<?xml version="1.0" encoding="utf-8" standalone="no"?>
<device schemaVersion="1.1" xmlns:xs="http://www.w3.org/2001/XMLSchema-instance" noNamespaceSchemaLocation="CMSIS-SVD.xsd">
  <vendor>PUYA Co.Ltd</vendor>
  <vendorID>PUYA</vendorID>
  <name>PY32F420xx</name>
  <series>ARMCM4</series>
  <version>1.2</version>
  <cpu>
    <name>CM4</name>
    <revision>r0p1</revision>
    <endian>little</endian>
    <mpuPresent>true</mpuPresent>
    <fpuPresent>true</fpuPresent>
    <nvicPrioBits>4</nvicPrioBits>
    <vendorSystickConfig>false</vendorSystickConfig>
  </cpu>
  <addressUnitBits>8</addressUnitBits>
  <width>32</width>
  <size>32</size>
  <access>read-write</access>
  <resetValue>0x0</resetValue>
  <resetMask>0xFFFFFFFF</resetMask>
  <peripherals>
    <peripheral>
      <name>ADC1</name>
      <groupName>ADC</groupName>
      <baseAddress>0x40012400</baseAddress>
      <addressBlock>
        <offset>0x0</offset>
        <size>0x310</size>
        <usage>registers</usage>
      </addressBlock>
      <interrupt>
        <name>ADC1</name>
        <description>ADC1 global Interrupt</description>
        <value>18</value>
      </interrupt>
      <registers>
        <register>
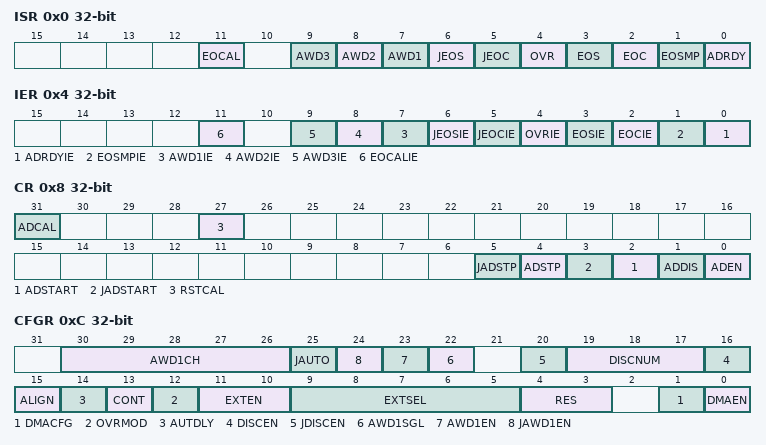
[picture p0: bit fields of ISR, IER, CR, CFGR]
          <name>ISR</name>
          <addressOffset>0x0</addressOffset>
          <fields>
            <field>
              <name>ADRDY</name>
              <bitRange>[0:0]</bitRange>
            </field>
            <field>
              <name>EOSMP</name>
              <bitRange>[1:1]</bitRange>
            </field>
            <field>
              <name>EOC</name>
              <bitRange>[2:2]</bitRange>
            </field>
            <field>
              <name>EOS</name>
              <bitRange>[3:3]</bitRange>
            </field>
            <field>
              <name>OVR</name>
              <bitRange>[4:4]</bitRange>
            </field>
            <field>
              <name>JEOC</name>
              <bitRange>[5:5]</bitRange>
            </field>
            <field>
              <name>JEOS</name>
              <bitRange>[6:6]</bitRange>
            </field>
            <field>
              <name>AWD1</name>
              <bitRange>[7:7]</bitRange>
            </field>
            <field>
              <name>AWD2</name>
              <bitRange>[8:8]</bitRange>
            </field>
            <field>
              <name>AWD3</name>
              <bitRange>[9:9]</bitRange>
            </field>
            <field>
              <name>EOCAL</name>
              <bitRange>[11:11]</bitRange>
            </field>
          </fields>
        </register>
        <register>
          <name>IER</name>
          <addressOffset>0x4</addressOffset>
          <fields>
            <field>
              <name>ADRDYIE</name>
              <bitRange>[0:0]</bitRange>
            </field>
            <field>
              <name>EOSMPIE</name>
              <bitRange>[1:1]</bitRange>
            </field>
            <field>
              <name>EOCIE</name>
              <bitRange>[2:2]</bitRange>
            </field>
            <field>
              <name>EOSIE</name>
              <bitRange>[3:3]</bitRange>
            </field>
            <field>
              <name>OVRIE</name>
              <bitRange>[4:4]</bitRange>
            </field>
            <field>
              <name>JEOCIE</name>
              <bitRange>[5:5]</bitRange>
            </field>
            <field>
              <name>JEOSIE</name>
              <bitRange>[6:6]</bitRange>
            </field>
            <field>
              <name>AWD1IE</name>
              <bitRange>[7:7]</bitRange>
            </field>
            <field>
              <name>AWD2IE</name>
              <bitRange>[8:8]</bitRange>
            </field>
            <field>
              <name>AWD3IE</name>
              <bitRange>[9:9]</bitRange>
            </field>
            <field>
              <name>EOCALIE</name>
              <bitRange>[11:11]</bitRange>
            </field>
          </fields>
        </register>
        <register>
          <name>CR</name>
          <addressOffset>0x8</addressOffset>
          <fields>
            <field>
              <name>ADEN</name>
              <bitRange>[0:0]</bitRange>
            </field>
            <field>
              <name>ADDIS</name>
              <bitRange>[1:1]</bitRange>
            </field>
            <field>
              <name>ADSTART</name>
              <bitRange>[2:2]</bitRange>
            </field>
            <field>
              <name>JADSTART</name>
              <bitRange>[3:3]</bitRange>
            </field>
            <field>
              <name>ADSTP</name>
              <bitRange>[4:4]</bitRange>
            </field>
            <field>
              <name>JADSTP</name>
              <bitRange>[5:5]</bitRange>
            </field>
            <field>
              <name>RSTCAL</name>
              <bitRange>[27:27]</bitRange>
            </field>
            <field>
              <name>ADCAL</name>
              <bitRange>[31:31]</bitRange>
            </field>
          </fields>
        </register>
        <register>
          <name>CFGR</name>
          <addressOffset>0xC</addressOffset>
          <fields>
            <field>
              <name>DMAEN</name>
              <bitRange>[0:0]</bitRange>
            </field>
            <field>
              <name>DMACFG</name>
              <bitRange>[1:1]</bitRange>
            </field>
            <field>
              <name>RES</name>
              <bitRange>[4:3]</bitRange>
            </field>
            <field>
              <name>EXTSEL</name>
              <bitRange>[9:5]</bitRange>
            </field>
            <field>
              <name>EXTEN</name>
              <bitRange>[11:10]</bitRange>
            </field>
            <field>
              <name>OVRMOD</name>
              <bitRange>[12:12]</bitRange>
            </field>
            <field>
              <name>CONT</name>
              <bitRange>[13:13]</bitRange>
            </field>
            <field>
              <name>AUTDLY</name>
              <bitRange>[14:14]</bitRange>
            </field>
            <field>
              <name>ALIGN</name>
              <bitRange>[15:15]</bitRange>
            </field>
            <field>
              <name>DISCEN</name>
              <bitRange>[16:16]</bitRange>
            </field>
            <field>
              <name>DISCNUM</name>
              <bitRange>[19:17]</bitRange>
            </field>
            <field>
              <name>JDISCEN</name>
              <bitRange>[20:20]</bitRange>
            </field>
            <field>
              <name>AWD1SGL</name>
              <bitRange>[22:22]</bitRange>
            </field>
            <field>
              <name>AWD1EN</name>
              <bitRange>[23:23]</bitRange>
            </field>
            <field>
              <name>JAWD1EN</name>
              <bitRange>[24:24]</bitRange>
            </field>
            <field>
              <name>JAUTO</name>
              <bitRange>[25:25]</bitRange>
            </field>
            <field>
              <name>AWD1CH</name>
              <bitRange>[30:26]</bitRange>
            </field>
          </fields>
        </register>
        <register>
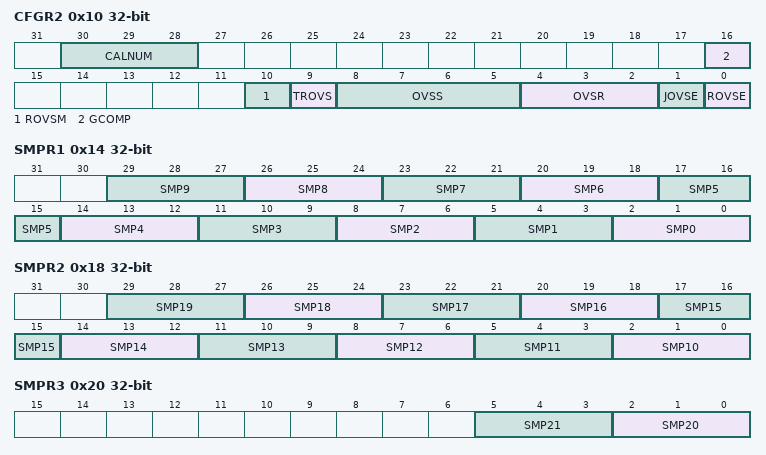
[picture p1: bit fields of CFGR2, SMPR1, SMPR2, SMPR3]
          <name>CFGR2</name>
          <addressOffset>0x10</addressOffset>
          <fields>
            <field>
              <name>ROVSE</name>
              <bitRange>[0:0]</bitRange>
            </field>
            <field>
              <name>JOVSE</name>
              <bitRange>[1:1]</bitRange>
            </field>
            <field>
              <name>OVSR</name>
              <bitRange>[4:2]</bitRange>
            </field>
            <field>
              <name>OVSS</name>
              <bitRange>[8:5]</bitRange>
            </field>
            <field>
              <name>TROVS</name>
              <bitRange>[9:9]</bitRange>
            </field>
            <field>
              <name>ROVSM</name>
              <bitRange>[10:10]</bitRange>
            </field>
            <field>
              <name>GCOMP</name>
              <bitRange>[16:16]</bitRange>
            </field>
            <field>
              <name>CALNUM</name>
              <bitRange>[30:28]</bitRange>
            </field>
          </fields>
        </register>
        <register>
          <name>SMPR1</name>
          <addressOffset>0x14</addressOffset>
          <fields>
            <field>
              <name>SMP0</name>
              <bitRange>[2:0]</bitRange>
            </field>
            <field>
              <name>SMP1</name>
              <bitRange>[5:3]</bitRange>
            </field>
            <field>
              <name>SMP2</name>
              <bitRange>[8:6]</bitRange>
            </field>
            <field>
              <name>SMP3</name>
              <bitRange>[11:9]</bitRange>
            </field>
            <field>
              <name>SMP4</name>
              <bitRange>[14:12]</bitRange>
            </field>
            <field>
              <name>SMP5</name>
              <bitRange>[17:15]</bitRange>
            </field>
            <field>
              <name>SMP6</name>
              <bitRange>[20:18]</bitRange>
            </field>
            <field>
              <name>SMP7</name>
              <bitRange>[23:21]</bitRange>
            </field>
            <field>
              <name>SMP8</name>
              <bitRange>[26:24]</bitRange>
            </field>
            <field>
              <name>SMP9</name>
              <bitRange>[29:27]</bitRange>
            </field>
          </fields>
        </register>
        <register>
          <name>SMPR2</name>
          <addressOffset>0x18</addressOffset>
          <fields>
            <field>
              <name>SMP10</name>
              <bitRange>[2:0]</bitRange>
            </field>
            <field>
              <name>SMP11</name>
              <bitRange>[5:3]</bitRange>
            </field>
            <field>
              <name>SMP12</name>
              <bitRange>[8:6]</bitRange>
            </field>
            <field>
              <name>SMP13</name>
              <bitRange>[11:9]</bitRange>
            </field>
            <field>
              <name>SMP14</name>
              <bitRange>[14:12]</bitRange>
            </field>
            <field>
              <name>SMP15</name>
              <bitRange>[17:15]</bitRange>
            </field>
            <field>
              <name>SMP16</name>
              <bitRange>[20:18]</bitRange>
            </field>
            <field>
              <name>SMP17</name>
              <bitRange>[23:21]</bitRange>
            </field>
            <field>
              <name>SMP18</name>
              <bitRange>[26:24]</bitRange>
            </field>
            <field>
              <name>SMP19</name>
              <bitRange>[29:27]</bitRange>
            </field>
          </fields>
        </register>
        <register>
          <name>SMPR3</name>
          <addressOffset>0x20</addressOffset>
          <fields>
            <field>
              <name>SMP20</name>
              <bitRange>[2:0]</bitRange>
            </field>
            <field>
              <name>SMP21</name>
              <bitRange>[5:3]</bitRange>
            </field>
          </fields>
        </register>
        <register>
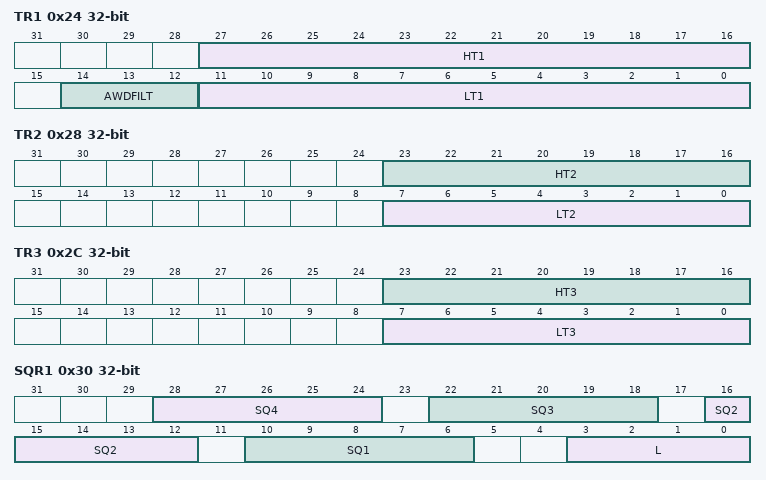
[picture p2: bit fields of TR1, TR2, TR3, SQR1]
          <name>TR1</name>
          <addressOffset>0x24</addressOffset>
          <fields>
            <field>
              <name>LT1</name>
              <bitRange>[11:0]</bitRange>
            </field>
            <field>
              <name>AWDFILT</name>
              <bitRange>[14:12]</bitRange>
            </field>
            <field>
              <name>HT1</name>
              <bitRange>[27:16]</bitRange>
            </field>
          </fields>
        </register>
        <register>
          <name>TR2</name>
          <addressOffset>0x28</addressOffset>
          <fields>
            <field>
              <name>LT2</name>
              <bitRange>[7:0]</bitRange>
            </field>
            <field>
              <name>HT2</name>
              <bitRange>[23:16]</bitRange>
            </field>
          </fields>
        </register>
        <register>
          <name>TR3</name>
          <addressOffset>0x2C</addressOffset>
          <fields>
            <field>
              <name>LT3</name>
              <bitRange>[7:0]</bitRange>
            </field>
            <field>
              <name>HT3</name>
              <bitRange>[23:16]</bitRange>
            </field>
          </fields>
        </register>
        <register>
          <name>SQR1</name>
          <addressOffset>0x30</addressOffset>
          <fields>
            <field>
              <name>L</name>
              <bitRange>[3:0]</bitRange>
            </field>
            <field>
              <name>SQ1</name>
              <bitRange>[10:6]</bitRange>
            </field>
            <field>
              <name>SQ2</name>
              <bitRange>[16:12]</bitRange>
            </field>
            <field>
              <name>SQ3</name>
              <bitRange>[22:18]</bitRange>
            </field>
            <field>
              <name>SQ4</name>
              <bitRange>[28:24]</bitRange>
            </field>
          </fields>
        </register>
        <register>
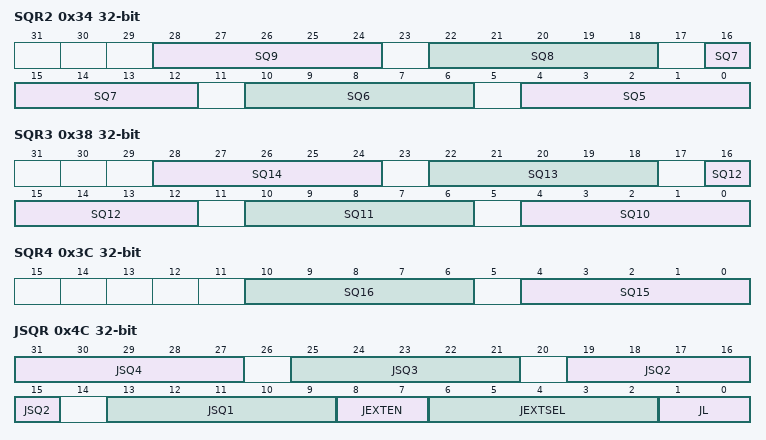
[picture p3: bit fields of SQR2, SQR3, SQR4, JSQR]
          <name>SQR2</name>
          <addressOffset>0x34</addressOffset>
          <fields>
            <field>
              <name>SQ5</name>
              <bitRange>[4:0]</bitRange>
            </field>
            <field>
              <name>SQ6</name>
              <bitRange>[10:6]</bitRange>
            </field>
            <field>
              <name>SQ7</name>
              <bitRange>[16:12]</bitRange>
            </field>
            <field>
              <name>SQ8</name>
              <bitRange>[22:18]</bitRange>
            </field>
            <field>
              <name>SQ9</name>
              <bitRange>[28:24]</bitRange>
            </field>
          </fields>
        </register>
        <register>
          <name>SQR3</name>
          <addressOffset>0x38</addressOffset>
          <fields>
            <field>
              <name>SQ10</name>
              <bitRange>[4:0]</bitRange>
            </field>
            <field>
              <name>SQ11</name>
              <bitRange>[10:6]</bitRange>
            </field>
            <field>
              <name>SQ12</name>
              <bitRange>[16:12]</bitRange>
            </field>
            <field>
              <name>SQ13</name>
              <bitRange>[22:18]</bitRange>
            </field>
            <field>
              <name>SQ14</name>
              <bitRange>[28:24]</bitRange>
            </field>
          </fields>
        </register>
        <register>
          <name>SQR4</name>
          <addressOffset>0x3C</addressOffset>
          <fields>
            <field>
              <name>SQ15</name>
              <bitRange>[4:0]</bitRange>
            </field>
            <field>
              <name>SQ16</name>
              <bitRange>[10:6]</bitRange>
            </field>
          </fields>
        </register>
        <register>
          <name>DR</name>
          <addressOffset>0x40</addressOffset>
          <fields>
            <field>
              <name>RDATA</name>
              <bitRange>[15:0]</bitRange>
              <access>read-only</access>
            </field>
          </fields>
        </register>
        <register>
          <name>JSQR</name>
          <addressOffset>0x4C</addressOffset>
          <fields>
            <field>
              <name>JL</name>
              <bitRange>[1:0]</bitRange>
            </field>
            <field>
              <name>JEXTSEL</name>
              <bitRange>[6:2]</bitRange>
            </field>
            <field>
              <name>JEXTEN</name>
              <bitRange>[8:7]</bitRange>
            </field>
            <field>
              <name>JSQ1</name>
              <bitRange>[13:9]</bitRange>
            </field>
            <field>
              <name>JSQ2</name>
              <bitRange>[19:15]</bitRange>
            </field>
            <field>
              <name>JSQ3</name>
              <bitRange>[25:21]</bitRange>
            </field>
            <field>
              <name>JSQ4</name>
              <bitRange>[31:27]</bitRange>
            </field>
          </fields>
        </register>
        <register>
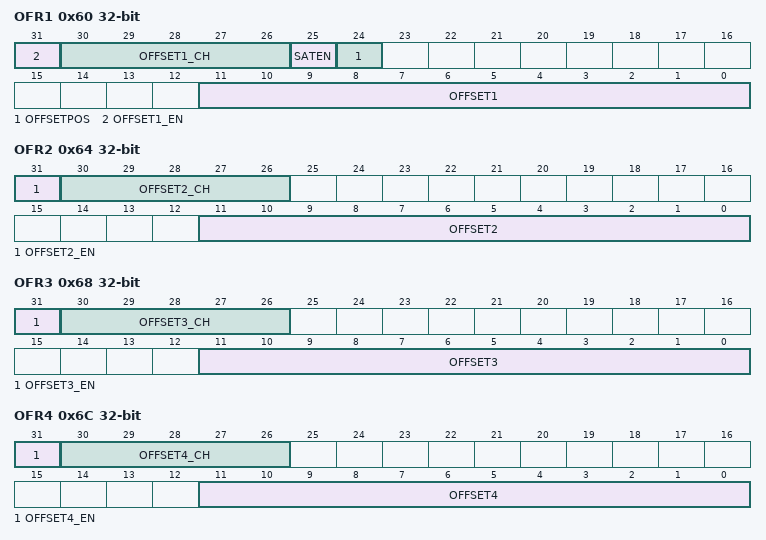
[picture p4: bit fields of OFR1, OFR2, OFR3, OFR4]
          <name>OFR1</name>
          <addressOffset>0x60</addressOffset>
          <fields>
            <field>
              <name>OFFSET1</name>
              <bitRange>[11:0]</bitRange>
            </field>
            <field>
              <name>OFFSETPOS</name>
              <bitRange>[24:24]</bitRange>
            </field>
            <field>
              <name>SATEN</name>
              <bitRange>[25:25]</bitRange>
            </field>
            <field>
              <name>OFFSET1_CH</name>
              <bitRange>[30:26]</bitRange>
            </field>
            <field>
              <name>OFFSET1_EN</name>
              <bitRange>[31:31]</bitRange>
            </field>
          </fields>
        </register>
        <register>
          <name>OFR2</name>
          <addressOffset>0x64</addressOffset>
          <fields>
            <field>
              <name>OFFSET2</name>
              <bitRange>[11:0]</bitRange>
            </field>
            <field>
              <name>OFFSET2_CH</name>
              <bitRange>[30:26]</bitRange>
            </field>
            <field>
              <name>OFFSET2_EN</name>
              <bitRange>[31:31]</bitRange>
            </field>
          </fields>
        </register>
        <register>
          <name>OFR3</name>
          <addressOffset>0x68</addressOffset>
          <fields>
            <field>
              <name>OFFSET3</name>
              <bitRange>[11:0]</bitRange>
            </field>
            <field>
              <name>OFFSET3_CH</name>
              <bitRange>[30:26]</bitRange>
            </field>
            <field>
              <name>OFFSET3_EN</name>
              <bitRange>[31:31]</bitRange>
            </field>
          </fields>
        </register>
        <register>
          <name>OFR4</name>
          <addressOffset>0x6C</addressOffset>
          <fields>
            <field>
              <name>OFFSET4</name>
              <bitRange>[11:0]</bitRange>
            </field>
            <field>
              <name>OFFSET4_CH</name>
              <bitRange>[30:26]</bitRange>
            </field>
            <field>
              <name>OFFSET4_EN</name>
              <bitRange>[31:31]</bitRange>
            </field>
          </fields>
        </register>
        <register>
          <name>JDR1</name>
          <addressOffset>0x80</addressOffset>
          <fields>
            <field>
              <name>JDATA</name>
              <bitRange>[15:0]</bitRange>
              <access>read-only</access>
            </field>
          </fields>
        </register>
        <register>
          <name>JDR2</name>
          <addressOffset>0x84</addressOffset>
          <fields>
            <field>
              <name>JDATA</name>
              <bitRange>[15:0]</bitRange>
              <access>read-only</access>
            </field>
          </fields>
        </register>
        <register>
          <name>JDR3</name>
          <addressOffset>0x88</addressOffset>
          <fields>
            <field>
              <name>JDATA</name>
              <bitRange>[15:0]</bitRange>
              <access>read-only</access>
            </field>
          </fields>
        </register>
        <register>
          <name>JDR4</name>
          <addressOffset>0x8C</addressOffset>
          <fields>
            <field>
              <name>JDATA</name>
              <bitRange>[15:0]</bitRange>
              <access>read-only</access>
            </field>
          </fields>
        </register>
        <register>
          <name>AWD2CR</name>
          <addressOffset>0xA0</addressOffset>
          <fields>
            <field>
              <name>AWD2CH</name>
              <bitRange>[21:0]</bitRange>
            </field>
          </fields>
        </register>
        <register>
          <name>AWD3CR</name>
          <addressOffset>0xA4</addressOffset>
          <fields>
            <field>
              <name>AWD3CH</name>
              <bitRange>[21:0]</bitRange>
            </field>
          </fields>
        </register>
        <register>
          <name>DIFSEL</name>
          <addressOffset>0xB0</addressOffset>
          <fields>
            <field>
              <name>DIFSEL</name>
              <bitRange>[21:0]</bitRange>
            </field>
          </fields>
        </register>
        <register>
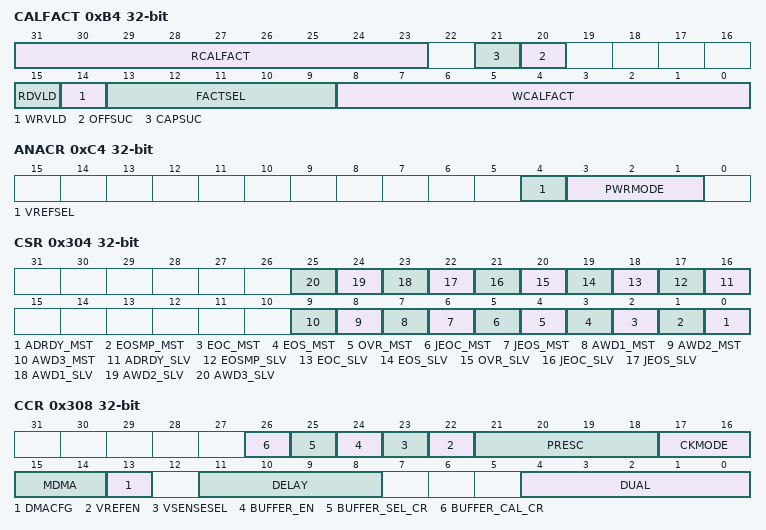
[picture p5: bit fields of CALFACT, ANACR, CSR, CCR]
          <name>CALFACT</name>
          <addressOffset>0xB4</addressOffset>
          <fields>
            <field>
              <name>WCALFACT</name>
              <bitRange>[8:0]</bitRange>
            </field>
            <field>
              <name>FACTSEL</name>
              <bitRange>[13:9]</bitRange>
            </field>
            <field>
              <name>WRVLD</name>
              <bitRange>[14:14]</bitRange>
            </field>
            <field>
              <name>RDVLD</name>
              <bitRange>[15:15]</bitRange>
            </field>
            <field>
              <name>OFFSUC</name>
              <bitRange>[20:20]</bitRange>
            </field>
            <field>
              <name>CAPSUC</name>
              <bitRange>[21:21]</bitRange>
            </field>
            <field>
              <name>RCALFACT</name>
              <bitRange>[31:23]</bitRange>
              <access>read-only</access>
            </field>
          </fields>
        </register>
        <register>
          <name>GCOMP</name>
          <addressOffset>0xC0</addressOffset>
          <fields>
            <field>
              <name>GCOMPCOEFF</name>
              <bitRange>[13:0]</bitRange>
            </field>
          </fields>
        </register>
        <register>
          <name>ANACR</name>
          <addressOffset>0xC4</addressOffset>
          <fields>
            <field>
              <name>PWRMODE</name>
              <bitRange>[3:1]</bitRange>
            </field>
            <field>
              <name>VREFSEL</name>
              <bitRange>[4:4]</bitRange>
            </field>
          </fields>
        </register>
        <register>
          <name>CSR</name>
          <addressOffset>0x304</addressOffset>
          <fields>
            <field>
              <name>ADRDY_MST</name>
              <bitRange>[0:0]</bitRange>
              <access>read-only</access>
            </field>
            <field>
              <name>EOSMP_MST</name>
              <bitRange>[1:1]</bitRange>
              <access>read-only</access>
            </field>
            <field>
              <name>EOC_MST</name>
              <bitRange>[2:2]</bitRange>
              <access>read-only</access>
            </field>
            <field>
              <name>EOS_MST</name>
              <bitRange>[3:3]</bitRange>
              <access>read-only</access>
            </field>
            <field>
              <name>OVR_MST</name>
              <bitRange>[4:4]</bitRange>
              <access>read-only</access>
            </field>
            <field>
              <name>JEOC_MST</name>
              <bitRange>[5:5]</bitRange>
              <access>read-only</access>
            </field>
            <field>
              <name>JEOS_MST</name>
              <bitRange>[6:6]</bitRange>
              <access>read-only</access>
            </field>
            <field>
              <name>AWD1_MST</name>
              <bitRange>[7:7]</bitRange>
              <access>read-only</access>
            </field>
            <field>
              <name>AWD2_MST</name>
              <bitRange>[8:8]</bitRange>
              <access>read-only</access>
            </field>
            <field>
              <name>AWD3_MST</name>
              <bitRange>[9:9]</bitRange>
              <access>read-only</access>
            </field>
            <field>
              <name>ADRDY_SLV</name>
              <bitRange>[16:16]</bitRange>
              <access>read-only</access>
            </field>
            <field>
              <name>EOSMP_SLV</name>
              <bitRange>[17:17]</bitRange>
              <access>read-only</access>
            </field>
            <field>
              <name>EOC_SLV</name>
              <bitRange>[18:18]</bitRange>
              <access>read-only</access>
            </field>
            <field>
              <name>EOS_SLV</name>
              <bitRange>[19:19]</bitRange>
              <access>read-only</access>
            </field>
            <field>
              <name>OVR_SLV</name>
              <bitRange>[20:20]</bitRange>
              <access>read-only</access>
            </field>
            <field>
              <name>JEOC_SLV</name>
              <bitRange>[21:21]</bitRange>
              <access>read-only</access>
            </field>
            <field>
              <name>JEOS_SLV</name>
              <bitRange>[22:22]</bitRange>
              <access>read-only</access>
            </field>
            <field>
              <name>AWD1_SLV</name>
              <bitRange>[23:23]</bitRange>
              <access>read-only</access>
            </field>
            <field>
              <name>AWD2_SLV</name>
              <bitRange>[24:24]</bitRange>
              <access>read-only</access>
            </field>
            <field>
              <name>AWD3_SLV</name>
              <bitRange>[25:25]</bitRange>
              <access>read-only</access>
            </field>
          </fields>
        </register>
        <register>
          <name>CCR</name>
          <addressOffset>0x308</addressOffset>
          <fields>
            <field>
              <name>DUAL</name>
              <bitRange>[4:0]</bitRange>
            </field>
            <field>
              <name>DELAY</name>
              <bitRange>[11:8]</bitRange>
            </field>
            <field>
              <name>DMACFG</name>
              <bitRange>[13:13]</bitRange>
            </field>
            <field>
              <name>MDMA</name>
              <bitRange>[15:14]</bitRange>
            </field>
            <field>
              <name>CKMODE</name>
              <bitRange>[17:16]</bitRange>
            </field>
            <field>
              <name>PRESC</name>
              <bitRange>[21:18]</bitRange>
            </field>
            <field>
              <name>VREFEN</name>
              <bitRange>[22:22]</bitRange>
            </field>
            <field>
              <name>VSENSESEL</name>
              <bitRange>[23:23]</bitRange>
            </field>
            <field>
              <name>BUFFER_EN</name>
              <bitRange>[24:24]</bitRange>
            </field>
            <field>
              <name>BUFFER_SEL_CR</name>
              <bitRange>[25:25]</bitRange>
            </field>
            <field>
              <name>BUFFER_CAL_CR</name>
              <bitRange>[26:26]</bitRange>
            </field>
          </fields>
        </register>
        <register>
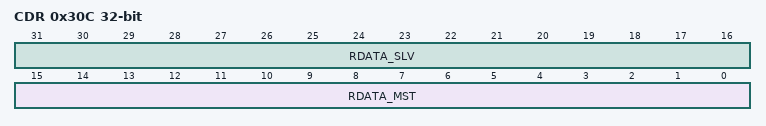
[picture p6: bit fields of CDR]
          <name>CDR</name>
          <addressOffset>0x30C</addressOffset>
          <fields>
            <field>
              <name>RDATA_MST</name>
              <bitRange>[15:0]</bitRange>
              <access>read-only</access>
            </field>
            <field>
              <name>RDATA_SLV</name>
              <bitRange>[31:16]</bitRange>
              <access>read-only</access>
            </field>
          </fields>
        </register>
      </registers>
    </peripheral>
    <peripheral derivedFrom="ADC1">
      <name>ADC2</name>
      <baseAddress>0x40012800</baseAddress>
      <interrupt>
        <name>ADC2</name>
        <description>ADC2 global Interrupt</description>
        <value>19</value>
      </interrupt>
    </peripheral>
    <peripheral>
      <name>COMP1</name>
      <groupName>COMP</groupName>
      <baseAddress>0x40016C00</baseAddress>
      <addressBlock>
        <offset>0x0</offset>
        <size>0x10</size>
        <usage>registers</usage>
      </addressBlock>
      <interrupt>
        <name>COMP1</name>
        <description>COMP1 global Interrupt</description>
        <value>47</value>
      </interrupt>
      <registers>
        <register>
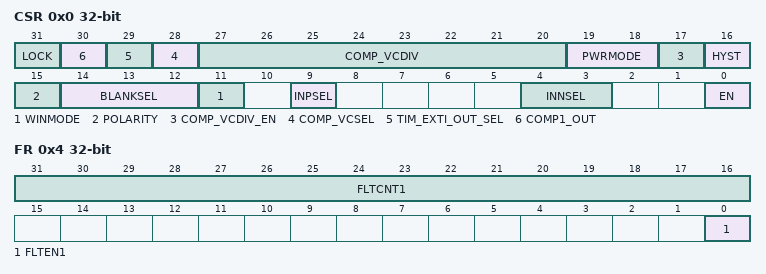
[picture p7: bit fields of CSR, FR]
          <name>CSR</name>
          <addressOffset>0x0</addressOffset>
          <fields>
            <field>
              <name>EN</name>
              <bitRange>[0:0]</bitRange>
            </field>
            <field>
              <name>INNSEL</name>
              <bitRange>[4:3]</bitRange>
            </field>
            <field>
              <name>INPSEL</name>
              <bitRange>[9:9]</bitRange>
            </field>
            <field>
              <name>WINMODE</name>
              <bitRange>[11:11]</bitRange>
            </field>
            <field>
              <name>BLANKSEL</name>
              <bitRange>[14:12]</bitRange>
            </field>
            <field>
              <name>POLARITY</name>
              <bitRange>[15:15]</bitRange>
            </field>
            <field>
              <name>HYST</name>
              <bitRange>[16:16]</bitRange>
            </field>
            <field>
              <name>COMP_VCDIV_EN</name>
              <bitRange>[17:17]</bitRange>
            </field>
            <field>
              <name>PWRMODE</name>
              <bitRange>[19:18]</bitRange>
            </field>
            <field>
              <name>COMP_VCDIV</name>
              <bitRange>[27:20]</bitRange>
            </field>
            <field>
              <name>COMP_VCSEL</name>
              <bitRange>[28:28]</bitRange>
            </field>
            <field>
              <name>TIM_EXTI_OUT_SEL</name>
              <bitRange>[29:29]</bitRange>
            </field>
            <field>
              <name>COMP1_OUT</name>
              <bitRange>[30:30]</bitRange>
              <access>read-only</access>
            </field>
            <field>
              <name>LOCK</name>
              <bitRange>[31:31]</bitRange>
            </field>
          </fields>
        </register>
        <register>
          <name>FR</name>
          <addressOffset>0x4</addressOffset>
          <fields>
            <field>
              <name>FLTEN1</name>
              <bitRange>[0:0]</bitRange>
            </field>
            <field>
              <name>FLTCNT1</name>
              <bitRange>[31:16]</bitRange>
            </field>
          </fields>
        </register>
      </registers>
    </peripheral>
    <peripheral derivedFrom="COMP1">
      <name>COMP2</name>
      <baseAddress>0x40016C10</baseAddress>
      <interrupt>
        <name>COMP2</name>
        <description>COMP2 global Interrupt</description>
        <value>48</value>
      </interrupt>
    </peripheral>
    <peripheral derivedFrom="COMP1">
      <name>COMP3</name>
      <baseAddress>0x40016C20</baseAddress>
      <interrupt>
        <name>COMP3</name>
        <description>COMP3 global Interrupt</description>
        <value>49</value>
      </interrupt>
    </peripheral>
    <peripheral derivedFrom="COMP1">
      <name>COMP4</name>
      <baseAddress>0x40016C30</baseAddress>
      <interrupt>
        <name>COMP4</name>
        <description>COMP4 global Interrupt</description>
        <value>50</value>
      </interrupt>
    </peripheral>
    <peripheral>
      <name>CRC</name>
      <baseAddress>0x40023000</baseAddress>
      <addressBlock>
        <offset>0x0</offset>
        <size>0x10</size>
        <usage>registers</usage>
      </addressBlock>
      <registers>
        <register>
          <name>DR</name>
          <addressOffset>0x0</addressOffset>
          <fields>
            <field>
              <name>DR</name>
              <description>CRC data</description>
              <bitRange>[31:0]</bitRange>
            </field>
          </fields>
        </register>
        <register>
          <name>IDR</name>
          <addressOffset>0x4</addressOffset>
          <fields>
            <field>
              <name>IDR</name>
              <description>CRC independent data</description>
              <bitRange>[7:0]</bitRange>
            </field>
          </fields>
        </register>
        <register>
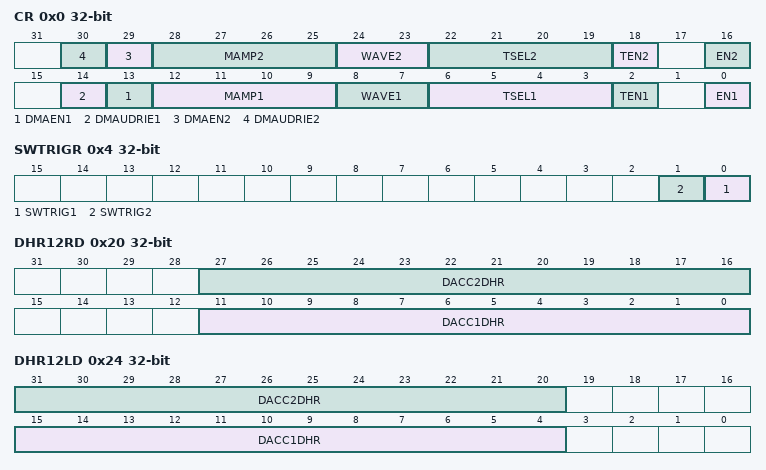
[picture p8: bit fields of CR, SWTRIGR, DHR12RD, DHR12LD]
          <name>CR</name>
          <addressOffset>0x8</addressOffset>
          <fields>
            <field>
              <name>RESET</name>
              <description>CRC software reset</description>
              <bitRange>[0:0]</bitRange>
            </field>
          </fields>
        </register>
      </registers>
    </peripheral>
    <peripheral>
      <name>DAC</name>
      <baseAddress>0x40007400</baseAddress>
      <addressBlock>
        <offset>0x0</offset>
        <size>0x70</size>
        <usage>registers</usage>
      </addressBlock>
      <interrupt>
        <name>DAC</name>
        <description>DAC global Interrupt</description>
        <value>20</value>
      </interrupt>
      <registers>
        <register>
          <name>CR</name>
          <addressOffset>0x0</addressOffset>
          <fields>
            <field>
              <name>EN1</name>
              <bitRange>[0:0]</bitRange>
            </field>
            <field>
              <name>TEN1</name>
              <bitRange>[2:2]</bitRange>
            </field>
            <field>
              <name>TSEL1</name>
              <bitRange>[6:3]</bitRange>
            </field>
            <field>
              <name>WAVE1</name>
              <bitRange>[8:7]</bitRange>
            </field>
            <field>
              <name>MAMP1</name>
              <bitRange>[12:9]</bitRange>
            </field>
            <field>
              <name>DMAEN1</name>
              <bitRange>[13:13]</bitRange>
            </field>
            <field>
              <name>DMAUDRIE1</name>
              <bitRange>[14:14]</bitRange>
            </field>
            <field>
              <name>EN2</name>
              <bitRange>[16:16]</bitRange>
            </field>
            <field>
              <name>TEN2</name>
              <bitRange>[18:18]</bitRange>
            </field>
            <field>
              <name>TSEL2</name>
              <bitRange>[22:19]</bitRange>
            </field>
            <field>
              <name>WAVE2</name>
              <bitRange>[24:23]</bitRange>
            </field>
            <field>
              <name>MAMP2</name>
              <bitRange>[28:25]</bitRange>
            </field>
            <field>
              <name>DMAEN2</name>
              <bitRange>[29:29]</bitRange>
            </field>
            <field>
              <name>DMAUDRIE2</name>
              <bitRange>[30:30]</bitRange>
            </field>
          </fields>
        </register>
        <register>
          <name>SWTRIGR</name>
          <addressOffset>0x4</addressOffset>
          <fields>
            <field>
              <name>SWTRIG1</name>
              <bitRange>[0:0]</bitRange>
              <access>write-only</access>
            </field>
            <field>
              <name>SWTRIG2</name>
              <bitRange>[1:1]</bitRange>
              <access>write-only</access>
            </field>
          </fields>
        </register>
        <register>
          <name>DHR12R1</name>
          <addressOffset>0x8</addressOffset>
          <fields>
            <field>
              <name>DACC1DHR</name>
              <bitRange>[11:0]</bitRange>
            </field>
          </fields>
        </register>
        <register>
          <name>DHR12L1</name>
          <addressOffset>0xC</addressOffset>
          <fields>
            <field>
              <name>DACC1DHR</name>
              <bitRange>[15:4]</bitRange>
            </field>
          </fields>
        </register>
        <register>
          <name>DHR8R1</name>
          <addressOffset>0x10</addressOffset>
          <fields>
            <field>
              <name>DACC1DHR</name>
              <bitRange>[7:0]</bitRange>
            </field>
          </fields>
        </register>
        <register>
          <name>DHR12R2</name>
          <addressOffset>0x14</addressOffset>
          <fields>
            <field>
              <name>DACC2DHR</name>
              <bitRange>[11:0]</bitRange>
            </field>
          </fields>
        </register>
        <register>
          <name>DHR12L2</name>
          <addressOffset>0x18</addressOffset>
          <fields>
            <field>
              <name>DACC2DHR</name>
              <bitRange>[15:4]</bitRange>
            </field>
          </fields>
        </register>
        <register>
          <name>DHR8R2</name>
          <addressOffset>0x1C</addressOffset>
          <fields>
            <field>
              <name>DACC2DHR</name>
              <bitRange>[7:0]</bitRange>
            </field>
          </fields>
        </register>
        <register>
          <name>DHR12RD</name>
          <addressOffset>0x20</addressOffset>
          <fields>
            <field>
              <name>DACC1DHR</name>
              <bitRange>[11:0]</bitRange>
            </field>
            <field>
              <name>DACC2DHR</name>
              <bitRange>[27:16]</bitRange>
            </field>
          </fields>
        </register>
        <register>
          <name>DHR12LD</name>
          <addressOffset>0x24</addressOffset>
          <fields>
            <field>
              <name>DACC1DHR</name>
              <bitRange>[15:4]</bitRange>
            </field>
            <field>
              <name>DACC2DHR</name>
              <bitRange>[31:20]</bitRange>
            </field>
          </fields>
        </register>
        <register>
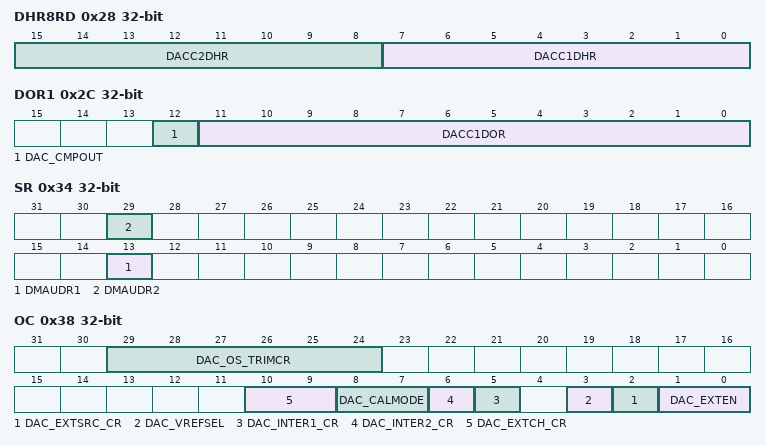
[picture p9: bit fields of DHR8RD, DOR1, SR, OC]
          <name>DHR8RD</name>
          <addressOffset>0x28</addressOffset>
          <fields>
            <field>
              <name>DACC1DHR</name>
              <bitRange>[7:0]</bitRange>
            </field>
            <field>
              <name>DACC2DHR</name>
              <bitRange>[15:8]</bitRange>
            </field>
          </fields>
        </register>
        <register>
          <name>DOR1</name>
          <addressOffset>0x2C</addressOffset>
          <fields>
            <field>
              <name>DACC1DOR</name>
              <bitRange>[11:0]</bitRange>
              <access>read-only</access>
            </field>
            <field>
              <name>DAC_CMPOUT</name>
              <bitRange>[12:12]</bitRange>
              <access>read-only</access>
            </field>
          </fields>
        </register>
        <register>
          <name>DOR2</name>
          <addressOffset>0x30</addressOffset>
          <fields>
            <field>
              <name>DACC2DOR</name>
              <bitRange>[11:0]</bitRange>
              <access>read-only</access>
            </field>
          </fields>
        </register>
        <register>
          <name>SR</name>
          <addressOffset>0x34</addressOffset>
          <fields>
            <field>
              <name>DMAUDR1</name>
              <bitRange>[13:13]</bitRange>
            </field>
            <field>
              <name>DMAUDR2</name>
              <bitRange>[29:29]</bitRange>
            </field>
          </fields>
        </register>
        <register>
          <name>OC</name>
          <addressOffset>0x38</addressOffset>
          <fields>
            <field>
              <name>DAC_EXTEN</name>
              <bitRange>[1:0]</bitRange>
            </field>
            <field>
              <name>DAC_EXTSRC_CR</name>
              <bitRange>[2:2]</bitRange>
            </field>
            <field>
              <name>DAC_VREFSEL</name>
              <bitRange>[3:3]</bitRange>
            </field>
            <field>
              <name>DAC_INTER1_CR</name>
              <bitRange>[5:5]</bitRange>
            </field>
            <field>
              <name>DAC_INTER2_CR</name>
              <bitRange>[6:6]</bitRange>
            </field>
            <field>
              <name>DAC_CALMODE</name>
              <bitRange>[8:7]</bitRange>
            </field>
            <field>
              <name>DAC_EXTCH_CR</name>
              <bitRange>[10:9]</bitRange>
            </field>
            <field>
              <name>DAC_OS_TRIMCR</name>
              <bitRange>[29:24]</bitRange>
            </field>
          </fields>
        </register>
        <register>
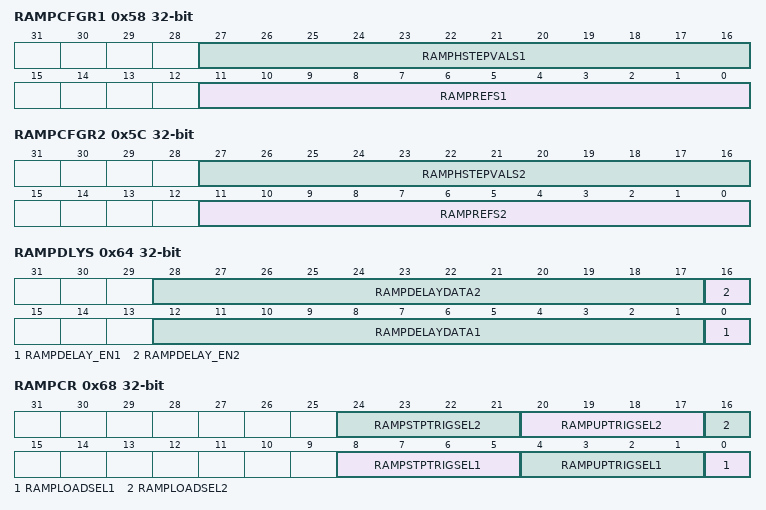
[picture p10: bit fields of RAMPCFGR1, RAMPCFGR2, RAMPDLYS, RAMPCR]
          <name>RAMPCFGR1</name>
          <addressOffset>0x58</addressOffset>
          <fields>
            <field>
              <name>RAMPREFS1</name>
              <bitRange>[11:0]</bitRange>
            </field>
            <field>
              <name>RAMPHSTEPVALS1</name>
              <bitRange>[27:16]</bitRange>
            </field>
          </fields>
        </register>
        <register>
          <name>RAMPCFGR2</name>
          <addressOffset>0x5C</addressOffset>
          <fields>
            <field>
              <name>RAMPREFS2</name>
              <bitRange>[11:0]</bitRange>
            </field>
            <field>
              <name>RAMPHSTEPVALS2</name>
              <bitRange>[27:16]</bitRange>
            </field>
          </fields>
        </register>
        <register>
          <name>RAMPDLYS</name>
          <addressOffset>0x64</addressOffset>
          <fields>
            <field>
              <name>RAMPDELAY_EN1</name>
              <bitRange>[0:0]</bitRange>
            </field>
            <field>
              <name>RAMPDELAYDATA1</name>
              <bitRange>[12:1]</bitRange>
            </field>
            <field>
              <name>RAMPDELAY_EN2</name>
              <bitRange>[16:16]</bitRange>
            </field>
            <field>
              <name>RAMPDELAYDATA2</name>
              <bitRange>[28:17]</bitRange>
            </field>
          </fields>
        </register>
        <register>
          <name>RAMPCR</name>
          <addressOffset>0x68</addressOffset>
          <fields>
            <field>
              <name>RAMPLOADSEL1</name>
              <bitRange>[0:0]</bitRange>
            </field>
            <field>
              <name>RAMPUPTRIGSEL1</name>
              <bitRange>[4:1]</bitRange>
            </field>
            <field>
              <name>RAMPSTPTRIGSEL1</name>
              <bitRange>[8:5]</bitRange>
            </field>
            <field>
              <name>RAMPLOADSEL2</name>
              <bitRange>[16:16]</bitRange>
            </field>
            <field>
              <name>RAMPUPTRIGSEL2</name>
              <bitRange>[20:17]</bitRange>
            </field>
            <field>
              <name>RAMPSTPTRIGSEL2</name>
              <bitRange>[24:21]</bitRange>
            </field>
          </fields>
        </register>
      </registers>
    </peripheral>
    <peripheral>
      <name>DBGMCU</name>
      <baseAddress>0xE0042000</baseAddress>
      <addressBlock>
        <offset>0x0</offset>
        <size>0x10</size>
        <usage>registers</usage>
      </addressBlock>
      <registers>
        <register>
          <name>IDCODE</name>
          <addressOffset>0x0</addressOffset>
          <fields>
            <field>
              <name>REV_ID</name>
              <bitRange>[31:0]</bitRange>
              <access>read-only</access>
            </field>
          </fields>
        </register>
        <register>
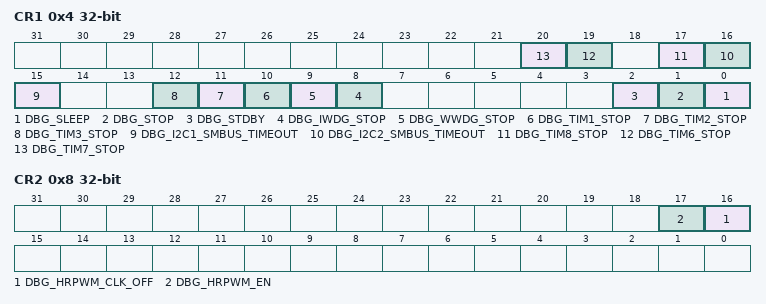
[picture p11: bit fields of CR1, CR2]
          <name>CR1</name>
          <addressOffset>0x4</addressOffset>
          <fields>
            <field>
              <name>DBG_SLEEP</name>
              <bitRange>[0:0]</bitRange>
            </field>
            <field>
              <name>DBG_STOP</name>
              <bitRange>[1:1]</bitRange>
            </field>
            <field>
              <name>DBG_STDBY</name>
              <bitRange>[2:2]</bitRange>
            </field>
            <field>
              <name>DBG_IWDG_STOP</name>
              <bitRange>[8:8]</bitRange>
            </field>
            <field>
              <name>DBG_WWDG_STOP</name>
              <bitRange>[9:9]</bitRange>
            </field>
            <field>
              <name>DBG_TIM1_STOP</name>
              <bitRange>[10:10]</bitRange>
            </field>
            <field>
              <name>DBG_TIM2_STOP</name>
              <bitRange>[11:11]</bitRange>
            </field>
            <field>
              <name>DBG_TIM3_STOP</name>
              <bitRange>[12:12]</bitRange>
            </field>
            <field>
              <name>DBG_I2C1_SMBUS_TIMEOUT</name>
              <bitRange>[15:15]</bitRange>
            </field>
            <field>
              <name>DBG_I2C2_SMBUS_TIMEOUT</name>
              <bitRange>[16:16]</bitRange>
            </field>
            <field>
              <name>DBG_TIM8_STOP</name>
              <bitRange>[17:17]</bitRange>
            </field>
            <field>
              <name>DBG_TIM6_STOP</name>
              <bitRange>[19:19]</bitRange>
            </field>
            <field>
              <name>DBG_TIM7_STOP</name>
              <bitRange>[20:20]</bitRange>
            </field>
          </fields>
        </register>
        <register>
          <name>CR2</name>
          <addressOffset>0x8</addressOffset>
          <fields>
            <field>
              <name>DBG_HRPWM_CLK_OFF</name>
              <bitRange>[16:16]</bitRange>
            </field>
            <field>
              <name>DBG_HRPWM_EN</name>
              <bitRange>[17:17]</bitRange>
            </field>
          </fields>
        </register>
      </registers>
    </peripheral>
    <peripheral>
      <name>DMA</name>
      <baseAddress>0x40020000</baseAddress>
      <addressBlock>
        <offset>0x0</offset>
        <size>0xB0</size>
        <usage>registers</usage>
      </addressBlock>
      <interrupt>
        <name>DMA1_MAP1</name>
        <description>DMA1_MAP1 global Interrupt</description>
        <value>13</value>
      </interrupt>
      <interrupt>
        <name>DMA1_MAP2</name>
        <description>DMA1_MAP2 global Interrupt</description>
        <value>14</value>
      </interrupt>
      <interrupt>
        <name>DMA1_MAP3</name>
        <description>DMA1_MAP3 global Interrupt</description>
        <value>15</value>
      </interrupt>
      <interrupt>
        <name>DMA1_MAP4</name>
        <description>DMA1_MAP4 global Interrupt</description>
        <value>16</value>
      </interrupt>
      <interrupt>
        <name>DMA1_MAP5</name>
        <description>DMA1_MAP5 global Interrupt</description>
        <value>17</value>
      </interrupt>
      <registers>
        <register>
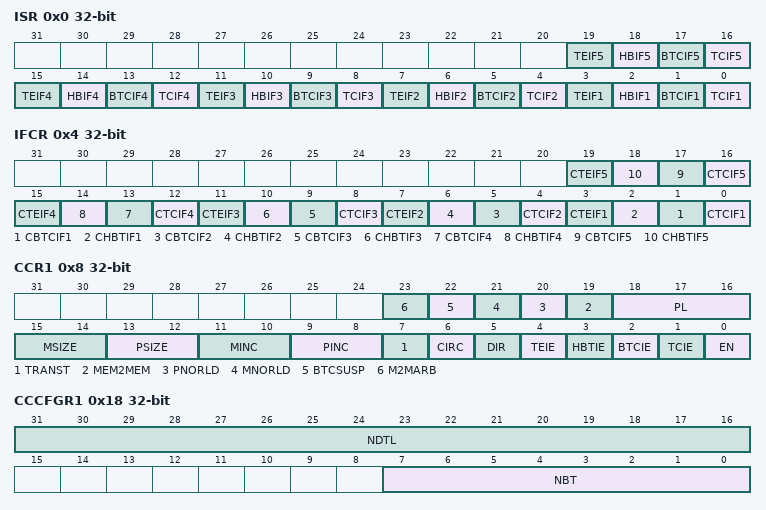
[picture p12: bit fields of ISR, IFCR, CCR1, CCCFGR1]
          <name>ISR</name>
          <addressOffset>0x0</addressOffset>
          <fields>
            <field>
              <name>TCIF1</name>
              <bitRange>[0:0]</bitRange>
              <access>read-only</access>
            </field>
            <field>
              <name>BTCIF1</name>
              <bitRange>[1:1]</bitRange>
              <access>read-only</access>
            </field>
            <field>
              <name>HBIF1</name>
              <bitRange>[2:2]</bitRange>
              <access>read-only</access>
            </field>
            <field>
              <name>TEIF1</name>
              <bitRange>[3:3]</bitRange>
              <access>read-only</access>
            </field>
            <field>
              <name>TCIF2</name>
              <bitRange>[4:4]</bitRange>
              <access>read-only</access>
            </field>
            <field>
              <name>BTCIF2</name>
              <bitRange>[5:5]</bitRange>
              <access>read-only</access>
            </field>
            <field>
              <name>HBIF2</name>
              <bitRange>[6:6]</bitRange>
              <access>read-only</access>
            </field>
            <field>
              <name>TEIF2</name>
              <bitRange>[7:7]</bitRange>
              <access>read-only</access>
            </field>
            <field>
              <name>TCIF3</name>
              <bitRange>[8:8]</bitRange>
              <access>read-only</access>
            </field>
            <field>
              <name>BTCIF3</name>
              <bitRange>[9:9]</bitRange>
              <access>read-only</access>
            </field>
            <field>
              <name>HBIF3</name>
              <bitRange>[10:10]</bitRange>
              <access>read-only</access>
            </field>
            <field>
              <name>TEIF3</name>
              <bitRange>[11:11]</bitRange>
              <access>read-only</access>
            </field>
            <field>
              <name>TCIF4</name>
              <bitRange>[12:12]</bitRange>
              <access>read-only</access>
            </field>
            <field>
              <name>BTCIF4</name>
              <bitRange>[13:13]</bitRange>
              <access>read-only</access>
            </field>
            <field>
              <name>HBIF4</name>
              <bitRange>[14:14]</bitRange>
              <access>read-only</access>
            </field>
            <field>
              <name>TEIF4</name>
              <bitRange>[15:15]</bitRange>
              <access>read-only</access>
            </field>
            <field>
              <name>TCIF5</name>
              <bitRange>[16:16]</bitRange>
              <access>read-only</access>
            </field>
            <field>
              <name>BTCIF5</name>
              <bitRange>[17:17]</bitRange>
              <access>read-only</access>
            </field>
            <field>
              <name>HBIF5</name>
              <bitRange>[18:18]</bitRange>
              <access>read-only</access>
            </field>
            <field>
              <name>TEIF5</name>
              <bitRange>[19:19]</bitRange>
              <access>read-only</access>
            </field>
          </fields>
        </register>
        <register>
          <name>IFCR</name>
          <addressOffset>0x4</addressOffset>
          <fields>
            <field>
              <name>CTCIF1</name>
              <bitRange>[0:0]</bitRange>
              <access>write-only</access>
            </field>
            <field>
              <name>CBTCIF1</name>
              <bitRange>[1:1]</bitRange>
              <access>write-only</access>
            </field>
            <field>
              <name>CHBTIF1</name>
              <bitRange>[2:2]</bitRange>
              <access>write-only</access>
            </field>
            <field>
              <name>CTEIF1</name>
              <bitRange>[3:3]</bitRange>
              <access>write-only</access>
            </field>
            <field>
              <name>CTCIF2</name>
              <bitRange>[4:4]</bitRange>
              <access>write-only</access>
            </field>
            <field>
              <name>CBTCIF2</name>
              <bitRange>[5:5]</bitRange>
              <access>write-only</access>
            </field>
            <field>
              <name>CHBTIF2</name>
              <bitRange>[6:6]</bitRange>
              <access>write-only</access>
            </field>
            <field>
              <name>CTEIF2</name>
              <bitRange>[7:7]</bitRange>
              <access>write-only</access>
            </field>
            <field>
              <name>CTCIF3</name>
              <bitRange>[8:8]</bitRange>
              <access>write-only</access>
            </field>
            <field>
              <name>CBTCIF3</name>
              <bitRange>[9:9]</bitRange>
              <access>write-only</access>
            </field>
            <field>
              <name>CHBTIF3</name>
              <bitRange>[10:10]</bitRange>
              <access>write-only</access>
            </field>
            <field>
              <name>CTEIF3</name>
              <bitRange>[11:11]</bitRange>
              <access>write-only</access>
            </field>
            <field>
              <name>CTCIF4</name>
              <bitRange>[12:12]</bitRange>
              <access>write-only</access>
            </field>
            <field>
              <name>CBTCIF4</name>
              <bitRange>[13:13]</bitRange>
              <access>write-only</access>
            </field>
            <field>
              <name>CHBTIF4</name>
              <bitRange>[14:14]</bitRange>
              <access>write-only</access>
            </field>
            <field>
              <name>CTEIF4</name>
              <bitRange>[15:15]</bitRange>
              <access>write-only</access>
            </field>
            <field>
              <name>CTCIF5</name>
              <bitRange>[16:16]</bitRange>
              <access>write-only</access>
            </field>
            <field>
              <name>CBTCIF5</name>
              <bitRange>[17:17]</bitRange>
              <access>write-only</access>
            </field>
            <field>
              <name>CHBTIF5</name>
              <bitRange>[18:18]</bitRange>
              <access>write-only</access>
            </field>
            <field>
              <name>CTEIF5</name>
              <bitRange>[19:19]</bitRange>
              <access>write-only</access>
            </field>
          </fields>
        </register>
        <register>
          <name>CCR1</name>
          <addressOffset>0x8</addressOffset>
          <fields>
            <field>
              <name>EN</name>
              <bitRange>[0:0]</bitRange>
            </field>
            <field>
              <name>TCIE</name>
              <bitRange>[1:1]</bitRange>
            </field>
            <field>
              <name>BTCIE</name>
              <bitRange>[2:2]</bitRange>
            </field>
            <field>
              <name>HBTIE</name>
              <bitRange>[3:3]</bitRange>
            </field>
            <field>
              <name>TEIE</name>
              <bitRange>[4:4]</bitRange>
            </field>
            <field>
              <name>DIR</name>
              <bitRange>[5:5]</bitRange>
            </field>
            <field>
              <name>CIRC</name>
              <bitRange>[6:6]</bitRange>
            </field>
            <field>
              <name>TRANST</name>
              <bitRange>[7:7]</bitRange>
            </field>
            <field>
              <name>PINC</name>
              <bitRange>[9:8]</bitRange>
            </field>
            <field>
              <name>MINC</name>
              <bitRange>[11:10]</bitRange>
            </field>
            <field>
              <name>PSIZE</name>
              <bitRange>[13:12]</bitRange>
            </field>
            <field>
              <name>MSIZE</name>
              <bitRange>[15:14]</bitRange>
            </field>
            <field>
              <name>PL</name>
              <bitRange>[18:16]</bitRange>
            </field>
            <field>
              <name>MEM2MEM</name>
              <bitRange>[19:19]</bitRange>
            </field>
            <field>
              <name>PNORLD</name>
              <bitRange>[20:20]</bitRange>
            </field>
            <field>
              <name>MNORLD</name>
              <bitRange>[21:21]</bitRange>
            </field>
            <field>
              <name>BTCSUSP</name>
              <bitRange>[22:22]</bitRange>
            </field>
            <field>
              <name>M2MARB</name>
              <bitRange>[23:23]</bitRange>
            </field>
          </fields>
        </register>
        <register>
          <name>CNDTR1</name>
          <addressOffset>0xC</addressOffset>
          <fields>
            <field>
              <name>NDT</name>
              <bitRange>[15:0]</bitRange>
            </field>
          </fields>
        </register>
        <register>
          <name>CPAR1</name>
          <addressOffset>0x10</addressOffset>
          <fields>
            <field>
              <name>PA</name>
              <bitRange>[31:0]</bitRange>
            </field>
          </fields>
        </register>
        <register>
          <name>CMAR1</name>
          <addressOffset>0x14</addressOffset>
          <fields>
            <field>
              <name>MA</name>
              <bitRange>[31:0]</bitRange>
            </field>
          </fields>
        </register>
        <register>
          <name>CCCFGR1</name>
          <addressOffset>0x18</addressOffset>
          <fields>
            <field>
              <name>NBT</name>
              <bitRange>[7:0]</bitRange>
            </field>
            <field>
              <name>NDTL</name>
              <bitRange>[31:16]</bitRange>
            </field>
          </fields>
        </register>
        <register>
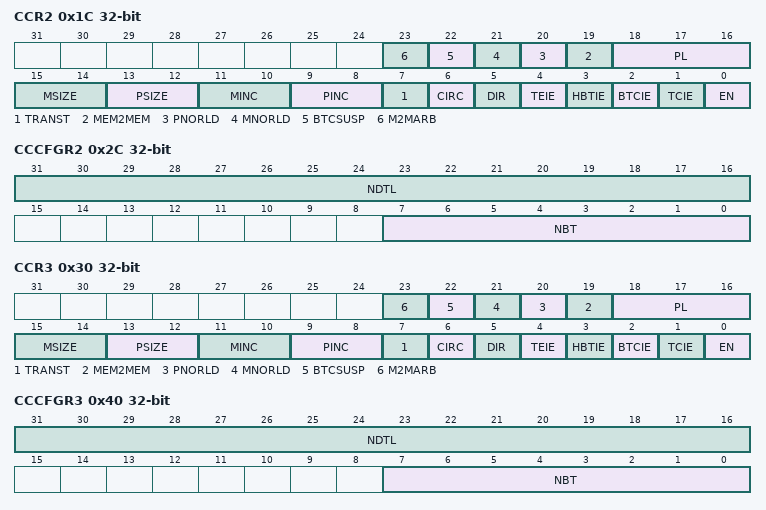
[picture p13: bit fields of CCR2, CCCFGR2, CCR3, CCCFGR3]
          <name>CCR2</name>
          <addressOffset>0x1C</addressOffset>
          <fields>
            <field>
              <name>EN</name>
              <bitRange>[0:0]</bitRange>
            </field>
            <field>
              <name>TCIE</name>
              <bitRange>[1:1]</bitRange>
            </field>
            <field>
              <name>BTCIE</name>
              <bitRange>[2:2]</bitRange>
            </field>
            <field>
              <name>HBTIE</name>
              <bitRange>[3:3]</bitRange>
            </field>
            <field>
              <name>TEIE</name>
              <bitRange>[4:4]</bitRange>
            </field>
            <field>
              <name>DIR</name>
              <bitRange>[5:5]</bitRange>
            </field>
            <field>
              <name>CIRC</name>
              <bitRange>[6:6]</bitRange>
            </field>
            <field>
              <name>TRANST</name>
              <bitRange>[7:7]</bitRange>
            </field>
            <field>
              <name>PINC</name>
              <bitRange>[9:8]</bitRange>
            </field>
            <field>
              <name>MINC</name>
              <bitRange>[11:10]</bitRange>
            </field>
            <field>
              <name>PSIZE</name>
              <bitRange>[13:12]</bitRange>
            </field>
            <field>
              <name>MSIZE</name>
              <bitRange>[15:14]</bitRange>
            </field>
            <field>
              <name>PL</name>
              <bitRange>[18:16]</bitRange>
            </field>
            <field>
              <name>MEM2MEM</name>
              <bitRange>[19:19]</bitRange>
            </field>
            <field>
              <name>PNORLD</name>
              <bitRange>[20:20]</bitRange>
            </field>
            <field>
              <name>MNORLD</name>
              <bitRange>[21:21]</bitRange>
            </field>
            <field>
              <name>BTCSUSP</name>
              <bitRange>[22:22]</bitRange>
            </field>
            <field>
              <name>M2MARB</name>
              <bitRange>[23:23]</bitRange>
            </field>
          </fields>
        </register>
        <register>
          <name>CNDTR2</name>
          <addressOffset>0x20</addressOffset>
          <fields>
            <field>
              <name>NDT</name>
              <bitRange>[15:0]</bitRange>
            </field>
          </fields>
        </register>
        <register>
          <name>CPAR2</name>
          <addressOffset>0x24</addressOffset>
          <fields>
            <field>
              <name>PA</name>
              <bitRange>[31:0]</bitRange>
            </field>
          </fields>
        </register>
        <register>
          <name>CMAR2</name>
          <addressOffset>0x28</addressOffset>
          <fields>
            <field>
              <name>MA</name>
              <bitRange>[31:0]</bitRange>
            </field>
          </fields>
        </register>
        <register>
          <name>CCCFGR2</name>
          <addressOffset>0x2C</addressOffset>
          <fields>
            <field>
              <name>NBT</name>
              <bitRange>[7:0]</bitRange>
            </field>
            <field>
              <name>NDTL</name>
              <bitRange>[31:16]</bitRange>
            </field>
          </fields>
        </register>
        <register>
          <name>CCR3</name>
          <addressOffset>0x30</addressOffset>
          <fields>
            <field>
              <name>EN</name>
              <bitRange>[0:0]</bitRange>
            </field>
            <field>
              <name>TCIE</name>
              <bitRange>[1:1]</bitRange>
            </field>
            <field>
              <name>BTCIE</name>
              <bitRange>[2:2]</bitRange>
            </field>
            <field>
              <name>HBTIE</name>
              <bitRange>[3:3]</bitRange>
            </field>
            <field>
              <name>TEIE</name>
              <bitRange>[4:4]</bitRange>
            </field>
            <field>
              <name>DIR</name>
              <bitRange>[5:5]</bitRange>
            </field>
            <field>
              <name>CIRC</name>
              <bitRange>[6:6]</bitRange>
            </field>
            <field>
              <name>TRANST</name>
              <bitRange>[7:7]</bitRange>
            </field>
            <field>
              <name>PINC</name>
              <bitRange>[9:8]</bitRange>
            </field>
            <field>
              <name>MINC</name>
              <bitRange>[11:10]</bitRange>
            </field>
            <field>
              <name>PSIZE</name>
              <bitRange>[13:12]</bitRange>
            </field>
            <field>
              <name>MSIZE</name>
              <bitRange>[15:14]</bitRange>
            </field>
            <field>
              <name>PL</name>
              <bitRange>[18:16]</bitRange>
            </field>
            <field>
              <name>MEM2MEM</name>
              <bitRange>[19:19]</bitRange>
            </field>
            <field>
              <name>PNORLD</name>
              <bitRange>[20:20]</bitRange>
            </field>
            <field>
              <name>MNORLD</name>
              <bitRange>[21:21]</bitRange>
            </field>
            <field>
              <name>BTCSUSP</name>
              <bitRange>[22:22]</bitRange>
            </field>
            <field>
              <name>M2MARB</name>
              <bitRange>[23:23]</bitRange>
            </field>
          </fields>
        </register>
        <register>
          <name>CNDTR3</name>
          <addressOffset>0x34</addressOffset>
          <fields>
            <field>
              <name>NDT</name>
              <bitRange>[15:0]</bitRange>
            </field>
          </fields>
        </register>
        <register>
          <name>CPAR3</name>
          <addressOffset>0x38</addressOffset>
          <fields>
            <field>
              <name>PA</name>
              <bitRange>[31:0]</bitRange>
            </field>
          </fields>
        </register>
        <register>
          <name>CMAR3</name>
          <addressOffset>0x3C</addressOffset>
          <fields>
            <field>
              <name>MA</name>
              <bitRange>[31:0]</bitRange>
            </field>
          </fields>
        </register>
        <register>
          <name>CCCFGR3</name>
          <addressOffset>0x40</addressOffset>
          <fields>
            <field>
              <name>NBT</name>
              <bitRange>[7:0]</bitRange>
            </field>
            <field>
              <name>NDTL</name>
              <bitRange>[31:16]</bitRange>
            </field>
          </fields>
        </register>
        <register>
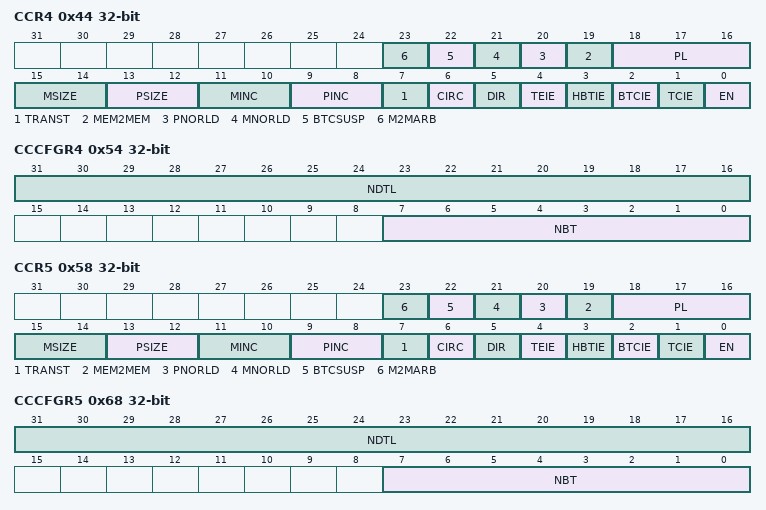
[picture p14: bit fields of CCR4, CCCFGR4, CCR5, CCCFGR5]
          <name>CCR4</name>
          <addressOffset>0x44</addressOffset>
          <fields>
            <field>
              <name>EN</name>
              <bitRange>[0:0]</bitRange>
            </field>
            <field>
              <name>TCIE</name>
              <bitRange>[1:1]</bitRange>
            </field>
            <field>
              <name>BTCIE</name>
              <bitRange>[2:2]</bitRange>
            </field>
            <field>
              <name>HBTIE</name>
              <bitRange>[3:3]</bitRange>
            </field>
            <field>
              <name>TEIE</name>
              <bitRange>[4:4]</bitRange>
            </field>
            <field>
              <name>DIR</name>
              <bitRange>[5:5]</bitRange>
            </field>
            <field>
              <name>CIRC</name>
              <bitRange>[6:6]</bitRange>
            </field>
            <field>
              <name>TRANST</name>
              <bitRange>[7:7]</bitRange>
            </field>
            <field>
              <name>PINC</name>
              <bitRange>[9:8]</bitRange>
            </field>
            <field>
              <name>MINC</name>
              <bitRange>[11:10]</bitRange>
            </field>
            <field>
              <name>PSIZE</name>
              <bitRange>[13:12]</bitRange>
            </field>
            <field>
              <name>MSIZE</name>
              <bitRange>[15:14]</bitRange>
            </field>
            <field>
              <name>PL</name>
              <bitRange>[18:16]</bitRange>
            </field>
            <field>
              <name>MEM2MEM</name>
              <bitRange>[19:19]</bitRange>
            </field>
            <field>
              <name>PNORLD</name>
              <bitRange>[20:20]</bitRange>
            </field>
            <field>
              <name>MNORLD</name>
              <bitRange>[21:21]</bitRange>
            </field>
            <field>
              <name>BTCSUSP</name>
              <bitRange>[22:22]</bitRange>
            </field>
            <field>
              <name>M2MARB</name>
              <bitRange>[23:23]</bitRange>
            </field>
          </fields>
        </register>
        <register>
          <name>CNDTR4</name>
          <addressOffset>0x48</addressOffset>
          <fields>
            <field>
              <name>NDT</name>
              <bitRange>[15:0]</bitRange>
            </field>
          </fields>
        </register>
        <register>
          <name>CPAR4</name>
          <addressOffset>0x4C</addressOffset>
          <fields>
            <field>
              <name>PA</name>
              <bitRange>[31:0]</bitRange>
            </field>
          </fields>
        </register>
        <register>
          <name>CMAR4</name>
          <addressOffset>0x50</addressOffset>
          <fields>
            <field>
              <name>MA</name>
              <bitRange>[31:0]</bitRange>
            </field>
          </fields>
        </register>
        <register>
          <name>CCCFGR4</name>
          <addressOffset>0x54</addressOffset>
          <fields>
            <field>
              <name>NBT</name>
              <bitRange>[7:0]</bitRange>
            </field>
            <field>
              <name>NDTL</name>
              <bitRange>[31:16]</bitRange>
            </field>
          </fields>
        </register>
        <register>
          <name>CCR5</name>
          <addressOffset>0x58</addressOffset>
          <fields>
            <field>
              <name>EN</name>
              <bitRange>[0:0]</bitRange>
            </field>
            <field>
              <name>TCIE</name>
              <bitRange>[1:1]</bitRange>
            </field>
            <field>
              <name>BTCIE</name>
              <bitRange>[2:2]</bitRange>
            </field>
            <field>
              <name>HBTIE</name>
              <bitRange>[3:3]</bitRange>
            </field>
            <field>
              <name>TEIE</name>
              <bitRange>[4:4]</bitRange>
            </field>
            <field>
              <name>DIR</name>
              <bitRange>[5:5]</bitRange>
            </field>
            <field>
              <name>CIRC</name>
              <bitRange>[6:6]</bitRange>
            </field>
            <field>
              <name>TRANST</name>
              <bitRange>[7:7]</bitRange>
            </field>
            <field>
              <name>PINC</name>
              <bitRange>[9:8]</bitRange>
            </field>
            <field>
              <name>MINC</name>
              <bitRange>[11:10]</bitRange>
            </field>
            <field>
              <name>PSIZE</name>
              <bitRange>[13:12]</bitRange>
            </field>
            <field>
              <name>MSIZE</name>
              <bitRange>[15:14]</bitRange>
            </field>
            <field>
              <name>PL</name>
              <bitRange>[18:16]</bitRange>
            </field>
            <field>
              <name>MEM2MEM</name>
              <bitRange>[19:19]</bitRange>
            </field>
            <field>
              <name>PNORLD</name>
              <bitRange>[20:20]</bitRange>
            </field>
            <field>
              <name>MNORLD</name>
              <bitRange>[21:21]</bitRange>
            </field>
            <field>
              <name>BTCSUSP</name>
              <bitRange>[22:22]</bitRange>
            </field>
            <field>
              <name>M2MARB</name>
              <bitRange>[23:23]</bitRange>
            </field>
          </fields>
        </register>
        <register>
          <name>CNDTR5</name>
          <addressOffset>0x5C</addressOffset>
          <fields>
            <field>
              <name>NDT</name>
              <bitRange>[15:0]</bitRange>
            </field>
          </fields>
        </register>
        <register>
          <name>CPAR5</name>
          <addressOffset>0x60</addressOffset>
          <fields>
            <field>
              <name>PA</name>
              <bitRange>[31:0]</bitRange>
            </field>
          </fields>
        </register>
        <register>
          <name>CMAR5</name>
          <addressOffset>0x64</addressOffset>
          <fields>
            <field>
              <name>MA</name>
              <bitRange>[31:0]</bitRange>
            </field>
          </fields>
        </register>
        <register>
          <name>CCCFGR5</name>
          <addressOffset>0x68</addressOffset>
          <fields>
            <field>
              <name>NBT</name>
              <bitRange>[7:0]</bitRange>
            </field>
            <field>
              <name>NDTL</name>
              <bitRange>[31:16]</bitRange>
            </field>
          </fields>
        </register>
      </registers>
    </peripheral>
    <peripheral>
      <name>EXTI</name>
      <baseAddress>0x40010400</baseAddress>
      <addressBlock>
        <offset>0x0</offset>
        <size>0x20</size>
        <usage>registers</usage>
      </addressBlock>
      <interrupt>
        <name>PVD</name>
        <description>PVD through EXTI Line detection Interrupt</description>
        <value>1</value>
      </interrupt>
      <interrupt>
        <name>EXTI0</name>
        <description>EXTI Line0 interrupt</description>
        <value>6</value>
      </interrupt>
      <interrupt>
        <name>EXTI1</name>
        <description>EXTI Line1 interrupt</description>
        <value>7</value>
      </interrupt>
      <interrupt>
        <name>EXTI2</name>
        <description>EXTI Line2 interrupt</description>
        <value>8</value>
      </interrupt>
      <interrupt>
        <name>EXTI3</name>
        <description>EXTI Line3 interrupt</description>
        <value>9</value>
      </interrupt>
      <interrupt>
        <name>EXTI4</name>
        <description>EXTI Line4 interrupt</description>
        <value>10</value>
      </interrupt>
      <interrupt>
        <name>EXTI9_5</name>
        <description>EXTI Line[9:5] interrupt</description>
        <value>11</value>
      </interrupt>
      <interrupt>
        <name>EXTI15_10</name>
        <description>EXTI Line[15:10] interrupt</description>
        <value>12</value>
      </interrupt>
      <interrupt>
        <name>RTC_ALR</name>
        <description>RTC_ALR through EXTI Line detection Interrupt</description>
        <value>40</value>
      </interrupt>
      <registers>
        <register>
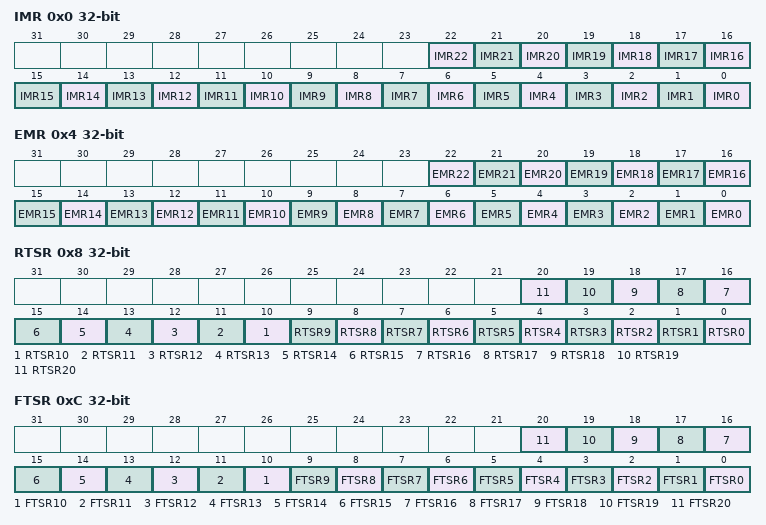
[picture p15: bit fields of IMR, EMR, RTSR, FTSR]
          <name>IMR</name>
          <addressOffset>0x0</addressOffset>
          <fields>
            <field>
              <name>IMR0</name>
              <bitRange>[0:0]</bitRange>
            </field>
            <field>
              <name>IMR1</name>
              <bitRange>[1:1]</bitRange>
            </field>
            <field>
              <name>IMR2</name>
              <bitRange>[2:2]</bitRange>
            </field>
            <field>
              <name>IMR3</name>
              <bitRange>[3:3]</bitRange>
            </field>
            <field>
              <name>IMR4</name>
              <bitRange>[4:4]</bitRange>
            </field>
            <field>
              <name>IMR5</name>
              <bitRange>[5:5]</bitRange>
            </field>
            <field>
              <name>IMR6</name>
              <bitRange>[6:6]</bitRange>
            </field>
            <field>
              <name>IMR7</name>
              <bitRange>[7:7]</bitRange>
            </field>
            <field>
              <name>IMR8</name>
              <bitRange>[8:8]</bitRange>
            </field>
            <field>
              <name>IMR9</name>
              <bitRange>[9:9]</bitRange>
            </field>
            <field>
              <name>IMR10</name>
              <bitRange>[10:10]</bitRange>
            </field>
            <field>
              <name>IMR11</name>
              <bitRange>[11:11]</bitRange>
            </field>
            <field>
              <name>IMR12</name>
              <bitRange>[12:12]</bitRange>
            </field>
            <field>
              <name>IMR13</name>
              <bitRange>[13:13]</bitRange>
            </field>
            <field>
              <name>IMR14</name>
              <bitRange>[14:14]</bitRange>
            </field>
            <field>
              <name>IMR15</name>
              <bitRange>[15:15]</bitRange>
            </field>
            <field>
              <name>IMR16</name>
              <bitRange>[16:16]</bitRange>
            </field>
            <field>
              <name>IMR17</name>
              <bitRange>[17:17]</bitRange>
            </field>
            <field>
              <name>IMR18</name>
              <bitRange>[18:18]</bitRange>
            </field>
            <field>
              <name>IMR19</name>
              <bitRange>[19:19]</bitRange>
            </field>
            <field>
              <name>IMR20</name>
              <bitRange>[20:20]</bitRange>
            </field>
            <field>
              <name>IMR21</name>
              <bitRange>[21:21]</bitRange>
            </field>
            <field>
              <name>IMR22</name>
              <bitRange>[22:22]</bitRange>
            </field>
          </fields>
        </register>
        <register>
          <name>EMR</name>
          <addressOffset>0x4</addressOffset>
          <fields>
            <field>
              <name>EMR0</name>
              <bitRange>[0:0]</bitRange>
            </field>
            <field>
              <name>EMR1</name>
              <bitRange>[1:1]</bitRange>
            </field>
            <field>
              <name>EMR2</name>
              <bitRange>[2:2]</bitRange>
            </field>
            <field>
              <name>EMR3</name>
              <bitRange>[3:3]</bitRange>
            </field>
            <field>
              <name>EMR4</name>
              <bitRange>[4:4]</bitRange>
            </field>
            <field>
              <name>EMR5</name>
              <bitRange>[5:5]</bitRange>
            </field>
            <field>
              <name>EMR6</name>
              <bitRange>[6:6]</bitRange>
            </field>
            <field>
              <name>EMR7</name>
              <bitRange>[7:7]</bitRange>
            </field>
            <field>
              <name>EMR8</name>
              <bitRange>[8:8]</bitRange>
            </field>
            <field>
              <name>EMR9</name>
              <bitRange>[9:9]</bitRange>
            </field>
            <field>
              <name>EMR10</name>
              <bitRange>[10:10]</bitRange>
            </field>
            <field>
              <name>EMR11</name>
              <bitRange>[11:11]</bitRange>
            </field>
            <field>
              <name>EMR12</name>
              <bitRange>[12:12]</bitRange>
            </field>
            <field>
              <name>EMR13</name>
              <bitRange>[13:13]</bitRange>
            </field>
            <field>
              <name>EMR14</name>
              <bitRange>[14:14]</bitRange>
            </field>
            <field>
              <name>EMR15</name>
              <bitRange>[15:15]</bitRange>
            </field>
            <field>
              <name>EMR16</name>
              <bitRange>[16:16]</bitRange>
            </field>
            <field>
              <name>EMR17</name>
              <bitRange>[17:17]</bitRange>
            </field>
            <field>
              <name>EMR18</name>
              <bitRange>[18:18]</bitRange>
            </field>
            <field>
              <name>EMR19</name>
              <bitRange>[19:19]</bitRange>
            </field>
            <field>
              <name>EMR20</name>
              <bitRange>[20:20]</bitRange>
            </field>
            <field>
              <name>EMR21</name>
              <bitRange>[21:21]</bitRange>
            </field>
            <field>
              <name>EMR22</name>
              <bitRange>[22:22]</bitRange>
            </field>
          </fields>
        </register>
        <register>
          <name>RTSR</name>
          <addressOffset>0x8</addressOffset>
          <fields>
            <field>
              <name>RTSR0</name>
              <bitRange>[0:0]</bitRange>
            </field>
            <field>
              <name>RTSR1</name>
              <bitRange>[1:1]</bitRange>
            </field>
            <field>
              <name>RTSR2</name>
              <bitRange>[2:2]</bitRange>
            </field>
            <field>
              <name>RTSR3</name>
              <bitRange>[3:3]</bitRange>
            </field>
            <field>
              <name>RTSR4</name>
              <bitRange>[4:4]</bitRange>
            </field>
            <field>
              <name>RTSR5</name>
              <bitRange>[5:5]</bitRange>
            </field>
            <field>
              <name>RTSR6</name>
              <bitRange>[6:6]</bitRange>
            </field>
            <field>
              <name>RTSR7</name>
              <bitRange>[7:7]</bitRange>
            </field>
            <field>
              <name>RTSR8</name>
              <bitRange>[8:8]</bitRange>
            </field>
            <field>
              <name>RTSR9</name>
              <bitRange>[9:9]</bitRange>
            </field>
            <field>
              <name>RTSR10</name>
              <bitRange>[10:10]</bitRange>
            </field>
            <field>
              <name>RTSR11</name>
              <bitRange>[11:11]</bitRange>
            </field>
            <field>
              <name>RTSR12</name>
              <bitRange>[12:12]</bitRange>
            </field>
            <field>
              <name>RTSR13</name>
              <bitRange>[13:13]</bitRange>
            </field>
            <field>
              <name>RTSR14</name>
              <bitRange>[14:14]</bitRange>
            </field>
            <field>
              <name>RTSR15</name>
              <bitRange>[15:15]</bitRange>
            </field>
            <field>
              <name>RTSR16</name>
              <bitRange>[16:16]</bitRange>
            </field>
            <field>
              <name>RTSR17</name>
              <bitRange>[17:17]</bitRange>
            </field>
            <field>
              <name>RTSR18</name>
              <bitRange>[18:18]</bitRange>
            </field>
            <field>
              <name>RTSR19</name>
              <bitRange>[19:19]</bitRange>
            </field>
            <field>
              <name>RTSR20</name>
              <bitRange>[20:20]</bitRange>
            </field>
          </fields>
        </register>
        <register>
          <name>FTSR</name>
          <addressOffset>0xC</addressOffset>
          <fields>
            <field>
              <name>FTSR0</name>
              <bitRange>[0:0]</bitRange>
            </field>
            <field>
              <name>FTSR1</name>
              <bitRange>[1:1]</bitRange>
            </field>
            <field>
              <name>FTSR2</name>
              <bitRange>[2:2]</bitRange>
            </field>
            <field>
              <name>FTSR3</name>
              <bitRange>[3:3]</bitRange>
            </field>
            <field>
              <name>FTSR4</name>
              <bitRange>[4:4]</bitRange>
            </field>
            <field>
              <name>FTSR5</name>
              <bitRange>[5:5]</bitRange>
            </field>
            <field>
              <name>FTSR6</name>
              <bitRange>[6:6]</bitRange>
            </field>
            <field>
              <name>FTSR7</name>
              <bitRange>[7:7]</bitRange>
            </field>
            <field>
              <name>FTSR8</name>
              <bitRange>[8:8]</bitRange>
            </field>
            <field>
              <name>FTSR9</name>
              <bitRange>[9:9]</bitRange>
            </field>
            <field>
              <name>FTSR10</name>
              <bitRange>[10:10]</bitRange>
            </field>
            <field>
              <name>FTSR11</name>
              <bitRange>[11:11]</bitRange>
            </field>
            <field>
              <name>FTSR12</name>
              <bitRange>[12:12]</bitRange>
            </field>
            <field>
              <name>FTSR13</name>
              <bitRange>[13:13]</bitRange>
            </field>
            <field>
              <name>FTSR14</name>
              <bitRange>[14:14]</bitRange>
            </field>
            <field>
              <name>FTSR15</name>
              <bitRange>[15:15]</bitRange>
            </field>
            <field>
              <name>FTSR16</name>
              <bitRange>[16:16]</bitRange>
            </field>
            <field>
              <name>FTSR17</name>
              <bitRange>[17:17]</bitRange>
            </field>
            <field>
              <name>FTSR18</name>
              <bitRange>[18:18]</bitRange>
            </field>
            <field>
              <name>FTSR19</name>
              <bitRange>[19:19]</bitRange>
            </field>
            <field>
              <name>FTSR20</name>
              <bitRange>[20:20]</bitRange>
            </field>
          </fields>
        </register>
        <register>
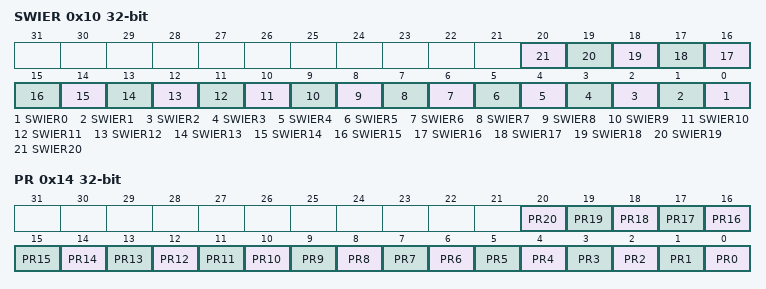
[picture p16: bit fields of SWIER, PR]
          <name>SWIER</name>
          <addressOffset>0x10</addressOffset>
          <fields>
            <field>
              <name>SWIER0</name>
              <bitRange>[0:0]</bitRange>
            </field>
            <field>
              <name>SWIER1</name>
              <bitRange>[1:1]</bitRange>
            </field>
            <field>
              <name>SWIER2</name>
              <bitRange>[2:2]</bitRange>
            </field>
            <field>
              <name>SWIER3</name>
              <bitRange>[3:3]</bitRange>
            </field>
            <field>
              <name>SWIER4</name>
              <bitRange>[4:4]</bitRange>
            </field>
            <field>
              <name>SWIER5</name>
              <bitRange>[5:5]</bitRange>
            </field>
            <field>
              <name>SWIER6</name>
              <bitRange>[6:6]</bitRange>
            </field>
            <field>
              <name>SWIER7</name>
              <bitRange>[7:7]</bitRange>
            </field>
            <field>
              <name>SWIER8</name>
              <bitRange>[8:8]</bitRange>
            </field>
            <field>
              <name>SWIER9</name>
              <bitRange>[9:9]</bitRange>
            </field>
            <field>
              <name>SWIER10</name>
              <bitRange>[10:10]</bitRange>
            </field>
            <field>
              <name>SWIER11</name>
              <bitRange>[11:11]</bitRange>
            </field>
            <field>
              <name>SWIER12</name>
              <bitRange>[12:12]</bitRange>
            </field>
            <field>
              <name>SWIER13</name>
              <bitRange>[13:13]</bitRange>
            </field>
            <field>
              <name>SWIER14</name>
              <bitRange>[14:14]</bitRange>
            </field>
            <field>
              <name>SWIER15</name>
              <bitRange>[15:15]</bitRange>
            </field>
            <field>
              <name>SWIER16</name>
              <bitRange>[16:16]</bitRange>
            </field>
            <field>
              <name>SWIER17</name>
              <bitRange>[17:17]</bitRange>
            </field>
            <field>
              <name>SWIER18</name>
              <bitRange>[18:18]</bitRange>
            </field>
            <field>
              <name>SWIER19</name>
              <bitRange>[19:19]</bitRange>
            </field>
            <field>
              <name>SWIER20</name>
              <bitRange>[20:20]</bitRange>
            </field>
          </fields>
        </register>
        <register>
          <name>PR</name>
          <addressOffset>0x14</addressOffset>
          <fields>
            <field>
              <name>PR0</name>
              <bitRange>[0:0]</bitRange>
            </field>
            <field>
              <name>PR1</name>
              <bitRange>[1:1]</bitRange>
            </field>
            <field>
              <name>PR2</name>
              <bitRange>[2:2]</bitRange>
            </field>
            <field>
              <name>PR3</name>
              <bitRange>[3:3]</bitRange>
            </field>
            <field>
              <name>PR4</name>
              <bitRange>[4:4]</bitRange>
            </field>
            <field>
              <name>PR5</name>
              <bitRange>[5:5]</bitRange>
            </field>
            <field>
              <name>PR6</name>
              <bitRange>[6:6]</bitRange>
            </field>
            <field>
              <name>PR7</name>
              <bitRange>[7:7]</bitRange>
            </field>
            <field>
              <name>PR8</name>
              <bitRange>[8:8]</bitRange>
            </field>
            <field>
              <name>PR9</name>
              <bitRange>[9:9]</bitRange>
            </field>
            <field>
              <name>PR10</name>
              <bitRange>[10:10]</bitRange>
            </field>
            <field>
              <name>PR11</name>
              <bitRange>[11:11]</bitRange>
            </field>
            <field>
              <name>PR12</name>
              <bitRange>[12:12]</bitRange>
            </field>
            <field>
              <name>PR13</name>
              <bitRange>[13:13]</bitRange>
            </field>
            <field>
              <name>PR14</name>
              <bitRange>[14:14]</bitRange>
            </field>
            <field>
              <name>PR15</name>
              <bitRange>[15:15]</bitRange>
            </field>
            <field>
              <name>PR16</name>
              <bitRange>[16:16]</bitRange>
            </field>
            <field>
              <name>PR17</name>
              <bitRange>[17:17]</bitRange>
            </field>
            <field>
              <name>PR18</name>
              <bitRange>[18:18]</bitRange>
            </field>
            <field>
              <name>PR19</name>
              <bitRange>[19:19]</bitRange>
            </field>
            <field>
              <name>PR20</name>
              <bitRange>[20:20]</bitRange>
            </field>
          </fields>
        </register>
      </registers>
    </peripheral>
    <peripheral>
      <name>FDCAN</name>
      <baseAddress>0x4000CC00</baseAddress>
      <addressBlock>
        <offset>0x0</offset>
        <size>0x100</size>
        <usage>registers</usage>
      </addressBlock>
      <interrupt>
        <name>CAN_INT0</name>
        <description>CAN_INT0 global Interrupt</description>
        <value>45</value>
      </interrupt>
      <interrupt>
        <name>CAN_INT1</name>
        <description>CAN_INT1 global Interrupt</description>
        <value>46</value>
      </interrupt>
      <registers>
        <register>
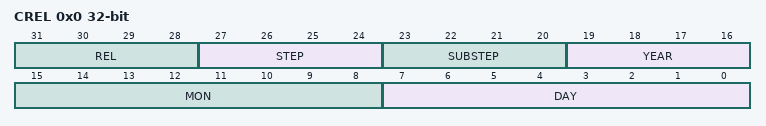
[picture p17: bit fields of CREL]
          <name>CREL</name>
          <addressOffset>0x0</addressOffset>
          <fields>
            <field>
              <name>DAY</name>
              <description>-</description>
              <bitRange>[7:0]</bitRange>
              <access>read-only</access>
            </field>
            <field>
              <name>MON</name>
              <description>-</description>
              <bitRange>[15:8]</bitRange>
              <access>read-only</access>
            </field>
            <field>
              <name>YEAR</name>
              <description>-</description>
              <bitRange>[19:16]</bitRange>
              <access>read-only</access>
            </field>
            <field>
              <name>SUBSTEP</name>
              <description>-</description>
              <bitRange>[23:20]</bitRange>
              <access>read-only</access>
            </field>
            <field>
              <name>STEP</name>
              <description>-</description>
              <bitRange>[27:24]</bitRange>
              <access>read-only</access>
            </field>
            <field>
              <name>REL</name>
              <description>-</description>
              <bitRange>[31:28]</bitRange>
              <access>read-only</access>
            </field>
          </fields>
        </register>
        <register>
          <name>ENDN</name>
          <addressOffset>0x4</addressOffset>
          <fields>
            <field>
              <name>ETV</name>
              <description>Endian Register</description>
              <bitRange>[31:0]</bitRange>
              <access>read-only</access>
            </field>
          </fields>
        </register>
        <register>
          <name>DBTP</name>
          <addressOffset>0xC</addressOffset>
          <fields>
            <field>
              <name>DSJW</name>
              <description>Data (Re)Synchronization Jump Width</description>
              <bitRange>[3:0]</bitRange>
            </field>
            <field>
              <name>DTSEG2</name>
              <description>Data time segment after sample point</description>
              <bitRange>[7:4]</bitRange>
            </field>
            <field>
              <name>DTSEG1</name>
              <description>Data time segment before sample point</description>
              <bitRange>[12:8]</bitRange>
            </field>
            <field>
              <name>DBRP</name>
              <description>Data Bit Rate Prescaler</description>
              <bitRange>[20:16]</bitRange>
            </field>
            <field>
              <name>TDC</name>
              <description>Transmitter Delay Compensation</description>
              <bitRange>[23:23]</bitRange>
            </field>
          </fields>
        </register>
        <register>
          <name>TEST</name>
          <addressOffset>0x10</addressOffset>
          <fields>
            <field>
              <name>LBCK</name>
              <description>Loop Back Mode</description>
              <bitRange>[4:4]</bitRange>
            </field>
            <field>
              <name>TX</name>
              <description>Control of Transmit Pin</description>
              <bitRange>[6:5]</bitRange>
            </field>
            <field>
              <name>RX</name>
              <description>Receive Pin</description>
              <bitRange>[7:7]</bitRange>
            </field>
            <field>
              <name>TXBNP</name>
              <description>Tx Buffer Number Prepared</description>
              <bitRange>[12:8]</bitRange>
            </field>
            <field>
              <name>PVAL</name>
              <description>Prepared Valid</description>
              <bitRange>[13:13]</bitRange>
            </field>
            <field>
              <name>TXBNS</name>
              <description>Tx Buffer Number Started</description>
              <bitRange>[20:16]</bitRange>
            </field>
            <field>
              <name>SVAL</name>
              <description>Started Valid</description>
              <bitRange>[21:21]</bitRange>
            </field>
          </fields>
        </register>
        <register>
          <name>RWD</name>
          <addressOffset>0x14</addressOffset>
          <fields>
            <field>
              <name>WDC</name>
              <description>Watchdog Configuration</description>
              <bitRange>[7:0]</bitRange>
            </field>
            <field>
              <name>WDV</name>
              <description>Watchdog Value</description>
              <bitRange>[15:8]</bitRange>
            </field>
          </fields>
        </register>
        <register>
          <name>CCCR</name>
          <addressOffset>0x18</addressOffset>
          <fields>
            <field>
              <name>INIT</name>
              <description>Initialization</description>
              <bitRange>[0:0]</bitRange>
            </field>
            <field>
              <name>CCE</name>
              <description>Configuration Change Enable</description>
              <bitRange>[1:1]</bitRange>
            </field>
            <field>
              <name>ASM</name>
              <description>Restricted Operation Mode</description>
              <bitRange>[2:2]</bitRange>
            </field>
            <field>
              <name>CSA</name>
              <description>Clock Stop Acknowledge</description>
              <bitRange>[3:3]</bitRange>
            </field>
            <field>
              <name>CSR</name>
              <description>Clock Stop Request</description>
              <bitRange>[4:4]</bitRange>
            </field>
            <field>
              <name>MON</name>
              <description>Bus Monitoring Mode</description>
              <bitRange>[5:5]</bitRange>
            </field>
            <field>
              <name>DAR</name>
              <description>Disable Automatic Retransmission</description>
              <bitRange>[6:6]</bitRange>
            </field>
            <field>
              <name>TEST</name>
              <description>Test Mode Enable</description>
              <bitRange>[7:7]</bitRange>
            </field>
            <field>
              <name>FDOE</name>
              <description>FD Operation Enable</description>
              <bitRange>[8:8]</bitRange>
            </field>
            <field>
              <name>BRSE</name>
              <description>Bit Rate Switch Enable</description>
              <bitRange>[9:9]</bitRange>
            </field>
            <field>
              <name>WMM</name>
              <description>Wide Message Marker</description>
              <bitRange>[11:11]</bitRange>
            </field>
            <field>
              <name>PXHD</name>
              <description>Protocol Exception Handling Disable</description>
              <bitRange>[12:12]</bitRange>
            </field>
            <field>
              <name>EFBI</name>
              <description>Edge Filtering during Bus Integration</description>
              <bitRange>[13:13]</bitRange>
            </field>
            <field>
              <name>TXP</name>
              <description>Transmit Pause</description>
              <bitRange>[14:14]</bitRange>
            </field>
            <field>
              <name>NISO</name>
              <description>Non ISO Operation</description>
              <bitRange>[15:15]</bitRange>
            </field>
          </fields>
        </register>
        <register>
          <name>NBTP</name>
          <addressOffset>0x1C</addressOffset>
          <fields>
            <field>
              <name>NTSEG2</name>
              <description>Nominal Time segment after sample point</description>
              <bitRange>[6:0]</bitRange>
              <access>read-only</access>
            </field>
            <field>
              <name>NTSEG1</name>
              <description>Nominal Time segment before sample point</description>
              <bitRange>[15:8]</bitRange>
              <access>read-only</access>
            </field>
            <field>
              <name>NBRP</name>
              <description>Nominal Bit Rate Prescaler</description>
              <bitRange>[24:16]</bitRange>
              <access>read-only</access>
            </field>
            <field>
              <name>NSJW</name>
              <description>Nominal (Re)Synchronization Jump Width</description>
              <bitRange>[31:25]</bitRange>
              <access>read-only</access>
            </field>
          </fields>
        </register>
        <register>
          <name>TSCC</name>
          <addressOffset>0x20</addressOffset>
          <fields>
            <field>
              <name>TSS</name>
              <description>Timestamp Select</description>
              <bitRange>[1:0]</bitRange>
            </field>
            <field>
              <name>TCP</name>
              <description>Timestamp Counter Prescaler</description>
              <bitRange>[19:16]</bitRange>
            </field>
          </fields>
        </register>
        <register>
          <name>TSCV</name>
          <addressOffset>0x24</addressOffset>
          <fields>
            <field>
              <name>TSC</name>
              <description>Timestamp Counter</description>
              <bitRange>[15:0]</bitRange>
            </field>
          </fields>
        </register>
        <register>
          <name>TOCC</name>
          <addressOffset>0x28</addressOffset>
          <fields>
            <field>
              <name>ETOC</name>
              <description>Enable Timeout Counter</description>
              <bitRange>[0:0]</bitRange>
            </field>
            <field>
              <name>TOS</name>
              <description>Timeout Select</description>
              <bitRange>[2:1]</bitRange>
            </field>
            <field>
              <name>TOP</name>
              <description>Timeout Period</description>
              <bitRange>[31:16]</bitRange>
            </field>
          </fields>
        </register>
        <register>
          <name>TOCV</name>
          <addressOffset>0x2C</addressOffset>
          <fields>
            <field>
              <name>TOC</name>
              <description>Timeout Counter</description>
              <bitRange>[15:0]</bitRange>
            </field>
          </fields>
        </register>
        <register>
          <name>ECR</name>
          <addressOffset>0x40</addressOffset>
          <fields>
            <field>
              <name>TEC</name>
              <description>Transmit Error Counter</description>
              <bitRange>[7:0]</bitRange>
            </field>
            <field>
              <name>REC</name>
              <description>Receive Error Counter</description>
              <bitRange>[14:8]</bitRange>
            </field>
            <field>
              <name>RP</name>
              <description>Receive Error Passive</description>
              <bitRange>[15:15]</bitRange>
            </field>
            <field>
              <name>CEL</name>
              <description>CAN Error Logging</description>
              <bitRange>[23:16]</bitRange>
            </field>
          </fields>
        </register>
        <register>
          <name>PSR</name>
          <addressOffset>0x44</addressOffset>
          <fields>
            <field>
              <name>LEC</name>
              <description>Last Error Code</description>
              <bitRange>[2:0]</bitRange>
            </field>
            <field>
              <name>ACT</name>
              <description>Activity</description>
              <bitRange>[4:3]</bitRange>
            </field>
            <field>
              <name>EP</name>
              <description>Error Passive</description>
              <bitRange>[5:5]</bitRange>
            </field>
            <field>
              <name>EW</name>
              <description>Warning Status</description>
              <bitRange>[6:6]</bitRange>
            </field>
            <field>
              <name>GAO</name>
              <description>Bus_Off Status</description>
              <bitRange>[7:7]</bitRange>
            </field>
            <field>
              <name>DLEC</name>
              <description>Data Phase Last Error Code</description>
              <bitRange>[10:8]</bitRange>
            </field>
            <field>
              <name>RESI</name>
              <description>ESI flag of last received CAN FD Message</description>
              <bitRange>[11:11]</bitRange>
            </field>
            <field>
              <name>RBRS</name>
              <description>BRS flag of last received CAN FD Message</description>
              <bitRange>[12:12]</bitRange>
            </field>
            <field>
              <name>RFDF</name>
              <description>Received a CAN FD Message</description>
              <bitRange>[13:13]</bitRange>
            </field>
            <field>
              <name>PXE</name>
              <description>Protocol Exception Event</description>
              <bitRange>[14:14]</bitRange>
            </field>
            <field>
              <name>TDCV</name>
              <description>Transmitter Delay Compensation Value</description>
              <bitRange>[22:16]</bitRange>
            </field>
          </fields>
        </register>
        <register>
          <name>TDCR</name>
          <addressOffset>0x48</addressOffset>
          <fields>
            <field>
              <name>TDCF</name>
              <description>Transmitter Delay Compensation Filter Window Length</description>
              <bitRange>[6:0]</bitRange>
            </field>
            <field>
              <name>TDCO</name>
              <description>Transmitter Delay Compensation SSP Offset</description>
              <bitRange>[14:8]</bitRange>
            </field>
          </fields>
        </register>
        <register>
          <name>IR</name>
          <addressOffset>0x50</addressOffset>
          <fields>
            <field>
              <name>RF0N</name>
              <description>Rx FIFO 0 New Message</description>
              <bitRange>[0:0]</bitRange>
            </field>
            <field>
              <name>RF0W</name>
              <description>Rx FIFO 0 Watermark Reached</description>
              <bitRange>[1:1]</bitRange>
            </field>
            <field>
              <name>RF0F</name>
              <description>Rx FIFO 0 Full</description>
              <bitRange>[2:2]</bitRange>
            </field>
            <field>
              <name>RF0L</name>
              <description>Rx FIFO 0 Message Lost</description>
              <bitRange>[3:3]</bitRange>
            </field>
            <field>
              <name>RF1N</name>
              <description>Rx FIFO 1 New Message</description>
              <bitRange>[4:4]</bitRange>
            </field>
            <field>
              <name>RF1W</name>
              <description>Rx FIFO 1 Watermark Reached</description>
              <bitRange>[5:5]</bitRange>
            </field>
            <field>
              <name>RF1F</name>
              <description>Rx FIFO 1 Full</description>
              <bitRange>[6:6]</bitRange>
            </field>
            <field>
              <name>RF1L</name>
              <description>Rx FIFO 1 Message Lost</description>
              <bitRange>[7:7]</bitRange>
            </field>
            <field>
              <name>HPM</name>
              <description>High Priority Message</description>
              <bitRange>[8:8]</bitRange>
            </field>
            <field>
              <name>TC</name>
              <description>Transmission Completed</description>
              <bitRange>[9:9]</bitRange>
            </field>
            <field>
              <name>TCF</name>
              <description>Transmission Cancellation Finished</description>
              <bitRange>[10:10]</bitRange>
            </field>
            <field>
              <name>TFE</name>
              <description>Tx FIFO Empty</description>
              <bitRange>[11:11]</bitRange>
            </field>
            <field>
              <name>TEFN</name>
              <description>Tx Event FIFO New Entry</description>
              <bitRange>[12:12]</bitRange>
            </field>
            <field>
              <name>TEFW</name>
              <description>Tx Event FIFO Watermark Reached</description>
              <bitRange>[13:13]</bitRange>
            </field>
            <field>
              <name>TEFF</name>
              <description>Tx Event FIFO Full</description>
              <bitRange>[14:14]</bitRange>
            </field>
            <field>
              <name>TEFL</name>
              <description>Tx Event FIFO Element Lost</description>
              <bitRange>[15:15]</bitRange>
            </field>
            <field>
              <name>TSW</name>
              <description>Timestamp Wraparound</description>
              <bitRange>[16:16]</bitRange>
            </field>
            <field>
              <name>MRAF</name>
              <description>Message RAM Access Failure</description>
              <bitRange>[17:17]</bitRange>
            </field>
            <field>
              <name>TOO</name>
              <description>Timeout Occurred</description>
              <bitRange>[18:18]</bitRange>
            </field>
            <field>
              <name>DRX</name>
              <description>Message stored to Dedicated Rx Buffer</description>
              <bitRange>[19:19]</bitRange>
            </field>
            <field>
              <name>BEC</name>
              <description>Bit Error Corrected</description>
              <bitRange>[20:20]</bitRange>
            </field>
            <field>
              <name>BEU</name>
              <description>Bit Error Uncorrected</description>
              <bitRange>[21:21]</bitRange>
            </field>
            <field>
              <name>ELO</name>
              <description>Error Logging Overflow</description>
              <bitRange>[22:22]</bitRange>
            </field>
            <field>
              <name>EP</name>
              <description>Error Passive</description>
              <bitRange>[23:23]</bitRange>
            </field>
            <field>
              <name>EW</name>
              <description>Warning Status</description>
              <bitRange>[24:24]</bitRange>
            </field>
            <field>
              <name>BO</name>
              <description>Bus_Off Status</description>
              <bitRange>[25:25]</bitRange>
            </field>
            <field>
              <name>WDI</name>
              <description>Watchdog Interrupt</description>
              <bitRange>[26:26]</bitRange>
            </field>
            <field>
              <name>PEA</name>
              <description>Protocol Error in Arbitration Phase</description>
              <bitRange>[27:27]</bitRange>
            </field>
            <field>
              <name>PED</name>
              <description>Protocol Error in Data Phase (Data Bit Time is used)</description>
              <bitRange>[28:28]</bitRange>
            </field>
            <field>
              <name>ARA</name>
              <description>Access to Reserved Address</description>
              <bitRange>[29:29]</bitRange>
            </field>
          </fields>
        </register>
        <register>
          <name>IE</name>
          <addressOffset>0x54</addressOffset>
          <fields>
            <field>
              <name>RF0NE</name>
              <description>Rx FIFO 1 New Message Interrupt Enable</description>
              <bitRange>[0:0]</bitRange>
            </field>
            <field>
              <name>RF0WE</name>
              <description>Rx FIFO 1 Watermark Reached Interrupt Enable</description>
              <bitRange>[1:1]</bitRange>
            </field>
            <field>
              <name>RF0FE</name>
              <description>Rx FIFO 1 Full Interrupt Enable</description>
              <bitRange>[2:2]</bitRange>
            </field>
            <field>
              <name>RF0LE</name>
              <description>Rx FIFO 1 Message Lost Interrupt Enable</description>
              <bitRange>[3:3]</bitRange>
            </field>
            <field>
              <name>RF1NE</name>
              <description>Rx FIFO 2 New Message Interrupt Enable</description>
              <bitRange>[4:4]</bitRange>
            </field>
            <field>
              <name>RF1WE</name>
              <description>Rx FIFO 2 Watermark Reached Interrupt Enable</description>
              <bitRange>[5:5]</bitRange>
            </field>
            <field>
              <name>RF1FE</name>
              <description>Rx FIFO 2 Full Interrupt Enable</description>
              <bitRange>[6:6]</bitRange>
            </field>
            <field>
              <name>RF1LE</name>
              <description>Rx FIFO 2 Message Lost Interrupt Enable</description>
              <bitRange>[7:7]</bitRange>
            </field>
            <field>
              <name>HPME</name>
              <description>High Priority Message Interrupt Enable</description>
              <bitRange>[8:8]</bitRange>
            </field>
            <field>
              <name>TCE</name>
              <description>Transmission Completed Interrupt Enable</description>
              <bitRange>[9:9]</bitRange>
            </field>
            <field>
              <name>TCFE</name>
              <description>Transmission Cancellation Finished Interrupt Enable</description>
              <bitRange>[10:10]</bitRange>
            </field>
            <field>
              <name>TFEE</name>
              <description>Tx FIFO Empty Interrupt Enable</description>
              <bitRange>[11:11]</bitRange>
            </field>
            <field>
              <name>TEFNE</name>
              <description>Tx Event FIFO New Entry Interrupt Enable</description>
              <bitRange>[12:12]</bitRange>
            </field>
            <field>
              <name>TEFWE</name>
              <description>Tx Event FIFO Watermark Reached Interrupt Enable</description>
              <bitRange>[13:13]</bitRange>
            </field>
            <field>
              <name>TEFFE</name>
              <description>Tx Event FIFO Full Interrupt Enable</description>
              <bitRange>[14:14]</bitRange>
            </field>
            <field>
              <name>TEFLE</name>
              <description>Tx Event FIFO Event Lost Interrupt Enable</description>
              <bitRange>[15:15]</bitRange>
            </field>
            <field>
              <name>TSWE</name>
              <description>Timestamp Wraparound Interrupt Enable</description>
              <bitRange>[16:16]</bitRange>
            </field>
            <field>
              <name>MRAFE</name>
              <description>Message RAM Access Failure Interrupt Enable</description>
              <bitRange>[17:17]</bitRange>
            </field>
            <field>
              <name>TOOE</name>
              <description>Timeout Occurred Interrupt Enable</description>
              <bitRange>[18:18]</bitRange>
            </field>
            <field>
              <name>DRXE</name>
              <description>Message stored to Dedicated Rx Buffer Interrupt Enable</description>
              <bitRange>[19:19]</bitRange>
            </field>
            <field>
              <name>BECE</name>
              <description>Bit Error Corrected Interrupt Enable</description>
              <bitRange>[20:20]</bitRange>
            </field>
            <field>
              <name>BEUE</name>
              <description>Bit Error Uncorrected Interrupt Enable</description>
              <bitRange>[21:21]</bitRange>
            </field>
            <field>
              <name>ELOE</name>
              <description>Error Logging Overflow Interrupt Enable</description>
              <bitRange>[22:22]</bitRange>
            </field>
            <field>
              <name>EPE</name>
              <description>Error Passive Interrupt Enable</description>
              <bitRange>[23:23]</bitRange>
            </field>
            <field>
              <name>EWE</name>
              <description>Warning Status Interrupt Enable</description>
              <bitRange>[24:24]</bitRange>
            </field>
            <field>
              <name>BOE</name>
              <description>Bus_Off Status Interrupt Enable</description>
              <bitRange>[25:25]</bitRange>
            </field>
            <field>
              <name>WDIE</name>
              <description>Watchdog Interrupt Enable</description>
              <bitRange>[26:26]</bitRange>
            </field>
            <field>
              <name>PEAE</name>
              <description>Protocol Error in Arbitration Phase Enable</description>
              <bitRange>[27:27]</bitRange>
            </field>
            <field>
              <name>PEDE</name>
              <description>Protocol Error in Data Phase Enable</description>
              <bitRange>[28:28]</bitRange>
            </field>
            <field>
              <name>ARAE</name>
              <description>Access to Reserved Address Enable</description>
              <bitRange>[29:29]</bitRange>
            </field>
          </fields>
        </register>
        <register>
          <name>ILS</name>
          <addressOffset>0x58</addressOffset>
          <fields>
            <field>
              <name>RF0NL</name>
              <description>Rx FIFO 1 New Message Interrupt Line</description>
              <bitRange>[0:0]</bitRange>
            </field>
            <field>
              <name>RF0WL</name>
              <description>Rx FIFO 1 Watermark Reached Interrupt Line</description>
              <bitRange>[1:1]</bitRange>
            </field>
            <field>
              <name>RF0FL</name>
              <description>Rx FIFO 1 Full Interrupt Line</description>
              <bitRange>[2:2]</bitRange>
            </field>
            <field>
              <name>RF0LL</name>
              <description>Rx FIFO 1 Message Lost Interrupt Line</description>
              <bitRange>[3:3]</bitRange>
            </field>
            <field>
              <name>RF1NL</name>
              <description>Rx FIFO 2 New Message Interrupt Line</description>
              <bitRange>[4:4]</bitRange>
            </field>
            <field>
              <name>RF1WL</name>
              <description>Rx FIFO 2 Watermark Reached Interrupt Line</description>
              <bitRange>[5:5]</bitRange>
            </field>
            <field>
              <name>RF1FL</name>
              <description>Rx FIFO 2 Full Interrupt Line</description>
              <bitRange>[6:6]</bitRange>
            </field>
            <field>
              <name>RF1LL</name>
              <description>Rx FIFO 2 Message Lost Interrupt Line</description>
              <bitRange>[7:7]</bitRange>
            </field>
            <field>
              <name>HPML</name>
              <description>High Priority Message Interrupt Line</description>
              <bitRange>[8:8]</bitRange>
            </field>
            <field>
              <name>TCL</name>
              <description>Transmission Completed Interrupt Line</description>
              <bitRange>[9:9]</bitRange>
            </field>
            <field>
              <name>TCFL</name>
              <description>Transmission Cancellation Finished Interrupt Line</description>
              <bitRange>[10:10]</bitRange>
            </field>
            <field>
              <name>TFEL</name>
              <description>Tx FIFO Empty Interrupt Line</description>
              <bitRange>[11:11]</bitRange>
            </field>
            <field>
              <name>TEFNL</name>
              <description>Tx Event FIFO New Entry Interrupt Line</description>
              <bitRange>[12:12]</bitRange>
            </field>
            <field>
              <name>TEFWL</name>
              <description>Tx Event FIFO Watermark Reached Interrupt Line</description>
              <bitRange>[13:13]</bitRange>
            </field>
            <field>
              <name>TEFFL</name>
              <description>Tx Event FIFO Full Interrupt Line</description>
              <bitRange>[14:14]</bitRange>
            </field>
            <field>
              <name>TEFLL</name>
              <description>Tx Event FIFO Event Lost Interrupt Line</description>
              <bitRange>[15:15]</bitRange>
            </field>
            <field>
              <name>TSWL</name>
              <description>Timestamp Wraparound Interrupt Line</description>
              <bitRange>[16:16]</bitRange>
            </field>
            <field>
              <name>MRAFL</name>
              <description>Message RAM Access Failure Interrupt Line</description>
              <bitRange>[17:17]</bitRange>
            </field>
            <field>
              <name>TOOL</name>
              <description>Timeout Occurred Interrupt Line</description>
              <bitRange>[18:18]</bitRange>
            </field>
            <field>
              <name>DRXL</name>
              <description>Message stored to Dedicated Rx Buffer Interrupt Line</description>
              <bitRange>[19:19]</bitRange>
            </field>
            <field>
              <name>BECL</name>
              <description>Bit Error Corrected Interrupt Line</description>
              <bitRange>[20:20]</bitRange>
            </field>
            <field>
              <name>BEUL</name>
              <description>Bit Error Uncorrected Interrupt Line</description>
              <bitRange>[21:21]</bitRange>
            </field>
            <field>
              <name>ELOL</name>
              <description>Error Logging Overflow Interrupt Line</description>
              <bitRange>[22:22]</bitRange>
            </field>
            <field>
              <name>EPL</name>
              <description>Error Passive Interrupt Line</description>
              <bitRange>[23:23]</bitRange>
            </field>
            <field>
              <name>EWL</name>
              <description>Warning Status Interrupt Line</description>
              <bitRange>[24:24]</bitRange>
            </field>
            <field>
              <name>BOL</name>
              <description>Bus_Off Status Interrupt Line</description>
              <bitRange>[25:25]</bitRange>
            </field>
            <field>
              <name>WDIL</name>
              <description>Watchdog Interrupt Line</description>
              <bitRange>[26:26]</bitRange>
            </field>
            <field>
              <name>PEAL</name>
              <description>Protocol Error in Arbitration Phase Line</description>
              <bitRange>[27:27]</bitRange>
            </field>
            <field>
              <name>PEDL</name>
              <description>Protocol Error in Data Phase Line</description>
              <bitRange>[28:28]</bitRange>
            </field>
            <field>
              <name>ARAL</name>
              <description>Access to Reserved Address Line</description>
              <bitRange>[29:29]</bitRange>
            </field>
          </fields>
        </register>
        <register>
          <name>ILE</name>
          <addressOffset>0x5C</addressOffset>
          <fields>
            <field>
              <name>EINT0</name>
              <description>Enable Interrupt Line 0</description>
              <bitRange>[0:0]</bitRange>
              <access>read-only</access>
            </field>
            <field>
              <name>EINT1</name>
              <description>Enable Interrupt Line 1</description>
              <bitRange>[1:1]</bitRange>
            </field>
          </fields>
        </register>
        <register>
          <name>GFC</name>
          <addressOffset>0x80</addressOffset>
          <fields>
            <field>
              <name>RRFE</name>
              <description>Reject Remote Frames Extended</description>
              <bitRange>[0:0]</bitRange>
            </field>
            <field>
              <name>RRFS</name>
              <description>Reject Remote Frames Standard</description>
              <bitRange>[1:1]</bitRange>
            </field>
            <field>
              <name>ANFE</name>
              <description>Accept Non-matching Frames Extended</description>
              <bitRange>[3:2]</bitRange>
            </field>
            <field>
              <name>ANFS</name>
              <description>Accept Non-matching Frames Standard</description>
              <bitRange>[5:4]</bitRange>
            </field>
          </fields>
        </register>
        <register>
          <name>SIDFC</name>
          <addressOffset>0x84</addressOffset>
          <fields>
            <field>
              <name>FLSSA</name>
              <description>Filter List Standard Start Address</description>
              <bitRange>[15:2]</bitRange>
            </field>
            <field>
              <name>LSS</name>
              <description>List Size Standard</description>
              <bitRange>[23:16]</bitRange>
            </field>
          </fields>
        </register>
        <register>
          <name>XIDFC</name>
          <addressOffset>0x88</addressOffset>
          <fields>
            <field>
              <name>FLESA</name>
              <description>Filter List Extended Start Address</description>
              <bitRange>[15:2]</bitRange>
            </field>
            <field>
              <name>LSE</name>
              <description>List Size Extended</description>
              <bitRange>[22:16]</bitRange>
            </field>
          </fields>
        </register>
        <register>
          <name>XIDAM</name>
          <addressOffset>0x90</addressOffset>
          <fields>
            <field>
              <name>EIDM</name>
              <description>Extended ID Mask</description>
              <bitRange>[28:0]</bitRange>
            </field>
          </fields>
        </register>
        <register>
          <name>HPMS</name>
          <addressOffset>0x94</addressOffset>
          <fields>
            <field>
              <name>BIDX</name>
              <description>Buffer Index</description>
              <bitRange>[5:0]</bitRange>
              <access>read-only</access>
            </field>
            <field>
              <name>MSI</name>
              <description>Message Storage Indicator</description>
              <bitRange>[7:6]</bitRange>
              <access>read-only</access>
            </field>
            <field>
              <name>FIDX</name>
              <description>Filter Index</description>
              <bitRange>[14:8]</bitRange>
              <access>read-only</access>
            </field>
            <field>
              <name>FLST</name>
              <description>Filter List</description>
              <bitRange>[15:15]</bitRange>
              <access>read-only</access>
            </field>
          </fields>
        </register>
        <register>
          <name>NDAT1</name>
          <addressOffset>0x98</addressOffset>
          <fields>
            <field>
              <name>ND0</name>
              <description>New Data0</description>
              <bitRange>[0:0]</bitRange>
            </field>
            <field>
              <name>ND1</name>
              <description>New Data1</description>
              <bitRange>[1:1]</bitRange>
            </field>
            <field>
              <name>ND2</name>
              <description>New Data2</description>
              <bitRange>[2:2]</bitRange>
            </field>
            <field>
              <name>ND3</name>
              <description>New Data3</description>
              <bitRange>[3:3]</bitRange>
            </field>
            <field>
              <name>ND4</name>
              <description>New Data4</description>
              <bitRange>[4:4]</bitRange>
            </field>
            <field>
              <name>ND5</name>
              <description>New Data5</description>
              <bitRange>[5:5]</bitRange>
            </field>
            <field>
              <name>ND6</name>
              <description>New Data6</description>
              <bitRange>[6:6]</bitRange>
            </field>
            <field>
              <name>ND7</name>
              <description>New Data7</description>
              <bitRange>[7:7]</bitRange>
            </field>
            <field>
              <name>ND8</name>
              <description>New Data8</description>
              <bitRange>[8:8]</bitRange>
            </field>
            <field>
              <name>ND9</name>
              <description>New Data9</description>
              <bitRange>[9:9]</bitRange>
            </field>
            <field>
              <name>ND10</name>
              <description>New Data10</description>
              <bitRange>[10:10]</bitRange>
            </field>
            <field>
              <name>ND11</name>
              <description>New Data11</description>
              <bitRange>[11:11]</bitRange>
            </field>
            <field>
              <name>ND12</name>
              <description>New Data12</description>
              <bitRange>[12:12]</bitRange>
            </field>
            <field>
              <name>ND13</name>
              <description>New Data13</description>
              <bitRange>[13:13]</bitRange>
            </field>
            <field>
              <name>ND14</name>
              <description>New Data14</description>
              <bitRange>[14:14]</bitRange>
            </field>
            <field>
              <name>ND15</name>
              <description>New Data15</description>
              <bitRange>[15:15]</bitRange>
            </field>
            <field>
              <name>ND16</name>
              <description>New Data16</description>
              <bitRange>[16:16]</bitRange>
            </field>
            <field>
              <name>ND17</name>
              <description>New Data17</description>
              <bitRange>[17:17]</bitRange>
            </field>
            <field>
              <name>ND18</name>
              <description>New Data18</description>
              <bitRange>[18:18]</bitRange>
            </field>
            <field>
              <name>ND19</name>
              <description>New Data19</description>
              <bitRange>[19:19]</bitRange>
            </field>
            <field>
              <name>ND20</name>
              <description>New Data20</description>
              <bitRange>[20:20]</bitRange>
            </field>
            <field>
              <name>ND21</name>
              <description>New Data21</description>
              <bitRange>[21:21]</bitRange>
            </field>
            <field>
              <name>ND22</name>
              <description>New Data22</description>
              <bitRange>[22:22]</bitRange>
            </field>
            <field>
              <name>ND23</name>
              <description>New Data23</description>
              <bitRange>[23:23]</bitRange>
            </field>
            <field>
              <name>ND24</name>
              <description>New Data24</description>
              <bitRange>[24:24]</bitRange>
            </field>
            <field>
              <name>ND25</name>
              <description>New Data25</description>
              <bitRange>[25:25]</bitRange>
            </field>
            <field>
              <name>ND26</name>
              <description>New Data26</description>
              <bitRange>[26:26]</bitRange>
            </field>
            <field>
              <name>ND27</name>
              <description>New Data27</description>
              <bitRange>[27:27]</bitRange>
            </field>
            <field>
              <name>ND28</name>
              <description>New Data28</description>
              <bitRange>[28:28]</bitRange>
            </field>
            <field>
              <name>ND29</name>
              <description>New Data29</description>
              <bitRange>[29:29]</bitRange>
            </field>
            <field>
              <name>ND30</name>
              <description>New Data30</description>
              <bitRange>[30:30]</bitRange>
            </field>
            <field>
              <name>ND31</name>
              <description>New Data31</description>
              <bitRange>[31:31]</bitRange>
            </field>
          </fields>
        </register>
        <register>
          <name>NDAT2</name>
          <addressOffset>0x9C</addressOffset>
          <fields>
            <field>
              <name>ND32</name>
              <description>New Data32</description>
              <bitRange>[0:0]</bitRange>
            </field>
            <field>
              <name>ND33</name>
              <description>New Data33</description>
              <bitRange>[1:1]</bitRange>
            </field>
            <field>
              <name>ND34</name>
              <description>New Data34</description>
              <bitRange>[2:2]</bitRange>
            </field>
            <field>
              <name>ND35</name>
              <description>New Data35</description>
              <bitRange>[3:3]</bitRange>
            </field>
            <field>
              <name>ND36</name>
              <description>New Data36</description>
              <bitRange>[4:4]</bitRange>
            </field>
            <field>
              <name>ND37</name>
              <description>New Data37</description>
              <bitRange>[5:5]</bitRange>
            </field>
            <field>
              <name>ND38</name>
              <description>New Data38</description>
              <bitRange>[6:6]</bitRange>
            </field>
            <field>
              <name>ND39</name>
              <description>New Data39</description>
              <bitRange>[7:7]</bitRange>
            </field>
            <field>
              <name>ND40</name>
              <description>New Data40</description>
              <bitRange>[8:8]</bitRange>
            </field>
            <field>
              <name>ND41</name>
              <description>New Data41</description>
              <bitRange>[9:9]</bitRange>
            </field>
            <field>
              <name>ND42</name>
              <description>New Data42</description>
              <bitRange>[10:10]</bitRange>
            </field>
            <field>
              <name>ND43</name>
              <description>New Data43</description>
              <bitRange>[11:11]</bitRange>
            </field>
            <field>
              <name>ND44</name>
              <description>New Data44</description>
              <bitRange>[12:12]</bitRange>
            </field>
            <field>
              <name>ND45</name>
              <description>New Data45</description>
              <bitRange>[13:13]</bitRange>
            </field>
            <field>
              <name>ND46</name>
              <description>New Data46</description>
              <bitRange>[14:14]</bitRange>
            </field>
            <field>
              <name>ND47</name>
              <description>New Data47</description>
              <bitRange>[15:15]</bitRange>
            </field>
            <field>
              <name>ND48</name>
              <description>New Data48</description>
              <bitRange>[16:16]</bitRange>
            </field>
            <field>
              <name>ND49</name>
              <description>New Data49</description>
              <bitRange>[17:17]</bitRange>
            </field>
            <field>
              <name>ND50</name>
              <description>New Data50</description>
              <bitRange>[18:18]</bitRange>
            </field>
            <field>
              <name>ND51</name>
              <description>New Data51</description>
              <bitRange>[19:19]</bitRange>
            </field>
            <field>
              <name>ND52</name>
              <description>New Data52</description>
              <bitRange>[20:20]</bitRange>
            </field>
            <field>
              <name>ND53</name>
              <description>New Data53</description>
              <bitRange>[21:21]</bitRange>
            </field>
            <field>
              <name>ND54</name>
              <description>New Data54</description>
              <bitRange>[22:22]</bitRange>
            </field>
            <field>
              <name>ND55</name>
              <description>New Data55</description>
              <bitRange>[23:23]</bitRange>
            </field>
            <field>
              <name>ND56</name>
              <description>New Data56</description>
              <bitRange>[24:24]</bitRange>
            </field>
            <field>
              <name>ND57</name>
              <description>New Data57</description>
              <bitRange>[25:25]</bitRange>
            </field>
            <field>
              <name>ND58</name>
              <description>New Data58</description>
              <bitRange>[26:26]</bitRange>
            </field>
            <field>
              <name>ND59</name>
              <description>New Data59</description>
              <bitRange>[27:27]</bitRange>
            </field>
            <field>
              <name>ND60</name>
              <description>New Data60</description>
              <bitRange>[28:28]</bitRange>
            </field>
            <field>
              <name>ND61</name>
              <description>New Data61</description>
              <bitRange>[29:29]</bitRange>
            </field>
            <field>
              <name>ND62</name>
              <description>New Data62</description>
              <bitRange>[30:30]</bitRange>
            </field>
            <field>
              <name>ND63</name>
              <description>New Data63</description>
              <bitRange>[31:31]</bitRange>
            </field>
          </fields>
        </register>
        <register>
          <name>RXF0C</name>
          <addressOffset>0xA0</addressOffset>
          <fields>
            <field>
              <name>F0SA</name>
              <description>Rx FIFO 0 Start Address</description>
              <bitRange>[5:2]</bitRange>
              <access>read-only</access>
            </field>
            <field>
              <name>F0S</name>
              <description>Rx FIFO 0 Size</description>
              <bitRange>[22:16]</bitRange>
              <access>read-only</access>
            </field>
            <field>
              <name>F0WM</name>
              <description>Rx FIFO 0 Watermark</description>
              <bitRange>[30:24]</bitRange>
              <access>read-only</access>
            </field>
            <field>
              <name>F0OM</name>
              <description>FIFO 0 Operation Mode</description>
              <bitRange>[31:31]</bitRange>
              <access>read-only</access>
            </field>
          </fields>
        </register>
        <register>
          <name>RXF0S</name>
          <addressOffset>0xA4</addressOffset>
          <fields>
            <field>
              <name>F0FL</name>
              <description>Rx FIFO 0 Fill Level</description>
              <bitRange>[6:0]</bitRange>
              <access>read-only</access>
            </field>
            <field>
              <name>F0GI</name>
              <description>Rx FIFO 0 Get Index</description>
              <bitRange>[13:8]</bitRange>
              <access>read-only</access>
            </field>
            <field>
              <name>F0PI</name>
              <description>Rx FIFO 0 Put Index</description>
              <bitRange>[21:16]</bitRange>
              <access>read-only</access>
            </field>
            <field>
              <name>F0F</name>
              <description>Rx FIFO 0 Full</description>
              <bitRange>[24:24]</bitRange>
              <access>read-only</access>
            </field>
            <field>
              <name>RF0L</name>
              <description>Rx FIFO 0 Message Lost</description>
              <bitRange>[25:25]</bitRange>
              <access>read-only</access>
            </field>
          </fields>
        </register>
        <register>
          <name>RXF0A</name>
          <addressOffset>0xA8</addressOffset>
          <fields>
            <field>
              <name>F0AI</name>
              <description>Rx FIFO 0 Acknowledge Index</description>
              <bitRange>[5:0]</bitRange>
              <access>read-only</access>
            </field>
          </fields>
        </register>
        <register>
          <name>RXBC</name>
          <addressOffset>0xAC</addressOffset>
          <fields>
            <field>
              <name>RBSA</name>
              <description>Rx Buffer Start Address</description>
              <bitRange>[15:2]</bitRange>
              <access>read-only</access>
            </field>
          </fields>
        </register>
        <register>
          <name>RXF1C</name>
          <addressOffset>0xB0</addressOffset>
          <fields>
            <field>
              <name>F1SA</name>
              <description>Rx FIFO 1 Start Address</description>
              <bitRange>[5:2]</bitRange>
              <access>read-only</access>
            </field>
            <field>
              <name>F1S</name>
              <description>Rx FIFO 1 Size</description>
              <bitRange>[22:16]</bitRange>
              <access>read-only</access>
            </field>
            <field>
              <name>F1WM</name>
              <description>Rx FIFO 1 Watermark</description>
              <bitRange>[30:24]</bitRange>
              <access>read-only</access>
            </field>
            <field>
              <name>F1OM</name>
              <description>FIFO 1 Operation Mode</description>
              <bitRange>[31:31]</bitRange>
              <access>read-only</access>
            </field>
          </fields>
        </register>
        <register>
          <name>RXF1S</name>
          <addressOffset>0xB4</addressOffset>
          <fields>
            <field>
              <name>F1FL</name>
              <description>Rx FIFO 1 Fill Level</description>
              <bitRange>[6:0]</bitRange>
              <access>read-only</access>
            </field>
            <field>
              <name>F1GI</name>
              <description>Rx FIFO 1 Get Index</description>
              <bitRange>[13:8]</bitRange>
              <access>read-only</access>
            </field>
            <field>
              <name>F1PI</name>
              <description>Rx FIFO 1 Put Index</description>
              <bitRange>[21:16]</bitRange>
              <access>read-only</access>
            </field>
            <field>
              <name>F1F</name>
              <description>Rx FIFO 1 Full</description>
              <bitRange>[24:24]</bitRange>
              <access>read-only</access>
            </field>
            <field>
              <name>RF1L</name>
              <description>Rx FIFO 1 Message Lost</description>
              <bitRange>[25:25]</bitRange>
              <access>read-only</access>
            </field>
            <field>
              <name>DMS</name>
              <description>Debug Message Status</description>
              <bitRange>[31:30]</bitRange>
              <access>read-only</access>
            </field>
          </fields>
        </register>
        <register>
          <name>RXF1A</name>
          <addressOffset>0xB8</addressOffset>
          <fields>
            <field>
              <name>F1AI</name>
              <description>Rx FIFO 1 Acknowledge Index</description>
              <bitRange>[5:0]</bitRange>
              <access>read-only</access>
            </field>
          </fields>
        </register>
        <register>
          <name>RXESC</name>
          <addressOffset>0xBC</addressOffset>
          <fields>
            <field>
              <name>F0DS</name>
              <description>Rx FIFO 0 Data Field Size</description>
              <bitRange>[2:0]</bitRange>
              <access>read-only</access>
            </field>
            <field>
              <name>F1DS</name>
              <description>Rx FIFO 1 Data Field Size</description>
              <bitRange>[6:4]</bitRange>
              <access>read-only</access>
            </field>
            <field>
              <name>RBDS</name>
              <description>Rx Buffer Data Field Size</description>
              <bitRange>[10:8]</bitRange>
              <access>read-only</access>
            </field>
          </fields>
        </register>
        <register>
          <name>TXBC</name>
          <addressOffset>0xC0</addressOffset>
          <fields>
            <field>
              <name>TBSA</name>
              <description>Tx Buffers Start Address</description>
              <bitRange>[15:2]</bitRange>
              <access>read-only</access>
            </field>
            <field>
              <name>NDTB</name>
              <description>Number of Dedicated Transmit Buffers</description>
              <bitRange>[21:16]</bitRange>
              <access>read-only</access>
            </field>
            <field>
              <name>TFQS</name>
              <description>Transmit FIFO/Queue Size</description>
              <bitRange>[29:24]</bitRange>
              <access>read-only</access>
            </field>
            <field>
              <name>TFQM</name>
              <description>Tx FIFO/Queue Mode</description>
              <bitRange>[30:30]</bitRange>
              <access>read-only</access>
            </field>
          </fields>
        </register>
        <register>
          <name>TXFQS</name>
          <addressOffset>0xC4</addressOffset>
          <fields>
            <field>
              <name>TFFL</name>
              <description>Tx FIFO Free Level</description>
              <bitRange>[5:0]</bitRange>
              <access>read-only</access>
            </field>
            <field>
              <name>TFGI</name>
              <description>Tx FIFO Get Index</description>
              <bitRange>[12:8]</bitRange>
              <access>read-only</access>
            </field>
            <field>
              <name>TFQPI</name>
              <description>Tx FIFO/Queue Put Index</description>
              <bitRange>[20:16]</bitRange>
              <access>read-only</access>
            </field>
            <field>
              <name>TFQF</name>
              <description>Tx FIFO/Queue Full</description>
              <bitRange>[21:21]</bitRange>
              <access>read-only</access>
            </field>
          </fields>
        </register>
        <register>
          <name>TXESC</name>
          <addressOffset>0xC8</addressOffset>
          <fields>
            <field>
              <name>TBDS</name>
              <description>Tx Buffer Data Field Size</description>
              <bitRange>[2:0]</bitRange>
              <access>read-only</access>
            </field>
          </fields>
        </register>
        <register>
          <name>TXBRP</name>
          <addressOffset>0xCC</addressOffset>
          <fields>
            <field>
              <name>TRP0</name>
              <description>Transmission Request Pending</description>
              <bitRange>[0:0]</bitRange>
              <access>read-only</access>
            </field>
            <field>
              <name>TRP1</name>
              <description>Transmission Request Pending</description>
              <bitRange>[1:1]</bitRange>
              <access>read-only</access>
            </field>
            <field>
              <name>TRP2</name>
              <description>Transmission Request Pending</description>
              <bitRange>[2:2]</bitRange>
              <access>read-only</access>
            </field>
            <field>
              <name>TRP3</name>
              <description>Transmission Request Pending</description>
              <bitRange>[3:3]</bitRange>
              <access>read-only</access>
            </field>
            <field>
              <name>TRP4</name>
              <description>Transmission Request Pending</description>
              <bitRange>[4:4]</bitRange>
              <access>read-only</access>
            </field>
            <field>
              <name>TRP5</name>
              <description>Transmission Request Pending</description>
              <bitRange>[5:5]</bitRange>
              <access>read-only</access>
            </field>
            <field>
              <name>TRP6</name>
              <description>Transmission Request Pending</description>
              <bitRange>[6:6]</bitRange>
              <access>read-only</access>
            </field>
            <field>
              <name>TRP7</name>
              <description>Transmission Request Pending</description>
              <bitRange>[7:7]</bitRange>
              <access>read-only</access>
            </field>
            <field>
              <name>TRP8</name>
              <description>Transmission Request Pending</description>
              <bitRange>[8:8]</bitRange>
              <access>read-only</access>
            </field>
            <field>
              <name>TRP9</name>
              <description>Transmission Request Pending</description>
              <bitRange>[9:9]</bitRange>
              <access>read-only</access>
            </field>
            <field>
              <name>TRP10</name>
              <description>Transmission Request Pending</description>
              <bitRange>[10:10]</bitRange>
              <access>read-only</access>
            </field>
            <field>
              <name>TRP11</name>
              <description>Transmission Request Pending</description>
              <bitRange>[11:11]</bitRange>
              <access>read-only</access>
            </field>
            <field>
              <name>TRP12</name>
              <description>Transmission Request Pending</description>
              <bitRange>[12:12]</bitRange>
              <access>read-only</access>
            </field>
            <field>
              <name>TRP13</name>
              <description>Transmission Request Pending</description>
              <bitRange>[13:13]</bitRange>
              <access>read-only</access>
            </field>
            <field>
              <name>TRP14</name>
              <description>Transmission Request Pending</description>
              <bitRange>[14:14]</bitRange>
              <access>read-only</access>
            </field>
            <field>
              <name>TRP15</name>
              <description>Transmission Request Pending</description>
              <bitRange>[15:15]</bitRange>
              <access>read-only</access>
            </field>
            <field>
              <name>TRP16</name>
              <description>Transmission Request Pending</description>
              <bitRange>[16:16]</bitRange>
              <access>read-only</access>
            </field>
            <field>
              <name>TRP17</name>
              <description>Transmission Request Pending</description>
              <bitRange>[17:17]</bitRange>
              <access>read-only</access>
            </field>
            <field>
              <name>TRP18</name>
              <description>Transmission Request Pending</description>
              <bitRange>[18:18]</bitRange>
              <access>read-only</access>
            </field>
            <field>
              <name>TRP19</name>
              <description>Transmission Request Pending</description>
              <bitRange>[19:19]</bitRange>
              <access>read-only</access>
            </field>
            <field>
              <name>TRP20</name>
              <description>Transmission Request Pending</description>
              <bitRange>[20:20]</bitRange>
              <access>read-only</access>
            </field>
            <field>
              <name>TRP21</name>
              <description>Transmission Request Pending</description>
              <bitRange>[21:21]</bitRange>
              <access>read-only</access>
            </field>
            <field>
              <name>TRP22</name>
              <description>Transmission Request Pending</description>
              <bitRange>[22:22]</bitRange>
              <access>read-only</access>
            </field>
            <field>
              <name>TRP23</name>
              <description>Transmission Request Pending</description>
              <bitRange>[23:23]</bitRange>
              <access>read-only</access>
            </field>
            <field>
              <name>TRP24</name>
              <description>Transmission Request Pending</description>
              <bitRange>[24:24]</bitRange>
              <access>read-only</access>
            </field>
            <field>
              <name>TRP25</name>
              <description>Transmission Request Pending</description>
              <bitRange>[25:25]</bitRange>
              <access>read-only</access>
            </field>
            <field>
              <name>TRP26</name>
              <description>Transmission Request Pending</description>
              <bitRange>[26:26]</bitRange>
              <access>read-only</access>
            </field>
            <field>
              <name>TRP27</name>
              <description>Transmission Request Pending</description>
              <bitRange>[27:27]</bitRange>
              <access>read-only</access>
            </field>
            <field>
              <name>TRP28</name>
              <description>Transmission Request Pending</description>
              <bitRange>[28:28]</bitRange>
              <access>read-only</access>
            </field>
            <field>
              <name>TRP29</name>
              <description>Transmission Request Pending</description>
              <bitRange>[29:29]</bitRange>
              <access>read-only</access>
            </field>
            <field>
              <name>TRP30</name>
              <description>Transmission Request Pending</description>
              <bitRange>[30:30]</bitRange>
              <access>read-only</access>
            </field>
            <field>
              <name>TRP31</name>
              <description>Transmission Request Pending</description>
              <bitRange>[31:31]</bitRange>
              <access>read-only</access>
            </field>
          </fields>
        </register>
        <register>
          <name>TXBAR</name>
          <addressOffset>0xD0</addressOffset>
          <fields>
            <field>
              <name>AR0</name>
              <description>Add Request</description>
              <bitRange>[0:0]</bitRange>
            </field>
            <field>
              <name>AR1</name>
              <description>Add Request</description>
              <bitRange>[1:1]</bitRange>
            </field>
            <field>
              <name>AR2</name>
              <description>Add Request</description>
              <bitRange>[2:2]</bitRange>
            </field>
            <field>
              <name>AR3</name>
              <description>Add Request</description>
              <bitRange>[3:3]</bitRange>
            </field>
            <field>
              <name>AR4</name>
              <description>Add Request</description>
              <bitRange>[4:4]</bitRange>
            </field>
            <field>
              <name>AR5</name>
              <description>Add Request</description>
              <bitRange>[5:5]</bitRange>
            </field>
            <field>
              <name>AR6</name>
              <description>Add Request</description>
              <bitRange>[6:6]</bitRange>
            </field>
            <field>
              <name>AR7</name>
              <description>Add Request</description>
              <bitRange>[7:7]</bitRange>
            </field>
            <field>
              <name>AR8</name>
              <description>Add Request</description>
              <bitRange>[8:8]</bitRange>
            </field>
            <field>
              <name>AR9</name>
              <description>Add Request</description>
              <bitRange>[9:9]</bitRange>
            </field>
            <field>
              <name>AR10</name>
              <description>Add Request</description>
              <bitRange>[10:10]</bitRange>
            </field>
            <field>
              <name>AR11</name>
              <description>Add Request</description>
              <bitRange>[11:11]</bitRange>
            </field>
            <field>
              <name>AR12</name>
              <description>Add Request</description>
              <bitRange>[12:12]</bitRange>
            </field>
            <field>
              <name>AR13</name>
              <description>Add Request</description>
              <bitRange>[13:13]</bitRange>
            </field>
            <field>
              <name>AR14</name>
              <description>Add Request</description>
              <bitRange>[14:14]</bitRange>
            </field>
            <field>
              <name>AR15</name>
              <description>Add Request</description>
              <bitRange>[15:15]</bitRange>
            </field>
            <field>
              <name>AR16</name>
              <description>Add Request</description>
              <bitRange>[16:16]</bitRange>
            </field>
            <field>
              <name>AR17</name>
              <description>Add Request</description>
              <bitRange>[17:17]</bitRange>
            </field>
            <field>
              <name>AR18</name>
              <description>Add Request</description>
              <bitRange>[18:18]</bitRange>
            </field>
            <field>
              <name>AR19</name>
              <description>Add Request</description>
              <bitRange>[19:19]</bitRange>
            </field>
            <field>
              <name>AR20</name>
              <description>Add Request</description>
              <bitRange>[20:20]</bitRange>
            </field>
            <field>
              <name>AR21</name>
              <description>Add Request</description>
              <bitRange>[21:21]</bitRange>
            </field>
            <field>
              <name>AR22</name>
              <description>Add Request</description>
              <bitRange>[22:22]</bitRange>
            </field>
            <field>
              <name>AR23</name>
              <description>Add Request</description>
              <bitRange>[23:23]</bitRange>
            </field>
            <field>
              <name>AR24</name>
              <description>Add Request</description>
              <bitRange>[24:24]</bitRange>
            </field>
            <field>
              <name>AR25</name>
              <description>Add Request</description>
              <bitRange>[25:25]</bitRange>
            </field>
            <field>
              <name>AR26</name>
              <description>Add Request</description>
              <bitRange>[26:26]</bitRange>
            </field>
            <field>
              <name>AR27</name>
              <description>Add Request</description>
              <bitRange>[27:27]</bitRange>
            </field>
            <field>
              <name>AR28</name>
              <description>Add Request</description>
              <bitRange>[28:28]</bitRange>
            </field>
            <field>
              <name>AR29</name>
              <description>Add Request</description>
              <bitRange>[29:29]</bitRange>
            </field>
            <field>
              <name>AR30</name>
              <description>Add Request</description>
              <bitRange>[30:30]</bitRange>
            </field>
            <field>
              <name>AR31</name>
              <description>Add Request</description>
              <bitRange>[31:31]</bitRange>
            </field>
          </fields>
        </register>
        <register>
          <name>TXBCR</name>
          <addressOffset>0xD4</addressOffset>
          <fields>
            <field>
              <name>CR0</name>
              <description>Cancellation Request</description>
              <bitRange>[0:0]</bitRange>
            </field>
            <field>
              <name>CR1</name>
              <description>Cancellation Request</description>
              <bitRange>[1:1]</bitRange>
            </field>
            <field>
              <name>CR2</name>
              <description>Cancellation Request</description>
              <bitRange>[2:2]</bitRange>
            </field>
            <field>
              <name>CR3</name>
              <description>Cancellation Request</description>
              <bitRange>[3:3]</bitRange>
            </field>
            <field>
              <name>CR4</name>
              <description>Cancellation Request</description>
              <bitRange>[4:4]</bitRange>
            </field>
            <field>
              <name>CR5</name>
              <description>Cancellation Request</description>
              <bitRange>[5:5]</bitRange>
            </field>
            <field>
              <name>CR6</name>
              <description>Cancellation Request</description>
              <bitRange>[6:6]</bitRange>
            </field>
            <field>
              <name>CR7</name>
              <description>Cancellation Request</description>
              <bitRange>[7:7]</bitRange>
            </field>
            <field>
              <name>CR8</name>
              <description>Cancellation Request</description>
              <bitRange>[8:8]</bitRange>
            </field>
            <field>
              <name>CR9</name>
              <description>Cancellation Request</description>
              <bitRange>[9:9]</bitRange>
            </field>
            <field>
              <name>CR10</name>
              <description>Cancellation Request</description>
              <bitRange>[10:10]</bitRange>
            </field>
            <field>
              <name>CR11</name>
              <description>Cancellation Request</description>
              <bitRange>[11:11]</bitRange>
            </field>
            <field>
              <name>CR12</name>
              <description>Cancellation Request</description>
              <bitRange>[12:12]</bitRange>
            </field>
            <field>
              <name>CR13</name>
              <description>Cancellation Request</description>
              <bitRange>[13:13]</bitRange>
            </field>
            <field>
              <name>CR14</name>
              <description>Cancellation Request</description>
              <bitRange>[14:14]</bitRange>
            </field>
            <field>
              <name>CR15</name>
              <description>Cancellation Request</description>
              <bitRange>[15:15]</bitRange>
            </field>
            <field>
              <name>CR16</name>
              <description>Cancellation Request</description>
              <bitRange>[16:16]</bitRange>
            </field>
            <field>
              <name>CR17</name>
              <description>Cancellation Request</description>
              <bitRange>[17:17]</bitRange>
            </field>
            <field>
              <name>CR18</name>
              <description>Cancellation Request</description>
              <bitRange>[18:18]</bitRange>
            </field>
            <field>
              <name>CR19</name>
              <description>Cancellation Request</description>
              <bitRange>[19:19]</bitRange>
            </field>
            <field>
              <name>CR20</name>
              <description>Cancellation Request</description>
              <bitRange>[20:20]</bitRange>
            </field>
            <field>
              <name>CR21</name>
              <description>Cancellation Request</description>
              <bitRange>[21:21]</bitRange>
            </field>
            <field>
              <name>CR22</name>
              <description>Cancellation Request</description>
              <bitRange>[22:22]</bitRange>
            </field>
            <field>
              <name>CR23</name>
              <description>Cancellation Request</description>
              <bitRange>[23:23]</bitRange>
            </field>
            <field>
              <name>CR24</name>
              <description>Cancellation Request</description>
              <bitRange>[24:24]</bitRange>
            </field>
            <field>
              <name>CR25</name>
              <description>Cancellation Request</description>
              <bitRange>[25:25]</bitRange>
            </field>
            <field>
              <name>CR26</name>
              <description>Cancellation Request</description>
              <bitRange>[26:26]</bitRange>
            </field>
            <field>
              <name>CR27</name>
              <description>Cancellation Request</description>
              <bitRange>[27:27]</bitRange>
            </field>
            <field>
              <name>CR28</name>
              <description>Cancellation Request</description>
              <bitRange>[28:28]</bitRange>
            </field>
            <field>
              <name>CR29</name>
              <description>Cancellation Request</description>
              <bitRange>[29:29]</bitRange>
            </field>
            <field>
              <name>CR30</name>
              <description>Cancellation Request</description>
              <bitRange>[30:30]</bitRange>
            </field>
            <field>
              <name>CR31</name>
              <description>Cancellation Request</description>
              <bitRange>[31:31]</bitRange>
            </field>
          </fields>
        </register>
        <register>
          <name>TXBTO</name>
          <addressOffset>0xD8</addressOffset>
          <fields>
            <field>
              <name>TO0</name>
              <description>Transmission Occurred</description>
              <bitRange>[0:0]</bitRange>
              <access>read-only</access>
            </field>
            <field>
              <name>TO1</name>
              <description>Transmission Occurred</description>
              <bitRange>[1:1]</bitRange>
              <access>read-only</access>
            </field>
            <field>
              <name>TO2</name>
              <description>Transmission Occurred</description>
              <bitRange>[2:2]</bitRange>
              <access>read-only</access>
            </field>
            <field>
              <name>TO3</name>
              <description>Transmission Occurred</description>
              <bitRange>[3:3]</bitRange>
              <access>read-only</access>
            </field>
            <field>
              <name>TO4</name>
              <description>Transmission Occurred</description>
              <bitRange>[4:4]</bitRange>
              <access>read-only</access>
            </field>
            <field>
              <name>TO5</name>
              <description>Transmission Occurred</description>
              <bitRange>[5:5]</bitRange>
              <access>read-only</access>
            </field>
            <field>
              <name>TO6</name>
              <description>Transmission Occurred</description>
              <bitRange>[6:6]</bitRange>
              <access>read-only</access>
            </field>
            <field>
              <name>TO7</name>
              <description>Transmission Occurred</description>
              <bitRange>[7:7]</bitRange>
              <access>read-only</access>
            </field>
            <field>
              <name>TO8</name>
              <description>Transmission Occurred</description>
              <bitRange>[8:8]</bitRange>
              <access>read-only</access>
            </field>
            <field>
              <name>TO9</name>
              <description>Transmission Occurred</description>
              <bitRange>[9:9]</bitRange>
              <access>read-only</access>
            </field>
            <field>
              <name>TO10</name>
              <description>Transmission Occurred</description>
              <bitRange>[10:10]</bitRange>
              <access>read-only</access>
            </field>
            <field>
              <name>TO11</name>
              <description>Transmission Occurred</description>
              <bitRange>[11:11]</bitRange>
              <access>read-only</access>
            </field>
            <field>
              <name>TO12</name>
              <description>Transmission Occurred</description>
              <bitRange>[12:12]</bitRange>
              <access>read-only</access>
            </field>
            <field>
              <name>TO13</name>
              <description>Transmission Occurred</description>
              <bitRange>[13:13]</bitRange>
              <access>read-only</access>
            </field>
            <field>
              <name>TO14</name>
              <description>Transmission Occurred</description>
              <bitRange>[14:14]</bitRange>
              <access>read-only</access>
            </field>
            <field>
              <name>TO15</name>
              <description>Transmission Occurred</description>
              <bitRange>[15:15]</bitRange>
              <access>read-only</access>
            </field>
            <field>
              <name>TO16</name>
              <description>Transmission Occurred</description>
              <bitRange>[16:16]</bitRange>
              <access>read-only</access>
            </field>
            <field>
              <name>TO17</name>
              <description>Transmission Occurred</description>
              <bitRange>[17:17]</bitRange>
              <access>read-only</access>
            </field>
            <field>
              <name>TO18</name>
              <description>Transmission Occurred</description>
              <bitRange>[18:18]</bitRange>
              <access>read-only</access>
            </field>
            <field>
              <name>TO19</name>
              <description>Transmission Occurred</description>
              <bitRange>[19:19]</bitRange>
              <access>read-only</access>
            </field>
            <field>
              <name>TO20</name>
              <description>Transmission Occurred</description>
              <bitRange>[20:20]</bitRange>
              <access>read-only</access>
            </field>
            <field>
              <name>TO21</name>
              <description>Transmission Occurred</description>
              <bitRange>[21:21]</bitRange>
              <access>read-only</access>
            </field>
            <field>
              <name>TO22</name>
              <description>Transmission Occurred</description>
              <bitRange>[22:22]</bitRange>
              <access>read-only</access>
            </field>
            <field>
              <name>TO23</name>
              <description>Transmission Occurred</description>
              <bitRange>[23:23]</bitRange>
              <access>read-only</access>
            </field>
            <field>
              <name>TO24</name>
              <description>Transmission Occurred</description>
              <bitRange>[24:24]</bitRange>
              <access>read-only</access>
            </field>
            <field>
              <name>TO25</name>
              <description>Transmission Occurred</description>
              <bitRange>[25:25]</bitRange>
              <access>read-only</access>
            </field>
            <field>
              <name>TO26</name>
              <description>Transmission Occurred</description>
              <bitRange>[26:26]</bitRange>
              <access>read-only</access>
            </field>
            <field>
              <name>TO27</name>
              <description>Transmission Occurred</description>
              <bitRange>[27:27]</bitRange>
              <access>read-only</access>
            </field>
            <field>
              <name>TO28</name>
              <description>Transmission Occurred</description>
              <bitRange>[28:28]</bitRange>
              <access>read-only</access>
            </field>
            <field>
              <name>TO29</name>
              <description>Transmission Occurred</description>
              <bitRange>[29:29]</bitRange>
              <access>read-only</access>
            </field>
            <field>
              <name>TO30</name>
              <description>Transmission Occurred</description>
              <bitRange>[30:30]</bitRange>
              <access>read-only</access>
            </field>
            <field>
              <name>TO31</name>
              <description>Transmission Occurred</description>
              <bitRange>[31:31]</bitRange>
              <access>read-only</access>
            </field>
          </fields>
        </register>
        <register>
          <name>TXBCF</name>
          <addressOffset>0xDC</addressOffset>
          <fields>
            <field>
              <name>CF0</name>
              <description>Cancellation Finished</description>
              <bitRange>[0:0]</bitRange>
              <access>read-only</access>
            </field>
            <field>
              <name>CF1</name>
              <description>Cancellation Finished</description>
              <bitRange>[1:1]</bitRange>
              <access>read-only</access>
            </field>
            <field>
              <name>CF2</name>
              <description>Cancellation Finished</description>
              <bitRange>[2:2]</bitRange>
              <access>read-only</access>
            </field>
            <field>
              <name>CF3</name>
              <description>Cancellation Finished</description>
              <bitRange>[3:3]</bitRange>
              <access>read-only</access>
            </field>
            <field>
              <name>CF4</name>
              <description>Cancellation Finished</description>
              <bitRange>[4:4]</bitRange>
              <access>read-only</access>
            </field>
            <field>
              <name>CF5</name>
              <description>Cancellation Finished</description>
              <bitRange>[5:5]</bitRange>
              <access>read-only</access>
            </field>
            <field>
              <name>CF6</name>
              <description>Cancellation Finished</description>
              <bitRange>[6:6]</bitRange>
              <access>read-only</access>
            </field>
            <field>
              <name>CF7</name>
              <description>Cancellation Finished</description>
              <bitRange>[7:7]</bitRange>
              <access>read-only</access>
            </field>
            <field>
              <name>CF8</name>
              <description>Cancellation Finished</description>
              <bitRange>[8:8]</bitRange>
              <access>read-only</access>
            </field>
            <field>
              <name>CF9</name>
              <description>Cancellation Finished</description>
              <bitRange>[9:9]</bitRange>
              <access>read-only</access>
            </field>
            <field>
              <name>CF10</name>
              <description>Cancellation Finished</description>
              <bitRange>[10:10]</bitRange>
              <access>read-only</access>
            </field>
            <field>
              <name>CF11</name>
              <description>Cancellation Finished</description>
              <bitRange>[11:11]</bitRange>
              <access>read-only</access>
            </field>
            <field>
              <name>CF12</name>
              <description>Cancellation Finished</description>
              <bitRange>[12:12]</bitRange>
              <access>read-only</access>
            </field>
            <field>
              <name>CF13</name>
              <description>Cancellation Finished</description>
              <bitRange>[13:13]</bitRange>
              <access>read-only</access>
            </field>
            <field>
              <name>CF14</name>
              <description>Cancellation Finished</description>
              <bitRange>[14:14]</bitRange>
              <access>read-only</access>
            </field>
            <field>
              <name>CF15</name>
              <description>Cancellation Finished</description>
              <bitRange>[15:15]</bitRange>
              <access>read-only</access>
            </field>
            <field>
              <name>CF16</name>
              <description>Cancellation Finished</description>
              <bitRange>[16:16]</bitRange>
              <access>read-only</access>
            </field>
            <field>
              <name>CF17</name>
              <description>Cancellation Finished</description>
              <bitRange>[17:17]</bitRange>
              <access>read-only</access>
            </field>
            <field>
              <name>CF18</name>
              <description>Cancellation Finished</description>
              <bitRange>[18:18]</bitRange>
              <access>read-only</access>
            </field>
            <field>
              <name>CF19</name>
              <description>Cancellation Finished</description>
              <bitRange>[19:19]</bitRange>
              <access>read-only</access>
            </field>
            <field>
              <name>CF20</name>
              <description>Cancellation Finished</description>
              <bitRange>[20:20]</bitRange>
              <access>read-only</access>
            </field>
            <field>
              <name>CF21</name>
              <description>Cancellation Finished</description>
              <bitRange>[21:21]</bitRange>
              <access>read-only</access>
            </field>
            <field>
              <name>CF22</name>
              <description>Cancellation Finished</description>
              <bitRange>[22:22]</bitRange>
              <access>read-only</access>
            </field>
            <field>
              <name>CF23</name>
              <description>Cancellation Finished</description>
              <bitRange>[23:23]</bitRange>
              <access>read-only</access>
            </field>
            <field>
              <name>CF24</name>
              <description>Cancellation Finished</description>
              <bitRange>[24:24]</bitRange>
              <access>read-only</access>
            </field>
            <field>
              <name>CF25</name>
              <description>Cancellation Finished</description>
              <bitRange>[25:25]</bitRange>
              <access>read-only</access>
            </field>
            <field>
              <name>CF26</name>
              <description>Cancellation Finished</description>
              <bitRange>[26:26]</bitRange>
              <access>read-only</access>
            </field>
            <field>
              <name>CF27</name>
              <description>Cancellation Finished</description>
              <bitRange>[27:27]</bitRange>
              <access>read-only</access>
            </field>
            <field>
              <name>CF28</name>
              <description>Cancellation Finished</description>
              <bitRange>[28:28]</bitRange>
              <access>read-only</access>
            </field>
            <field>
              <name>CF29</name>
              <description>Cancellation Finished</description>
              <bitRange>[29:29]</bitRange>
              <access>read-only</access>
            </field>
            <field>
              <name>CF30</name>
              <description>Cancellation Finished</description>
              <bitRange>[30:30]</bitRange>
              <access>read-only</access>
            </field>
            <field>
              <name>CF31</name>
              <description>Cancellation Finished</description>
              <bitRange>[31:31]</bitRange>
              <access>read-only</access>
            </field>
          </fields>
        </register>
        <register>
          <name>TXBTIE</name>
          <addressOffset>0xE0</addressOffset>
          <fields>
            <field>
              <name>TIE0</name>
              <description>Transmission Interrupt Enable</description>
              <bitRange>[0:0]</bitRange>
            </field>
            <field>
              <name>TIE1</name>
              <description>Transmission Interrupt Enable</description>
              <bitRange>[1:1]</bitRange>
            </field>
            <field>
              <name>TIE2</name>
              <description>Transmission Interrupt Enable</description>
              <bitRange>[2:2]</bitRange>
            </field>
            <field>
              <name>TIE3</name>
              <description>Transmission Interrupt Enable</description>
              <bitRange>[3:3]</bitRange>
            </field>
            <field>
              <name>TIE4</name>
              <description>Transmission Interrupt Enable</description>
              <bitRange>[4:4]</bitRange>
            </field>
            <field>
              <name>TIE5</name>
              <description>Transmission Interrupt Enable</description>
              <bitRange>[5:5]</bitRange>
            </field>
            <field>
              <name>TIE6</name>
              <description>Transmission Interrupt Enable</description>
              <bitRange>[6:6]</bitRange>
            </field>
            <field>
              <name>TIE7</name>
              <description>Transmission Interrupt Enable</description>
              <bitRange>[7:7]</bitRange>
            </field>
            <field>
              <name>TIE8</name>
              <description>Transmission Interrupt Enable</description>
              <bitRange>[8:8]</bitRange>
            </field>
            <field>
              <name>TIE9</name>
              <description>Transmission Interrupt Enable</description>
              <bitRange>[9:9]</bitRange>
            </field>
            <field>
              <name>TIE10</name>
              <description>Transmission Interrupt Enable</description>
              <bitRange>[10:10]</bitRange>
            </field>
            <field>
              <name>TIE11</name>
              <description>Transmission Interrupt Enable</description>
              <bitRange>[11:11]</bitRange>
            </field>
            <field>
              <name>TIE12</name>
              <description>Transmission Interrupt Enable</description>
              <bitRange>[12:12]</bitRange>
            </field>
            <field>
              <name>TIE13</name>
              <description>Transmission Interrupt Enable</description>
              <bitRange>[13:13]</bitRange>
            </field>
            <field>
              <name>TIE14</name>
              <description>Transmission Interrupt Enable</description>
              <bitRange>[14:14]</bitRange>
            </field>
            <field>
              <name>TIE15</name>
              <description>Transmission Interrupt Enable</description>
              <bitRange>[15:15]</bitRange>
            </field>
            <field>
              <name>TIE16</name>
              <description>Transmission Interrupt Enable</description>
              <bitRange>[16:16]</bitRange>
            </field>
            <field>
              <name>TIE17</name>
              <description>Transmission Interrupt Enable</description>
              <bitRange>[17:17]</bitRange>
            </field>
            <field>
              <name>TIE18</name>
              <description>Transmission Interrupt Enable</description>
              <bitRange>[18:18]</bitRange>
            </field>
            <field>
              <name>TIE19</name>
              <description>Transmission Interrupt Enable</description>
              <bitRange>[19:19]</bitRange>
            </field>
            <field>
              <name>TIE20</name>
              <description>Transmission Interrupt Enable</description>
              <bitRange>[20:20]</bitRange>
            </field>
            <field>
              <name>TIE21</name>
              <description>Transmission Interrupt Enable</description>
              <bitRange>[21:21]</bitRange>
            </field>
            <field>
              <name>TIE22</name>
              <description>Transmission Interrupt Enable</description>
              <bitRange>[22:22]</bitRange>
            </field>
            <field>
              <name>TIE23</name>
              <description>Transmission Interrupt Enable</description>
              <bitRange>[23:23]</bitRange>
            </field>
            <field>
              <name>TIE24</name>
              <description>Transmission Interrupt Enable</description>
              <bitRange>[24:24]</bitRange>
            </field>
            <field>
              <name>TIE25</name>
              <description>Transmission Interrupt Enable</description>
              <bitRange>[25:25]</bitRange>
            </field>
            <field>
              <name>TIE26</name>
              <description>Transmission Interrupt Enable</description>
              <bitRange>[26:26]</bitRange>
            </field>
            <field>
              <name>TIE27</name>
              <description>Transmission Interrupt Enable</description>
              <bitRange>[27:27]</bitRange>
            </field>
            <field>
              <name>TIE28</name>
              <description>Transmission Interrupt Enable</description>
              <bitRange>[28:28]</bitRange>
            </field>
            <field>
              <name>TIE29</name>
              <description>Transmission Interrupt Enable</description>
              <bitRange>[29:29]</bitRange>
            </field>
            <field>
              <name>TIE30</name>
              <description>Transmission Interrupt Enable</description>
              <bitRange>[30:30]</bitRange>
            </field>
            <field>
              <name>TIE31</name>
              <description>Transmission Interrupt Enable</description>
              <bitRange>[31:31]</bitRange>
            </field>
          </fields>
        </register>
        <register>
          <name>TXBCIE</name>
          <addressOffset>0xE4</addressOffset>
          <fields>
            <field>
              <name>CFIE0</name>
              <description>Cancellation Finished Interrupt Enable</description>
              <bitRange>[0:0]</bitRange>
            </field>
            <field>
              <name>CFIE1</name>
              <description>Cancellation Finished Interrupt Enable</description>
              <bitRange>[1:1]</bitRange>
            </field>
            <field>
              <name>CFIE2</name>
              <description>Cancellation Finished Interrupt Enable</description>
              <bitRange>[2:2]</bitRange>
            </field>
            <field>
              <name>CFIE3</name>
              <description>Cancellation Finished Interrupt Enable</description>
              <bitRange>[3:3]</bitRange>
            </field>
            <field>
              <name>CFIE4</name>
              <description>Cancellation Finished Interrupt Enable</description>
              <bitRange>[4:4]</bitRange>
            </field>
            <field>
              <name>CFIE5</name>
              <description>Cancellation Finished Interrupt Enable</description>
              <bitRange>[5:5]</bitRange>
            </field>
            <field>
              <name>CFIE6</name>
              <description>Cancellation Finished Interrupt Enable</description>
              <bitRange>[6:6]</bitRange>
            </field>
            <field>
              <name>CFIE7</name>
              <description>Cancellation Finished Interrupt Enable</description>
              <bitRange>[7:7]</bitRange>
            </field>
            <field>
              <name>CFIE8</name>
              <description>Cancellation Finished Interrupt Enable</description>
              <bitRange>[8:8]</bitRange>
            </field>
            <field>
              <name>CFIE9</name>
              <description>Cancellation Finished Interrupt Enable</description>
              <bitRange>[9:9]</bitRange>
            </field>
            <field>
              <name>CFIE10</name>
              <description>Cancellation Finished Interrupt Enable</description>
              <bitRange>[10:10]</bitRange>
            </field>
            <field>
              <name>CFIE11</name>
              <description>Cancellation Finished Interrupt Enable</description>
              <bitRange>[11:11]</bitRange>
            </field>
            <field>
              <name>CFIE12</name>
              <description>Cancellation Finished Interrupt Enable</description>
              <bitRange>[12:12]</bitRange>
            </field>
            <field>
              <name>CFIE13</name>
              <description>Cancellation Finished Interrupt Enable</description>
              <bitRange>[13:13]</bitRange>
            </field>
            <field>
              <name>CFIE14</name>
              <description>Cancellation Finished Interrupt Enable</description>
              <bitRange>[14:14]</bitRange>
            </field>
            <field>
              <name>CFIE15</name>
              <description>Cancellation Finished Interrupt Enable</description>
              <bitRange>[15:15]</bitRange>
            </field>
            <field>
              <name>CFIE16</name>
              <description>Cancellation Finished Interrupt Enable</description>
              <bitRange>[16:16]</bitRange>
            </field>
            <field>
              <name>CFIE17</name>
              <description>Cancellation Finished Interrupt Enable</description>
              <bitRange>[17:17]</bitRange>
            </field>
            <field>
              <name>CFIE18</name>
              <description>Cancellation Finished Interrupt Enable</description>
              <bitRange>[18:18]</bitRange>
            </field>
            <field>
              <name>CFIE19</name>
              <description>Cancellation Finished Interrupt Enable</description>
              <bitRange>[19:19]</bitRange>
            </field>
            <field>
              <name>CFIE20</name>
              <description>Cancellation Finished Interrupt Enable</description>
              <bitRange>[20:20]</bitRange>
            </field>
            <field>
              <name>CFIE21</name>
              <description>Cancellation Finished Interrupt Enable</description>
              <bitRange>[21:21]</bitRange>
            </field>
            <field>
              <name>CFIE22</name>
              <description>Cancellation Finished Interrupt Enable</description>
              <bitRange>[22:22]</bitRange>
            </field>
            <field>
              <name>CFIE23</name>
              <description>Cancellation Finished Interrupt Enable</description>
              <bitRange>[23:23]</bitRange>
            </field>
            <field>
              <name>CFIE24</name>
              <description>Cancellation Finished Interrupt Enable</description>
              <bitRange>[24:24]</bitRange>
            </field>
            <field>
              <name>CFIE25</name>
              <description>Cancellation Finished Interrupt Enable</description>
              <bitRange>[25:25]</bitRange>
            </field>
            <field>
              <name>CFIE26</name>
              <description>Cancellation Finished Interrupt Enable</description>
              <bitRange>[26:26]</bitRange>
            </field>
            <field>
              <name>CFIE27</name>
              <description>Cancellation Finished Interrupt Enable</description>
              <bitRange>[27:27]</bitRange>
            </field>
            <field>
              <name>CFIE28</name>
              <description>Cancellation Finished Interrupt Enable</description>
              <bitRange>[28:28]</bitRange>
            </field>
            <field>
              <name>CFIE29</name>
              <description>Cancellation Finished Interrupt Enable</description>
              <bitRange>[29:29]</bitRange>
            </field>
            <field>
              <name>CFIE30</name>
              <description>Cancellation Finished Interrupt Enable</description>
              <bitRange>[30:30]</bitRange>
            </field>
            <field>
              <name>CFIE31</name>
              <description>Cancellation Finished Interrupt Enable</description>
              <bitRange>[31:31]</bitRange>
            </field>
          </fields>
        </register>
        <register>
          <name>TXEFC</name>
          <addressOffset>0xF0</addressOffset>
          <fields>
            <field>
              <name>EFSA</name>
              <description>Event FIFO Start Address</description>
              <bitRange>[15:2]</bitRange>
              <access>read-only</access>
            </field>
            <field>
              <name>EFS</name>
              <description>Event FIFO Size</description>
              <bitRange>[21:16]</bitRange>
              <access>read-only</access>
            </field>
            <field>
              <name>EFWM</name>
              <description>Event FIFO Watermark</description>
              <bitRange>[29:24]</bitRange>
              <access>read-only</access>
            </field>
          </fields>
        </register>
        <register>
          <name>TXEFS</name>
          <addressOffset>0xF4</addressOffset>
          <fields>
            <field>
              <name>EFFL</name>
              <description>Event FIFO Fill Level</description>
              <bitRange>[5:0]</bitRange>
              <access>read-only</access>
            </field>
            <field>
              <name>EFGI</name>
              <description>Event FIFO Get Index</description>
              <bitRange>[12:8]</bitRange>
              <access>read-only</access>
            </field>
            <field>
              <name>EFPI</name>
              <description>Event FIFO Put Index</description>
              <bitRange>[20:16]</bitRange>
              <access>read-only</access>
            </field>
            <field>
              <name>EFF</name>
              <description>Event FIFO Full</description>
              <bitRange>[24:24]</bitRange>
              <access>read-only</access>
            </field>
            <field>
              <name>TEFL</name>
              <description>Tx Event FIFO Element Lost</description>
              <bitRange>[25:25]</bitRange>
              <access>read-only</access>
            </field>
          </fields>
        </register>
        <register>
          <name>TXEFA</name>
          <addressOffset>0xF8</addressOffset>
          <fields>
            <field>
              <name>EFAI</name>
              <description>Event FIFO Acknowledge Index</description>
              <bitRange>[4:0]</bitRange>
            </field>
          </fields>
        </register>
      </registers>
    </peripheral>
    <peripheral>
      <name>FLASH</name>
      <baseAddress>0x40022000</baseAddress>
      <addressBlock>
        <offset>0x0</offset>
        <size>0x120</size>
        <usage>registers</usage>
      </addressBlock>
      <interrupt>
        <name>FLASH</name>
        <description>FLASH global Interrupt</description>
        <value>4</value>
      </interrupt>
      <registers>
        <register>
          <name>ACR</name>
          <addressOffset>0x0</addressOffset>
          <fields>
            <field>
              <name>LATENCY</name>
              <description>Latency</description>
              <bitRange>[3:0]</bitRange>
            </field>
            <field>
              <name>PRFTEN</name>
              <bitRange>[8:8]</bitRange>
            </field>
            <field>
              <name>ICEN</name>
              <bitRange>[9:9]</bitRange>
            </field>
            <field>
              <name>DCEN</name>
              <bitRange>[10:10]</bitRange>
            </field>
          </fields>
        </register>
        <register>
          <name>KEYR</name>
          <addressOffset>0x8</addressOffset>
          <fields>
            <field>
              <name>KEY</name>
              <description>Flash CR key</description>
              <bitRange>[31:0]</bitRange>
              <access>write-only</access>
            </field>
          </fields>
        </register>
        <register>
          <name>OPTKEYR</name>
          <addressOffset>0xC</addressOffset>
          <fields>
            <field>
              <name>OPTKEY</name>
              <description>Flash Option key</description>
              <bitRange>[31:0]</bitRange>
              <access>write-only</access>
            </field>
          </fields>
        </register>
        <register>
          <name>SR</name>
          <addressOffset>0x10</addressOffset>
          <fields>
            <field>
              <name>EOP</name>
              <description>End of operation</description>
              <bitRange>[0:0]</bitRange>
            </field>
            <field>
              <name>WRPERR</name>
              <description>Write protection error</description>
              <bitRange>[4:4]</bitRange>
            </field>
            <field>
              <name>RDERR</name>
              <description>bank0 read error</description>
              <bitRange>[11:11]</bitRange>
            </field>
            <field>
              <name>OPTVERR</name>
              <description>Option and trimming bits loading validity error</description>
              <bitRange>[15:15]</bitRange>
            </field>
            <field>
              <name>BSY0</name>
              <description>Bank0 Busy</description>
              <bitRange>[16:16]</bitRange>
              <access>read-only</access>
            </field>
            <field>
              <name>BSY1</name>
              <description>Bank1 Busy</description>
              <bitRange>[17:17]</bitRange>
              <access>read-only</access>
            </field>
            <field>
              <name>USRLOCK0</name>
              <description>Userdata Lock</description>
              <bitRange>[31:31]</bitRange>
              <access>read-only</access>
            </field>
          </fields>
        </register>
        <register>
          <name>CR</name>
          <addressOffset>0x14</addressOffset>
          <fields>
            <field>
              <name>PG</name>
              <description>Page Program</description>
              <bitRange>[0:0]</bitRange>
            </field>
            <field>
              <name>PER</name>
              <description>Page Erase</description>
              <bitRange>[1:1]</bitRange>
            </field>
            <field>
              <name>MER</name>
              <description>Bank 0 Mass Erase</description>
              <bitRange>[2:2]</bitRange>
            </field>
            <field>
              <name>UPG</name>
              <description>User data page Program</description>
              <bitRange>[4:4]</bitRange>
            </field>
            <field>
              <name>UPER</name>
              <description>User data Page erase</description>
              <bitRange>[5:5]</bitRange>
            </field>
            <field>
              <name>SER</name>
              <description>Sector Erase</description>
              <bitRange>[11:11]</bitRange>
            </field>
            <field>
              <name>OPTSTRT</name>
              <description>Option bytes Programming Start</description>
              <bitRange>[17:17]</bitRange>
            </field>
            <field>
              <name>PGSTRT</name>
              <description>Programming Start</description>
              <bitRange>[19:19]</bitRange>
            </field>
            <field>
              <name>RDERRIE</name>
              <description>bank1 read error</description>
              <bitRange>[22:22]</bitRange>
            </field>
            <field>
              <name>EOPIE</name>
              <description>End of operation interrupt enable</description>
              <bitRange>[24:24]</bitRange>
            </field>
            <field>
              <name>ERRIE</name>
              <description>Error interrupt enable</description>
              <bitRange>[25:25]</bitRange>
            </field>
            <field>
              <name>OBL_LAUNCH</name>
              <description>Force the option bytes loading</description>
              <bitRange>[27:27]</bitRange>
            </field>
            <field>
              <name>SECPROT0</name>
              <description>bank0 sec protect</description>
              <bitRange>[28:28]</bitRange>
            </field>
            <field>
              <name>SECPROT1</name>
              <description>bank1 sec protect</description>
              <bitRange>[29:29]</bitRange>
            </field>
            <field>
              <name>OPTLOCK</name>
              <description>Option Lock</description>
              <bitRange>[30:30]</bitRange>
            </field>
            <field>
              <name>LOCK</name>
              <description>Lock</description>
              <bitRange>[31:31]</bitRange>
            </field>
          </fields>
        </register>
        <register>
          <name>OPTR1</name>
          <addressOffset>0x20</addressOffset>
          <fields>
            <field>
              <name>RDP</name>
              <description>Read Protection</description>
              <bitRange>[7:0]</bitRange>
            </field>
            <field>
              <name>NRST_STDBY</name>
              <bitRange>[8:8]</bitRange>
            </field>
            <field>
              <name>NRST_STOP</name>
              <bitRange>[9:9]</bitRange>
            </field>
            <field>
              <name>NRST_MODE</name>
              <bitRange>[11:10]</bitRange>
            </field>
            <field>
              <name>IWDG_STDBY</name>
              <bitRange>[12:12]</bitRange>
            </field>
            <field>
              <name>IWDG_STOP</name>
              <bitRange>[13:13]</bitRange>
            </field>
            <field>
              <name>IWDG_SW</name>
              <description>IWDG Software Enable</description>
              <bitRange>[14:14]</bitRange>
            </field>
            <field>
              <name>WWDG_SW</name>
              <bitRange>[15:15]</bitRange>
            </field>
            <field>
              <name>NBOOT0</name>
              <bitRange>[16:16]</bitRange>
            </field>
            <field>
              <name>NBOOT1</name>
              <bitRange>[17:17]</bitRange>
            </field>
            <field>
              <name>NSWBOOT0</name>
              <bitRange>[18:18]</bitRange>
            </field>
            <field>
              <name>BFB</name>
              <bitRange>[19:19]</bitRange>
            </field>
            <field>
              <name>BOOT_LOCK</name>
              <bitRange>[20:20]</bitRange>
              <access>read-only</access>
            </field>
          </fields>
        </register>
        <register>
          <name>OPTR2</name>
          <addressOffset>0x24</addressOffset>
          <fields>
            <field>
              <name>ACC_CTRL</name>
              <bitRange>[2:0]</bitRange>
            </field>
            <field>
              <name>PLL_UNLOCK</name>
              <bitRange>[3:3]</bitRange>
            </field>
          </fields>
        </register>
        <register>
          <name>WRPR0</name>
          <addressOffset>0x28</addressOffset>
          <fields>
            <field>
              <name>BANK0_WRPR</name>
              <description>Write Protection Disable</description>
              <bitRange>[15:0]</bitRange>
            </field>
          </fields>
        </register>
        <register>
          <name>PCROPR0</name>
          <addressOffset>0x2C</addressOffset>
          <fields>
            <field>
              <name>PCROP0SR</name>
              <bitRange>[8:0]</bitRange>
            </field>
            <field>
              <name>PCROP0ER</name>
              <bitRange>[24:16]</bitRange>
            </field>
          </fields>
        </register>
        <register>
          <name>SECR0</name>
          <addressOffset>0x30</addressOffset>
          <fields>
            <field>
              <name>SEC_SIZEER0</name>
              <bitRange>[24:16]</bitRange>
            </field>
          </fields>
        </register>
        <register>
          <name>WRPR1</name>
          <addressOffset>0x34</addressOffset>
          <fields>
            <field>
              <name>BANK0_WRPR</name>
              <description>Write Protection Disable</description>
              <bitRange>[15:0]</bitRange>
            </field>
          </fields>
        </register>
        <register>
          <name>PCROPR1</name>
          <addressOffset>0x38</addressOffset>
          <fields>
            <field>
              <name>PCROP1SR</name>
              <bitRange>[8:0]</bitRange>
            </field>
            <field>
              <name>PCROP1ER</name>
              <bitRange>[24:16]</bitRange>
            </field>
          </fields>
        </register>
        <register>
          <name>SECR1</name>
          <addressOffset>0x3C</addressOffset>
          <fields>
            <field>
              <name>SEC_SIZEER1</name>
              <bitRange>[24:16]</bitRange>
            </field>
          </fields>
        </register>
        <register>
          <name>TS0</name>
          <addressOffset>0x100</addressOffset>
          <fields>
            <field>
              <name>TS0</name>
              <bitRange>[6:0]</bitRange>
            </field>
          </fields>
        </register>
        <register>
          <name>TS1</name>
          <addressOffset>0x104</addressOffset>
          <fields>
            <field>
              <name>TS1</name>
              <bitRange>[6:0]</bitRange>
            </field>
          </fields>
        </register>
        <register>
          <name>TS2P</name>
          <addressOffset>0x108</addressOffset>
          <fields>
            <field>
              <name>TS2P</name>
              <bitRange>[6:0]</bitRange>
            </field>
          </fields>
        </register>
        <register>
          <name>TPS3</name>
          <addressOffset>0x10C</addressOffset>
          <fields>
            <field>
              <name>TPS3</name>
              <bitRange>[8:0]</bitRange>
            </field>
          </fields>
        </register>
        <register>
          <name>TS3</name>
          <addressOffset>0x110</addressOffset>
          <fields>
            <field>
              <name>TS3</name>
              <bitRange>[6:0]</bitRange>
            </field>
          </fields>
        </register>
        <register>
          <name>ERSTPE</name>
          <addressOffset>0x114</addressOffset>
          <fields>
            <field>
              <name>ERSTPE</name>
              <bitRange>[14:0]</bitRange>
            </field>
          </fields>
        </register>
        <register>
          <name>PRGTPE</name>
          <addressOffset>0x118</addressOffset>
          <fields>
            <field>
              <name>PRGTPE</name>
              <bitRange>[14:0]</bitRange>
            </field>
          </fields>
        </register>
        <register>
          <name>PRETPE</name>
          <addressOffset>0x11C</addressOffset>
          <fields>
            <field>
              <name>PRETPE</name>
              <bitRange>[11:0]</bitRange>
            </field>
          </fields>
        </register>
      </registers>
    </peripheral>
    <peripheral>
      <name>GPIOA</name>
      <baseAddress>0x40024000</baseAddress>
      <addressBlock>
        <offset>0x0</offset>
        <size>0x30</size>
        <usage>registers</usage>
      </addressBlock>
      <registers>
        <register>
          <name>MODER</name>
          <addressOffset>0x0</addressOffset>
          <fields>
            <field>
              <name>MODER0</name>
              <description>GPIOA0 MODE</description>
              <bitRange>[1:0]</bitRange>
            </field>
            <field>
              <name>MODER1</name>
              <description>GPIOA1 MODE</description>
              <bitRange>[3:2]</bitRange>
            </field>
            <field>
              <name>MODER2</name>
              <description>GPIOA2 MODE</description>
              <bitRange>[5:4]</bitRange>
            </field>
            <field>
              <name>MODER3</name>
              <description>GPIOA3 MODE</description>
              <bitRange>[7:6]</bitRange>
            </field>
            <field>
              <name>MODER4</name>
              <description>GPIOA4 MODE</description>
              <bitRange>[9:8]</bitRange>
            </field>
            <field>
              <name>MODER5</name>
              <description>GPIOA5 MODE</description>
              <bitRange>[11:10]</bitRange>
            </field>
            <field>
              <name>MODER6</name>
              <description>GPIOA6 MODE</description>
              <bitRange>[13:12]</bitRange>
            </field>
            <field>
              <name>MODER7</name>
              <description>GPIOA7 MODE</description>
              <bitRange>[15:14]</bitRange>
            </field>
            <field>
              <name>MODER8</name>
              <description>GPIOA8 MODE</description>
              <bitRange>[17:16]</bitRange>
            </field>
            <field>
              <name>MODER9</name>
              <description>GPIOA9 MODE</description>
              <bitRange>[19:18]</bitRange>
            </field>
            <field>
              <name>MODER10</name>
              <description>GPIOA10 MODE</description>
              <bitRange>[21:20]</bitRange>
            </field>
            <field>
              <name>MODER11</name>
              <description>GPIOA11 MODE</description>
              <bitRange>[23:22]</bitRange>
            </field>
            <field>
              <name>MODER12</name>
              <description>GPIOA12 MODE</description>
              <bitRange>[25:24]</bitRange>
            </field>
            <field>
              <name>MODER13</name>
              <description>GPIOA13 MODE</description>
              <bitRange>[27:26]</bitRange>
            </field>
            <field>
              <name>MODER14</name>
              <description>GPIOA14 MODE</description>
              <bitRange>[29:28]</bitRange>
            </field>
            <field>
              <name>MODER15</name>
              <description>GPIOA15 MODE</description>
              <bitRange>[31:30]</bitRange>
            </field>
          </fields>
        </register>
        <register>
          <name>OTYPER</name>
          <addressOffset>0x4</addressOffset>
          <fields>
            <field>
              <name>OT0</name>
              <description>GPIOA0 Output type</description>
              <bitRange>[0:0]</bitRange>
            </field>
            <field>
              <name>OT1</name>
              <description>GPIOA1 Output type</description>
              <bitRange>[1:1]</bitRange>
            </field>
            <field>
              <name>OT2</name>
              <description>GPIOA2 Output type</description>
              <bitRange>[2:2]</bitRange>
            </field>
            <field>
              <name>OT3</name>
              <description>GPIOA3 Output type</description>
              <bitRange>[3:3]</bitRange>
            </field>
            <field>
              <name>OT4</name>
              <description>GPIOA4 Output type</description>
              <bitRange>[4:4]</bitRange>
            </field>
            <field>
              <name>OT5</name>
              <description>GPIOA5 Output type</description>
              <bitRange>[5:5]</bitRange>
            </field>
            <field>
              <name>OT6</name>
              <description>GPIOA6 Output type</description>
              <bitRange>[6:6]</bitRange>
            </field>
            <field>
              <name>OT7</name>
              <description>GPIOA7 Output type</description>
              <bitRange>[7:7]</bitRange>
            </field>
            <field>
              <name>OT8</name>
              <description>GPIOA8 Output type</description>
              <bitRange>[8:8]</bitRange>
            </field>
            <field>
              <name>OT9</name>
              <description>GPIOA9 Output type</description>
              <bitRange>[9:9]</bitRange>
            </field>
            <field>
              <name>OT10</name>
              <description>GPIOA10 Output type</description>
              <bitRange>[10:10]</bitRange>
            </field>
            <field>
              <name>OT11</name>
              <description>GPIOA11 Output type</description>
              <bitRange>[11:11]</bitRange>
            </field>
            <field>
              <name>OT12</name>
              <description>GPIOA12 Output type</description>
              <bitRange>[12:12]</bitRange>
            </field>
            <field>
              <name>OT13</name>
              <description>GPIOA13 Output type</description>
              <bitRange>[13:13]</bitRange>
            </field>
            <field>
              <name>OT14</name>
              <description>GPIOA14 Output type</description>
              <bitRange>[14:14]</bitRange>
            </field>
            <field>
              <name>OT15</name>
              <description>GPIOA15 Output type</description>
              <bitRange>[15:15]</bitRange>
            </field>
          </fields>
        </register>
        <register>
          <name>OSPDDER</name>
          <addressOffset>0x8</addressOffset>
          <fields>
            <field>
              <name>OSPEED0</name>
              <description>GPIOA0 output speed</description>
              <bitRange>[1:0]</bitRange>
            </field>
            <field>
              <name>OSPEED1</name>
              <description>GPIOA1 output speed</description>
              <bitRange>[3:2]</bitRange>
            </field>
            <field>
              <name>OSPEED2</name>
              <description>GPIOA2 output speed</description>
              <bitRange>[5:4]</bitRange>
            </field>
            <field>
              <name>OSPEED3</name>
              <description>GPIOA3 output speed</description>
              <bitRange>[7:6]</bitRange>
            </field>
            <field>
              <name>OSPEED4</name>
              <description>GPIOA4 output speed</description>
              <bitRange>[9:8]</bitRange>
            </field>
            <field>
              <name>OSPEED5</name>
              <description>GPIOA5 output speed</description>
              <bitRange>[11:10]</bitRange>
            </field>
            <field>
              <name>OSPEED6</name>
              <description>GPIOA6 output speed</description>
              <bitRange>[13:12]</bitRange>
            </field>
            <field>
              <name>OSPEED7</name>
              <description>GPIOA7 output speed</description>
              <bitRange>[15:14]</bitRange>
            </field>
            <field>
              <name>OSPEED8</name>
              <description>GPIOA8 output speed</description>
              <bitRange>[17:16]</bitRange>
            </field>
            <field>
              <name>OSPEED9</name>
              <description>GPIOA9 output speed</description>
              <bitRange>[19:18]</bitRange>
            </field>
            <field>
              <name>OSPEED10</name>
              <description>GPIOA10 output speed</description>
              <bitRange>[21:20]</bitRange>
            </field>
            <field>
              <name>OSPEED11</name>
              <description>GPIOA11 output speed</description>
              <bitRange>[23:22]</bitRange>
            </field>
            <field>
              <name>OSPEED12</name>
              <description>GPIOA12 output speed</description>
              <bitRange>[25:24]</bitRange>
            </field>
            <field>
              <name>OSPEED13</name>
              <description>GPIOA13 output speed</description>
              <bitRange>[27:26]</bitRange>
            </field>
            <field>
              <name>OSPEED14</name>
              <description>GPIOA14 output speed</description>
              <bitRange>[29:28]</bitRange>
            </field>
            <field>
              <name>OSPEED15</name>
              <description>GPIOA15 output speed</description>
              <bitRange>[31:30]</bitRange>
            </field>
          </fields>
        </register>
        <register>
          <name>PUPDR</name>
          <addressOffset>0xC</addressOffset>
          <fields>
            <field>
              <name>PUPD0</name>
              <description>GPIOA0 pull up/pull down</description>
              <bitRange>[1:0]</bitRange>
            </field>
            <field>
              <name>PUPD1</name>
              <description>GPIOA1 pull up/pull down</description>
              <bitRange>[3:2]</bitRange>
            </field>
            <field>
              <name>PUPD2</name>
              <description>GPIOA2 pull up/pull down</description>
              <bitRange>[5:4]</bitRange>
            </field>
            <field>
              <name>PUPD3</name>
              <description>GPIOA3 pull up/pull down</description>
              <bitRange>[7:6]</bitRange>
            </field>
            <field>
              <name>PUPD4</name>
              <description>GPIOA4 pull up/pull down</description>
              <bitRange>[9:8]</bitRange>
            </field>
            <field>
              <name>PUPD5</name>
              <description>GPIOA5 pull up/pull down</description>
              <bitRange>[11:10]</bitRange>
            </field>
            <field>
              <name>PUPD6</name>
              <description>GPIOA6 pull up/pull down</description>
              <bitRange>[13:12]</bitRange>
            </field>
            <field>
              <name>PUPD7</name>
              <description>GPIOA7 pull up/pull down</description>
              <bitRange>[15:14]</bitRange>
            </field>
            <field>
              <name>PUPD8</name>
              <description>GPIOA8 pull up/pull down</description>
              <bitRange>[17:16]</bitRange>
            </field>
            <field>
              <name>PUPD9</name>
              <description>GPIOA9 pull up/pull down</description>
              <bitRange>[19:18]</bitRange>
            </field>
            <field>
              <name>PUPD10</name>
              <description>GPIOA10 pull up/pull down</description>
              <bitRange>[21:20]</bitRange>
            </field>
            <field>
              <name>PUPD11</name>
              <description>GPIOA11 pull up/pull down</description>
              <bitRange>[23:22]</bitRange>
            </field>
            <field>
              <name>PUPD12</name>
              <description>GPIOA12 pull up/pull down</description>
              <bitRange>[25:24]</bitRange>
            </field>
            <field>
              <name>PUPD13</name>
              <description>GPIOA13 pull up/pull down</description>
              <bitRange>[27:26]</bitRange>
            </field>
            <field>
              <name>PUPD14</name>
              <description>GPIOA14 pull up/pull down</description>
              <bitRange>[29:28]</bitRange>
            </field>
            <field>
              <name>PUPD15</name>
              <description>GPIOA15 pull up/pull down</description>
              <bitRange>[31:30]</bitRange>
            </field>
          </fields>
        </register>
        <register>
          <name>IDR</name>
          <addressOffset>0x10</addressOffset>
          <fields>
            <field>
              <name>ID0</name>
              <description>GPIOA0 input data</description>
              <bitRange>[0:0]</bitRange>
              <access>read-only</access>
            </field>
            <field>
              <name>ID1</name>
              <description>GPIOA1 input data</description>
              <bitRange>[1:1]</bitRange>
              <access>read-only</access>
            </field>
            <field>
              <name>ID2</name>
              <description>GPIOA2 input data</description>
              <bitRange>[2:2]</bitRange>
              <access>read-only</access>
            </field>
            <field>
              <name>ID3</name>
              <description>GPIOA3 input data</description>
              <bitRange>[3:3]</bitRange>
              <access>read-only</access>
            </field>
            <field>
              <name>ID4</name>
              <description>GPIOA4 input data</description>
              <bitRange>[4:4]</bitRange>
              <access>read-only</access>
            </field>
            <field>
              <name>ID5</name>
              <description>GPIOA5 input data</description>
              <bitRange>[5:5]</bitRange>
              <access>read-only</access>
            </field>
            <field>
              <name>ID6</name>
              <description>GPIOA6 input data</description>
              <bitRange>[6:6]</bitRange>
              <access>read-only</access>
            </field>
            <field>
              <name>ID7</name>
              <description>GPIOA7 input data</description>
              <bitRange>[7:7]</bitRange>
              <access>read-only</access>
            </field>
            <field>
              <name>ID8</name>
              <description>GPIOA8 input data</description>
              <bitRange>[8:8]</bitRange>
              <access>read-only</access>
            </field>
            <field>
              <name>ID9</name>
              <description>GPIOA9 input data</description>
              <bitRange>[9:9]</bitRange>
              <access>read-only</access>
            </field>
            <field>
              <name>ID10</name>
              <description>GPIOA10 input data</description>
              <bitRange>[10:10]</bitRange>
              <access>read-only</access>
            </field>
            <field>
              <name>ID11</name>
              <description>GPIOA11 input data</description>
              <bitRange>[11:11]</bitRange>
              <access>read-only</access>
            </field>
            <field>
              <name>ID12</name>
              <description>GPIOA12 input data</description>
              <bitRange>[12:12]</bitRange>
              <access>read-only</access>
            </field>
            <field>
              <name>ID13</name>
              <description>GPIOA13 input data</description>
              <bitRange>[13:13]</bitRange>
              <access>read-only</access>
            </field>
            <field>
              <name>ID14</name>
              <description>GPIOA14 input data</description>
              <bitRange>[14:14]</bitRange>
              <access>read-only</access>
            </field>
            <field>
              <name>ID15</name>
              <description>GPIOA15 input data</description>
              <bitRange>[15:15]</bitRange>
              <access>read-only</access>
            </field>
          </fields>
        </register>
        <register>
          <name>ODR</name>
          <addressOffset>0x14</addressOffset>
          <fields>
            <field>
              <name>OD0</name>
              <description>GPIOA0 output data</description>
              <bitRange>[0:0]</bitRange>
            </field>
            <field>
              <name>OD1</name>
              <description>GPIOA1 output data</description>
              <bitRange>[1:1]</bitRange>
            </field>
            <field>
              <name>OD2</name>
              <description>GPIOA2 output data</description>
              <bitRange>[2:2]</bitRange>
            </field>
            <field>
              <name>OD3</name>
              <description>GPIOA3 output data</description>
              <bitRange>[3:3]</bitRange>
            </field>
            <field>
              <name>OD4</name>
              <description>GPIOA4 output data</description>
              <bitRange>[4:4]</bitRange>
            </field>
            <field>
              <name>OD5</name>
              <description>GPIOA5 output data</description>
              <bitRange>[5:5]</bitRange>
            </field>
            <field>
              <name>OD6</name>
              <description>GPIOA6 output data</description>
              <bitRange>[6:6]</bitRange>
            </field>
            <field>
              <name>OD7</name>
              <description>GPIOA7 output data</description>
              <bitRange>[7:7]</bitRange>
            </field>
            <field>
              <name>OD8</name>
              <description>GPIOA8 output data</description>
              <bitRange>[8:8]</bitRange>
            </field>
            <field>
              <name>OD9</name>
              <description>GPIOA9 output data</description>
              <bitRange>[9:9]</bitRange>
            </field>
            <field>
              <name>OD10</name>
              <description>GPIOA10 output data</description>
              <bitRange>[10:10]</bitRange>
            </field>
            <field>
              <name>OD11</name>
              <description>GPIOA11 output data</description>
              <bitRange>[11:11]</bitRange>
            </field>
            <field>
              <name>OD12</name>
              <description>GPIOA12 output data</description>
              <bitRange>[12:12]</bitRange>
            </field>
            <field>
              <name>OD13</name>
              <description>GPIOA13 output data</description>
              <bitRange>[13:13]</bitRange>
            </field>
            <field>
              <name>OD14</name>
              <description>GPIOA14 output data</description>
              <bitRange>[14:14]</bitRange>
            </field>
            <field>
              <name>OD15</name>
              <description>GPIOA15 output data</description>
              <bitRange>[15:15]</bitRange>
            </field>
          </fields>
        </register>
        <register>
          <name>BSRR</name>
          <addressOffset>0x18</addressOffset>
          <fields>
            <field>
              <name>BS0</name>
              <description>GPIOA0 output set</description>
              <bitRange>[0:0]</bitRange>
            </field>
            <field>
              <name>BS1</name>
              <description>GPIOA1 output set</description>
              <bitRange>[1:1]</bitRange>
            </field>
            <field>
              <name>BS2</name>
              <description>GPIOA2 output set</description>
              <bitRange>[2:2]</bitRange>
            </field>
            <field>
              <name>BS3</name>
              <description>GPIOA3 output set</description>
              <bitRange>[3:3]</bitRange>
            </field>
            <field>
              <name>BS4</name>
              <description>GPIOA4 output set</description>
              <bitRange>[4:4]</bitRange>
            </field>
            <field>
              <name>BS5</name>
              <description>GPIOA5 output set</description>
              <bitRange>[5:5]</bitRange>
            </field>
            <field>
              <name>BS6</name>
              <description>GPIOA6 output set</description>
              <bitRange>[6:6]</bitRange>
            </field>
            <field>
              <name>BS7</name>
              <description>GPIOA7 output set</description>
              <bitRange>[7:7]</bitRange>
            </field>
            <field>
              <name>BS8</name>
              <description>GPIOA8 output set</description>
              <bitRange>[8:8]</bitRange>
            </field>
            <field>
              <name>BS9</name>
              <description>GPIOA9 output set</description>
              <bitRange>[9:9]</bitRange>
            </field>
            <field>
              <name>BS10</name>
              <description>GPIOA10 output set</description>
              <bitRange>[10:10]</bitRange>
            </field>
            <field>
              <name>BS11</name>
              <description>GPIOA11 output set</description>
              <bitRange>[11:11]</bitRange>
            </field>
            <field>
              <name>BS12</name>
              <description>GPIOA12 output set</description>
              <bitRange>[12:12]</bitRange>
            </field>
            <field>
              <name>BS13</name>
              <description>GPIOA13 output set</description>
              <bitRange>[13:13]</bitRange>
            </field>
            <field>
              <name>BS14</name>
              <description>GPIOA14 output set</description>
              <bitRange>[14:14]</bitRange>
            </field>
            <field>
              <name>BS15</name>
              <description>GPIOA15 output set</description>
              <bitRange>[15:15]</bitRange>
            </field>
            <field>
              <name>BR0</name>
              <description>GPIOA0 outut reset</description>
              <bitRange>[16:16]</bitRange>
            </field>
            <field>
              <name>BR1</name>
              <description>GPIOA1 outut reset</description>
              <bitRange>[17:17]</bitRange>
            </field>
            <field>
              <name>BR2</name>
              <description>GPIOA2 outut reset</description>
              <bitRange>[18:18]</bitRange>
            </field>
            <field>
              <name>BR3</name>
              <description>GPIOA3 outut reset</description>
              <bitRange>[19:19]</bitRange>
            </field>
            <field>
              <name>BR4</name>
              <description>GPIOA4 outut reset</description>
              <bitRange>[20:20]</bitRange>
            </field>
            <field>
              <name>BR5</name>
              <description>GPIOA5 outut reset</description>
              <bitRange>[21:21]</bitRange>
            </field>
            <field>
              <name>BR6</name>
              <description>GPIOA6 outut reset</description>
              <bitRange>[22:22]</bitRange>
            </field>
            <field>
              <name>BR7</name>
              <description>GPIOA7 outut reset</description>
              <bitRange>[23:23]</bitRange>
            </field>
            <field>
              <name>BR8</name>
              <description>GPIOA8 outut reset</description>
              <bitRange>[24:24]</bitRange>
            </field>
            <field>
              <name>BR9</name>
              <description>GPIOA9 outut reset</description>
              <bitRange>[25:25]</bitRange>
            </field>
            <field>
              <name>BR10</name>
              <description>GPIOA10 outut reset</description>
              <bitRange>[26:26]</bitRange>
            </field>
            <field>
              <name>BR11</name>
              <description>GPIOA11 outut reset</description>
              <bitRange>[27:27]</bitRange>
            </field>
            <field>
              <name>BR12</name>
              <description>GPIOA12 outut reset</description>
              <bitRange>[28:28]</bitRange>
            </field>
            <field>
              <name>BR13</name>
              <description>GPIOA13 outut reset</description>
              <bitRange>[29:29]</bitRange>
            </field>
            <field>
              <name>BR14</name>
              <description>GPIOA14 outut reset</description>
              <bitRange>[30:30]</bitRange>
            </field>
            <field>
              <name>BR15</name>
              <description>GPIOA15 outut reset</description>
              <bitRange>[31:31]</bitRange>
            </field>
          </fields>
        </register>
        <register>
          <name>LCKR</name>
          <addressOffset>0x1C</addressOffset>
          <fields>
            <field>
              <name>LCK0</name>
              <description>GPIOA lock(bit0)</description>
              <bitRange>[0:0]</bitRange>
            </field>
            <field>
              <name>LCK1</name>
              <description>GPIOA lock(bit1)</description>
              <bitRange>[1:1]</bitRange>
            </field>
            <field>
              <name>LCK2</name>
              <description>GPIOA lock(bit2)</description>
              <bitRange>[2:2]</bitRange>
            </field>
            <field>
              <name>LCK3</name>
              <description>GPIOA lock(bit3)</description>
              <bitRange>[3:3]</bitRange>
            </field>
            <field>
              <name>LCK4</name>
              <description>GPIOA lock(bit4)</description>
              <bitRange>[4:4]</bitRange>
            </field>
            <field>
              <name>LCK5</name>
              <description>GPIOA lock(bit5)</description>
              <bitRange>[5:5]</bitRange>
            </field>
            <field>
              <name>LCK6</name>
              <description>GPIOA lock(bit6)</description>
              <bitRange>[6:6]</bitRange>
            </field>
            <field>
              <name>LCK7</name>
              <description>GPIOA lock(bit7)</description>
              <bitRange>[7:7]</bitRange>
            </field>
            <field>
              <name>LCK8</name>
              <description>GPIOA lock(bit8)</description>
              <bitRange>[8:8]</bitRange>
            </field>
            <field>
              <name>LCK9</name>
              <description>GPIOA lock(bit9)</description>
              <bitRange>[9:9]</bitRange>
            </field>
            <field>
              <name>LCK10</name>
              <description>GPIOA lock(bit10)</description>
              <bitRange>[10:10]</bitRange>
            </field>
            <field>
              <name>LCK11</name>
              <description>GPIOA lock(bit11)</description>
              <bitRange>[11:11]</bitRange>
            </field>
            <field>
              <name>LCK12</name>
              <description>GPIOA lock(bit12)</description>
              <bitRange>[12:12]</bitRange>
            </field>
            <field>
              <name>LCK13</name>
              <description>GPIOA lock(bit13)</description>
              <bitRange>[13:13]</bitRange>
            </field>
            <field>
              <name>LCK14</name>
              <description>GPIOA lock(bit14)</description>
              <bitRange>[14:14]</bitRange>
            </field>
            <field>
              <name>LCK15</name>
              <description>GPIOA lock(bit15)</description>
              <bitRange>[15:15]</bitRange>
            </field>
            <field>
              <name>LCKK</name>
              <description>GPIOA lock key</description>
              <bitRange>[16:16]</bitRange>
            </field>
          </fields>
        </register>
        <register>
          <name>AFRL</name>
          <addressOffset>0x20</addressOffset>
          <fields>
            <field>
              <name>AFSEL0</name>
              <description>GPIOA0 AF select</description>
              <bitRange>[3:0]</bitRange>
            </field>
            <field>
              <name>AFSEL1</name>
              <description>GPIOA1 AF select</description>
              <bitRange>[7:4]</bitRange>
            </field>
            <field>
              <name>AFSEL2</name>
              <description>GPIOA2 AF select</description>
              <bitRange>[11:8]</bitRange>
            </field>
            <field>
              <name>AFSEL3</name>
              <description>GPIOA3 AF select</description>
              <bitRange>[15:12]</bitRange>
            </field>
            <field>
              <name>AFSEL4</name>
              <description>GPIOA4 AF select</description>
              <bitRange>[19:16]</bitRange>
            </field>
            <field>
              <name>AFSEL5</name>
              <description>GPIOA5 AF select</description>
              <bitRange>[23:20]</bitRange>
            </field>
            <field>
              <name>AFSEL6</name>
              <description>GPIOA6 AF select</description>
              <bitRange>[27:24]</bitRange>
            </field>
            <field>
              <name>AFSEL7</name>
              <description>GPIOA7 AF select</description>
              <bitRange>[31:28]</bitRange>
            </field>
          </fields>
        </register>
        <register>
          <name>AFRH</name>
          <addressOffset>0x24</addressOffset>
          <fields>
            <field>
              <name>AFSEL8</name>
              <description>GPIOA8 AF select</description>
              <bitRange>[3:0]</bitRange>
            </field>
            <field>
              <name>AFSEL9</name>
              <description>GPIOA9 AF select</description>
              <bitRange>[7:4]</bitRange>
            </field>
            <field>
              <name>AFSEL10</name>
              <description>GPIOA10 AF select</description>
              <bitRange>[11:8]</bitRange>
            </field>
            <field>
              <name>AFSEL11</name>
              <description>GPIOA11 AF select</description>
              <bitRange>[15:12]</bitRange>
            </field>
            <field>
              <name>AFSEL12</name>
              <description>GPIOA12 AF select</description>
              <bitRange>[19:16]</bitRange>
            </field>
            <field>
              <name>AFSEL13</name>
              <description>GPIOA13 AF select</description>
              <bitRange>[23:20]</bitRange>
            </field>
            <field>
              <name>AFSEL14</name>
              <description>GPIOA14 AF select</description>
              <bitRange>[27:24]</bitRange>
            </field>
            <field>
              <name>AFSEL15</name>
              <description>GPIOA15 AF select</description>
              <bitRange>[31:28]</bitRange>
            </field>
          </fields>
        </register>
        <register>
          <name>BRR</name>
          <addressOffset>0x28</addressOffset>
          <fields>
            <field>
              <name>BR0</name>
              <description>GPIOA 0 output pin reset</description>
              <bitRange>[0:0]</bitRange>
            </field>
            <field>
              <name>BR1</name>
              <description>GPIOA 1 output pin reset</description>
              <bitRange>[1:1]</bitRange>
            </field>
            <field>
              <name>BR2</name>
              <description>GPIOA 2 output pin reset</description>
              <bitRange>[2:2]</bitRange>
            </field>
            <field>
              <name>BR3</name>
              <description>GPIOA 3 output pin reset</description>
              <bitRange>[3:3]</bitRange>
            </field>
            <field>
              <name>BR4</name>
              <description>GPIOA 4 output pin reset</description>
              <bitRange>[4:4]</bitRange>
            </field>
            <field>
              <name>BR5</name>
              <description>GPIOA 5 output pin reset</description>
              <bitRange>[5:5]</bitRange>
            </field>
            <field>
              <name>BR6</name>
              <description>GPIOA 6 output pin reset</description>
              <bitRange>[6:6]</bitRange>
            </field>
            <field>
              <name>BR7</name>
              <description>GPIOA 7 output pin reset</description>
              <bitRange>[7:7]</bitRange>
            </field>
            <field>
              <name>BR8</name>
              <description>GPIOA 8 output pin reset</description>
              <bitRange>[8:8]</bitRange>
            </field>
            <field>
              <name>BR9</name>
              <description>GPIOA 9 output pin reset</description>
              <bitRange>[9:9]</bitRange>
            </field>
            <field>
              <name>BR10</name>
              <description>GPIOA 10 output pin reset</description>
              <bitRange>[10:10]</bitRange>
            </field>
            <field>
              <name>BR11</name>
              <description>GPIOA 11 output pin reset</description>
              <bitRange>[11:11]</bitRange>
            </field>
            <field>
              <name>BR12</name>
              <description>GPIOA 12 output pin reset</description>
              <bitRange>[12:12]</bitRange>
            </field>
            <field>
              <name>BR13</name>
              <description>GPIOA 13 output pin reset</description>
              <bitRange>[13:13]</bitRange>
            </field>
            <field>
              <name>BR14</name>
              <description>GPIOA 14 output pin reset</description>
              <bitRange>[14:14]</bitRange>
            </field>
            <field>
              <name>BR15</name>
              <description>GPIOA 15 output pin reset</description>
              <bitRange>[15:15]</bitRange>
            </field>
          </fields>
        </register>
      </registers>
    </peripheral>
    <peripheral>
      <name>GPIOB</name>
      <baseAddress>0x40024400</baseAddress>
      <addressBlock>
        <offset>0x0</offset>
        <size>0x30</size>
        <usage>registers</usage>
      </addressBlock>
      <registers>
        <register>
          <name>MODER</name>
          <addressOffset>0x0</addressOffset>
          <fields>
            <field>
              <name>MODER0</name>
              <description>GPIOB0 MODE</description>
              <bitRange>[1:0]</bitRange>
            </field>
            <field>
              <name>MODER1</name>
              <description>GPIOB1 MODE</description>
              <bitRange>[3:2]</bitRange>
            </field>
            <field>
              <name>MODER2</name>
              <description>GPIOB2 MODE</description>
              <bitRange>[5:4]</bitRange>
            </field>
            <field>
              <name>MODER3</name>
              <description>GPIOB3 MODE</description>
              <bitRange>[7:6]</bitRange>
            </field>
            <field>
              <name>MODER4</name>
              <description>GPIOB4 MODE</description>
              <bitRange>[9:8]</bitRange>
            </field>
            <field>
              <name>MODER5</name>
              <description>GPIOB5 MODE</description>
              <bitRange>[11:10]</bitRange>
            </field>
            <field>
              <name>MODER6</name>
              <description>GPIOB6 MODE</description>
              <bitRange>[13:12]</bitRange>
            </field>
            <field>
              <name>MODER7</name>
              <description>GPIOB7 MODE</description>
              <bitRange>[15:14]</bitRange>
            </field>
            <field>
              <name>MODER8</name>
              <description>GPIOB8 MODE</description>
              <bitRange>[17:16]</bitRange>
            </field>
            <field>
              <name>MODER9</name>
              <description>GPIOB9 MODE</description>
              <bitRange>[19:18]</bitRange>
            </field>
            <field>
              <name>MODER10</name>
              <description>GPIOB10 MODE</description>
              <bitRange>[21:20]</bitRange>
            </field>
            <field>
              <name>MODER11</name>
              <description>GPIOB11 MODE</description>
              <bitRange>[23:22]</bitRange>
            </field>
            <field>
              <name>MODER12</name>
              <description>GPIOB12 MODE</description>
              <bitRange>[25:24]</bitRange>
            </field>
            <field>
              <name>MODER13</name>
              <description>GPIOB13 MODE</description>
              <bitRange>[27:26]</bitRange>
            </field>
            <field>
              <name>MODER14</name>
              <description>GPIOB14 MODE</description>
              <bitRange>[29:28]</bitRange>
            </field>
            <field>
              <name>MODER15</name>
              <description>GPIOB15 MODE</description>
              <bitRange>[31:30]</bitRange>
            </field>
          </fields>
        </register>
        <register>
          <name>OTYPER</name>
          <addressOffset>0x4</addressOffset>
          <fields>
            <field>
              <name>OT0</name>
              <description>GPIOB0 Output type</description>
              <bitRange>[0:0]</bitRange>
            </field>
            <field>
              <name>OT1</name>
              <description>GPIOB1 Output type</description>
              <bitRange>[1:1]</bitRange>
            </field>
            <field>
              <name>OT2</name>
              <description>GPIOB2 Output type</description>
              <bitRange>[2:2]</bitRange>
            </field>
            <field>
              <name>OT3</name>
              <description>GPIOB3 Output type</description>
              <bitRange>[3:3]</bitRange>
            </field>
            <field>
              <name>OT4</name>
              <description>GPIOB4 Output type</description>
              <bitRange>[4:4]</bitRange>
            </field>
            <field>
              <name>OT5</name>
              <description>GPIOB5 Output type</description>
              <bitRange>[5:5]</bitRange>
            </field>
            <field>
              <name>OT6</name>
              <description>GPIOB6 Output type</description>
              <bitRange>[6:6]</bitRange>
            </field>
            <field>
              <name>OT7</name>
              <description>GPIOB7 Output type</description>
              <bitRange>[7:7]</bitRange>
            </field>
            <field>
              <name>OT8</name>
              <description>GPIOB8 Output type</description>
              <bitRange>[8:8]</bitRange>
            </field>
            <field>
              <name>OT9</name>
              <description>GPIOB9 Output type</description>
              <bitRange>[9:9]</bitRange>
            </field>
            <field>
              <name>OT10</name>
              <description>GPIOB10 Output type</description>
              <bitRange>[10:10]</bitRange>
            </field>
            <field>
              <name>OT11</name>
              <description>GPIOB11 Output type</description>
              <bitRange>[11:11]</bitRange>
            </field>
            <field>
              <name>OT12</name>
              <description>GPIOB12 Output type</description>
              <bitRange>[12:12]</bitRange>
            </field>
            <field>
              <name>OT13</name>
              <description>GPIOB13 Output type</description>
              <bitRange>[13:13]</bitRange>
            </field>
            <field>
              <name>OT14</name>
              <description>GPIOB14 Output type</description>
              <bitRange>[14:14]</bitRange>
            </field>
            <field>
              <name>OT15</name>
              <description>GPIOB15 Output type</description>
              <bitRange>[15:15]</bitRange>
            </field>
          </fields>
        </register>
        <register>
          <name>OSPDDER</name>
          <addressOffset>0x8</addressOffset>
          <fields>
            <field>
              <name>OSPEED0</name>
              <description>GPIOB0 output speed</description>
              <bitRange>[1:0]</bitRange>
            </field>
            <field>
              <name>OSPEED1</name>
              <description>GPIOB1 output speed</description>
              <bitRange>[3:2]</bitRange>
            </field>
            <field>
              <name>OSPEED2</name>
              <description>GPIOB2 output speed</description>
              <bitRange>[5:4]</bitRange>
            </field>
            <field>
              <name>OSPEED3</name>
              <description>GPIOB3 output speed</description>
              <bitRange>[7:6]</bitRange>
            </field>
            <field>
              <name>OSPEED4</name>
              <description>GPIOB4 output speed</description>
              <bitRange>[9:8]</bitRange>
            </field>
            <field>
              <name>OSPEED5</name>
              <description>GPIOB5 output speed</description>
              <bitRange>[11:10]</bitRange>
            </field>
            <field>
              <name>OSPEED6</name>
              <description>GPIOB6 output speed</description>
              <bitRange>[13:12]</bitRange>
            </field>
            <field>
              <name>OSPEED7</name>
              <description>GPIOB7 output speed</description>
              <bitRange>[15:14]</bitRange>
            </field>
            <field>
              <name>OSPEED8</name>
              <description>GPIOB8 output speed</description>
              <bitRange>[17:16]</bitRange>
            </field>
            <field>
              <name>OSPEED9</name>
              <description>GPIOB9 output speed</description>
              <bitRange>[19:18]</bitRange>
            </field>
            <field>
              <name>OSPEED10</name>
              <description>GPIOB10 output speed</description>
              <bitRange>[21:20]</bitRange>
            </field>
            <field>
              <name>OSPEED11</name>
              <description>GPIOB11 output speed</description>
              <bitRange>[23:22]</bitRange>
            </field>
            <field>
              <name>OSPEED12</name>
              <description>GPIOB12 output speed</description>
              <bitRange>[25:24]</bitRange>
            </field>
            <field>
              <name>OSPEED13</name>
              <description>GPIOB13 output speed</description>
              <bitRange>[27:26]</bitRange>
            </field>
            <field>
              <name>OSPEED14</name>
              <description>GPIOB14 output speed</description>
              <bitRange>[29:28]</bitRange>
            </field>
            <field>
              <name>OSPEED15</name>
              <description>GPIOB15 output speed</description>
              <bitRange>[31:30]</bitRange>
            </field>
          </fields>
        </register>
        <register>
          <name>PUPDR</name>
          <addressOffset>0xC</addressOffset>
          <fields>
            <field>
              <name>PUPD0</name>
              <description>GPIOB0 pull up/pull down</description>
              <bitRange>[1:0]</bitRange>
            </field>
            <field>
              <name>PUPD1</name>
              <description>GPIOB1 pull up/pull down</description>
              <bitRange>[3:2]</bitRange>
            </field>
            <field>
              <name>PUPD2</name>
              <description>GPIOB2 pull up/pull down</description>
              <bitRange>[5:4]</bitRange>
            </field>
            <field>
              <name>PUPD3</name>
              <description>GPIOB3 pull up/pull down</description>
              <bitRange>[7:6]</bitRange>
            </field>
            <field>
              <name>PUPD4</name>
              <description>GPIOB4 pull up/pull down</description>
              <bitRange>[9:8]</bitRange>
            </field>
            <field>
              <name>PUPD5</name>
              <description>GPIOB5 pull up/pull down</description>
              <bitRange>[11:10]</bitRange>
            </field>
            <field>
              <name>PUPD6</name>
              <description>GPIOB6 pull up/pull down</description>
              <bitRange>[13:12]</bitRange>
            </field>
            <field>
              <name>PUPD7</name>
              <description>GPIOB7 pull up/pull down</description>
              <bitRange>[15:14]</bitRange>
            </field>
            <field>
              <name>PUPD8</name>
              <description>GPIOB8 pull up/pull down</description>
              <bitRange>[17:16]</bitRange>
            </field>
            <field>
              <name>PUPD9</name>
              <description>GPIOB9 pull up/pull down</description>
              <bitRange>[19:18]</bitRange>
            </field>
            <field>
              <name>PUPD10</name>
              <description>GPIOB10 pull up/pull down</description>
              <bitRange>[21:20]</bitRange>
            </field>
            <field>
              <name>PUPD11</name>
              <description>GPIOB11 pull up/pull down</description>
              <bitRange>[23:22]</bitRange>
            </field>
            <field>
              <name>PUPD12</name>
              <description>GPIOB12 pull up/pull down</description>
              <bitRange>[25:24]</bitRange>
            </field>
            <field>
              <name>PUPD13</name>
              <description>GPIOB13 pull up/pull down</description>
              <bitRange>[27:26]</bitRange>
            </field>
            <field>
              <name>PUPD14</name>
              <description>GPIOB14 pull up/pull down</description>
              <bitRange>[29:28]</bitRange>
            </field>
            <field>
              <name>PUPD15</name>
              <description>GPIOB15 pull up/pull down</description>
              <bitRange>[31:30]</bitRange>
            </field>
          </fields>
        </register>
        <register>
          <name>IDR</name>
          <addressOffset>0x10</addressOffset>
          <fields>
            <field>
              <name>ID0</name>
              <description>GPIOB0 input data</description>
              <bitRange>[0:0]</bitRange>
              <access>read-only</access>
            </field>
            <field>
              <name>ID1</name>
              <description>GPIOB1 input data</description>
              <bitRange>[1:1]</bitRange>
              <access>read-only</access>
            </field>
            <field>
              <name>ID2</name>
              <description>GPIOB2 input data</description>
              <bitRange>[2:2]</bitRange>
              <access>read-only</access>
            </field>
            <field>
              <name>ID3</name>
              <description>GPIOB3 input data</description>
              <bitRange>[3:3]</bitRange>
              <access>read-only</access>
            </field>
            <field>
              <name>ID4</name>
              <description>GPIOB4 input data</description>
              <bitRange>[4:4]</bitRange>
              <access>read-only</access>
            </field>
            <field>
              <name>ID5</name>
              <description>GPIOB5 input data</description>
              <bitRange>[5:5]</bitRange>
              <access>read-only</access>
            </field>
            <field>
              <name>ID6</name>
              <description>GPIOB6 input data</description>
              <bitRange>[6:6]</bitRange>
              <access>read-only</access>
            </field>
            <field>
              <name>ID7</name>
              <description>GPIOB7 input data</description>
              <bitRange>[7:7]</bitRange>
              <access>read-only</access>
            </field>
            <field>
              <name>ID8</name>
              <description>GPIOB8 input data</description>
              <bitRange>[8:8]</bitRange>
              <access>read-only</access>
            </field>
            <field>
              <name>ID9</name>
              <description>GPIOB9 input data</description>
              <bitRange>[9:9]</bitRange>
              <access>read-only</access>
            </field>
            <field>
              <name>ID10</name>
              <description>GPIOB10 input data</description>
              <bitRange>[10:10]</bitRange>
              <access>read-only</access>
            </field>
            <field>
              <name>ID11</name>
              <description>GPIOB11 input data</description>
              <bitRange>[11:11]</bitRange>
              <access>read-only</access>
            </field>
            <field>
              <name>ID12</name>
              <description>GPIOB12 input data</description>
              <bitRange>[12:12]</bitRange>
              <access>read-only</access>
            </field>
            <field>
              <name>ID13</name>
              <description>GPIOB13 input data</description>
              <bitRange>[13:13]</bitRange>
              <access>read-only</access>
            </field>
            <field>
              <name>ID14</name>
              <description>GPIOB14 input data</description>
              <bitRange>[14:14]</bitRange>
              <access>read-only</access>
            </field>
            <field>
              <name>ID15</name>
              <description>GPIOB15 input data</description>
              <bitRange>[15:15]</bitRange>
              <access>read-only</access>
            </field>
          </fields>
        </register>
        <register>
          <name>ODR</name>
          <addressOffset>0x14</addressOffset>
          <fields>
            <field>
              <name>OD0</name>
              <description>GPIOB0 output data</description>
              <bitRange>[0:0]</bitRange>
            </field>
            <field>
              <name>OD1</name>
              <description>GPIOB1 output data</description>
              <bitRange>[1:1]</bitRange>
            </field>
            <field>
              <name>OD2</name>
              <description>GPIOB2 output data</description>
              <bitRange>[2:2]</bitRange>
            </field>
            <field>
              <name>OD3</name>
              <description>GPIOB3 output data</description>
              <bitRange>[3:3]</bitRange>
            </field>
            <field>
              <name>OD4</name>
              <description>GPIOB4 output data</description>
              <bitRange>[4:4]</bitRange>
            </field>
            <field>
              <name>OD5</name>
              <description>GPIOB5 output data</description>
              <bitRange>[5:5]</bitRange>
            </field>
            <field>
              <name>OD6</name>
              <description>GPIOB6 output data</description>
              <bitRange>[6:6]</bitRange>
            </field>
            <field>
              <name>OD7</name>
              <description>GPIOB7 output data</description>
              <bitRange>[7:7]</bitRange>
            </field>
            <field>
              <name>OD8</name>
              <description>GPIOB8 output data</description>
              <bitRange>[8:8]</bitRange>
            </field>
            <field>
              <name>OD9</name>
              <description>GPIOB9 output data</description>
              <bitRange>[9:9]</bitRange>
            </field>
            <field>
              <name>OD10</name>
              <description>GPIOB10 output data</description>
              <bitRange>[10:10]</bitRange>
            </field>
            <field>
              <name>OD11</name>
              <description>GPIOB11 output data</description>
              <bitRange>[11:11]</bitRange>
            </field>
            <field>
              <name>OD12</name>
              <description>GPIOB12 output data</description>
              <bitRange>[12:12]</bitRange>
            </field>
            <field>
              <name>OD13</name>
              <description>GPIOB13 output data</description>
              <bitRange>[13:13]</bitRange>
            </field>
            <field>
              <name>OD14</name>
              <description>GPIOB14 output data</description>
              <bitRange>[14:14]</bitRange>
            </field>
            <field>
              <name>OD15</name>
              <description>GPIOB15 output data</description>
              <bitRange>[15:15]</bitRange>
            </field>
          </fields>
        </register>
        <register>
          <name>BSRR</name>
          <addressOffset>0x18</addressOffset>
          <fields>
            <field>
              <name>BS0</name>
              <description>GPIOB0 output set</description>
              <bitRange>[0:0]</bitRange>
            </field>
            <field>
              <name>BS1</name>
              <description>GPIOB1 output set</description>
              <bitRange>[1:1]</bitRange>
            </field>
            <field>
              <name>BS2</name>
              <description>GPIOB2 output set</description>
              <bitRange>[2:2]</bitRange>
            </field>
            <field>
              <name>BS3</name>
              <description>GPIOB3 output set</description>
              <bitRange>[3:3]</bitRange>
            </field>
            <field>
              <name>BS4</name>
              <description>GPIOB4 output set</description>
              <bitRange>[4:4]</bitRange>
            </field>
            <field>
              <name>BS5</name>
              <description>GPIOB5 output set</description>
              <bitRange>[5:5]</bitRange>
            </field>
            <field>
              <name>BS6</name>
              <description>GPIOB6 output set</description>
              <bitRange>[6:6]</bitRange>
            </field>
            <field>
              <name>BS7</name>
              <description>GPIOB7 output set</description>
              <bitRange>[7:7]</bitRange>
            </field>
            <field>
              <name>BS8</name>
              <description>GPIOB8 output set</description>
              <bitRange>[8:8]</bitRange>
            </field>
            <field>
              <name>BS9</name>
              <description>GPIOB9 output set</description>
              <bitRange>[9:9]</bitRange>
            </field>
            <field>
              <name>BS10</name>
              <description>GPIOB10 output set</description>
              <bitRange>[10:10]</bitRange>
            </field>
            <field>
              <name>BS11</name>
              <description>GPIOB11 output set</description>
              <bitRange>[11:11]</bitRange>
            </field>
            <field>
              <name>BS12</name>
              <description>GPIOB12 output set</description>
              <bitRange>[12:12]</bitRange>
            </field>
            <field>
              <name>BS13</name>
              <description>GPIOB13 output set</description>
              <bitRange>[13:13]</bitRange>
            </field>
            <field>
              <name>BS14</name>
              <description>GPIOB14 output set</description>
              <bitRange>[14:14]</bitRange>
            </field>
            <field>
              <name>BS15</name>
              <description>GPIOB15 output set</description>
              <bitRange>[15:15]</bitRange>
            </field>
            <field>
              <name>BR0</name>
              <description>GPIOB0 outut reset</description>
              <bitRange>[16:16]</bitRange>
            </field>
            <field>
              <name>BR1</name>
              <description>GPIOB1 outut reset</description>
              <bitRange>[17:17]</bitRange>
            </field>
            <field>
              <name>BR2</name>
              <description>GPIOB2 outut reset</description>
              <bitRange>[18:18]</bitRange>
            </field>
            <field>
              <name>BR3</name>
              <description>GPIOB3 outut reset</description>
              <bitRange>[19:19]</bitRange>
            </field>
            <field>
              <name>BR4</name>
              <description>GPIOB4 outut reset</description>
              <bitRange>[20:20]</bitRange>
            </field>
            <field>
              <name>BR5</name>
              <description>GPIOB5 outut reset</description>
              <bitRange>[21:21]</bitRange>
            </field>
            <field>
              <name>BR6</name>
              <description>GPIOB6 outut reset</description>
              <bitRange>[22:22]</bitRange>
            </field>
            <field>
              <name>BR7</name>
              <description>GPIOB7 outut reset</description>
              <bitRange>[23:23]</bitRange>
            </field>
            <field>
              <name>BR8</name>
              <description>GPIOB8 outut reset</description>
              <bitRange>[24:24]</bitRange>
            </field>
            <field>
              <name>BR9</name>
              <description>GPIOB9 outut reset</description>
              <bitRange>[25:25]</bitRange>
            </field>
            <field>
              <name>BR10</name>
              <description>GPIOB10 outut reset</description>
              <bitRange>[26:26]</bitRange>
            </field>
            <field>
              <name>BR11</name>
              <description>GPIOB11 outut reset</description>
              <bitRange>[27:27]</bitRange>
            </field>
            <field>
              <name>BR12</name>
              <description>GPIOB12 outut reset</description>
              <bitRange>[28:28]</bitRange>
            </field>
            <field>
              <name>BR13</name>
              <description>GPIOB13 outut reset</description>
              <bitRange>[29:29]</bitRange>
            </field>
            <field>
              <name>BR14</name>
              <description>GPIOB14 outut reset</description>
              <bitRange>[30:30]</bitRange>
            </field>
            <field>
              <name>BR15</name>
              <description>GPIOB15 outut reset</description>
              <bitRange>[31:31]</bitRange>
            </field>
          </fields>
        </register>
        <register>
          <name>LCKR</name>
          <addressOffset>0x1C</addressOffset>
          <fields>
            <field>
              <name>LCK0</name>
              <description>GPIOB lock(bit0)</description>
              <bitRange>[0:0]</bitRange>
            </field>
            <field>
              <name>LCK1</name>
              <description>GPIOB lock(bit1)</description>
              <bitRange>[1:1]</bitRange>
            </field>
            <field>
              <name>LCK2</name>
              <description>GPIOB lock(bit2)</description>
              <bitRange>[2:2]</bitRange>
            </field>
            <field>
              <name>LCK3</name>
              <description>GPIOB lock(bit3)</description>
              <bitRange>[3:3]</bitRange>
            </field>
            <field>
              <name>LCK4</name>
              <description>GPIOB lock(bit4)</description>
              <bitRange>[4:4]</bitRange>
            </field>
            <field>
              <name>LCK5</name>
              <description>GPIOB lock(bit5)</description>
              <bitRange>[5:5]</bitRange>
            </field>
            <field>
              <name>LCK6</name>
              <description>GPIOB lock(bit6)</description>
              <bitRange>[6:6]</bitRange>
            </field>
            <field>
              <name>LCK7</name>
              <description>GPIOB lock(bit7)</description>
              <bitRange>[7:7]</bitRange>
            </field>
            <field>
              <name>LCK8</name>
              <description>GPIOB lock(bit8)</description>
              <bitRange>[8:8]</bitRange>
            </field>
            <field>
              <name>LCK9</name>
              <description>GPIOB lock(bit9)</description>
              <bitRange>[9:9]</bitRange>
            </field>
            <field>
              <name>LCK10</name>
              <description>GPIOB lock(bit10)</description>
              <bitRange>[10:10]</bitRange>
            </field>
            <field>
              <name>LCK11</name>
              <description>GPIOB lock(bit11)</description>
              <bitRange>[11:11]</bitRange>
            </field>
            <field>
              <name>LCK12</name>
              <description>GPIOB lock(bit12)</description>
              <bitRange>[12:12]</bitRange>
            </field>
            <field>
              <name>LCK13</name>
              <description>GPIOB lock(bit13)</description>
              <bitRange>[13:13]</bitRange>
            </field>
            <field>
              <name>LCK14</name>
              <description>GPIOB lock(bit14)</description>
              <bitRange>[14:14]</bitRange>
            </field>
            <field>
              <name>LCK15</name>
              <description>GPIOB lock(bit15)</description>
              <bitRange>[15:15]</bitRange>
            </field>
            <field>
              <name>LCKK</name>
              <description>GPIOB lock key</description>
              <bitRange>[16:16]</bitRange>
            </field>
          </fields>
        </register>
        <register>
          <name>AFRL</name>
          <addressOffset>0x20</addressOffset>
          <fields>
            <field>
              <name>AFSEL0</name>
              <description>GPIOB0 AF select</description>
              <bitRange>[3:0]</bitRange>
            </field>
            <field>
              <name>AFSEL1</name>
              <description>GPIOB1 AF select</description>
              <bitRange>[7:4]</bitRange>
            </field>
            <field>
              <name>AFSEL2</name>
              <description>GPIOB2 AF select</description>
              <bitRange>[11:8]</bitRange>
            </field>
            <field>
              <name>AFSEL3</name>
              <description>GPIOB3 AF select</description>
              <bitRange>[15:12]</bitRange>
            </field>
            <field>
              <name>AFSEL4</name>
              <description>GPIOB4 AF select</description>
              <bitRange>[19:16]</bitRange>
            </field>
            <field>
              <name>AFSEL5</name>
              <description>GPIOB5 AF select</description>
              <bitRange>[23:20]</bitRange>
            </field>
            <field>
              <name>AFSEL6</name>
              <description>GPIOB6 AF select</description>
              <bitRange>[27:24]</bitRange>
            </field>
            <field>
              <name>AFSEL7</name>
              <description>GPIOB7 AF select</description>
              <bitRange>[31:28]</bitRange>
            </field>
          </fields>
        </register>
        <register>
          <name>AFRH</name>
          <addressOffset>0x24</addressOffset>
          <fields>
            <field>
              <name>AFSEL8</name>
              <description>GPIOB8 AF select</description>
              <bitRange>[3:0]</bitRange>
            </field>
            <field>
              <name>AFSEL9</name>
              <description>GPIOB9 AF select</description>
              <bitRange>[7:4]</bitRange>
            </field>
            <field>
              <name>AFSEL10</name>
              <description>GPIOB10 AF select</description>
              <bitRange>[11:8]</bitRange>
            </field>
            <field>
              <name>AFSEL11</name>
              <description>GPIOB11 AF select</description>
              <bitRange>[15:12]</bitRange>
            </field>
            <field>
              <name>AFSEL12</name>
              <description>GPIOB12 AF select</description>
              <bitRange>[19:16]</bitRange>
            </field>
            <field>
              <name>AFSEL13</name>
              <description>GPIOB13 AF select</description>
              <bitRange>[23:20]</bitRange>
            </field>
            <field>
              <name>AFSEL14</name>
              <description>GPIOB14 AF select</description>
              <bitRange>[27:24]</bitRange>
            </field>
            <field>
              <name>AFSEL15</name>
              <description>GPIOB15 AF select</description>
              <bitRange>[31:28]</bitRange>
            </field>
          </fields>
        </register>
        <register>
          <name>BRR</name>
          <addressOffset>0x28</addressOffset>
          <fields>
            <field>
              <name>BR0</name>
              <description>GPIOB 0 output pin reset</description>
              <bitRange>[0:0]</bitRange>
            </field>
            <field>
              <name>BR1</name>
              <description>GPIOB 1 output pin reset</description>
              <bitRange>[1:1]</bitRange>
            </field>
            <field>
              <name>BR2</name>
              <description>GPIOB 2 output pin reset</description>
              <bitRange>[2:2]</bitRange>
            </field>
            <field>
              <name>BR3</name>
              <description>GPIOB 3 output pin reset</description>
              <bitRange>[3:3]</bitRange>
            </field>
            <field>
              <name>BR4</name>
              <description>GPIOB 4 output pin reset</description>
              <bitRange>[4:4]</bitRange>
            </field>
            <field>
              <name>BR5</name>
              <description>GPIOB 5 output pin reset</description>
              <bitRange>[5:5]</bitRange>
            </field>
            <field>
              <name>BR6</name>
              <description>GPIOB 6 output pin reset</description>
              <bitRange>[6:6]</bitRange>
            </field>
            <field>
              <name>BR7</name>
              <description>GPIOB 7 output pin reset</description>
              <bitRange>[7:7]</bitRange>
            </field>
            <field>
              <name>BR8</name>
              <description>GPIOB 8 output pin reset</description>
              <bitRange>[8:8]</bitRange>
            </field>
            <field>
              <name>BR9</name>
              <description>GPIOB 9 output pin reset</description>
              <bitRange>[9:9]</bitRange>
            </field>
            <field>
              <name>BR10</name>
              <description>GPIOB 10 output pin reset</description>
              <bitRange>[10:10]</bitRange>
            </field>
            <field>
              <name>BR11</name>
              <description>GPIOB 11 output pin reset</description>
              <bitRange>[11:11]</bitRange>
            </field>
            <field>
              <name>BR12</name>
              <description>GPIOB 12 output pin reset</description>
              <bitRange>[12:12]</bitRange>
            </field>
            <field>
              <name>BR13</name>
              <description>GPIOB 13 output pin reset</description>
              <bitRange>[13:13]</bitRange>
            </field>
            <field>
              <name>BR14</name>
              <description>GPIOB 14 output pin reset</description>
              <bitRange>[14:14]</bitRange>
            </field>
            <field>
              <name>BR15</name>
              <description>GPIOB 15 output pin reset</description>
              <bitRange>[15:15]</bitRange>
            </field>
          </fields>
        </register>
      </registers>
    </peripheral>
    <peripheral>
      <name>GPIOC</name>
      <baseAddress>0x40024800</baseAddress>
      <addressBlock>
        <offset>0x0</offset>
        <size>0x30</size>
        <usage>registers</usage>
      </addressBlock>
      <registers>
        <register>
          <name>MODER</name>
          <addressOffset>0x0</addressOffset>
          <fields>
            <field>
              <name>MODER0</name>
              <description>GPIOC0 MODE</description>
              <bitRange>[1:0]</bitRange>
            </field>
            <field>
              <name>MODER1</name>
              <description>GPIOC1 MODE</description>
              <bitRange>[3:2]</bitRange>
            </field>
            <field>
              <name>MODER2</name>
              <description>GPIOC2 MODE</description>
              <bitRange>[5:4]</bitRange>
            </field>
            <field>
              <name>MODER3</name>
              <description>GPIOC3 MODE</description>
              <bitRange>[7:6]</bitRange>
            </field>
            <field>
              <name>MODER4</name>
              <description>GPIOC4 MODE</description>
              <bitRange>[9:8]</bitRange>
            </field>
            <field>
              <name>MODER5</name>
              <description>GPIOC5 MODE</description>
              <bitRange>[11:10]</bitRange>
            </field>
            <field>
              <name>MODER6</name>
              <description>GPIOC6 MODE</description>
              <bitRange>[13:12]</bitRange>
            </field>
            <field>
              <name>MODER7</name>
              <description>GPIOC7 MODE</description>
              <bitRange>[15:14]</bitRange>
            </field>
            <field>
              <name>MODER8</name>
              <description>GPIOC8 MODE</description>
              <bitRange>[17:16]</bitRange>
            </field>
            <field>
              <name>MODER9</name>
              <description>GPIOC9 MODE</description>
              <bitRange>[19:18]</bitRange>
            </field>
            <field>
              <name>MODER10</name>
              <description>GPIOC10 MODE</description>
              <bitRange>[21:20]</bitRange>
            </field>
            <field>
              <name>MODER11</name>
              <description>GPIOC11 MODE</description>
              <bitRange>[23:22]</bitRange>
            </field>
            <field>
              <name>MODER12</name>
              <description>GPIOC12 MODE</description>
              <bitRange>[25:24]</bitRange>
            </field>
            <field>
              <name>MODER13</name>
              <description>GPIOC13 MODE</description>
              <bitRange>[27:26]</bitRange>
            </field>
            <field>
              <name>MODER14</name>
              <description>GPIOC14 MODE</description>
              <bitRange>[29:28]</bitRange>
            </field>
            <field>
              <name>MODER15</name>
              <description>GPIOC15 MODE</description>
              <bitRange>[31:30]</bitRange>
            </field>
          </fields>
        </register>
        <register>
          <name>OTYPER</name>
          <addressOffset>0x4</addressOffset>
          <fields>
            <field>
              <name>OT0</name>
              <description>GPIOC0 Output type</description>
              <bitRange>[0:0]</bitRange>
            </field>
            <field>
              <name>OT1</name>
              <description>GPIOC1 Output type</description>
              <bitRange>[1:1]</bitRange>
            </field>
            <field>
              <name>OT2</name>
              <description>GPIOC2 Output type</description>
              <bitRange>[2:2]</bitRange>
            </field>
            <field>
              <name>OT3</name>
              <description>GPIOC3 Output type</description>
              <bitRange>[3:3]</bitRange>
            </field>
            <field>
              <name>OT4</name>
              <description>GPIOC4 Output type</description>
              <bitRange>[4:4]</bitRange>
            </field>
            <field>
              <name>OT5</name>
              <description>GPIOC5 Output type</description>
              <bitRange>[5:5]</bitRange>
            </field>
            <field>
              <name>OT6</name>
              <description>GPIOC6 Output type</description>
              <bitRange>[6:6]</bitRange>
            </field>
            <field>
              <name>OT7</name>
              <description>GPIOC7 Output type</description>
              <bitRange>[7:7]</bitRange>
            </field>
            <field>
              <name>OT8</name>
              <description>GPIOC8 Output type</description>
              <bitRange>[8:8]</bitRange>
            </field>
            <field>
              <name>OT9</name>
              <description>GPIOC9 Output type</description>
              <bitRange>[9:9]</bitRange>
            </field>
            <field>
              <name>OT10</name>
              <description>GPIOC10 Output type</description>
              <bitRange>[10:10]</bitRange>
            </field>
            <field>
              <name>OT11</name>
              <description>GPIOC11 Output type</description>
              <bitRange>[11:11]</bitRange>
            </field>
            <field>
              <name>OT12</name>
              <description>GPIOC12 Output type</description>
              <bitRange>[12:12]</bitRange>
            </field>
            <field>
              <name>OT13</name>
              <description>GPIOC13 Output type</description>
              <bitRange>[13:13]</bitRange>
            </field>
            <field>
              <name>OT14</name>
              <description>GPIOC14 Output type</description>
              <bitRange>[14:14]</bitRange>
            </field>
            <field>
              <name>OT15</name>
              <description>GPIOC15 Output type</description>
              <bitRange>[15:15]</bitRange>
            </field>
          </fields>
        </register>
        <register>
          <name>OSPDDER</name>
          <addressOffset>0x8</addressOffset>
          <fields>
            <field>
              <name>OSPEED0</name>
              <description>GPIOC0 output speed</description>
              <bitRange>[1:0]</bitRange>
            </field>
            <field>
              <name>OSPEED1</name>
              <description>GPIOC1 output speed</description>
              <bitRange>[3:2]</bitRange>
            </field>
            <field>
              <name>OSPEED2</name>
              <description>GPIOC2 output speed</description>
              <bitRange>[5:4]</bitRange>
            </field>
            <field>
              <name>OSPEED3</name>
              <description>GPIOC3 output speed</description>
              <bitRange>[7:6]</bitRange>
            </field>
            <field>
              <name>OSPEED4</name>
              <description>GPIOC4 output speed</description>
              <bitRange>[9:8]</bitRange>
            </field>
            <field>
              <name>OSPEED5</name>
              <description>GPIOC5 output speed</description>
              <bitRange>[11:10]</bitRange>
            </field>
            <field>
              <name>OSPEED6</name>
              <description>GPIOC6 output speed</description>
              <bitRange>[13:12]</bitRange>
            </field>
            <field>
              <name>OSPEED7</name>
              <description>GPIOC7 output speed</description>
              <bitRange>[15:14]</bitRange>
            </field>
            <field>
              <name>OSPEED8</name>
              <description>GPIOC8 output speed</description>
              <bitRange>[17:16]</bitRange>
            </field>
            <field>
              <name>OSPEED9</name>
              <description>GPIOC9 output speed</description>
              <bitRange>[19:18]</bitRange>
            </field>
            <field>
              <name>OSPEED10</name>
              <description>GPIOC10 output speed</description>
              <bitRange>[21:20]</bitRange>
            </field>
            <field>
              <name>OSPEED11</name>
              <description>GPIOC11 output speed</description>
              <bitRange>[23:22]</bitRange>
            </field>
            <field>
              <name>OSPEED12</name>
              <description>GPIOC12 output speed</description>
              <bitRange>[25:24]</bitRange>
            </field>
            <field>
              <name>OSPEED13</name>
              <description>GPIOC13 output speed</description>
              <bitRange>[27:26]</bitRange>
            </field>
            <field>
              <name>OSPEED14</name>
              <description>GPIOC14 output speed</description>
              <bitRange>[29:28]</bitRange>
            </field>
            <field>
              <name>OSPEED15</name>
              <description>GPIOC15 output speed</description>
              <bitRange>[31:30]</bitRange>
            </field>
          </fields>
        </register>
        <register>
          <name>PUPDR</name>
          <addressOffset>0xC</addressOffset>
          <fields>
            <field>
              <name>PUPD0</name>
              <description>GPIOC0 pull up/pull down</description>
              <bitRange>[1:0]</bitRange>
            </field>
            <field>
              <name>PUPD1</name>
              <description>GPIOC1 pull up/pull down</description>
              <bitRange>[3:2]</bitRange>
            </field>
            <field>
              <name>PUPD2</name>
              <description>GPIOC2 pull up/pull down</description>
              <bitRange>[5:4]</bitRange>
            </field>
            <field>
              <name>PUPD3</name>
              <description>GPIOC3 pull up/pull down</description>
              <bitRange>[7:6]</bitRange>
            </field>
            <field>
              <name>PUPD4</name>
              <description>GPIOC4 pull up/pull down</description>
              <bitRange>[9:8]</bitRange>
            </field>
            <field>
              <name>PUPD5</name>
              <description>GPIOC5 pull up/pull down</description>
              <bitRange>[11:10]</bitRange>
            </field>
            <field>
              <name>PUPD6</name>
              <description>GPIOC6 pull up/pull down</description>
              <bitRange>[13:12]</bitRange>
            </field>
            <field>
              <name>PUPD7</name>
              <description>GPIOC7 pull up/pull down</description>
              <bitRange>[15:14]</bitRange>
            </field>
            <field>
              <name>PUPD8</name>
              <description>GPIOC8 pull up/pull down</description>
              <bitRange>[17:16]</bitRange>
            </field>
            <field>
              <name>PUPD9</name>
              <description>GPIOC9 pull up/pull down</description>
              <bitRange>[19:18]</bitRange>
            </field>
            <field>
              <name>PUPD10</name>
              <description>GPIOC10 pull up/pull down</description>
              <bitRange>[21:20]</bitRange>
            </field>
            <field>
              <name>PUPD11</name>
              <description>GPIOC11 pull up/pull down</description>
              <bitRange>[23:22]</bitRange>
            </field>
            <field>
              <name>PUPD12</name>
              <description>GPIOC12 pull up/pull down</description>
              <bitRange>[25:24]</bitRange>
            </field>
            <field>
              <name>PUPD13</name>
              <description>GPIOC13 pull up/pull down</description>
              <bitRange>[27:26]</bitRange>
            </field>
            <field>
              <name>PUPD14</name>
              <description>GPIOC14 pull up/pull down</description>
              <bitRange>[29:28]</bitRange>
            </field>
            <field>
              <name>PUPD15</name>
              <description>GPIOC15 pull up/pull down</description>
              <bitRange>[31:30]</bitRange>
            </field>
          </fields>
        </register>
        <register>
          <name>IDR</name>
          <addressOffset>0x10</addressOffset>
          <fields>
            <field>
              <name>ID0</name>
              <description>GPIOC0 input data</description>
              <bitRange>[0:0]</bitRange>
              <access>read-only</access>
            </field>
            <field>
              <name>ID1</name>
              <description>GPIOC1 input data</description>
              <bitRange>[1:1]</bitRange>
              <access>read-only</access>
            </field>
            <field>
              <name>ID2</name>
              <description>GPIOC2 input data</description>
              <bitRange>[2:2]</bitRange>
              <access>read-only</access>
            </field>
            <field>
              <name>ID3</name>
              <description>GPIOC3 input data</description>
              <bitRange>[3:3]</bitRange>
              <access>read-only</access>
            </field>
            <field>
              <name>ID4</name>
              <description>GPIOC4 input data</description>
              <bitRange>[4:4]</bitRange>
              <access>read-only</access>
            </field>
            <field>
              <name>ID5</name>
              <description>GPIOC5 input data</description>
              <bitRange>[5:5]</bitRange>
              <access>read-only</access>
            </field>
            <field>
              <name>ID6</name>
              <description>GPIOC6 input data</description>
              <bitRange>[6:6]</bitRange>
              <access>read-only</access>
            </field>
            <field>
              <name>ID7</name>
              <description>GPIOC7 input data</description>
              <bitRange>[7:7]</bitRange>
              <access>read-only</access>
            </field>
            <field>
              <name>ID8</name>
              <description>GPIOC8 input data</description>
              <bitRange>[8:8]</bitRange>
              <access>read-only</access>
            </field>
            <field>
              <name>ID9</name>
              <description>GPIOC9 input data</description>
              <bitRange>[9:9]</bitRange>
              <access>read-only</access>
            </field>
            <field>
              <name>ID10</name>
              <description>GPIOC10 input data</description>
              <bitRange>[10:10]</bitRange>
              <access>read-only</access>
            </field>
            <field>
              <name>ID11</name>
              <description>GPIOC11 input data</description>
              <bitRange>[11:11]</bitRange>
              <access>read-only</access>
            </field>
            <field>
              <name>ID12</name>
              <description>GPIOC12 input data</description>
              <bitRange>[12:12]</bitRange>
              <access>read-only</access>
            </field>
            <field>
              <name>ID13</name>
              <description>GPIOC13 input data</description>
              <bitRange>[13:13]</bitRange>
              <access>read-only</access>
            </field>
            <field>
              <name>ID14</name>
              <description>GPIOC14 input data</description>
              <bitRange>[14:14]</bitRange>
              <access>read-only</access>
            </field>
            <field>
              <name>ID15</name>
              <description>GPIOC15 input data</description>
              <bitRange>[15:15]</bitRange>
              <access>read-only</access>
            </field>
          </fields>
        </register>
        <register>
          <name>ODR</name>
          <addressOffset>0x14</addressOffset>
          <fields>
            <field>
              <name>OD0</name>
              <description>GPIOC0 output data</description>
              <bitRange>[0:0]</bitRange>
            </field>
            <field>
              <name>OD1</name>
              <description>GPIOC1 output data</description>
              <bitRange>[1:1]</bitRange>
            </field>
            <field>
              <name>OD2</name>
              <description>GPIOC2 output data</description>
              <bitRange>[2:2]</bitRange>
            </field>
            <field>
              <name>OD3</name>
              <description>GPIOC3 output data</description>
              <bitRange>[3:3]</bitRange>
            </field>
            <field>
              <name>OD4</name>
              <description>GPIOC4 output data</description>
              <bitRange>[4:4]</bitRange>
            </field>
            <field>
              <name>OD5</name>
              <description>GPIOC5 output data</description>
              <bitRange>[5:5]</bitRange>
            </field>
            <field>
              <name>OD6</name>
              <description>GPIOC6 output data</description>
              <bitRange>[6:6]</bitRange>
            </field>
            <field>
              <name>OD7</name>
              <description>GPIOC7 output data</description>
              <bitRange>[7:7]</bitRange>
            </field>
            <field>
              <name>OD8</name>
              <description>GPIOC8 output data</description>
              <bitRange>[8:8]</bitRange>
            </field>
            <field>
              <name>OD9</name>
              <description>GPIOC9 output data</description>
              <bitRange>[9:9]</bitRange>
            </field>
            <field>
              <name>OD10</name>
              <description>GPIOC10 output data</description>
              <bitRange>[10:10]</bitRange>
            </field>
            <field>
              <name>OD11</name>
              <description>GPIOC11 output data</description>
              <bitRange>[11:11]</bitRange>
            </field>
            <field>
              <name>OD12</name>
              <description>GPIOC12 output data</description>
              <bitRange>[12:12]</bitRange>
            </field>
            <field>
              <name>OD13</name>
              <description>GPIOC13 output data</description>
              <bitRange>[13:13]</bitRange>
            </field>
            <field>
              <name>OD14</name>
              <description>GPIOC14 output data</description>
              <bitRange>[14:14]</bitRange>
            </field>
            <field>
              <name>OD15</name>
              <description>GPIOC15 output data</description>
              <bitRange>[15:15]</bitRange>
            </field>
          </fields>
        </register>
        <register>
          <name>BSRR</name>
          <addressOffset>0x18</addressOffset>
          <fields>
            <field>
              <name>BS0</name>
              <description>GPIOC0 output set</description>
              <bitRange>[0:0]</bitRange>
            </field>
            <field>
              <name>BS1</name>
              <description>GPIOC1 output set</description>
              <bitRange>[1:1]</bitRange>
            </field>
            <field>
              <name>BS2</name>
              <description>GPIOC2 output set</description>
              <bitRange>[2:2]</bitRange>
            </field>
            <field>
              <name>BS3</name>
              <description>GPIOC3 output set</description>
              <bitRange>[3:3]</bitRange>
            </field>
            <field>
              <name>BS4</name>
              <description>GPIOC4 output set</description>
              <bitRange>[4:4]</bitRange>
            </field>
            <field>
              <name>BS5</name>
              <description>GPIOC5 output set</description>
              <bitRange>[5:5]</bitRange>
            </field>
            <field>
              <name>BS6</name>
              <description>GPIOC6 output set</description>
              <bitRange>[6:6]</bitRange>
            </field>
            <field>
              <name>BS7</name>
              <description>GPIOC7 output set</description>
              <bitRange>[7:7]</bitRange>
            </field>
            <field>
              <name>BS8</name>
              <description>GPIOC8 output set</description>
              <bitRange>[8:8]</bitRange>
            </field>
            <field>
              <name>BS9</name>
              <description>GPIOC9 output set</description>
              <bitRange>[9:9]</bitRange>
            </field>
            <field>
              <name>BS10</name>
              <description>GPIOC10 output set</description>
              <bitRange>[10:10]</bitRange>
            </field>
            <field>
              <name>BS11</name>
              <description>GPIOC11 output set</description>
              <bitRange>[11:11]</bitRange>
            </field>
            <field>
              <name>BS12</name>
              <description>GPIOC12 output set</description>
              <bitRange>[12:12]</bitRange>
            </field>
            <field>
              <name>BS13</name>
              <description>GPIOC13 output set</description>
              <bitRange>[13:13]</bitRange>
            </field>
            <field>
              <name>BS14</name>
              <description>GPIOC14 output set</description>
              <bitRange>[14:14]</bitRange>
            </field>
            <field>
              <name>BS15</name>
              <description>GPIOC15 output set</description>
              <bitRange>[15:15]</bitRange>
            </field>
            <field>
              <name>BR0</name>
              <description>GPIOC0 outut reset</description>
              <bitRange>[16:16]</bitRange>
            </field>
            <field>
              <name>BR1</name>
              <description>GPIOC1 outut reset</description>
              <bitRange>[17:17]</bitRange>
            </field>
            <field>
              <name>BR2</name>
              <description>GPIOC2 outut reset</description>
              <bitRange>[18:18]</bitRange>
            </field>
            <field>
              <name>BR3</name>
              <description>GPIOC3 outut reset</description>
              <bitRange>[19:19]</bitRange>
            </field>
            <field>
              <name>BR4</name>
              <description>GPIOC4 outut reset</description>
              <bitRange>[20:20]</bitRange>
            </field>
            <field>
              <name>BR5</name>
              <description>GPIOC5 outut reset</description>
              <bitRange>[21:21]</bitRange>
            </field>
            <field>
              <name>BR6</name>
              <description>GPIOC6 outut reset</description>
              <bitRange>[22:22]</bitRange>
            </field>
            <field>
              <name>BR7</name>
              <description>GPIOC7 outut reset</description>
              <bitRange>[23:23]</bitRange>
            </field>
            <field>
              <name>BR8</name>
              <description>GPIOC8 outut reset</description>
              <bitRange>[24:24]</bitRange>
            </field>
            <field>
              <name>BR9</name>
              <description>GPIOC9 outut reset</description>
              <bitRange>[25:25]</bitRange>
            </field>
            <field>
              <name>BR10</name>
              <description>GPIOC10 outut reset</description>
              <bitRange>[26:26]</bitRange>
            </field>
            <field>
              <name>BR11</name>
              <description>GPIOC11 outut reset</description>
              <bitRange>[27:27]</bitRange>
            </field>
            <field>
              <name>BR12</name>
              <description>GPIOC12 outut reset</description>
              <bitRange>[28:28]</bitRange>
            </field>
            <field>
              <name>BR13</name>
              <description>GPIOC13 outut reset</description>
              <bitRange>[29:29]</bitRange>
            </field>
            <field>
              <name>BR14</name>
              <description>GPIOC14 outut reset</description>
              <bitRange>[30:30]</bitRange>
            </field>
            <field>
              <name>BR15</name>
              <description>GPIOC15 outut reset</description>
              <bitRange>[31:31]</bitRange>
            </field>
          </fields>
        </register>
        <register>
          <name>LCKR</name>
          <addressOffset>0x1C</addressOffset>
          <fields>
            <field>
              <name>LCK0</name>
              <description>GPIOC lock(bit0)</description>
              <bitRange>[0:0]</bitRange>
            </field>
            <field>
              <name>LCK1</name>
              <description>GPIOC lock(bit1)</description>
              <bitRange>[1:1]</bitRange>
            </field>
            <field>
              <name>LCK2</name>
              <description>GPIOC lock(bit2)</description>
              <bitRange>[2:2]</bitRange>
            </field>
            <field>
              <name>LCK3</name>
              <description>GPIOC lock(bit3)</description>
              <bitRange>[3:3]</bitRange>
            </field>
            <field>
              <name>LCK4</name>
              <description>GPIOC lock(bit4)</description>
              <bitRange>[4:4]</bitRange>
            </field>
            <field>
              <name>LCK5</name>
              <description>GPIOC lock(bit5)</description>
              <bitRange>[5:5]</bitRange>
            </field>
            <field>
              <name>LCK6</name>
              <description>GPIOC lock(bit6)</description>
              <bitRange>[6:6]</bitRange>
            </field>
            <field>
              <name>LCK7</name>
              <description>GPIOC lock(bit7)</description>
              <bitRange>[7:7]</bitRange>
            </field>
            <field>
              <name>LCK8</name>
              <description>GPIOC lock(bit8)</description>
              <bitRange>[8:8]</bitRange>
            </field>
            <field>
              <name>LCK9</name>
              <description>GPIOC lock(bit9)</description>
              <bitRange>[9:9]</bitRange>
            </field>
            <field>
              <name>LCK10</name>
              <description>GPIOC lock(bit10)</description>
              <bitRange>[10:10]</bitRange>
            </field>
            <field>
              <name>LCK11</name>
              <description>GPIOC lock(bit11)</description>
              <bitRange>[11:11]</bitRange>
            </field>
            <field>
              <name>LCK12</name>
              <description>GPIOC lock(bit12)</description>
              <bitRange>[12:12]</bitRange>
            </field>
            <field>
              <name>LCK13</name>
              <description>GPIOC lock(bit13)</description>
              <bitRange>[13:13]</bitRange>
            </field>
            <field>
              <name>LCK14</name>
              <description>GPIOC lock(bit14)</description>
              <bitRange>[14:14]</bitRange>
            </field>
            <field>
              <name>LCK15</name>
              <description>GPIOC lock(bit15)</description>
              <bitRange>[15:15]</bitRange>
            </field>
            <field>
              <name>LCKK</name>
              <description>GPIOC lock key</description>
              <bitRange>[16:16]</bitRange>
            </field>
          </fields>
        </register>
        <register>
          <name>AFRL</name>
          <addressOffset>0x20</addressOffset>
          <fields>
            <field>
              <name>AFSEL0</name>
              <description>GPIOC0 AF select</description>
              <bitRange>[3:0]</bitRange>
            </field>
            <field>
              <name>AFSEL1</name>
              <description>GPIOC1 AF select</description>
              <bitRange>[7:4]</bitRange>
            </field>
            <field>
              <name>AFSEL2</name>
              <description>GPIOC2 AF select</description>
              <bitRange>[11:8]</bitRange>
            </field>
            <field>
              <name>AFSEL3</name>
              <description>GPIOC3 AF select</description>
              <bitRange>[15:12]</bitRange>
            </field>
            <field>
              <name>AFSEL4</name>
              <description>GPIOC4 AF select</description>
              <bitRange>[19:16]</bitRange>
            </field>
            <field>
              <name>AFSEL5</name>
              <description>GPIOC5 AF select</description>
              <bitRange>[23:20]</bitRange>
            </field>
            <field>
              <name>AFSEL6</name>
              <description>GPIOC6 AF select</description>
              <bitRange>[27:24]</bitRange>
            </field>
            <field>
              <name>AFSEL7</name>
              <description>GPIOC7 AF select</description>
              <bitRange>[31:28]</bitRange>
            </field>
          </fields>
        </register>
        <register>
          <name>AFRH</name>
          <addressOffset>0x24</addressOffset>
          <fields>
            <field>
              <name>AFSEL8</name>
              <description>GPIOC8 AF select</description>
              <bitRange>[3:0]</bitRange>
            </field>
            <field>
              <name>AFSEL9</name>
              <description>GPIOC9 AF select</description>
              <bitRange>[7:4]</bitRange>
            </field>
            <field>
              <name>AFSEL10</name>
              <description>GPIOC10 AF select</description>
              <bitRange>[11:8]</bitRange>
            </field>
            <field>
              <name>AFSEL11</name>
              <description>GPIOC11 AF select</description>
              <bitRange>[15:12]</bitRange>
            </field>
            <field>
              <name>AFSEL12</name>
              <description>GPIOC12 AF select</description>
              <bitRange>[19:16]</bitRange>
            </field>
            <field>
              <name>AFSEL13</name>
              <description>GPIOC13 AF select</description>
              <bitRange>[23:20]</bitRange>
            </field>
            <field>
              <name>AFSEL14</name>
              <description>GPIOC14 AF select</description>
              <bitRange>[27:24]</bitRange>
            </field>
            <field>
              <name>AFSEL15</name>
              <description>GPIOC15 AF select</description>
              <bitRange>[31:28]</bitRange>
            </field>
          </fields>
        </register>
        <register>
          <name>BRR</name>
          <addressOffset>0x28</addressOffset>
          <fields>
            <field>
              <name>BR0</name>
              <description>GPIOC 0 output pin reset</description>
              <bitRange>[0:0]</bitRange>
            </field>
            <field>
              <name>BR1</name>
              <description>GPIOC 1 output pin reset</description>
              <bitRange>[1:1]</bitRange>
            </field>
            <field>
              <name>BR2</name>
              <description>GPIOC 2 output pin reset</description>
              <bitRange>[2:2]</bitRange>
            </field>
            <field>
              <name>BR3</name>
              <description>GPIOC 3 output pin reset</description>
              <bitRange>[3:3]</bitRange>
            </field>
            <field>
              <name>BR4</name>
              <description>GPIOC 4 output pin reset</description>
              <bitRange>[4:4]</bitRange>
            </field>
            <field>
              <name>BR5</name>
              <description>GPIOC 5 output pin reset</description>
              <bitRange>[5:5]</bitRange>
            </field>
            <field>
              <name>BR6</name>
              <description>GPIOC 6 output pin reset</description>
              <bitRange>[6:6]</bitRange>
            </field>
            <field>
              <name>BR7</name>
              <description>GPIOC 7 output pin reset</description>
              <bitRange>[7:7]</bitRange>
            </field>
            <field>
              <name>BR8</name>
              <description>GPIOC 8 output pin reset</description>
              <bitRange>[8:8]</bitRange>
            </field>
            <field>
              <name>BR9</name>
              <description>GPIOC 9 output pin reset</description>
              <bitRange>[9:9]</bitRange>
            </field>
            <field>
              <name>BR10</name>
              <description>GPIOC 10 output pin reset</description>
              <bitRange>[10:10]</bitRange>
            </field>
            <field>
              <name>BR11</name>
              <description>GPIOC 11 output pin reset</description>
              <bitRange>[11:11]</bitRange>
            </field>
            <field>
              <name>BR12</name>
              <description>GPIOC 12 output pin reset</description>
              <bitRange>[12:12]</bitRange>
            </field>
            <field>
              <name>BR13</name>
              <description>GPIOC 13 output pin reset</description>
              <bitRange>[13:13]</bitRange>
            </field>
            <field>
              <name>BR14</name>
              <description>GPIOC 14 output pin reset</description>
              <bitRange>[14:14]</bitRange>
            </field>
            <field>
              <name>BR15</name>
              <description>GPIOC 15 output pin reset</description>
              <bitRange>[15:15]</bitRange>
            </field>
          </fields>
        </register>
      </registers>
    </peripheral>
    <peripheral>
      <name>GPIOD</name>
      <baseAddress>0x40024C00</baseAddress>
      <addressBlock>
        <offset>0x0</offset>
        <size>0x30</size>
        <usage>registers</usage>
      </addressBlock>
      <registers>
        <register>
          <name>MODER</name>
          <addressOffset>0x0</addressOffset>
          <fields>
            <field>
              <name>MODER0</name>
              <description>GPIOD0 MODE</description>
              <bitRange>[1:0]</bitRange>
            </field>
            <field>
              <name>MODER1</name>
              <description>GPIOD1 MODE</description>
              <bitRange>[3:2]</bitRange>
            </field>
            <field>
              <name>MODER2</name>
              <description>GPIOD2 MODE</description>
              <bitRange>[5:4]</bitRange>
            </field>
            <field>
              <name>MODER3</name>
              <description>GPIOD3 MODE</description>
              <bitRange>[7:6]</bitRange>
            </field>
            <field>
              <name>MODER4</name>
              <description>GPIOD4 MODE</description>
              <bitRange>[9:8]</bitRange>
            </field>
            <field>
              <name>MODER5</name>
              <description>GPIOD5 MODE</description>
              <bitRange>[11:10]</bitRange>
            </field>
            <field>
              <name>MODER6</name>
              <description>GPIOD6 MODE</description>
              <bitRange>[13:12]</bitRange>
            </field>
            <field>
              <name>MODER7</name>
              <description>GPIOD7 MODE</description>
              <bitRange>[15:14]</bitRange>
            </field>
            <field>
              <name>MODER8</name>
              <description>GPIOD8 MODE</description>
              <bitRange>[17:16]</bitRange>
            </field>
            <field>
              <name>MODER9</name>
              <description>GPIOD9 MODE</description>
              <bitRange>[19:18]</bitRange>
            </field>
            <field>
              <name>MODER10</name>
              <description>GPIOD10 MODE</description>
              <bitRange>[21:20]</bitRange>
            </field>
            <field>
              <name>MODER11</name>
              <description>GPIOD11 MODE</description>
              <bitRange>[23:22]</bitRange>
            </field>
          </fields>
        </register>
        <register>
          <name>OTYPER</name>
          <addressOffset>0x4</addressOffset>
          <fields>
            <field>
              <name>OT0</name>
              <description>GPIOD0 Output type</description>
              <bitRange>[0:0]</bitRange>
            </field>
            <field>
              <name>OT1</name>
              <description>GPIOD1 Output type</description>
              <bitRange>[1:1]</bitRange>
            </field>
            <field>
              <name>OT2</name>
              <description>GPIOD2 Output type</description>
              <bitRange>[2:2]</bitRange>
            </field>
            <field>
              <name>OT3</name>
              <description>GPIOD3 Output type</description>
              <bitRange>[3:3]</bitRange>
            </field>
            <field>
              <name>OT4</name>
              <description>GPIOD4 Output type</description>
              <bitRange>[4:4]</bitRange>
            </field>
            <field>
              <name>OT5</name>
              <description>GPIOD5 Output type</description>
              <bitRange>[5:5]</bitRange>
            </field>
            <field>
              <name>OT6</name>
              <description>GPIOD6 Output type</description>
              <bitRange>[6:6]</bitRange>
            </field>
            <field>
              <name>OT7</name>
              <description>GPIOD7 Output type</description>
              <bitRange>[7:7]</bitRange>
            </field>
            <field>
              <name>OT8</name>
              <description>GPIOD8 Output type</description>
              <bitRange>[8:8]</bitRange>
            </field>
            <field>
              <name>OT9</name>
              <description>GPIOD9 Output type</description>
              <bitRange>[9:9]</bitRange>
            </field>
            <field>
              <name>OT10</name>
              <description>GPIOD10 Output type</description>
              <bitRange>[10:10]</bitRange>
            </field>
            <field>
              <name>OT11</name>
              <description>GPIOD11 Output type</description>
              <bitRange>[11:11]</bitRange>
            </field>
          </fields>
        </register>
        <register>
          <name>OSPDDER</name>
          <addressOffset>0x8</addressOffset>
          <fields>
            <field>
              <name>OSPEED0</name>
              <description>GPIOD0 output speed</description>
              <bitRange>[1:0]</bitRange>
            </field>
            <field>
              <name>OSPEED1</name>
              <description>GPIOD1 output speed</description>
              <bitRange>[3:2]</bitRange>
            </field>
            <field>
              <name>OSPEED2</name>
              <description>GPIOD2 output speed</description>
              <bitRange>[5:4]</bitRange>
            </field>
            <field>
              <name>OSPEED3</name>
              <description>GPIOD3 output speed</description>
              <bitRange>[7:6]</bitRange>
            </field>
            <field>
              <name>OSPEED4</name>
              <description>GPIOD4 output speed</description>
              <bitRange>[9:8]</bitRange>
            </field>
            <field>
              <name>OSPEED5</name>
              <description>GPIOD5 output speed</description>
              <bitRange>[11:10]</bitRange>
            </field>
            <field>
              <name>OSPEED6</name>
              <description>GPIOD6 output speed</description>
              <bitRange>[13:12]</bitRange>
            </field>
            <field>
              <name>OSPEED7</name>
              <description>GPIOD7 output speed</description>
              <bitRange>[15:14]</bitRange>
            </field>
            <field>
              <name>OSPEED8</name>
              <description>GPIOD8 output speed</description>
              <bitRange>[17:16]</bitRange>
            </field>
            <field>
              <name>OSPEED9</name>
              <description>GPIOD9 output speed</description>
              <bitRange>[19:18]</bitRange>
            </field>
            <field>
              <name>OSPEED10</name>
              <description>GPIOD10 output speed</description>
              <bitRange>[21:20]</bitRange>
            </field>
            <field>
              <name>OSPEED11</name>
              <description>GPIOD11 output speed</description>
              <bitRange>[23:22]</bitRange>
            </field>
          </fields>
        </register>
        <register>
          <name>PUPDR</name>
          <addressOffset>0xC</addressOffset>
          <fields>
            <field>
              <name>PUPD0</name>
              <description>GPIOD0 pull up/pull down</description>
              <bitRange>[1:0]</bitRange>
            </field>
            <field>
              <name>PUPD1</name>
              <description>GPIOD1 pull up/pull down</description>
              <bitRange>[3:2]</bitRange>
            </field>
            <field>
              <name>PUPD2</name>
              <description>GPIOD2 pull up/pull down</description>
              <bitRange>[5:4]</bitRange>
            </field>
            <field>
              <name>PUPD3</name>
              <description>GPIOD3 pull up/pull down</description>
              <bitRange>[7:6]</bitRange>
            </field>
            <field>
              <name>PUPD4</name>
              <description>GPIOD4 pull up/pull down</description>
              <bitRange>[9:8]</bitRange>
            </field>
            <field>
              <name>PUPD5</name>
              <description>GPIOD5 pull up/pull down</description>
              <bitRange>[11:10]</bitRange>
            </field>
            <field>
              <name>PUPD6</name>
              <description>GPIOD6 pull up/pull down</description>
              <bitRange>[13:12]</bitRange>
            </field>
            <field>
              <name>PUPD7</name>
              <description>GPIOD7 pull up/pull down</description>
              <bitRange>[15:14]</bitRange>
            </field>
            <field>
              <name>PUPD8</name>
              <description>GPIOD8 pull up/pull down</description>
              <bitRange>[17:16]</bitRange>
            </field>
            <field>
              <name>PUPD9</name>
              <description>GPIOD9 pull up/pull down</description>
              <bitRange>[19:18]</bitRange>
            </field>
            <field>
              <name>PUPD10</name>
              <description>GPIOD10 pull up/pull down</description>
              <bitRange>[21:20]</bitRange>
            </field>
            <field>
              <name>PUPD11</name>
              <description>GPIOD11 pull up/pull down</description>
              <bitRange>[23:22]</bitRange>
            </field>
          </fields>
        </register>
        <register>
          <name>IDR</name>
          <addressOffset>0x10</addressOffset>
          <fields>
            <field>
              <name>ID0</name>
              <description>GPIOD0 input data</description>
              <bitRange>[0:0]</bitRange>
              <access>read-only</access>
            </field>
            <field>
              <name>ID1</name>
              <description>GPIOD1 input data</description>
              <bitRange>[1:1]</bitRange>
              <access>read-only</access>
            </field>
            <field>
              <name>ID2</name>
              <description>GPIOD2 input data</description>
              <bitRange>[2:2]</bitRange>
              <access>read-only</access>
            </field>
            <field>
              <name>ID3</name>
              <description>GPIOD3 input data</description>
              <bitRange>[3:3]</bitRange>
              <access>read-only</access>
            </field>
            <field>
              <name>ID4</name>
              <description>GPIOD4 input data</description>
              <bitRange>[4:4]</bitRange>
              <access>read-only</access>
            </field>
            <field>
              <name>ID5</name>
              <description>GPIOD5 input data</description>
              <bitRange>[5:5]</bitRange>
              <access>read-only</access>
            </field>
            <field>
              <name>ID6</name>
              <description>GPIOD6 input data</description>
              <bitRange>[6:6]</bitRange>
              <access>read-only</access>
            </field>
            <field>
              <name>ID7</name>
              <description>GPIOD7 input data</description>
              <bitRange>[7:7]</bitRange>
              <access>read-only</access>
            </field>
            <field>
              <name>ID8</name>
              <description>GPIOD8 input data</description>
              <bitRange>[8:8]</bitRange>
              <access>read-only</access>
            </field>
            <field>
              <name>ID9</name>
              <description>GPIOD9 input data</description>
              <bitRange>[9:9]</bitRange>
              <access>read-only</access>
            </field>
            <field>
              <name>ID10</name>
              <description>GPIOD10 input data</description>
              <bitRange>[10:10]</bitRange>
              <access>read-only</access>
            </field>
            <field>
              <name>ID11</name>
              <description>GPIOD11 input data</description>
              <bitRange>[11:11]</bitRange>
              <access>read-only</access>
            </field>
          </fields>
        </register>
        <register>
          <name>ODR</name>
          <addressOffset>0x14</addressOffset>
          <fields>
            <field>
              <name>OD0</name>
              <description>GPIOD0 output data</description>
              <bitRange>[0:0]</bitRange>
            </field>
            <field>
              <name>OD1</name>
              <description>GPIOD1 output data</description>
              <bitRange>[1:1]</bitRange>
            </field>
            <field>
              <name>OD2</name>
              <description>GPIOD2 output data</description>
              <bitRange>[2:2]</bitRange>
            </field>
            <field>
              <name>OD3</name>
              <description>GPIOD3 output data</description>
              <bitRange>[3:3]</bitRange>
            </field>
            <field>
              <name>OD4</name>
              <description>GPIOD4 output data</description>
              <bitRange>[4:4]</bitRange>
            </field>
            <field>
              <name>OD5</name>
              <description>GPIOD5 output data</description>
              <bitRange>[5:5]</bitRange>
            </field>
            <field>
              <name>OD6</name>
              <description>GPIOD6 output data</description>
              <bitRange>[6:6]</bitRange>
            </field>
            <field>
              <name>OD7</name>
              <description>GPIOD7 output data</description>
              <bitRange>[7:7]</bitRange>
            </field>
            <field>
              <name>OD8</name>
              <description>GPIOD8 output data</description>
              <bitRange>[8:8]</bitRange>
            </field>
            <field>
              <name>OD9</name>
              <description>GPIOD9 output data</description>
              <bitRange>[9:9]</bitRange>
            </field>
            <field>
              <name>OD10</name>
              <description>GPIOD10 output data</description>
              <bitRange>[10:10]</bitRange>
            </field>
            <field>
              <name>OD11</name>
              <description>GPIOD11 output data</description>
              <bitRange>[11:11]</bitRange>
            </field>
          </fields>
        </register>
        <register>
          <name>BSRR</name>
          <addressOffset>0x18</addressOffset>
          <fields>
            <field>
              <name>BS0</name>
              <description>GPIOD0 output set</description>
              <bitRange>[0:0]</bitRange>
            </field>
            <field>
              <name>BS1</name>
              <description>GPIOD1 output set</description>
              <bitRange>[1:1]</bitRange>
            </field>
            <field>
              <name>BS2</name>
              <description>GPIOD2 output set</description>
              <bitRange>[2:2]</bitRange>
            </field>
            <field>
              <name>BS3</name>
              <description>GPIOD3 output set</description>
              <bitRange>[3:3]</bitRange>
            </field>
            <field>
              <name>BS4</name>
              <description>GPIOD4 output set</description>
              <bitRange>[4:4]</bitRange>
            </field>
            <field>
              <name>BS5</name>
              <description>GPIOD5 output set</description>
              <bitRange>[5:5]</bitRange>
            </field>
            <field>
              <name>BS6</name>
              <description>GPIOD6 output set</description>
              <bitRange>[6:6]</bitRange>
            </field>
            <field>
              <name>BS7</name>
              <description>GPIOD7 output set</description>
              <bitRange>[7:7]</bitRange>
            </field>
            <field>
              <name>BS8</name>
              <description>GPIOD8 output set</description>
              <bitRange>[8:8]</bitRange>
            </field>
            <field>
              <name>BS9</name>
              <description>GPIOD9 output set</description>
              <bitRange>[9:9]</bitRange>
            </field>
            <field>
              <name>BS10</name>
              <description>GPIOD10 output set</description>
              <bitRange>[10:10]</bitRange>
            </field>
            <field>
              <name>BS11</name>
              <description>GPIOD11 output set</description>
              <bitRange>[11:11]</bitRange>
            </field>
            <field>
              <name>BR0</name>
              <description>GPIOD0 outut reset</description>
              <bitRange>[16:16]</bitRange>
            </field>
            <field>
              <name>BR1</name>
              <description>GPIOD1 outut reset</description>
              <bitRange>[17:17]</bitRange>
            </field>
            <field>
              <name>BR2</name>
              <description>GPIOD2 outut reset</description>
              <bitRange>[18:18]</bitRange>
            </field>
            <field>
              <name>BR3</name>
              <description>GPIOD3 outut reset</description>
              <bitRange>[19:19]</bitRange>
            </field>
            <field>
              <name>BR4</name>
              <description>GPIOD4 outut reset</description>
              <bitRange>[20:20]</bitRange>
            </field>
            <field>
              <name>BR5</name>
              <description>GPIOD5 outut reset</description>
              <bitRange>[21:21]</bitRange>
            </field>
            <field>
              <name>BR6</name>
              <description>GPIOD6 outut reset</description>
              <bitRange>[22:22]</bitRange>
            </field>
            <field>
              <name>BR7</name>
              <description>GPIOD7 outut reset</description>
              <bitRange>[23:23]</bitRange>
            </field>
            <field>
              <name>BR8</name>
              <description>GPIOD8 outut reset</description>
              <bitRange>[24:24]</bitRange>
            </field>
            <field>
              <name>BR9</name>
              <description>GPIOD9 outut reset</description>
              <bitRange>[25:25]</bitRange>
            </field>
            <field>
              <name>BR10</name>
              <description>GPIOD10 outut reset</description>
              <bitRange>[26:26]</bitRange>
            </field>
            <field>
              <name>BR11</name>
              <description>GPIOD11 outut reset</description>
              <bitRange>[27:27]</bitRange>
            </field>
          </fields>
        </register>
        <register>
          <name>LCKR</name>
          <addressOffset>0x1C</addressOffset>
          <fields>
            <field>
              <name>LCK0</name>
              <description>GPIOD lock(bit0)</description>
              <bitRange>[0:0]</bitRange>
            </field>
            <field>
              <name>LCK1</name>
              <description>GPIOD lock(bit1)</description>
              <bitRange>[1:1]</bitRange>
            </field>
            <field>
              <name>LCK2</name>
              <description>GPIOD lock(bit2)</description>
              <bitRange>[2:2]</bitRange>
            </field>
            <field>
              <name>LCK3</name>
              <description>GPIOD lock(bit3)</description>
              <bitRange>[3:3]</bitRange>
            </field>
            <field>
              <name>LCK4</name>
              <description>GPIOD lock(bit4)</description>
              <bitRange>[4:4]</bitRange>
            </field>
            <field>
              <name>LCK5</name>
              <description>GPIOD lock(bit5)</description>
              <bitRange>[5:5]</bitRange>
            </field>
            <field>
              <name>LCK6</name>
              <description>GPIOD lock(bit6)</description>
              <bitRange>[6:6]</bitRange>
            </field>
            <field>
              <name>LCK7</name>
              <description>GPIOD lock(bit7)</description>
              <bitRange>[7:7]</bitRange>
            </field>
            <field>
              <name>LCK8</name>
              <description>GPIOD lock(bit8)</description>
              <bitRange>[8:8]</bitRange>
            </field>
            <field>
              <name>LCK9</name>
              <description>GPIOD lock(bit9)</description>
              <bitRange>[9:9]</bitRange>
            </field>
            <field>
              <name>LCK10</name>
              <description>GPIOD lock(bit10)</description>
              <bitRange>[10:10]</bitRange>
            </field>
            <field>
              <name>LCK11</name>
              <description>GPIOD lock(bit11)</description>
              <bitRange>[11:11]</bitRange>
            </field>
            <field>
              <name>LCKK</name>
              <description>GPIOD lock key</description>
              <bitRange>[16:16]</bitRange>
            </field>
          </fields>
        </register>
        <register>
          <name>AFRL</name>
          <addressOffset>0x20</addressOffset>
          <fields>
            <field>
              <name>AFSEL0</name>
              <description>GPIOD0 AF select</description>
              <bitRange>[3:0]</bitRange>
            </field>
            <field>
              <name>AFSEL1</name>
              <description>GPIOD1 AF select</description>
              <bitRange>[7:4]</bitRange>
            </field>
            <field>
              <name>AFSEL2</name>
              <description>GPIOD2 AF select</description>
              <bitRange>[11:8]</bitRange>
            </field>
            <field>
              <name>AFSEL3</name>
              <description>GPIOD3 AF select</description>
              <bitRange>[15:12]</bitRange>
            </field>
            <field>
              <name>AFSEL4</name>
              <description>GPIOD4 AF select</description>
              <bitRange>[19:16]</bitRange>
            </field>
            <field>
              <name>AFSEL5</name>
              <description>GPIOD5 AF select</description>
              <bitRange>[23:20]</bitRange>
            </field>
            <field>
              <name>AFSEL6</name>
              <description>GPIOD6 AF select</description>
              <bitRange>[27:24]</bitRange>
            </field>
            <field>
              <name>AFSEL7</name>
              <description>GPIOD7 AF select</description>
              <bitRange>[31:28]</bitRange>
            </field>
          </fields>
        </register>
        <register>
          <name>AFRH</name>
          <addressOffset>0x24</addressOffset>
          <fields>
            <field>
              <name>AFSEL8</name>
              <description>GPIOD8 AF select</description>
              <bitRange>[3:0]</bitRange>
            </field>
            <field>
              <name>AFSEL9</name>
              <description>GPIOD9 AF select</description>
              <bitRange>[7:4]</bitRange>
            </field>
            <field>
              <name>AFSEL10</name>
              <description>GPIOD10 AF select</description>
              <bitRange>[11:8]</bitRange>
            </field>
            <field>
              <name>AFSEL11</name>
              <description>GPIOD11 AF select</description>
              <bitRange>[15:12]</bitRange>
            </field>
          </fields>
        </register>
        <register>
          <name>BRR</name>
          <addressOffset>0x28</addressOffset>
          <fields>
            <field>
              <name>BR0</name>
              <description>GPIOD 0 output pin reset</description>
              <bitRange>[0:0]</bitRange>
            </field>
            <field>
              <name>BR1</name>
              <description>GPIOD 1 output pin reset</description>
              <bitRange>[1:1]</bitRange>
            </field>
            <field>
              <name>BR2</name>
              <description>GPIOD 2 output pin reset</description>
              <bitRange>[2:2]</bitRange>
            </field>
            <field>
              <name>BR3</name>
              <description>GPIOD 3 output pin reset</description>
              <bitRange>[3:3]</bitRange>
            </field>
            <field>
              <name>BR4</name>
              <description>GPIOD 4 output pin reset</description>
              <bitRange>[4:4]</bitRange>
            </field>
            <field>
              <name>BR5</name>
              <description>GPIOD 5 output pin reset</description>
              <bitRange>[5:5]</bitRange>
            </field>
            <field>
              <name>BR6</name>
              <description>GPIOD 6 output pin reset</description>
              <bitRange>[6:6]</bitRange>
            </field>
            <field>
              <name>BR7</name>
              <description>GPIOD 7 output pin reset</description>
              <bitRange>[7:7]</bitRange>
            </field>
            <field>
              <name>BR8</name>
              <description>GPIOD 8 output pin reset</description>
              <bitRange>[8:8]</bitRange>
            </field>
            <field>
              <name>BR9</name>
              <description>GPIOD 9 output pin reset</description>
              <bitRange>[9:9]</bitRange>
            </field>
            <field>
              <name>BR10</name>
              <description>GPIOD 10 output pin reset</description>
              <bitRange>[10:10]</bitRange>
            </field>
            <field>
              <name>BR11</name>
              <description>GPIOD 11 output pin reset</description>
              <bitRange>[11:11]</bitRange>
            </field>
          </fields>
        </register>
      </registers>
    </peripheral>
    <peripheral>
      <name>HRPWM1</name>
      <groupName>HRPWM</groupName>
      <baseAddress>0x40018000</baseAddress>
      <addressBlock>
        <offset>0x0</offset>
        <size>0x200</size>
        <usage>registers</usage>
      </addressBlock>
      <interrupt>
        <name>HRPWM1</name>
        <description>HRPWM1 global Interrupt</description>
        <value>51</value>
      </interrupt>
      <interrupt>
        <name>HRPWM1_TZ</name>
        <description>HRPWM1 Trip Interrupt</description>
        <value>57</value>
      </interrupt>
      <registers>
        <register>
          <name>TBCTL</name>
          <addressOffset>0x0</addressOffset>
          <size>16</size>
          <fields>
            <field>
              <name>CTRMODE</name>
              <bitRange>[1:0]</bitRange>
            </field>
            <field>
              <name>PHSEN</name>
              <bitRange>[2:2]</bitRange>
            </field>
            <field>
              <name>PRDLD</name>
              <bitRange>[3:3]</bitRange>
            </field>
            <field>
              <name>SYNCOSEL</name>
              <bitRange>[5:4]</bitRange>
            </field>
            <field>
              <name>SWFSYNC</name>
              <bitRange>[6:6]</bitRange>
            </field>
            <field>
              <name>HSPCLKDIV</name>
              <bitRange>[9:7]</bitRange>
            </field>
            <field>
              <name>CLKDIV</name>
              <bitRange>[12:10]</bitRange>
            </field>
            <field>
              <name>PHSDIR</name>
              <bitRange>[13:13]</bitRange>
            </field>
            <field>
              <name>FREE_SOFT</name>
              <bitRange>[15:14]</bitRange>
            </field>
          </fields>
        </register>
        <register>
          <name>TBCTL2</name>
          <addressOffset>0x2</addressOffset>
          <size>16</size>
          <fields>
            <field>
              <name>OSHTSYNCMODE</name>
              <bitRange>[6:6]</bitRange>
            </field>
            <field>
              <name>OSHTSYNC</name>
              <bitRange>[7:7]</bitRange>
            </field>
            <field>
              <name>SYNCOSELX</name>
              <bitRange>[13:12]</bitRange>
            </field>
            <field>
              <name>PRDLDSYNC</name>
              <bitRange>[15:14]</bitRange>
            </field>
          </fields>
        </register>
        <register>
          <name>TBCTR</name>
          <addressOffset>0x8</addressOffset>
          <size>16</size>
          <fields>
            <field>
              <name>TBCTR</name>
              <bitRange>[15:0]</bitRange>
            </field>
          </fields>
        </register>
        <register>
          <name>TBSTS</name>
          <addressOffset>0xA</addressOffset>
          <size>16</size>
          <fields>
            <field>
              <name>CTRDIR</name>
              <bitRange>[0:0]</bitRange>
              <access>read-only</access>
            </field>
            <field>
              <name>SYNCI</name>
              <bitRange>[1:1]</bitRange>
            </field>
            <field>
              <name>CTRMAX</name>
              <bitRange>[2:2]</bitRange>
            </field>
          </fields>
        </register>
        <register>
          <name>CMPCTL</name>
          <addressOffset>0x10</addressOffset>
          <size>16</size>
          <fields>
            <field>
              <name>LOADAMODE</name>
              <bitRange>[1:0]</bitRange>
            </field>
            <field>
              <name>LOADBMODE</name>
              <bitRange>[3:2]</bitRange>
            </field>
            <field>
              <name>SHDWAMODE</name>
              <bitRange>[4:4]</bitRange>
            </field>
            <field>
              <name>SHDWBMODE</name>
              <bitRange>[6:6]</bitRange>
            </field>
            <field>
              <name>SHDWAFULL</name>
              <bitRange>[8:8]</bitRange>
              <access>read-only</access>
            </field>
            <field>
              <name>SHDWBFULL</name>
              <bitRange>[9:9]</bitRange>
              <access>read-only</access>
            </field>
            <field>
              <name>LOADASYNC</name>
              <bitRange>[11:10]</bitRange>
            </field>
            <field>
              <name>LOADBSYNC</name>
              <bitRange>[13:12]</bitRange>
            </field>
          </fields>
        </register>
        <register>
          <name>CMPCTL2</name>
          <addressOffset>0x12</addressOffset>
          <size>16</size>
          <fields>
            <field>
              <name>LOADCMODE</name>
              <bitRange>[1:0]</bitRange>
            </field>
            <field>
              <name>LOADDMODE</name>
              <bitRange>[3:2]</bitRange>
            </field>
            <field>
              <name>SHDWCMODE</name>
              <bitRange>[4:4]</bitRange>
            </field>
            <field>
              <name>SHDWDMODE</name>
              <bitRange>[6:6]</bitRange>
            </field>
            <field>
              <name>LOADCSYNC</name>
              <bitRange>[11:10]</bitRange>
            </field>
            <field>
              <name>LOADDSYNC</name>
              <bitRange>[13:12]</bitRange>
            </field>
          </fields>
        </register>
        <register>
          <name>DBCTL</name>
          <addressOffset>0x18</addressOffset>
          <size>16</size>
          <fields>
            <field>
              <name>OUT_MODE</name>
              <bitRange>[1:0]</bitRange>
            </field>
            <field>
              <name>POLSEL</name>
              <bitRange>[3:2]</bitRange>
            </field>
            <field>
              <name>IN_MODE</name>
              <bitRange>[5:4]</bitRange>
            </field>
            <field>
              <name>LOADREDMODE</name>
              <bitRange>[7:6]</bitRange>
            </field>
            <field>
              <name>LOADFEDMODE</name>
              <bitRange>[9:8]</bitRange>
            </field>
            <field>
              <name>SHDWDBRED_MODE</name>
              <bitRange>[10:10]</bitRange>
            </field>
            <field>
              <name>SHDWDBFED_MODE</name>
              <bitRange>[11:11]</bitRange>
            </field>
            <field>
              <name>OUTSWAP</name>
              <bitRange>[13:12]</bitRange>
            </field>
            <field>
              <name>DEDB_MODE</name>
              <bitRange>[14:14]</bitRange>
            </field>
            <field>
              <name>HALFCYCLE</name>
              <bitRange>[15:15]</bitRange>
            </field>
          </fields>
        </register>
        <register>
          <name>DBCTL2</name>
          <addressOffset>0x1A</addressOffset>
          <size>16</size>
          <fields>
            <field>
              <name>LOADDBCTLMODE</name>
              <bitRange>[1:0]</bitRange>
            </field>
            <field>
              <name>SHDWDBCTLMODE</name>
              <bitRange>[2:2]</bitRange>
            </field>
          </fields>
        </register>
        <register>
          <name>AQCTL</name>
          <addressOffset>0x20</addressOffset>
          <size>16</size>
          <fields>
            <field>
              <name>LDAQAMODE</name>
              <bitRange>[1:0]</bitRange>
            </field>
            <field>
              <name>LDAQBMODE</name>
              <bitRange>[3:2]</bitRange>
            </field>
            <field>
              <name>SHDWAQAMODE</name>
              <bitRange>[4:4]</bitRange>
            </field>
            <field>
              <name>SHDWAQBMODE</name>
              <bitRange>[6:6]</bitRange>
            </field>
            <field>
              <name>LDAQASYNC</name>
              <bitRange>[9:8]</bitRange>
            </field>
            <field>
              <name>LDAQBSYNC</name>
              <bitRange>[11:10]</bitRange>
            </field>
          </fields>
        </register>
        <register>
          <name>AQTSRCSEL</name>
          <addressOffset>0x22</addressOffset>
          <size>16</size>
          <fields>
            <field>
              <name>T1SEL</name>
              <bitRange>[3:0]</bitRange>
            </field>
            <field>
              <name>T2SEL</name>
              <bitRange>[7:4]</bitRange>
            </field>
          </fields>
        </register>
        <register>
          <name>PCCTL</name>
          <addressOffset>0x28</addressOffset>
          <size>16</size>
          <fields>
            <field>
              <name>CHPEN</name>
              <bitRange>[0:0]</bitRange>
            </field>
            <field>
              <name>OSHTWTH</name>
              <bitRange>[4:1]</bitRange>
            </field>
            <field>
              <name>CHPFREQ</name>
              <bitRange>[7:5]</bitRange>
            </field>
            <field>
              <name>CHPDUTY</name>
              <bitRange>[10:8]</bitRange>
            </field>
          </fields>
        </register>
        <register>
          <name>VCAPCTL</name>
          <addressOffset>0x30</addressOffset>
          <size>16</size>
          <fields>
            <field>
              <name>VCAPE</name>
              <bitRange>[0:0]</bitRange>
            </field>
            <field>
              <name>VCAPSTART</name>
              <bitRange>[1:1]</bitRange>
            </field>
            <field>
              <name>TRIGSEL</name>
              <bitRange>[4:2]</bitRange>
            </field>
            <field>
              <name>VDELAYDIV</name>
              <bitRange>[9:7]</bitRange>
            </field>
            <field>
              <name>EDGEFILTDLYSEL</name>
              <bitRange>[10:10]</bitRange>
            </field>
          </fields>
        </register>
        <register>
          <name>VCNTCFG</name>
          <addressOffset>0x32</addressOffset>
          <size>16</size>
          <fields>
            <field>
              <name>STARTEDGE</name>
              <bitRange>[3:0]</bitRange>
            </field>
            <field>
              <name>STARTEDGESTS</name>
              <bitRange>[7:7]</bitRange>
              <access>read-only</access>
            </field>
            <field>
              <name>STOPEDGE</name>
              <bitRange>[11:8]</bitRange>
            </field>
            <field>
              <name>STOPEDGESTS</name>
              <bitRange>[15:15]</bitRange>
              <access>read-only</access>
            </field>
          </fields>
        </register>
        <register>
          <name>HRCNFG</name>
          <addressOffset>0x40</addressOffset>
          <size>16</size>
          <fields>
            <field>
              <name>EDGMODE</name>
              <bitRange>[1:0]</bitRange>
            </field>
            <field>
              <name>CTLMODE</name>
              <bitRange>[2:2]</bitRange>
            </field>
            <field>
              <name>HRLOAD</name>
              <bitRange>[4:3]</bitRange>
            </field>
            <field>
              <name>SELOUTB</name>
              <bitRange>[5:5]</bitRange>
            </field>
            <field>
              <name>AUTOCONV</name>
              <bitRange>[6:6]</bitRange>
            </field>
            <field>
              <name>SWAPAB</name>
              <bitRange>[7:7]</bitRange>
            </field>
            <field>
              <name>EDGMODEB</name>
              <bitRange>[9:8]</bitRange>
            </field>
            <field>
              <name>CTLMODEB</name>
              <bitRange>[10:10]</bitRange>
            </field>
            <field>
              <name>HRLOADB</name>
              <bitRange>[12:11]</bitRange>
            </field>
          </fields>
        </register>
        <register>
          <name>HRPWR</name>
          <addressOffset>0x42</addressOffset>
          <size>16</size>
          <fields>
            <field>
              <name>CALPWRON</name>
              <bitRange>[15:15]</bitRange>
            </field>
          </fields>
        </register>
        <register>
          <name>HRMSTEP</name>
          <addressOffset>0x4C</addressOffset>
          <size>16</size>
          <fields>
            <field>
              <name>HRMSTEP</name>
              <bitRange>[7:0]</bitRange>
            </field>
          </fields>
        </register>
        <register>
          <name>HRCNFG2</name>
          <addressOffset>0x4E</addressOffset>
          <size>16</size>
          <fields>
            <field>
              <name>EDGMODEDB</name>
              <bitRange>[1:0]</bitRange>
            </field>
            <field>
              <name>CTLMODEDBRED</name>
              <bitRange>[3:2]</bitRange>
            </field>
            <field>
              <name>CTLMODEDBFED</name>
              <bitRange>[5:4]</bitRange>
            </field>
          </fields>
        </register>
        <register>
          <name>HRPCTL</name>
          <addressOffset>0x5A</addressOffset>
          <size>16</size>
          <fields>
            <field>
              <name>HRPE</name>
              <bitRange>[0:0]</bitRange>
            </field>
            <field>
              <name>PWMSYNCSEL</name>
              <bitRange>[1:1]</bitRange>
            </field>
            <field>
              <name>TBPHSHRLOADE</name>
              <bitRange>[2:2]</bitRange>
            </field>
            <field>
              <name>PWMSYNCSELX</name>
              <bitRange>[6:4]</bitRange>
            </field>
          </fields>
        </register>
        <register>
          <name>TRREM</name>
          <addressOffset>0x5C</addressOffset>
          <size>16</size>
          <fields>
            <field>
              <name>TREEM</name>
              <bitRange>[10:0]</bitRange>
            </field>
          </fields>
        </register>
        <register>
          <name>GLDCTL</name>
          <addressOffset>0x68</addressOffset>
          <size>16</size>
          <fields>
            <field>
              <name>GLD</name>
              <bitRange>[0:0]</bitRange>
            </field>
            <field>
              <name>GLDMODE</name>
              <bitRange>[4:1]</bitRange>
            </field>
            <field>
              <name>OSHTMODE</name>
              <bitRange>[5:5]</bitRange>
            </field>
            <field>
              <name>GLDPRD</name>
              <bitRange>[9:7]</bitRange>
            </field>
            <field>
              <name>GLDCNT</name>
              <bitRange>[12:10]</bitRange>
              <access>read-only</access>
            </field>
          </fields>
        </register>
        <register>
          <name>GLDCFG</name>
          <addressOffset>0x6A</addressOffset>
          <size>16</size>
          <fields>
            <field>
              <name>TBPRD_TBPRDRHR</name>
              <bitRange>[0:0]</bitRange>
            </field>
            <field>
              <name>CMPA_CMPAHR</name>
              <bitRange>[1:1]</bitRange>
            </field>
            <field>
              <name>CMPB_CMPBHR</name>
              <bitRange>[2:2]</bitRange>
            </field>
            <field>
              <name>CMPC</name>
              <bitRange>[3:3]</bitRange>
            </field>
            <field>
              <name>CMPD</name>
              <bitRange>[4:4]</bitRange>
            </field>
            <field>
              <name>DBRED_DBREDHR</name>
              <bitRange>[5:5]</bitRange>
            </field>
            <field>
              <name>DBFED_DBFEDHR</name>
              <bitRange>[6:6]</bitRange>
            </field>
            <field>
              <name>DBCTL</name>
              <bitRange>[7:7]</bitRange>
            </field>
            <field>
              <name>AQCTLA_AQCTLA2</name>
              <bitRange>[8:8]</bitRange>
            </field>
            <field>
              <name>AQCTLB_AQCTLB2</name>
              <bitRange>[9:9]</bitRange>
            </field>
            <field>
              <name>AQCSPRC</name>
              <bitRange>[10:10]</bitRange>
            </field>
          </fields>
        </register>
        <register>
          <name>PWMXLINK</name>
          <addressOffset>0x70</addressOffset>
          <fields>
            <field>
              <name>TBPRDLINK</name>
              <bitRange>[3:0]</bitRange>
            </field>
            <field>
              <name>CMPALINK</name>
              <bitRange>[7:4]</bitRange>
            </field>
            <field>
              <name>CMPBLINK</name>
              <bitRange>[11:8]</bitRange>
            </field>
            <field>
              <name>CMPCLINK</name>
              <bitRange>[15:12]</bitRange>
            </field>
            <field>
              <name>CMPDLINK</name>
              <bitRange>[19:16]</bitRange>
            </field>
            <field>
              <name>GLDCTL2LINK</name>
              <bitRange>[31:28]</bitRange>
            </field>
          </fields>
        </register>
        <register>
          <name>AQCTLA</name>
          <addressOffset>0x80</addressOffset>
          <size>16</size>
          <fields>
            <field>
              <name>ZRO</name>
              <bitRange>[1:0]</bitRange>
            </field>
            <field>
              <name>PRD</name>
              <bitRange>[3:2]</bitRange>
            </field>
            <field>
              <name>CAU</name>
              <bitRange>[5:4]</bitRange>
            </field>
            <field>
              <name>CAD</name>
              <bitRange>[7:6]</bitRange>
            </field>
            <field>
              <name>CBU</name>
              <bitRange>[9:8]</bitRange>
            </field>
            <field>
              <name>CBD</name>
              <bitRange>[11:10]</bitRange>
            </field>
          </fields>
        </register>
        <register>
          <name>AQCTLA2</name>
          <addressOffset>0x82</addressOffset>
          <size>16</size>
          <fields>
            <field>
              <name>T1U</name>
              <bitRange>[1:0]</bitRange>
            </field>
            <field>
              <name>T1D</name>
              <bitRange>[3:2]</bitRange>
            </field>
            <field>
              <name>T2U</name>
              <bitRange>[5:4]</bitRange>
            </field>
            <field>
              <name>T2D</name>
              <bitRange>[7:6]</bitRange>
            </field>
          </fields>
        </register>
        <register>
          <name>AQCTLB</name>
          <addressOffset>0x84</addressOffset>
          <size>16</size>
          <fields>
            <field>
              <name>ZRO</name>
              <bitRange>[1:0]</bitRange>
            </field>
            <field>
              <name>PRD</name>
              <bitRange>[3:2]</bitRange>
            </field>
            <field>
              <name>CAU</name>
              <bitRange>[5:4]</bitRange>
            </field>
            <field>
              <name>CAD</name>
              <bitRange>[7:6]</bitRange>
            </field>
            <field>
              <name>CBU</name>
              <bitRange>[9:8]</bitRange>
            </field>
            <field>
              <name>CBD</name>
              <bitRange>[11:10]</bitRange>
            </field>
          </fields>
        </register>
        <register>
          <name>AQCTLB2</name>
          <addressOffset>0x86</addressOffset>
          <size>16</size>
          <fields>
            <field>
              <name>T1U</name>
              <bitRange>[1:0]</bitRange>
            </field>
            <field>
              <name>T1D</name>
              <bitRange>[3:2]</bitRange>
            </field>
            <field>
              <name>T2U</name>
              <bitRange>[5:4]</bitRange>
            </field>
            <field>
              <name>T2D</name>
              <bitRange>[7:6]</bitRange>
            </field>
          </fields>
        </register>
        <register>
          <name>AQSFRC</name>
          <addressOffset>0x8E</addressOffset>
          <size>16</size>
          <fields>
            <field>
              <name>ACTSFA</name>
              <bitRange>[1:0]</bitRange>
            </field>
            <field>
              <name>OTSFA</name>
              <bitRange>[2:2]</bitRange>
            </field>
            <field>
              <name>ACTSFB</name>
              <bitRange>[4:3]</bitRange>
            </field>
            <field>
              <name>OTSFB</name>
              <bitRange>[5:5]</bitRange>
            </field>
            <field>
              <name>RLDCSF</name>
              <bitRange>[7:6]</bitRange>
            </field>
          </fields>
        </register>
        <register>
          <name>AQCSPFRC</name>
          <addressOffset>0x92</addressOffset>
          <size>16</size>
          <fields>
            <field>
              <name>CSFA</name>
              <bitRange>[1:0]</bitRange>
            </field>
            <field>
              <name>CSFB</name>
              <bitRange>[3:2]</bitRange>
            </field>
          </fields>
        </register>
        <register>
          <name>DBREDHR</name>
          <addressOffset>0xA0</addressOffset>
          <size>16</size>
          <fields>
            <field>
              <name>DBREDHR</name>
              <bitRange>[15:9]</bitRange>
            </field>
          </fields>
        </register>
        <register>
          <name>DBRED</name>
          <addressOffset>0xA2</addressOffset>
          <size>16</size>
          <fields>
            <field>
              <name>DBRED</name>
              <bitRange>[13:0]</bitRange>
            </field>
          </fields>
        </register>
        <register>
          <name>DBFEDHR</name>
          <addressOffset>0xA4</addressOffset>
          <size>16</size>
          <fields>
            <field>
              <name>DBFEDHR</name>
              <bitRange>[15:9]</bitRange>
            </field>
          </fields>
        </register>
        <register>
          <name>DBFED</name>
          <addressOffset>0xA6</addressOffset>
          <size>16</size>
          <fields>
            <field>
              <name>DBFED</name>
              <bitRange>[13:0]</bitRange>
            </field>
          </fields>
        </register>
        <register>
          <name>TBPHS</name>
          <addressOffset>0xC0</addressOffset>
          <fields>
            <field>
              <name>TBPHSHR</name>
              <bitRange>[15:0]</bitRange>
            </field>
            <field>
              <name>TBPHS</name>
              <bitRange>[31:16]</bitRange>
            </field>
          </fields>
        </register>
        <register>
          <name>TBPRDHR</name>
          <addressOffset>0xC4</addressOffset>
          <size>16</size>
          <fields>
            <field>
              <name>TBPRDHR</name>
              <bitRange>[15:0]</bitRange>
            </field>
          </fields>
        </register>
        <register>
          <name>TBPRD</name>
          <addressOffset>0xC6</addressOffset>
          <size>16</size>
          <fields>
            <field>
              <name>TBPRD</name>
              <bitRange>[15:0]</bitRange>
            </field>
          </fields>
        </register>
        <register>
          <name>CMPA</name>
          <addressOffset>0xD4</addressOffset>
          <fields>
            <field>
              <name>CMPAHR</name>
              <bitRange>[15:0]</bitRange>
            </field>
            <field>
              <name>CMPA</name>
              <bitRange>[31:16]</bitRange>
            </field>
          </fields>
        </register>
        <register>
          <name>CMPB</name>
          <addressOffset>0xD8</addressOffset>
          <fields>
            <field>
              <name>CMPBHR</name>
              <bitRange>[15:0]</bitRange>
            </field>
            <field>
              <name>CMPB</name>
              <bitRange>[31:16]</bitRange>
            </field>
          </fields>
        </register>
        <register>
          <name>CMPC</name>
          <addressOffset>0xDE</addressOffset>
          <size>16</size>
          <fields>
            <field>
              <name>CMPC</name>
              <bitRange>[15:0]</bitRange>
            </field>
          </fields>
        </register>
        <register>
          <name>CMPD</name>
          <addressOffset>0xE2</addressOffset>
          <size>16</size>
          <fields>
            <field>
              <name>CMPD</name>
              <bitRange>[15:0]</bitRange>
            </field>
          </fields>
        </register>
        <register>
          <name>GLDCTL2</name>
          <addressOffset>0xE8</addressOffset>
          <size>16</size>
          <fields>
            <field>
              <name>OSHTLD</name>
              <bitRange>[0:0]</bitRange>
            </field>
            <field>
              <name>GFRCLD</name>
              <bitRange>[1:1]</bitRange>
            </field>
          </fields>
        </register>
        <register>
          <name>SWVDELVAL</name>
          <addressOffset>0xEE</addressOffset>
          <size>16</size>
          <fields>
            <field>
              <name>SWVDELVAL</name>
              <bitRange>[15:0]</bitRange>
            </field>
          </fields>
        </register>
        <register>
          <name>TZSEL</name>
          <addressOffset>0x100</addressOffset>
          <size>16</size>
          <fields>
            <field>
              <name>CBC1</name>
              <bitRange>[0:0]</bitRange>
            </field>
            <field>
              <name>CBC2</name>
              <bitRange>[1:1]</bitRange>
            </field>
            <field>
              <name>CBC3</name>
              <bitRange>[2:2]</bitRange>
            </field>
            <field>
              <name>CBC4</name>
              <bitRange>[3:3]</bitRange>
            </field>
            <field>
              <name>CBC5</name>
              <bitRange>[4:4]</bitRange>
            </field>
            <field>
              <name>CBC6</name>
              <bitRange>[5:5]</bitRange>
            </field>
            <field>
              <name>DCAEVT2</name>
              <bitRange>[6:6]</bitRange>
            </field>
            <field>
              <name>DCBEVT2</name>
              <bitRange>[7:7]</bitRange>
            </field>
            <field>
              <name>OSHT1</name>
              <bitRange>[8:8]</bitRange>
            </field>
            <field>
              <name>OSHT2</name>
              <bitRange>[9:9]</bitRange>
            </field>
            <field>
              <name>OSHT3</name>
              <bitRange>[10:10]</bitRange>
            </field>
            <field>
              <name>OSHT4</name>
              <bitRange>[11:11]</bitRange>
            </field>
            <field>
              <name>OSHT5</name>
              <bitRange>[12:12]</bitRange>
            </field>
            <field>
              <name>OSHT6</name>
              <bitRange>[13:13]</bitRange>
            </field>
            <field>
              <name>DCAEVT1</name>
              <bitRange>[14:14]</bitRange>
            </field>
            <field>
              <name>DCBEVT1</name>
              <bitRange>[15:15]</bitRange>
            </field>
          </fields>
        </register>
        <register>
          <name>TZDCSEL</name>
          <addressOffset>0x104</addressOffset>
          <size>16</size>
          <fields>
            <field>
              <name>DCAEVT1</name>
              <bitRange>[2:0]</bitRange>
            </field>
            <field>
              <name>DCAEVT2</name>
              <bitRange>[5:3]</bitRange>
            </field>
            <field>
              <name>DCBEVT1</name>
              <bitRange>[8:6]</bitRange>
            </field>
            <field>
              <name>DCBEVT2</name>
              <bitRange>[11:9]</bitRange>
            </field>
          </fields>
        </register>
        <register>
          <name>TZCTL</name>
          <addressOffset>0x108</addressOffset>
          <size>16</size>
          <fields>
            <field>
              <name>TZA</name>
              <bitRange>[1:0]</bitRange>
            </field>
            <field>
              <name>TZB</name>
              <bitRange>[3:2]</bitRange>
            </field>
            <field>
              <name>DCAEVT1</name>
              <bitRange>[5:4]</bitRange>
            </field>
            <field>
              <name>DCAEVT2</name>
              <bitRange>[7:6]</bitRange>
            </field>
            <field>
              <name>DCBEVT1</name>
              <bitRange>[9:8]</bitRange>
            </field>
            <field>
              <name>DCBEVT2</name>
              <bitRange>[11:10]</bitRange>
            </field>
          </fields>
        </register>
        <register>
          <name>TZCTL2</name>
          <addressOffset>0x10A</addressOffset>
          <size>16</size>
          <fields>
            <field>
              <name>TZAU</name>
              <bitRange>[2:0]</bitRange>
            </field>
            <field>
              <name>TZAD</name>
              <bitRange>[5:3]</bitRange>
            </field>
            <field>
              <name>TZBU</name>
              <bitRange>[8:6]</bitRange>
            </field>
            <field>
              <name>TZBD</name>
              <bitRange>[11:9]</bitRange>
            </field>
            <field>
              <name>ETZE</name>
              <bitRange>[15:15]</bitRange>
            </field>
          </fields>
        </register>
        <register>
          <name>TZCTLDCA</name>
          <addressOffset>0x10C</addressOffset>
          <size>16</size>
          <fields>
            <field>
              <name>DCAEVT1U</name>
              <bitRange>[2:0]</bitRange>
            </field>
            <field>
              <name>DCAEVT1D</name>
              <bitRange>[5:3]</bitRange>
            </field>
            <field>
              <name>DCAEVT2U</name>
              <bitRange>[8:6]</bitRange>
            </field>
            <field>
              <name>DCAEVT2D</name>
              <bitRange>[11:9]</bitRange>
            </field>
          </fields>
        </register>
        <register>
          <name>TZCTLDCB</name>
          <addressOffset>0x10E</addressOffset>
          <size>16</size>
          <fields>
            <field>
              <name>DCBEVT1U</name>
              <bitRange>[2:0]</bitRange>
            </field>
            <field>
              <name>DCBEVT1D</name>
              <bitRange>[5:3]</bitRange>
            </field>
            <field>
              <name>DCBEVT2U</name>
              <bitRange>[8:6]</bitRange>
            </field>
            <field>
              <name>DCBEVT2D</name>
              <bitRange>[11:9]</bitRange>
            </field>
          </fields>
        </register>
        <register>
          <name>TZEINT</name>
          <addressOffset>0x11A</addressOffset>
          <size>16</size>
          <fields>
            <field>
              <name>CBC</name>
              <bitRange>[1:1]</bitRange>
            </field>
            <field>
              <name>OST</name>
              <bitRange>[2:2]</bitRange>
            </field>
            <field>
              <name>DCAEVT1</name>
              <bitRange>[3:3]</bitRange>
            </field>
            <field>
              <name>DCAEVT2</name>
              <bitRange>[4:4]</bitRange>
            </field>
            <field>
              <name>DCBEVT1</name>
              <bitRange>[5:5]</bitRange>
            </field>
            <field>
              <name>DCBEVT2</name>
              <bitRange>[6:6]</bitRange>
            </field>
          </fields>
        </register>
        <register>
          <name>TZFLG</name>
          <addressOffset>0x126</addressOffset>
          <size>16</size>
          <fields>
            <field>
              <name>INT</name>
              <bitRange>[0:0]</bitRange>
              <access>read-only</access>
            </field>
            <field>
              <name>CBC</name>
              <bitRange>[1:1]</bitRange>
              <access>read-only</access>
            </field>
            <field>
              <name>OST</name>
              <bitRange>[2:2]</bitRange>
              <access>read-only</access>
            </field>
            <field>
              <name>DCAEVT1</name>
              <bitRange>[3:3]</bitRange>
              <access>read-only</access>
            </field>
            <field>
              <name>DCAEVT2</name>
              <bitRange>[4:4]</bitRange>
              <access>read-only</access>
            </field>
            <field>
              <name>DCBEVT1</name>
              <bitRange>[5:5]</bitRange>
              <access>read-only</access>
            </field>
            <field>
              <name>DCBEVT2</name>
              <bitRange>[6:6]</bitRange>
              <access>read-only</access>
            </field>
          </fields>
        </register>
        <register>
          <name>TZCBCFLG</name>
          <addressOffset>0x128</addressOffset>
          <size>16</size>
          <fields>
            <field>
              <name>CBC1</name>
              <bitRange>[0:0]</bitRange>
              <access>read-only</access>
            </field>
            <field>
              <name>CBC2</name>
              <bitRange>[1:1]</bitRange>
              <access>read-only</access>
            </field>
            <field>
              <name>CBC3</name>
              <bitRange>[2:2]</bitRange>
              <access>read-only</access>
            </field>
            <field>
              <name>CBC4</name>
              <bitRange>[3:3]</bitRange>
              <access>read-only</access>
            </field>
            <field>
              <name>CBC5</name>
              <bitRange>[4:4]</bitRange>
              <access>read-only</access>
            </field>
            <field>
              <name>CBC6</name>
              <bitRange>[5:5]</bitRange>
              <access>read-only</access>
            </field>
            <field>
              <name>DCAEVT2</name>
              <bitRange>[6:6]</bitRange>
              <access>read-only</access>
            </field>
            <field>
              <name>DCBEVT2</name>
              <bitRange>[7:7]</bitRange>
              <access>read-only</access>
            </field>
          </fields>
        </register>
        <register>
          <name>TZOSTFLG</name>
          <addressOffset>0x12A</addressOffset>
          <size>16</size>
          <fields>
            <field>
              <name>OST1</name>
              <bitRange>[0:0]</bitRange>
              <access>read-only</access>
            </field>
            <field>
              <name>OST2</name>
              <bitRange>[1:1]</bitRange>
              <access>read-only</access>
            </field>
            <field>
              <name>OST3</name>
              <bitRange>[2:2]</bitRange>
              <access>read-only</access>
            </field>
            <field>
              <name>OST4</name>
              <bitRange>[3:3]</bitRange>
              <access>read-only</access>
            </field>
            <field>
              <name>OST5</name>
              <bitRange>[4:4]</bitRange>
              <access>read-only</access>
            </field>
            <field>
              <name>OST6</name>
              <bitRange>[5:5]</bitRange>
              <access>read-only</access>
            </field>
            <field>
              <name>DCAEVT1</name>
              <bitRange>[6:6]</bitRange>
              <access>read-only</access>
            </field>
            <field>
              <name>DCBEVT1</name>
              <bitRange>[7:7]</bitRange>
              <access>read-only</access>
            </field>
          </fields>
        </register>
        <register>
          <name>TZCLR</name>
          <addressOffset>0x12E</addressOffset>
          <size>16</size>
          <fields>
            <field>
              <name>INT</name>
              <bitRange>[0:0]</bitRange>
            </field>
            <field>
              <name>CBC</name>
              <bitRange>[1:1]</bitRange>
            </field>
            <field>
              <name>OST</name>
              <bitRange>[2:2]</bitRange>
            </field>
            <field>
              <name>DCAEVT1</name>
              <bitRange>[3:3]</bitRange>
            </field>
            <field>
              <name>DCAEVT2</name>
              <bitRange>[4:4]</bitRange>
            </field>
            <field>
              <name>DCBEVT1</name>
              <bitRange>[5:5]</bitRange>
            </field>
            <field>
              <name>DCBEVT2</name>
              <bitRange>[6:6]</bitRange>
            </field>
            <field>
              <name>CBCPULSE</name>
              <bitRange>[15:14]</bitRange>
            </field>
          </fields>
        </register>
        <register>
          <name>TZCBCCLR</name>
          <addressOffset>0x130</addressOffset>
          <size>16</size>
          <fields>
            <field>
              <name>CBC1</name>
              <bitRange>[0:0]</bitRange>
            </field>
            <field>
              <name>CBC2</name>
              <bitRange>[1:1]</bitRange>
            </field>
            <field>
              <name>CBC3</name>
              <bitRange>[2:2]</bitRange>
            </field>
            <field>
              <name>CBC4</name>
              <bitRange>[3:3]</bitRange>
            </field>
            <field>
              <name>CBC5</name>
              <bitRange>[4:4]</bitRange>
            </field>
            <field>
              <name>CBC6</name>
              <bitRange>[5:5]</bitRange>
            </field>
            <field>
              <name>DCAEVT2</name>
              <bitRange>[6:6]</bitRange>
            </field>
            <field>
              <name>DCBEVT2</name>
              <bitRange>[7:7]</bitRange>
            </field>
          </fields>
        </register>
        <register>
          <name>TZOSTCLR</name>
          <addressOffset>0x132</addressOffset>
          <size>16</size>
          <fields>
            <field>
              <name>OST1</name>
              <bitRange>[0:0]</bitRange>
            </field>
            <field>
              <name>OST2</name>
              <bitRange>[1:1]</bitRange>
            </field>
            <field>
              <name>OST3</name>
              <bitRange>[2:2]</bitRange>
            </field>
            <field>
              <name>OST4</name>
              <bitRange>[3:3]</bitRange>
            </field>
            <field>
              <name>OST5</name>
              <bitRange>[4:4]</bitRange>
            </field>
            <field>
              <name>OST6</name>
              <bitRange>[5:5]</bitRange>
            </field>
            <field>
              <name>DCAEVT1</name>
              <bitRange>[6:6]</bitRange>
            </field>
            <field>
              <name>DCBEVT1</name>
              <bitRange>[7:7]</bitRange>
            </field>
          </fields>
        </register>
        <register>
          <name>TZFRC</name>
          <addressOffset>0x136</addressOffset>
          <size>16</size>
          <fields>
            <field>
              <name>CBC</name>
              <bitRange>[1:1]</bitRange>
            </field>
            <field>
              <name>OST</name>
              <bitRange>[2:2]</bitRange>
            </field>
            <field>
              <name>DCAEVT1</name>
              <bitRange>[3:3]</bitRange>
            </field>
            <field>
              <name>DCAEVT2</name>
              <bitRange>[4:4]</bitRange>
            </field>
            <field>
              <name>DCBEVT1</name>
              <bitRange>[5:5]</bitRange>
            </field>
            <field>
              <name>DCBEVT2</name>
              <bitRange>[6:6]</bitRange>
            </field>
          </fields>
        </register>
        <register>
          <name>ETSEL</name>
          <addressOffset>0x148</addressOffset>
          <size>16</size>
          <fields>
            <field>
              <name>INTSEL</name>
              <bitRange>[2:0]</bitRange>
            </field>
            <field>
              <name>INTEN</name>
              <bitRange>[3:3]</bitRange>
            </field>
            <field>
              <name>SOCASELCMP</name>
              <bitRange>[4:4]</bitRange>
            </field>
            <field>
              <name>SOCBSELCMP</name>
              <bitRange>[5:5]</bitRange>
            </field>
            <field>
              <name>INTSELCMP</name>
              <bitRange>[6:6]</bitRange>
            </field>
            <field>
              <name>SOCASEL</name>
              <bitRange>[10:8]</bitRange>
            </field>
            <field>
              <name>SOCAEN</name>
              <bitRange>[11:11]</bitRange>
            </field>
            <field>
              <name>SOCBSEL</name>
              <bitRange>[14:12]</bitRange>
            </field>
            <field>
              <name>SOCBEN</name>
              <bitRange>[15:15]</bitRange>
            </field>
          </fields>
        </register>
        <register>
          <name>ETPS</name>
          <addressOffset>0x14C</addressOffset>
          <size>16</size>
          <fields>
            <field>
              <name>INTPRD</name>
              <bitRange>[1:0]</bitRange>
            </field>
            <field>
              <name>INTCNT</name>
              <bitRange>[3:2]</bitRange>
              <access>read-only</access>
            </field>
            <field>
              <name>INTPSSEL</name>
              <bitRange>[4:4]</bitRange>
            </field>
            <field>
              <name>SOCPSSEL</name>
              <bitRange>[5:5]</bitRange>
            </field>
            <field>
              <name>SOCAPRD</name>
              <bitRange>[9:8]</bitRange>
            </field>
            <field>
              <name>SOCACNT</name>
              <bitRange>[11:10]</bitRange>
              <access>read-only</access>
            </field>
            <field>
              <name>SOCBPRD</name>
              <bitRange>[13:12]</bitRange>
            </field>
            <field>
              <name>SOCBCNT</name>
              <bitRange>[15:14]</bitRange>
              <access>read-only</access>
            </field>
          </fields>
        </register>
        <register>
          <name>ETFLG</name>
          <addressOffset>0x150</addressOffset>
          <size>16</size>
          <fields>
            <field>
              <name>INT</name>
              <bitRange>[0:0]</bitRange>
              <access>read-only</access>
            </field>
            <field>
              <name>SOCA</name>
              <bitRange>[2:2]</bitRange>
              <access>read-only</access>
            </field>
            <field>
              <name>SOCB</name>
              <bitRange>[3:3]</bitRange>
              <access>read-only</access>
            </field>
          </fields>
        </register>
        <register>
          <name>ETCLR</name>
          <addressOffset>0x154</addressOffset>
          <size>16</size>
          <fields>
            <field>
              <name>INT</name>
              <bitRange>[0:0]</bitRange>
            </field>
            <field>
              <name>SOCA</name>
              <bitRange>[2:2]</bitRange>
            </field>
            <field>
              <name>SOCB</name>
              <bitRange>[3:3]</bitRange>
            </field>
          </fields>
        </register>
        <register>
          <name>ETFRC</name>
          <addressOffset>0x158</addressOffset>
          <size>16</size>
          <fields>
            <field>
              <name>INT</name>
              <bitRange>[0:0]</bitRange>
            </field>
            <field>
              <name>SOCA</name>
              <bitRange>[2:2]</bitRange>
            </field>
            <field>
              <name>SOCB</name>
              <bitRange>[3:3]</bitRange>
            </field>
          </fields>
        </register>
        <register>
          <name>ETINTPS</name>
          <addressOffset>0x15C</addressOffset>
          <size>16</size>
          <fields>
            <field>
              <name>INTPRD2</name>
              <bitRange>[3:0]</bitRange>
            </field>
            <field>
              <name>INTCNT2</name>
              <bitRange>[7:4]</bitRange>
              <access>read-only</access>
            </field>
          </fields>
        </register>
        <register>
          <name>ETSOCPS</name>
          <addressOffset>0x160</addressOffset>
          <size>16</size>
          <fields>
            <field>
              <name>SOCAPRD2</name>
              <bitRange>[3:0]</bitRange>
            </field>
            <field>
              <name>SOCACNT2</name>
              <bitRange>[7:4]</bitRange>
              <access>read-only</access>
            </field>
            <field>
              <name>SOCBPRD2</name>
              <bitRange>[11:8]</bitRange>
            </field>
            <field>
              <name>SOCBCNT2</name>
              <bitRange>[15:12]</bitRange>
              <access>read-only</access>
            </field>
          </fields>
        </register>
        <register>
          <name>ETCNTINITCTL</name>
          <addressOffset>0x164</addressOffset>
          <size>16</size>
          <fields>
            <field>
              <name>INTINITFRC</name>
              <bitRange>[10:10]</bitRange>
            </field>
            <field>
              <name>SOCAINITFRC</name>
              <bitRange>[11:11]</bitRange>
            </field>
            <field>
              <name>SOCBINITFRC</name>
              <bitRange>[12:12]</bitRange>
            </field>
            <field>
              <name>INTINTEN</name>
              <bitRange>[13:13]</bitRange>
            </field>
            <field>
              <name>SOCAINTEN</name>
              <bitRange>[14:14]</bitRange>
            </field>
            <field>
              <name>SOCBINTEN</name>
              <bitRange>[15:15]</bitRange>
            </field>
          </fields>
        </register>
        <register>
          <name>ETCNTINIT</name>
          <addressOffset>0x168</addressOffset>
          <size>16</size>
          <fields>
            <field>
              <name>INTINT</name>
              <bitRange>[3:0]</bitRange>
            </field>
            <field>
              <name>SOCAINT</name>
              <bitRange>[7:4]</bitRange>
            </field>
            <field>
              <name>SOCBINT</name>
              <bitRange>[11:8]</bitRange>
            </field>
          </fields>
        </register>
        <register>
          <name>DCTRIPSEL</name>
          <addressOffset>0x180</addressOffset>
          <size>16</size>
          <fields>
            <field>
              <name>DCAHCOMPSEL</name>
              <bitRange>[3:0]</bitRange>
            </field>
            <field>
              <name>DCALCOMPSEL</name>
              <bitRange>[7:4]</bitRange>
            </field>
            <field>
              <name>DCBHCOMPSEL</name>
              <bitRange>[11:8]</bitRange>
            </field>
            <field>
              <name>DCBLCOMPSEL</name>
              <bitRange>[15:12]</bitRange>
            </field>
          </fields>
        </register>
        <register>
          <name>DCACTL</name>
          <addressOffset>0x186</addressOffset>
          <size>16</size>
          <fields>
            <field>
              <name>EVT1SRCSEL</name>
              <bitRange>[0:0]</bitRange>
            </field>
            <field>
              <name>EVT1FRCSYNCSEL</name>
              <bitRange>[1:1]</bitRange>
            </field>
            <field>
              <name>EVT1SOCE</name>
              <bitRange>[2:2]</bitRange>
            </field>
            <field>
              <name>EVT1SYNCE</name>
              <bitRange>[3:3]</bitRange>
            </field>
            <field>
              <name>EVT2SRCSEL</name>
              <bitRange>[8:8]</bitRange>
            </field>
            <field>
              <name>EVT2FRCSYNCSEL</name>
              <bitRange>[9:9]</bitRange>
            </field>
          </fields>
        </register>
        <register>
          <name>DCBCTL</name>
          <addressOffset>0x188</addressOffset>
          <size>16</size>
          <fields>
            <field>
              <name>EVT1SRCSEL</name>
              <bitRange>[0:0]</bitRange>
            </field>
            <field>
              <name>EVT1FRCSYNCSEL</name>
              <bitRange>[1:1]</bitRange>
            </field>
            <field>
              <name>EVT1SOCE</name>
              <bitRange>[2:2]</bitRange>
            </field>
            <field>
              <name>EVT1SYNCE</name>
              <bitRange>[3:3]</bitRange>
            </field>
            <field>
              <name>EVT2SRCSEL</name>
              <bitRange>[8:8]</bitRange>
            </field>
            <field>
              <name>EVT2FRCSYNCSEL</name>
              <bitRange>[9:9]</bitRange>
            </field>
          </fields>
        </register>
        <register>
          <name>DCFCTL</name>
          <addressOffset>0x18E</addressOffset>
          <size>16</size>
          <fields>
            <field>
              <name>SRCSEL</name>
              <bitRange>[1:0]</bitRange>
            </field>
            <field>
              <name>BLANKE</name>
              <bitRange>[2:2]</bitRange>
            </field>
            <field>
              <name>BLANKINV</name>
              <bitRange>[3:3]</bitRange>
            </field>
            <field>
              <name>PULSESEL</name>
              <bitRange>[5:4]</bitRange>
            </field>
            <field>
              <name>EDGEFILTSEL</name>
              <bitRange>[6:6]</bitRange>
            </field>
            <field>
              <name>EDGEMODE</name>
              <bitRange>[9:8]</bitRange>
            </field>
            <field>
              <name>EDGECOUNT</name>
              <bitRange>[12:10]</bitRange>
            </field>
            <field>
              <name>EDGESTATUS</name>
              <bitRange>[15:13]</bitRange>
              <access>read-only</access>
            </field>
          </fields>
        </register>
        <register>
          <name>DCCAPCTL</name>
          <addressOffset>0x190</addressOffset>
          <size>16</size>
          <fields>
            <field>
              <name>CAPE</name>
              <bitRange>[0:0]</bitRange>
            </field>
            <field>
              <name>SHDWMODE</name>
              <bitRange>[1:1]</bitRange>
            </field>
            <field>
              <name>CAPSTS</name>
              <bitRange>[13:13]</bitRange>
              <access>read-only</access>
            </field>
            <field>
              <name>CAPCLR</name>
              <bitRange>[14:14]</bitRange>
            </field>
            <field>
              <name>CAPMODE</name>
              <bitRange>[15:15]</bitRange>
            </field>
          </fields>
        </register>
        <register>
          <name>DCFOFFSET</name>
          <addressOffset>0x192</addressOffset>
          <size>16</size>
          <fields>
            <field>
              <name>DCFOFFSET</name>
              <bitRange>[15:0]</bitRange>
            </field>
          </fields>
        </register>
        <register>
          <name>DCFOFFSETCNT</name>
          <addressOffset>0x194</addressOffset>
          <size>16</size>
          <fields>
            <field>
              <name>DCFOFFSETCNT</name>
              <bitRange>[15:0]</bitRange>
              <access>read-only</access>
            </field>
          </fields>
        </register>
        <register>
          <name>DCFWINDOW</name>
          <addressOffset>0x196</addressOffset>
          <size>16</size>
          <fields>
            <field>
              <name>DCFWINDOW</name>
              <bitRange>[15:0]</bitRange>
            </field>
          </fields>
        </register>
        <register>
          <name>DCFWINDOWCNT</name>
          <addressOffset>0x198</addressOffset>
          <size>16</size>
          <fields>
            <field>
              <name>DCFWINDOWCNT</name>
              <bitRange>[15:0]</bitRange>
              <access>read-only</access>
            </field>
          </fields>
        </register>
        <register>
          <name>DCCAP</name>
          <addressOffset>0x19E</addressOffset>
          <size>16</size>
          <fields>
            <field>
              <name>DCCAP</name>
              <bitRange>[15:0]</bitRange>
              <access>read-only</access>
            </field>
          </fields>
        </register>
        <register>
          <name>DCAHTRIPSEL</name>
          <addressOffset>0x1A4</addressOffset>
          <size>16</size>
          <fields>
            <field>
              <name>TRIPINPUT1</name>
              <bitRange>[0:0]</bitRange>
            </field>
            <field>
              <name>TRIPINPUT2</name>
              <bitRange>[1:1]</bitRange>
            </field>
            <field>
              <name>TRIPINPUT3</name>
              <bitRange>[2:2]</bitRange>
            </field>
            <field>
              <name>TRIPINPUT4</name>
              <bitRange>[3:3]</bitRange>
            </field>
            <field>
              <name>TRIPINPUT5</name>
              <bitRange>[4:4]</bitRange>
            </field>
            <field>
              <name>TRIPINPUT6</name>
              <bitRange>[5:5]</bitRange>
            </field>
            <field>
              <name>TRIPINPUT7</name>
              <bitRange>[6:6]</bitRange>
            </field>
            <field>
              <name>TRIPINPUT8</name>
              <bitRange>[7:7]</bitRange>
            </field>
            <field>
              <name>TRIPINPUT9</name>
              <bitRange>[8:8]</bitRange>
            </field>
            <field>
              <name>TRIPINPUT10</name>
              <bitRange>[9:9]</bitRange>
            </field>
            <field>
              <name>TRIPINPUT11</name>
              <bitRange>[10:10]</bitRange>
            </field>
            <field>
              <name>TRIPINPUT12</name>
              <bitRange>[11:11]</bitRange>
            </field>
            <field>
              <name>TRIPINPUT14</name>
              <bitRange>[13:13]</bitRange>
            </field>
            <field>
              <name>TRIPINPUT15</name>
              <bitRange>[14:14]</bitRange>
            </field>
          </fields>
        </register>
        <register>
          <name>DCALTRIPSEL</name>
          <addressOffset>0x1A6</addressOffset>
          <size>16</size>
          <fields>
            <field>
              <name>TRIPINPUT1</name>
              <bitRange>[0:0]</bitRange>
            </field>
            <field>
              <name>TRIPINPUT2</name>
              <bitRange>[1:1]</bitRange>
            </field>
            <field>
              <name>TRIPINPUT3</name>
              <bitRange>[2:2]</bitRange>
            </field>
            <field>
              <name>TRIPINPUT4</name>
              <bitRange>[3:3]</bitRange>
            </field>
            <field>
              <name>TRIPINPUT5</name>
              <bitRange>[4:4]</bitRange>
            </field>
            <field>
              <name>TRIPINPUT6</name>
              <bitRange>[5:5]</bitRange>
            </field>
            <field>
              <name>TRIPINPUT7</name>
              <bitRange>[6:6]</bitRange>
            </field>
            <field>
              <name>TRIPINPUT8</name>
              <bitRange>[7:7]</bitRange>
            </field>
            <field>
              <name>TRIPINPUT9</name>
              <bitRange>[8:8]</bitRange>
            </field>
            <field>
              <name>TRIPINPUT10</name>
              <bitRange>[9:9]</bitRange>
            </field>
            <field>
              <name>TRIPINPUT11</name>
              <bitRange>[10:10]</bitRange>
            </field>
            <field>
              <name>TRIPINPUT12</name>
              <bitRange>[11:11]</bitRange>
            </field>
            <field>
              <name>TRIPINPUT14</name>
              <bitRange>[13:13]</bitRange>
            </field>
            <field>
              <name>TRIPINPUT15</name>
              <bitRange>[14:14]</bitRange>
            </field>
          </fields>
        </register>
        <register>
          <name>DCBHTRIPSEL</name>
          <addressOffset>0x1A8</addressOffset>
          <size>16</size>
          <fields>
            <field>
              <name>TRIPINPUT1</name>
              <bitRange>[0:0]</bitRange>
            </field>
            <field>
              <name>TRIPINPUT2</name>
              <bitRange>[1:1]</bitRange>
            </field>
            <field>
              <name>TRIPINPUT3</name>
              <bitRange>[2:2]</bitRange>
            </field>
            <field>
              <name>TRIPINPUT4</name>
              <bitRange>[3:3]</bitRange>
            </field>
            <field>
              <name>TRIPINPUT5</name>
              <bitRange>[4:4]</bitRange>
            </field>
            <field>
              <name>TRIPINPUT6</name>
              <bitRange>[5:5]</bitRange>
            </field>
            <field>
              <name>TRIPINPUT7</name>
              <bitRange>[6:6]</bitRange>
            </field>
            <field>
              <name>TRIPINPUT8</name>
              <bitRange>[7:7]</bitRange>
            </field>
            <field>
              <name>TRIPINPUT9</name>
              <bitRange>[8:8]</bitRange>
            </field>
            <field>
              <name>TRIPINPUT10</name>
              <bitRange>[9:9]</bitRange>
            </field>
            <field>
              <name>TRIPINPUT11</name>
              <bitRange>[10:10]</bitRange>
            </field>
            <field>
              <name>TRIPINPUT12</name>
              <bitRange>[11:11]</bitRange>
            </field>
            <field>
              <name>TRIPINPUT14</name>
              <bitRange>[13:13]</bitRange>
            </field>
            <field>
              <name>TRIPINPUT15</name>
              <bitRange>[14:14]</bitRange>
            </field>
          </fields>
        </register>
        <register>
          <name>DCBLTRIPSEL</name>
          <addressOffset>0x1AA</addressOffset>
          <size>16</size>
          <fields>
            <field>
              <name>TRIPINPUT1</name>
              <bitRange>[0:0]</bitRange>
            </field>
            <field>
              <name>TRIPINPUT2</name>
              <bitRange>[1:1]</bitRange>
            </field>
            <field>
              <name>TRIPINPUT3</name>
              <bitRange>[2:2]</bitRange>
            </field>
            <field>
              <name>TRIPINPUT4</name>
              <bitRange>[3:3]</bitRange>
            </field>
            <field>
              <name>TRIPINPUT5</name>
              <bitRange>[4:4]</bitRange>
            </field>
            <field>
              <name>TRIPINPUT6</name>
              <bitRange>[5:5]</bitRange>
            </field>
            <field>
              <name>TRIPINPUT7</name>
              <bitRange>[6:6]</bitRange>
            </field>
            <field>
              <name>TRIPINPUT8</name>
              <bitRange>[7:7]</bitRange>
            </field>
            <field>
              <name>TRIPINPUT9</name>
              <bitRange>[8:8]</bitRange>
            </field>
            <field>
              <name>TRIPINPUT10</name>
              <bitRange>[9:9]</bitRange>
            </field>
            <field>
              <name>TRIPINPUT11</name>
              <bitRange>[10:10]</bitRange>
            </field>
            <field>
              <name>TRIPINPUT12</name>
              <bitRange>[11:11]</bitRange>
            </field>
            <field>
              <name>TRIPINPUT14</name>
              <bitRange>[13:13]</bitRange>
            </field>
            <field>
              <name>TRIPINPUT15</name>
              <bitRange>[14:14]</bitRange>
            </field>
          </fields>
        </register>
        <register>
          <name>PWMLOCK</name>
          <addressOffset>0x1F4</addressOffset>
          <fields>
            <field>
              <name>HRLOCK</name>
              <bitRange>[0:0]</bitRange>
            </field>
            <field>
              <name>GLLOCK</name>
              <bitRange>[1:1]</bitRange>
            </field>
            <field>
              <name>TZCFGLOCK</name>
              <bitRange>[2:2]</bitRange>
            </field>
            <field>
              <name>TZCLRLOCK</name>
              <bitRange>[3:3]</bitRange>
            </field>
            <field>
              <name>DCLOCK</name>
              <bitRange>[4:4]</bitRange>
            </field>
            <field>
              <name>KEY</name>
              <bitRange>[31:16]</bitRange>
            </field>
          </fields>
        </register>
        <register>
          <name>HWVDELVAL</name>
          <addressOffset>0x1FA</addressOffset>
          <size>16</size>
          <fields>
            <field>
              <name>HWVDELVAL</name>
              <bitRange>[15:0]</bitRange>
              <access>read-only</access>
            </field>
          </fields>
        </register>
        <register>
          <name>VCNTVAL</name>
          <addressOffset>0x1FC</addressOffset>
          <size>16</size>
          <fields>
            <field>
              <name>VCNTVAL</name>
              <bitRange>[15:0]</bitRange>
              <access>read-only</access>
            </field>
          </fields>
        </register>
      </registers>
    </peripheral>
    <peripheral derivedFrom="HRPWM1">
      <name>HRPWM2</name>
      <baseAddress>0x40018400</baseAddress>
      <interrupt>
        <name>HRPWM2</name>
        <description>HRPWM2 global Interrupt</description>
        <value>52</value>
      </interrupt>
      <interrupt>
        <name>HRPWM2_TZ</name>
        <description>HRPWM2 Trip Interrupt</description>
        <value>58</value>
      </interrupt>
    </peripheral>
    <peripheral derivedFrom="HRPWM1">
      <name>HRPWM3</name>
      <baseAddress>0x40018800</baseAddress>
      <interrupt>
        <name>HRPWM3</name>
        <description>HRPWM3 global Interrupt</description>
        <value>53</value>
      </interrupt>
      <interrupt>
        <name>HRPWM3_TZ</name>
        <description>HRPWM3 Trip Interrupt</description>
        <value>59</value>
      </interrupt>
    </peripheral>
    <peripheral derivedFrom="HRPWM1">
      <name>HRPWM4</name>
      <baseAddress>0x40018C00</baseAddress>
      <interrupt>
        <name>HRPWM4</name>
        <description>HRPWM4 global Interrupt</description>
        <value>54</value>
      </interrupt>
      <interrupt>
        <name>HRPWM4_TZ</name>
        <description>HRPWM4 Trip Interrupt</description>
        <value>60</value>
      </interrupt>
    </peripheral>
    <peripheral derivedFrom="HRPWM1">
      <name>HRPWM5</name>
      <baseAddress>0x40019000</baseAddress>
      <interrupt>
        <name>HRPWM5</name>
        <description>HRPWM5 global Interrupt</description>
        <value>55</value>
      </interrupt>
      <interrupt>
        <name>HRPWM5_TZ</name>
        <description>HRPWM5 Trip Interrupt</description>
        <value>61</value>
      </interrupt>
    </peripheral>
    <peripheral derivedFrom="HRPWM1">
      <name>HRPWM6</name>
      <baseAddress>0x40019400</baseAddress>
      <interrupt>
        <name>HRPWM6</name>
        <description>HRPWM6 global Interrupt</description>
        <value>56</value>
      </interrupt>
      <interrupt>
        <name>HRPWM6_TZ</name>
        <description>HRPWM6 Trip Interrupt</description>
        <value>62</value>
      </interrupt>
    </peripheral>
    <peripheral>
      <name>HRPWMC</name>
      <baseAddress>0x40019800</baseAddress>
      <addressBlock>
        <offset>0x0</offset>
        <size>0x400</size>
        <usage>registers</usage>
      </addressBlock>
      <registers>
        <register>
          <name>IXBSEL1_2</name>
          <addressOffset>0x0</addressOffset>
          <fields>
            <field>
              <name>SEL1</name>
              <description>eallow, inputxbar_lock</description>
              <bitRange>[5:0]</bitRange>
            </field>
            <field>
              <name>SEL2</name>
              <description>eallow, inputxbar_lock</description>
              <bitRange>[21:16]</bitRange>
            </field>
          </fields>
        </register>
        <register>
          <name>IXBSEL3_4</name>
          <addressOffset>0x4</addressOffset>
          <fields>
            <field>
              <name>SEL3</name>
              <description>eallow, inputxbar_lock</description>
              <bitRange>[5:0]</bitRange>
            </field>
            <field>
              <name>SEL4</name>
              <description>eallow, inputxbar_lock</description>
              <bitRange>[21:16]</bitRange>
            </field>
          </fields>
        </register>
        <register>
          <name>IXBSEL5_6</name>
          <addressOffset>0x8</addressOffset>
          <fields>
            <field>
              <name>SEL5</name>
              <description>eallow, inputxbar_lock</description>
              <bitRange>[5:0]</bitRange>
            </field>
            <field>
              <name>SEL6</name>
              <description>eallow, inputxbar_lock</description>
              <bitRange>[21:16]</bitRange>
            </field>
          </fields>
        </register>
        <register>
          <name>IXBSEL7_8</name>
          <addressOffset>0xC</addressOffset>
          <fields>
            <field>
              <name>SEL7</name>
              <description>eallow, inputxbar_lock</description>
              <bitRange>[5:0]</bitRange>
            </field>
            <field>
              <name>SEL8</name>
              <description>eallow, inputxbar_lock</description>
              <bitRange>[21:16]</bitRange>
            </field>
          </fields>
        </register>
        <register>
          <name>IXBSEL9_10</name>
          <addressOffset>0x10</addressOffset>
          <fields>
            <field>
              <name>SEL9</name>
              <description>eallow, inputxbar_lock</description>
              <bitRange>[5:0]</bitRange>
            </field>
            <field>
              <name>SEL10</name>
              <description>eallow, inputxbar_lock</description>
              <bitRange>[21:16]</bitRange>
            </field>
          </fields>
        </register>
        <register>
          <name>IXBSEL11_12</name>
          <addressOffset>0x14</addressOffset>
          <fields>
            <field>
              <name>SEL11</name>
              <description>eallow, inputxbar_lock</description>
              <bitRange>[5:0]</bitRange>
            </field>
            <field>
              <name>SEL12</name>
              <description>eallow, inputxbar_lock</description>
              <bitRange>[21:16]</bitRange>
            </field>
          </fields>
        </register>
        <register>
          <name>IXBSEL13_14</name>
          <addressOffset>0x18</addressOffset>
          <fields>
            <field>
              <name>SEL13</name>
              <description>eallow, inputxbar_lock</description>
              <bitRange>[5:0]</bitRange>
            </field>
            <field>
              <name>SEL14</name>
              <description>eallow, inputxbar_lock</description>
              <bitRange>[21:16]</bitRange>
            </field>
          </fields>
        </register>
        <register>
          <name>IXBAQSEL</name>
          <addressOffset>0x1C</addressOffset>
          <fields>
            <field>
              <name>AQSEL1</name>
              <description>eallow</description>
              <bitRange>[1:0]</bitRange>
            </field>
            <field>
              <name>AQSEL2</name>
              <description>eallow</description>
              <bitRange>[3:2]</bitRange>
            </field>
            <field>
              <name>AQSEL3</name>
              <description>eallow, lock_fl</description>
              <bitRange>[5:4]</bitRange>
            </field>
            <field>
              <name>AQSEL4</name>
              <description>eallow, lock_fl</description>
              <bitRange>[7:6]</bitRange>
            </field>
            <field>
              <name>AQSEL5</name>
              <description>eallow, lock_fl</description>
              <bitRange>[9:8]</bitRange>
            </field>
            <field>
              <name>AQSEL6</name>
              <description>eallow, lock_fl</description>
              <bitRange>[11:10]</bitRange>
            </field>
            <field>
              <name>AQSEL7</name>
              <description>eallow, lock_fl</description>
              <bitRange>[13:12]</bitRange>
            </field>
            <field>
              <name>AQSEL8</name>
              <description>eallow, lock_fl</description>
              <bitRange>[15:14]</bitRange>
            </field>
            <field>
              <name>AQSEL9</name>
              <description>eallow, lock_fl</description>
              <bitRange>[17:16]</bitRange>
            </field>
            <field>
              <name>AQSEL10</name>
              <description>eallow, lock_fl</description>
              <bitRange>[19:18]</bitRange>
            </field>
            <field>
              <name>AQSEL11</name>
              <description>eallow, lock_fl</description>
              <bitRange>[21:20]</bitRange>
            </field>
            <field>
              <name>AQSEL12</name>
              <description>eallow, lock_fl</description>
              <bitRange>[23:22]</bitRange>
            </field>
            <field>
              <name>AQSEL13</name>
              <description>eallow, lock_fl</description>
              <bitRange>[25:24]</bitRange>
            </field>
            <field>
              <name>AQSEL14</name>
              <description>eallow, lock_fl</description>
              <bitRange>[27:26]</bitRange>
            </field>
          </fields>
        </register>
        <register>
          <name>IXBSEL_LOCK</name>
          <addressOffset>0x20</addressOffset>
          <fields>
            <field>
              <name>LOCK1</name>
              <description>eallow</description>
              <bitRange>[0:0]</bitRange>
            </field>
            <field>
              <name>LOCK2</name>
              <description>eallow</description>
              <bitRange>[1:1]</bitRange>
            </field>
            <field>
              <name>LOCK3</name>
              <description>eallow</description>
              <bitRange>[2:2]</bitRange>
            </field>
            <field>
              <name>LOCK4</name>
              <description>eallow</description>
              <bitRange>[3:3]</bitRange>
            </field>
            <field>
              <name>LOCK5</name>
              <description>eallow</description>
              <bitRange>[4:4]</bitRange>
            </field>
            <field>
              <name>LOCK6</name>
              <description>eallow</description>
              <bitRange>[5:5]</bitRange>
            </field>
            <field>
              <name>LOCK7</name>
              <description>eallow</description>
              <bitRange>[6:6]</bitRange>
            </field>
            <field>
              <name>LOCK8</name>
              <description>eallow</description>
              <bitRange>[7:7]</bitRange>
            </field>
            <field>
              <name>LOCK9</name>
              <description>eallow</description>
              <bitRange>[8:8]</bitRange>
            </field>
            <field>
              <name>LOCK10</name>
              <description>eallow</description>
              <bitRange>[9:9]</bitRange>
            </field>
            <field>
              <name>LOCK11</name>
              <description>eallow</description>
              <bitRange>[10:10]</bitRange>
            </field>
            <field>
              <name>LOCK12</name>
              <description>eallow</description>
              <bitRange>[11:11]</bitRange>
            </field>
            <field>
              <name>LOCK13</name>
              <description>eallow</description>
              <bitRange>[12:12]</bitRange>
            </field>
            <field>
              <name>LOCK14</name>
              <description>eallow</description>
              <bitRange>[13:13]</bitRange>
            </field>
            <field>
              <name>LOCK_FL</name>
              <description>eallow</description>
              <bitRange>[31:31]</bitRange>
            </field>
          </fields>
        </register>
        <register>
          <name>IXBCTRL</name>
          <addressOffset>0x24</addressOffset>
          <fields>
            <field>
              <name>ISAPRD0</name>
              <description>eallow, lock_fl</description>
              <bitRange>[7:0]</bitRange>
            </field>
            <field>
              <name>ISAPRD1</name>
              <description>eallow, lock_fl</description>
              <bitRange>[15:8]</bitRange>
            </field>
          </fields>
        </register>
        <register>
          <name>HXB4_0</name>
          <addressOffset>0x40</addressOffset>
          <fields>
            <field>
              <name>MUX0</name>
              <description>eallow, HRPWMXBAR_LOCK</description>
              <bitRange>[1:0]</bitRange>
            </field>
            <field>
              <name>MUX1</name>
              <description>eallow, HRPWMXBAR_LOCK</description>
              <bitRange>[3:2]</bitRange>
            </field>
            <field>
              <name>MUX2</name>
              <description>eallow, HRPWMXBAR_LOCK</description>
              <bitRange>[5:4]</bitRange>
            </field>
            <field>
              <name>MUX3</name>
              <description>eallow, HRPWMXBAR_LOCK</description>
              <bitRange>[7:6]</bitRange>
            </field>
            <field>
              <name>MUX4</name>
              <description>eallow, HRPWMXBAR_LOCK</description>
              <bitRange>[9:8]</bitRange>
            </field>
            <field>
              <name>MUX5</name>
              <description>eallow, HRPWMXBAR_LOCK</description>
              <bitRange>[11:10]</bitRange>
            </field>
            <field>
              <name>MUX6</name>
              <description>eallow, HRPWMXBAR_LOCK</description>
              <bitRange>[13:12]</bitRange>
            </field>
            <field>
              <name>MUX7</name>
              <description>eallow, HRPWMXBAR_LOCK</description>
              <bitRange>[15:14]</bitRange>
            </field>
            <field>
              <name>MUX8</name>
              <description>eallow, HRPWMXBAR_LOCK</description>
              <bitRange>[17:16]</bitRange>
            </field>
            <field>
              <name>MUX9</name>
              <description>eallow, HRPWMXBAR_LOCK</description>
              <bitRange>[19:18]</bitRange>
            </field>
            <field>
              <name>MUX10</name>
              <description>eallow, HRPWMXBAR_LOCK</description>
              <bitRange>[21:20]</bitRange>
            </field>
            <field>
              <name>MUX11</name>
              <description>eallow, HRPWMXBAR_LOCK</description>
              <bitRange>[23:22]</bitRange>
            </field>
            <field>
              <name>MUX12</name>
              <description>eallow, HRPWMXBAR_LOCK</description>
              <bitRange>[25:24]</bitRange>
            </field>
            <field>
              <name>MUX13</name>
              <description>eallow, HRPWMXBAR_LOCK</description>
              <bitRange>[27:26]</bitRange>
            </field>
            <field>
              <name>MUX14</name>
              <description>eallow, HRPWMXBAR_LOCK</description>
              <bitRange>[29:28]</bitRange>
            </field>
            <field>
              <name>MUX15</name>
              <description>eallow, HRPWMXBAR_LOCK</description>
              <bitRange>[31:30]</bitRange>
            </field>
          </fields>
        </register>
        <register>
          <name>HXB4_1</name>
          <addressOffset>0x44</addressOffset>
          <fields>
            <field>
              <name>MUX16</name>
              <description>eallow, HRPWMXBAR_LOCK</description>
              <bitRange>[1:0]</bitRange>
            </field>
            <field>
              <name>MUX17</name>
              <description>eallow, HRPWMXBAR_LOCK</description>
              <bitRange>[3:2]</bitRange>
            </field>
            <field>
              <name>MUX18</name>
              <description>eallow, HRPWMXBAR_LOCK</description>
              <bitRange>[5:4]</bitRange>
            </field>
            <field>
              <name>MUX19</name>
              <description>eallow, HRPWMXBAR_LOCK</description>
              <bitRange>[7:6]</bitRange>
            </field>
            <field>
              <name>MUX20</name>
              <description>eallow, HRPWMXBAR_LOCK</description>
              <bitRange>[9:8]</bitRange>
            </field>
            <field>
              <name>MUX21</name>
              <description>eallow, HRPWMXBAR_LOCK</description>
              <bitRange>[11:10]</bitRange>
            </field>
            <field>
              <name>MUX22</name>
              <description>eallow, HRPWMXBAR_LOCK</description>
              <bitRange>[13:12]</bitRange>
            </field>
            <field>
              <name>MUX23</name>
              <description>eallow, HRPWMXBAR_LOCK</description>
              <bitRange>[15:14]</bitRange>
            </field>
            <field>
              <name>MUX24</name>
              <description>eallow, HRPWMXBAR_LOCK</description>
              <bitRange>[17:16]</bitRange>
            </field>
            <field>
              <name>MUX25</name>
              <description>eallow, HRPWMXBAR_LOCK</description>
              <bitRange>[19:18]</bitRange>
            </field>
            <field>
              <name>MUX26</name>
              <description>eallow, HRPWMXBAR_LOCK</description>
              <bitRange>[21:20]</bitRange>
            </field>
            <field>
              <name>MUX27</name>
              <description>eallow, HRPWMXBAR_LOCK</description>
              <bitRange>[23:22]</bitRange>
            </field>
            <field>
              <name>MUX28</name>
              <description>eallow, HRPWMXBAR_LOCK</description>
              <bitRange>[25:24]</bitRange>
            </field>
            <field>
              <name>MUX29</name>
              <description>eallow, HRPWMXBAR_LOCK</description>
              <bitRange>[27:26]</bitRange>
            </field>
            <field>
              <name>MUX30</name>
              <description>eallow, HRPWMXBAR_LOCK</description>
              <bitRange>[29:28]</bitRange>
            </field>
            <field>
              <name>MUX31</name>
              <description>eallow, HRPWMXBAR_LOCK</description>
              <bitRange>[31:30]</bitRange>
            </field>
          </fields>
        </register>
        <register>
          <name>HXB5_0</name>
          <addressOffset>0x48</addressOffset>
          <fields>
            <field>
              <name>MUX0</name>
              <description>eallow, HRPWMXBAR_LOCK</description>
              <bitRange>[1:0]</bitRange>
            </field>
            <field>
              <name>MUX1</name>
              <description>eallow, HRPWMXBAR_LOCK</description>
              <bitRange>[3:2]</bitRange>
            </field>
            <field>
              <name>MUX2</name>
              <description>eallow, HRPWMXBAR_LOCK</description>
              <bitRange>[5:4]</bitRange>
            </field>
            <field>
              <name>MUX3</name>
              <description>eallow, HRPWMXBAR_LOCK</description>
              <bitRange>[7:6]</bitRange>
            </field>
            <field>
              <name>MUX4</name>
              <description>eallow, HRPWMXBAR_LOCK</description>
              <bitRange>[9:8]</bitRange>
            </field>
            <field>
              <name>MUX5</name>
              <description>eallow, HRPWMXBAR_LOCK</description>
              <bitRange>[11:10]</bitRange>
            </field>
            <field>
              <name>MUX6</name>
              <description>eallow, HRPWMXBAR_LOCK</description>
              <bitRange>[13:12]</bitRange>
            </field>
            <field>
              <name>MUX7</name>
              <description>eallow, HRPWMXBAR_LOCK</description>
              <bitRange>[15:14]</bitRange>
            </field>
            <field>
              <name>MUX8</name>
              <description>eallow, HRPWMXBAR_LOCK</description>
              <bitRange>[17:16]</bitRange>
            </field>
            <field>
              <name>MUX9</name>
              <description>eallow, HRPWMXBAR_LOCK</description>
              <bitRange>[19:18]</bitRange>
            </field>
            <field>
              <name>MUX10</name>
              <description>eallow, HRPWMXBAR_LOCK</description>
              <bitRange>[21:20]</bitRange>
            </field>
            <field>
              <name>MUX11</name>
              <description>eallow, HRPWMXBAR_LOCK</description>
              <bitRange>[23:22]</bitRange>
            </field>
            <field>
              <name>MUX12</name>
              <description>eallow, HRPWMXBAR_LOCK</description>
              <bitRange>[25:24]</bitRange>
            </field>
            <field>
              <name>MUX13</name>
              <description>eallow, HRPWMXBAR_LOCK</description>
              <bitRange>[27:26]</bitRange>
            </field>
            <field>
              <name>MUX14</name>
              <description>eallow, HRPWMXBAR_LOCK</description>
              <bitRange>[29:28]</bitRange>
            </field>
            <field>
              <name>MUX15</name>
              <description>eallow, HRPWMXBAR_LOCK</description>
              <bitRange>[31:30]</bitRange>
            </field>
          </fields>
        </register>
        <register>
          <name>HXB5_1</name>
          <addressOffset>0x4C</addressOffset>
          <fields>
            <field>
              <name>MUX16</name>
              <description>eallow, HRPWMXBAR_LOCK</description>
              <bitRange>[1:0]</bitRange>
            </field>
            <field>
              <name>MUX17</name>
              <description>eallow, HRPWMXBAR_LOCK</description>
              <bitRange>[3:2]</bitRange>
            </field>
            <field>
              <name>MUX18</name>
              <description>eallow, HRPWMXBAR_LOCK</description>
              <bitRange>[5:4]</bitRange>
            </field>
            <field>
              <name>MUX19</name>
              <description>eallow, HRPWMXBAR_LOCK</description>
              <bitRange>[7:6]</bitRange>
            </field>
            <field>
              <name>MUX20</name>
              <description>eallow, HRPWMXBAR_LOCK</description>
              <bitRange>[9:8]</bitRange>
            </field>
            <field>
              <name>MUX21</name>
              <description>eallow, HRPWMXBAR_LOCK</description>
              <bitRange>[11:10]</bitRange>
            </field>
            <field>
              <name>MUX22</name>
              <description>eallow, HRPWMXBAR_LOCK</description>
              <bitRange>[13:12]</bitRange>
            </field>
            <field>
              <name>MUX23</name>
              <description>eallow, HRPWMXBAR_LOCK</description>
              <bitRange>[15:14]</bitRange>
            </field>
            <field>
              <name>MUX24</name>
              <description>eallow, HRPWMXBAR_LOCK</description>
              <bitRange>[17:16]</bitRange>
            </field>
            <field>
              <name>MUX25</name>
              <description>eallow, HRPWMXBAR_LOCK</description>
              <bitRange>[19:18]</bitRange>
            </field>
            <field>
              <name>MUX26</name>
              <description>eallow, HRPWMXBAR_LOCK</description>
              <bitRange>[21:20]</bitRange>
            </field>
            <field>
              <name>MUX27</name>
              <description>eallow, HRPWMXBAR_LOCK</description>
              <bitRange>[23:22]</bitRange>
            </field>
            <field>
              <name>MUX28</name>
              <description>eallow, HRPWMXBAR_LOCK</description>
              <bitRange>[25:24]</bitRange>
            </field>
            <field>
              <name>MUX29</name>
              <description>eallow, HRPWMXBAR_LOCK</description>
              <bitRange>[27:26]</bitRange>
            </field>
            <field>
              <name>MUX30</name>
              <description>eallow, HRPWMXBAR_LOCK</description>
              <bitRange>[29:28]</bitRange>
            </field>
            <field>
              <name>MUX31</name>
              <description>eallow, HRPWMXBAR_LOCK</description>
              <bitRange>[31:30]</bitRange>
            </field>
          </fields>
        </register>
        <register>
          <name>HXB7_0</name>
          <addressOffset>0x50</addressOffset>
          <fields>
            <field>
              <name>MUX0</name>
              <description>eallow, HRPWMXBAR_LOCK</description>
              <bitRange>[1:0]</bitRange>
            </field>
            <field>
              <name>MUX1</name>
              <description>eallow, HRPWMXBAR_LOCK</description>
              <bitRange>[3:2]</bitRange>
            </field>
            <field>
              <name>MUX2</name>
              <description>eallow, HRPWMXBAR_LOCK</description>
              <bitRange>[5:4]</bitRange>
            </field>
            <field>
              <name>MUX3</name>
              <description>eallow, HRPWMXBAR_LOCK</description>
              <bitRange>[7:6]</bitRange>
            </field>
            <field>
              <name>MUX4</name>
              <description>eallow, HRPWMXBAR_LOCK</description>
              <bitRange>[9:8]</bitRange>
            </field>
            <field>
              <name>MUX5</name>
              <description>eallow, HRPWMXBAR_LOCK</description>
              <bitRange>[11:10]</bitRange>
            </field>
            <field>
              <name>MUX6</name>
              <description>eallow, HRPWMXBAR_LOCK</description>
              <bitRange>[13:12]</bitRange>
            </field>
            <field>
              <name>MUX7</name>
              <description>eallow, HRPWMXBAR_LOCK</description>
              <bitRange>[15:14]</bitRange>
            </field>
            <field>
              <name>MUX8</name>
              <description>eallow, HRPWMXBAR_LOCK</description>
              <bitRange>[17:16]</bitRange>
            </field>
            <field>
              <name>MUX9</name>
              <description>eallow, HRPWMXBAR_LOCK</description>
              <bitRange>[19:18]</bitRange>
            </field>
            <field>
              <name>MUX10</name>
              <description>eallow, HRPWMXBAR_LOCK</description>
              <bitRange>[21:20]</bitRange>
            </field>
            <field>
              <name>MUX11</name>
              <description>eallow, HRPWMXBAR_LOCK</description>
              <bitRange>[23:22]</bitRange>
            </field>
            <field>
              <name>MUX12</name>
              <description>eallow, HRPWMXBAR_LOCK</description>
              <bitRange>[25:24]</bitRange>
            </field>
            <field>
              <name>MUX13</name>
              <description>eallow, HRPWMXBAR_LOCK</description>
              <bitRange>[27:26]</bitRange>
            </field>
            <field>
              <name>MUX14</name>
              <description>eallow, HRPWMXBAR_LOCK</description>
              <bitRange>[29:28]</bitRange>
            </field>
            <field>
              <name>MUX15</name>
              <description>eallow, HRPWMXBAR_LOCK</description>
              <bitRange>[31:30]</bitRange>
            </field>
          </fields>
        </register>
        <register>
          <name>HXB7_1</name>
          <addressOffset>0x54</addressOffset>
          <fields>
            <field>
              <name>MUX16</name>
              <description>eallow, HRPWMXBAR_LOCK</description>
              <bitRange>[1:0]</bitRange>
            </field>
            <field>
              <name>MUX17</name>
              <description>eallow, HRPWMXBAR_LOCK</description>
              <bitRange>[3:2]</bitRange>
            </field>
            <field>
              <name>MUX18</name>
              <description>eallow, HRPWMXBAR_LOCK</description>
              <bitRange>[5:4]</bitRange>
            </field>
            <field>
              <name>MUX19</name>
              <description>eallow, HRPWMXBAR_LOCK</description>
              <bitRange>[7:6]</bitRange>
            </field>
            <field>
              <name>MUX20</name>
              <description>eallow, HRPWMXBAR_LOCK</description>
              <bitRange>[9:8]</bitRange>
            </field>
            <field>
              <name>MUX21</name>
              <description>eallow, HRPWMXBAR_LOCK</description>
              <bitRange>[11:10]</bitRange>
            </field>
            <field>
              <name>MUX22</name>
              <description>eallow, HRPWMXBAR_LOCK</description>
              <bitRange>[13:12]</bitRange>
            </field>
            <field>
              <name>MUX23</name>
              <description>eallow, HRPWMXBAR_LOCK</description>
              <bitRange>[15:14]</bitRange>
            </field>
            <field>
              <name>MUX24</name>
              <description>eallow, HRPWMXBAR_LOCK</description>
              <bitRange>[17:16]</bitRange>
            </field>
            <field>
              <name>MUX25</name>
              <description>eallow, HRPWMXBAR_LOCK</description>
              <bitRange>[19:18]</bitRange>
            </field>
            <field>
              <name>MUX26</name>
              <description>eallow, HRPWMXBAR_LOCK</description>
              <bitRange>[21:20]</bitRange>
            </field>
            <field>
              <name>MUX27</name>
              <description>eallow, HRPWMXBAR_LOCK</description>
              <bitRange>[23:22]</bitRange>
            </field>
            <field>
              <name>MUX28</name>
              <description>eallow, HRPWMXBAR_LOCK</description>
              <bitRange>[25:24]</bitRange>
            </field>
            <field>
              <name>MUX29</name>
              <description>eallow, HRPWMXBAR_LOCK</description>
              <bitRange>[27:26]</bitRange>
            </field>
            <field>
              <name>MUX30</name>
              <description>eallow, HRPWMXBAR_LOCK</description>
              <bitRange>[29:28]</bitRange>
            </field>
            <field>
              <name>MUX31</name>
              <description>eallow, HRPWMXBAR_LOCK</description>
              <bitRange>[31:30]</bitRange>
            </field>
          </fields>
        </register>
        <register>
          <name>HXB8_0</name>
          <addressOffset>0x58</addressOffset>
          <fields>
            <field>
              <name>MUX0</name>
              <description>eallow, HRPWMXBAR_LOCK</description>
              <bitRange>[1:0]</bitRange>
            </field>
            <field>
              <name>MUX1</name>
              <description>eallow, HRPWMXBAR_LOCK</description>
              <bitRange>[3:2]</bitRange>
            </field>
            <field>
              <name>MUX2</name>
              <description>eallow, HRPWMXBAR_LOCK</description>
              <bitRange>[5:4]</bitRange>
            </field>
            <field>
              <name>MUX3</name>
              <description>eallow, HRPWMXBAR_LOCK</description>
              <bitRange>[7:6]</bitRange>
            </field>
            <field>
              <name>MUX4</name>
              <description>eallow, HRPWMXBAR_LOCK</description>
              <bitRange>[9:8]</bitRange>
            </field>
            <field>
              <name>MUX5</name>
              <description>eallow, HRPWMXBAR_LOCK</description>
              <bitRange>[11:10]</bitRange>
            </field>
            <field>
              <name>MUX6</name>
              <description>eallow, HRPWMXBAR_LOCK</description>
              <bitRange>[13:12]</bitRange>
            </field>
            <field>
              <name>MUX7</name>
              <description>eallow, HRPWMXBAR_LOCK</description>
              <bitRange>[15:14]</bitRange>
            </field>
            <field>
              <name>MUX8</name>
              <description>eallow, HRPWMXBAR_LOCK</description>
              <bitRange>[17:16]</bitRange>
            </field>
            <field>
              <name>MUX9</name>
              <description>eallow, HRPWMXBAR_LOCK</description>
              <bitRange>[19:18]</bitRange>
            </field>
            <field>
              <name>MUX10</name>
              <description>eallow, HRPWMXBAR_LOCK</description>
              <bitRange>[21:20]</bitRange>
            </field>
            <field>
              <name>MUX11</name>
              <description>eallow, HRPWMXBAR_LOCK</description>
              <bitRange>[23:22]</bitRange>
            </field>
            <field>
              <name>MUX12</name>
              <description>eallow, HRPWMXBAR_LOCK</description>
              <bitRange>[25:24]</bitRange>
            </field>
            <field>
              <name>MUX13</name>
              <description>eallow, HRPWMXBAR_LOCK</description>
              <bitRange>[27:26]</bitRange>
            </field>
            <field>
              <name>MUX14</name>
              <description>eallow, HRPWMXBAR_LOCK</description>
              <bitRange>[29:28]</bitRange>
            </field>
            <field>
              <name>MUX15</name>
              <description>eallow, HRPWMXBAR_LOCK</description>
              <bitRange>[31:30]</bitRange>
            </field>
          </fields>
        </register>
        <register>
          <name>HXB8_1</name>
          <addressOffset>0x5C</addressOffset>
          <fields>
            <field>
              <name>MUX16</name>
              <description>eallow, HRPWMXBAR_LOCK</description>
              <bitRange>[1:0]</bitRange>
            </field>
            <field>
              <name>MUX17</name>
              <description>eallow, HRPWMXBAR_LOCK</description>
              <bitRange>[3:2]</bitRange>
            </field>
            <field>
              <name>MUX18</name>
              <description>eallow, HRPWMXBAR_LOCK</description>
              <bitRange>[5:4]</bitRange>
            </field>
            <field>
              <name>MUX19</name>
              <description>eallow, HRPWMXBAR_LOCK</description>
              <bitRange>[7:6]</bitRange>
            </field>
            <field>
              <name>MUX20</name>
              <description>eallow, HRPWMXBAR_LOCK</description>
              <bitRange>[9:8]</bitRange>
            </field>
            <field>
              <name>MUX21</name>
              <description>eallow, HRPWMXBAR_LOCK</description>
              <bitRange>[11:10]</bitRange>
            </field>
            <field>
              <name>MUX22</name>
              <description>eallow, HRPWMXBAR_LOCK</description>
              <bitRange>[13:12]</bitRange>
            </field>
            <field>
              <name>MUX23</name>
              <description>eallow, HRPWMXBAR_LOCK</description>
              <bitRange>[15:14]</bitRange>
            </field>
            <field>
              <name>MUX24</name>
              <description>eallow, HRPWMXBAR_LOCK</description>
              <bitRange>[17:16]</bitRange>
            </field>
            <field>
              <name>MUX25</name>
              <description>eallow, HRPWMXBAR_LOCK</description>
              <bitRange>[19:18]</bitRange>
            </field>
            <field>
              <name>MUX26</name>
              <description>eallow, HRPWMXBAR_LOCK</description>
              <bitRange>[21:20]</bitRange>
            </field>
            <field>
              <name>MUX27</name>
              <description>eallow, HRPWMXBAR_LOCK</description>
              <bitRange>[23:22]</bitRange>
            </field>
            <field>
              <name>MUX28</name>
              <description>eallow, HRPWMXBAR_LOCK</description>
              <bitRange>[25:24]</bitRange>
            </field>
            <field>
              <name>MUX29</name>
              <description>eallow, HRPWMXBAR_LOCK</description>
              <bitRange>[27:26]</bitRange>
            </field>
            <field>
              <name>MUX30</name>
              <description>eallow, HRPWMXBAR_LOCK</description>
              <bitRange>[29:28]</bitRange>
            </field>
            <field>
              <name>MUX31</name>
              <description>eallow, HRPWMXBAR_LOCK</description>
              <bitRange>[31:30]</bitRange>
            </field>
          </fields>
        </register>
        <register>
          <name>HXB9_0</name>
          <addressOffset>0x60</addressOffset>
          <fields>
            <field>
              <name>MUX0</name>
              <description>eallow, HRPWMXBAR_LOCK</description>
              <bitRange>[1:0]</bitRange>
            </field>
            <field>
              <name>MUX1</name>
              <description>eallow, HRPWMXBAR_LOCK</description>
              <bitRange>[3:2]</bitRange>
            </field>
            <field>
              <name>MUX2</name>
              <description>eallow, HRPWMXBAR_LOCK</description>
              <bitRange>[5:4]</bitRange>
            </field>
            <field>
              <name>MUX3</name>
              <description>eallow, HRPWMXBAR_LOCK</description>
              <bitRange>[7:6]</bitRange>
            </field>
            <field>
              <name>MUX4</name>
              <description>eallow, HRPWMXBAR_LOCK</description>
              <bitRange>[9:8]</bitRange>
            </field>
            <field>
              <name>MUX5</name>
              <description>eallow, HRPWMXBAR_LOCK</description>
              <bitRange>[11:10]</bitRange>
            </field>
            <field>
              <name>MUX6</name>
              <description>eallow, HRPWMXBAR_LOCK</description>
              <bitRange>[13:12]</bitRange>
            </field>
            <field>
              <name>MUX7</name>
              <description>eallow, HRPWMXBAR_LOCK</description>
              <bitRange>[15:14]</bitRange>
            </field>
            <field>
              <name>MUX8</name>
              <description>eallow, HRPWMXBAR_LOCK</description>
              <bitRange>[17:16]</bitRange>
            </field>
            <field>
              <name>MUX9</name>
              <description>eallow, HRPWMXBAR_LOCK</description>
              <bitRange>[19:18]</bitRange>
            </field>
            <field>
              <name>MUX10</name>
              <description>eallow, HRPWMXBAR_LOCK</description>
              <bitRange>[21:20]</bitRange>
            </field>
            <field>
              <name>MUX11</name>
              <description>eallow, HRPWMXBAR_LOCK</description>
              <bitRange>[23:22]</bitRange>
            </field>
            <field>
              <name>MUX12</name>
              <description>eallow, HRPWMXBAR_LOCK</description>
              <bitRange>[25:24]</bitRange>
            </field>
            <field>
              <name>MUX13</name>
              <description>eallow, HRPWMXBAR_LOCK</description>
              <bitRange>[27:26]</bitRange>
            </field>
            <field>
              <name>MUX14</name>
              <description>eallow, HRPWMXBAR_LOCK</description>
              <bitRange>[29:28]</bitRange>
            </field>
            <field>
              <name>MUX15</name>
              <description>eallow, HRPWMXBAR_LOCK</description>
              <bitRange>[31:30]</bitRange>
            </field>
          </fields>
        </register>
        <register>
          <name>HXB9_1</name>
          <addressOffset>0x64</addressOffset>
          <fields>
            <field>
              <name>MUX16</name>
              <description>eallow, HRPWMXBAR_LOCK</description>
              <bitRange>[1:0]</bitRange>
            </field>
            <field>
              <name>MUX17</name>
              <description>eallow, HRPWMXBAR_LOCK</description>
              <bitRange>[3:2]</bitRange>
            </field>
            <field>
              <name>MUX18</name>
              <description>eallow, HRPWMXBAR_LOCK</description>
              <bitRange>[5:4]</bitRange>
            </field>
            <field>
              <name>MUX19</name>
              <description>eallow, HRPWMXBAR_LOCK</description>
              <bitRange>[7:6]</bitRange>
            </field>
            <field>
              <name>MUX20</name>
              <description>eallow, HRPWMXBAR_LOCK</description>
              <bitRange>[9:8]</bitRange>
            </field>
            <field>
              <name>MUX21</name>
              <description>eallow, HRPWMXBAR_LOCK</description>
              <bitRange>[11:10]</bitRange>
            </field>
            <field>
              <name>MUX22</name>
              <description>eallow, HRPWMXBAR_LOCK</description>
              <bitRange>[13:12]</bitRange>
            </field>
            <field>
              <name>MUX23</name>
              <description>eallow, HRPWMXBAR_LOCK</description>
              <bitRange>[15:14]</bitRange>
            </field>
            <field>
              <name>MUX24</name>
              <description>eallow, HRPWMXBAR_LOCK</description>
              <bitRange>[17:16]</bitRange>
            </field>
            <field>
              <name>MUX25</name>
              <description>eallow, HRPWMXBAR_LOCK</description>
              <bitRange>[19:18]</bitRange>
            </field>
            <field>
              <name>MUX26</name>
              <description>eallow, HRPWMXBAR_LOCK</description>
              <bitRange>[21:20]</bitRange>
            </field>
            <field>
              <name>MUX27</name>
              <description>eallow, HRPWMXBAR_LOCK</description>
              <bitRange>[23:22]</bitRange>
            </field>
            <field>
              <name>MUX28</name>
              <description>eallow, HRPWMXBAR_LOCK</description>
              <bitRange>[25:24]</bitRange>
            </field>
            <field>
              <name>MUX29</name>
              <description>eallow, HRPWMXBAR_LOCK</description>
              <bitRange>[27:26]</bitRange>
            </field>
            <field>
              <name>MUX30</name>
              <description>eallow, HRPWMXBAR_LOCK</description>
              <bitRange>[29:28]</bitRange>
            </field>
            <field>
              <name>MUX31</name>
              <description>eallow, HRPWMXBAR_LOCK</description>
              <bitRange>[31:30]</bitRange>
            </field>
          </fields>
        </register>
        <register>
          <name>HXB10_0</name>
          <addressOffset>0x68</addressOffset>
          <fields>
            <field>
              <name>MUX0</name>
              <description>eallow, HRPWMXBAR_LOCK</description>
              <bitRange>[1:0]</bitRange>
            </field>
            <field>
              <name>MUX1</name>
              <description>eallow, HRPWMXBAR_LOCK</description>
              <bitRange>[3:2]</bitRange>
            </field>
            <field>
              <name>MUX2</name>
              <description>eallow, HRPWMXBAR_LOCK</description>
              <bitRange>[5:4]</bitRange>
            </field>
            <field>
              <name>MUX3</name>
              <description>eallow, HRPWMXBAR_LOCK</description>
              <bitRange>[7:6]</bitRange>
            </field>
            <field>
              <name>MUX4</name>
              <description>eallow, HRPWMXBAR_LOCK</description>
              <bitRange>[9:8]</bitRange>
            </field>
            <field>
              <name>MUX5</name>
              <description>eallow, HRPWMXBAR_LOCK</description>
              <bitRange>[11:10]</bitRange>
            </field>
            <field>
              <name>MUX6</name>
              <description>eallow, HRPWMXBAR_LOCK</description>
              <bitRange>[13:12]</bitRange>
            </field>
            <field>
              <name>MUX7</name>
              <description>eallow, HRPWMXBAR_LOCK</description>
              <bitRange>[15:14]</bitRange>
            </field>
            <field>
              <name>MUX8</name>
              <description>eallow, HRPWMXBAR_LOCK</description>
              <bitRange>[17:16]</bitRange>
            </field>
            <field>
              <name>MUX9</name>
              <description>eallow, HRPWMXBAR_LOCK</description>
              <bitRange>[19:18]</bitRange>
            </field>
            <field>
              <name>MUX10</name>
              <description>eallow, HRPWMXBAR_LOCK</description>
              <bitRange>[21:20]</bitRange>
            </field>
            <field>
              <name>MUX11</name>
              <description>eallow, HRPWMXBAR_LOCK</description>
              <bitRange>[23:22]</bitRange>
            </field>
            <field>
              <name>MUX12</name>
              <description>eallow, HRPWMXBAR_LOCK</description>
              <bitRange>[25:24]</bitRange>
            </field>
            <field>
              <name>MUX13</name>
              <description>eallow, HRPWMXBAR_LOCK</description>
              <bitRange>[27:26]</bitRange>
            </field>
            <field>
              <name>MUX14</name>
              <description>eallow, HRPWMXBAR_LOCK</description>
              <bitRange>[29:28]</bitRange>
            </field>
            <field>
              <name>MUX15</name>
              <description>eallow, HRPWMXBAR_LOCK</description>
              <bitRange>[31:30]</bitRange>
            </field>
          </fields>
        </register>
        <register>
          <name>HXB10_1</name>
          <addressOffset>0x6C</addressOffset>
          <fields>
            <field>
              <name>MUX16</name>
              <description>eallow, HRPWMXBAR_LOCK</description>
              <bitRange>[1:0]</bitRange>
            </field>
            <field>
              <name>MUX17</name>
              <description>eallow, HRPWMXBAR_LOCK</description>
              <bitRange>[3:2]</bitRange>
            </field>
            <field>
              <name>MUX18</name>
              <description>eallow, HRPWMXBAR_LOCK</description>
              <bitRange>[5:4]</bitRange>
            </field>
            <field>
              <name>MUX19</name>
              <description>eallow, HRPWMXBAR_LOCK</description>
              <bitRange>[7:6]</bitRange>
            </field>
            <field>
              <name>MUX20</name>
              <description>eallow, HRPWMXBAR_LOCK</description>
              <bitRange>[9:8]</bitRange>
            </field>
            <field>
              <name>MUX21</name>
              <description>eallow, HRPWMXBAR_LOCK</description>
              <bitRange>[11:10]</bitRange>
            </field>
            <field>
              <name>MUX22</name>
              <description>eallow, HRPWMXBAR_LOCK</description>
              <bitRange>[13:12]</bitRange>
            </field>
            <field>
              <name>MUX23</name>
              <description>eallow, HRPWMXBAR_LOCK</description>
              <bitRange>[15:14]</bitRange>
            </field>
            <field>
              <name>MUX24</name>
              <description>eallow, HRPWMXBAR_LOCK</description>
              <bitRange>[17:16]</bitRange>
            </field>
            <field>
              <name>MUX25</name>
              <description>eallow, HRPWMXBAR_LOCK</description>
              <bitRange>[19:18]</bitRange>
            </field>
            <field>
              <name>MUX26</name>
              <description>eallow, HRPWMXBAR_LOCK</description>
              <bitRange>[21:20]</bitRange>
            </field>
            <field>
              <name>MUX27</name>
              <description>eallow, HRPWMXBAR_LOCK</description>
              <bitRange>[23:22]</bitRange>
            </field>
            <field>
              <name>MUX28</name>
              <description>eallow, HRPWMXBAR_LOCK</description>
              <bitRange>[25:24]</bitRange>
            </field>
            <field>
              <name>MUX29</name>
              <description>eallow, HRPWMXBAR_LOCK</description>
              <bitRange>[27:26]</bitRange>
            </field>
            <field>
              <name>MUX30</name>
              <description>eallow, HRPWMXBAR_LOCK</description>
              <bitRange>[29:28]</bitRange>
            </field>
            <field>
              <name>MUX31</name>
              <description>eallow, HRPWMXBAR_LOCK</description>
              <bitRange>[31:30]</bitRange>
            </field>
          </fields>
        </register>
        <register>
          <name>HXB11_0</name>
          <addressOffset>0x70</addressOffset>
          <fields>
            <field>
              <name>MUX0</name>
              <description>eallow, HRPWMXBAR_LOCK</description>
              <bitRange>[1:0]</bitRange>
            </field>
            <field>
              <name>MUX1</name>
              <description>eallow, HRPWMXBAR_LOCK</description>
              <bitRange>[3:2]</bitRange>
            </field>
            <field>
              <name>MUX2</name>
              <description>eallow, HRPWMXBAR_LOCK</description>
              <bitRange>[5:4]</bitRange>
            </field>
            <field>
              <name>MUX3</name>
              <description>eallow, HRPWMXBAR_LOCK</description>
              <bitRange>[7:6]</bitRange>
            </field>
            <field>
              <name>MUX4</name>
              <description>eallow, HRPWMXBAR_LOCK</description>
              <bitRange>[9:8]</bitRange>
            </field>
            <field>
              <name>MUX5</name>
              <description>eallow, HRPWMXBAR_LOCK</description>
              <bitRange>[11:10]</bitRange>
            </field>
            <field>
              <name>MUX6</name>
              <description>eallow, HRPWMXBAR_LOCK</description>
              <bitRange>[13:12]</bitRange>
            </field>
            <field>
              <name>MUX7</name>
              <description>eallow, HRPWMXBAR_LOCK</description>
              <bitRange>[15:14]</bitRange>
            </field>
            <field>
              <name>MUX8</name>
              <description>eallow, HRPWMXBAR_LOCK</description>
              <bitRange>[17:16]</bitRange>
            </field>
            <field>
              <name>MUX9</name>
              <description>eallow, HRPWMXBAR_LOCK</description>
              <bitRange>[19:18]</bitRange>
            </field>
            <field>
              <name>MUX10</name>
              <description>eallow, HRPWMXBAR_LOCK</description>
              <bitRange>[21:20]</bitRange>
            </field>
            <field>
              <name>MUX11</name>
              <description>eallow, HRPWMXBAR_LOCK</description>
              <bitRange>[23:22]</bitRange>
            </field>
            <field>
              <name>MUX12</name>
              <description>eallow, HRPWMXBAR_LOCK</description>
              <bitRange>[25:24]</bitRange>
            </field>
            <field>
              <name>MUX13</name>
              <description>eallow, HRPWMXBAR_LOCK</description>
              <bitRange>[27:26]</bitRange>
            </field>
            <field>
              <name>MUX14</name>
              <description>eallow, HRPWMXBAR_LOCK</description>
              <bitRange>[29:28]</bitRange>
            </field>
            <field>
              <name>MUX15</name>
              <description>eallow, HRPWMXBAR_LOCK</description>
              <bitRange>[31:30]</bitRange>
            </field>
          </fields>
        </register>
        <register>
          <name>HXB11_1</name>
          <addressOffset>0x74</addressOffset>
          <fields>
            <field>
              <name>MUX16</name>
              <description>eallow, HRPWMXBAR_LOCK</description>
              <bitRange>[1:0]</bitRange>
            </field>
            <field>
              <name>MUX17</name>
              <description>eallow, HRPWMXBAR_LOCK</description>
              <bitRange>[3:2]</bitRange>
            </field>
            <field>
              <name>MUX18</name>
              <description>eallow, HRPWMXBAR_LOCK</description>
              <bitRange>[5:4]</bitRange>
            </field>
            <field>
              <name>MUX19</name>
              <description>eallow, HRPWMXBAR_LOCK</description>
              <bitRange>[7:6]</bitRange>
            </field>
            <field>
              <name>MUX20</name>
              <description>eallow, HRPWMXBAR_LOCK</description>
              <bitRange>[9:8]</bitRange>
            </field>
            <field>
              <name>MUX21</name>
              <description>eallow, HRPWMXBAR_LOCK</description>
              <bitRange>[11:10]</bitRange>
            </field>
            <field>
              <name>MUX22</name>
              <description>eallow, HRPWMXBAR_LOCK</description>
              <bitRange>[13:12]</bitRange>
            </field>
            <field>
              <name>MUX23</name>
              <description>eallow, HRPWMXBAR_LOCK</description>
              <bitRange>[15:14]</bitRange>
            </field>
            <field>
              <name>MUX24</name>
              <description>eallow, HRPWMXBAR_LOCK</description>
              <bitRange>[17:16]</bitRange>
            </field>
            <field>
              <name>MUX25</name>
              <description>eallow, HRPWMXBAR_LOCK</description>
              <bitRange>[19:18]</bitRange>
            </field>
            <field>
              <name>MUX26</name>
              <description>eallow, HRPWMXBAR_LOCK</description>
              <bitRange>[21:20]</bitRange>
            </field>
            <field>
              <name>MUX27</name>
              <description>eallow, HRPWMXBAR_LOCK</description>
              <bitRange>[23:22]</bitRange>
            </field>
            <field>
              <name>MUX28</name>
              <description>eallow, HRPWMXBAR_LOCK</description>
              <bitRange>[25:24]</bitRange>
            </field>
            <field>
              <name>MUX29</name>
              <description>eallow, HRPWMXBAR_LOCK</description>
              <bitRange>[27:26]</bitRange>
            </field>
            <field>
              <name>MUX30</name>
              <description>eallow, HRPWMXBAR_LOCK</description>
              <bitRange>[29:28]</bitRange>
            </field>
            <field>
              <name>MUX31</name>
              <description>eallow, HRPWMXBAR_LOCK</description>
              <bitRange>[31:30]</bitRange>
            </field>
          </fields>
        </register>
        <register>
          <name>HXB12_0</name>
          <addressOffset>0x78</addressOffset>
          <fields>
            <field>
              <name>MUX0</name>
              <description>eallow, HRPWMXBAR_LOCK</description>
              <bitRange>[1:0]</bitRange>
            </field>
            <field>
              <name>MUX1</name>
              <description>eallow, HRPWMXBAR_LOCK</description>
              <bitRange>[3:2]</bitRange>
            </field>
            <field>
              <name>MUX2</name>
              <description>eallow, HRPWMXBAR_LOCK</description>
              <bitRange>[5:4]</bitRange>
            </field>
            <field>
              <name>MUX3</name>
              <description>eallow, HRPWMXBAR_LOCK</description>
              <bitRange>[7:6]</bitRange>
            </field>
            <field>
              <name>MUX4</name>
              <description>eallow, HRPWMXBAR_LOCK</description>
              <bitRange>[9:8]</bitRange>
            </field>
            <field>
              <name>MUX5</name>
              <description>eallow, HRPWMXBAR_LOCK</description>
              <bitRange>[11:10]</bitRange>
            </field>
            <field>
              <name>MUX6</name>
              <description>eallow, HRPWMXBAR_LOCK</description>
              <bitRange>[13:12]</bitRange>
            </field>
            <field>
              <name>MUX7</name>
              <description>eallow, HRPWMXBAR_LOCK</description>
              <bitRange>[15:14]</bitRange>
            </field>
            <field>
              <name>MUX8</name>
              <description>eallow, HRPWMXBAR_LOCK</description>
              <bitRange>[17:16]</bitRange>
            </field>
            <field>
              <name>MUX9</name>
              <description>eallow, HRPWMXBAR_LOCK</description>
              <bitRange>[19:18]</bitRange>
            </field>
            <field>
              <name>MUX10</name>
              <description>eallow, HRPWMXBAR_LOCK</description>
              <bitRange>[21:20]</bitRange>
            </field>
            <field>
              <name>MUX11</name>
              <description>eallow, HRPWMXBAR_LOCK</description>
              <bitRange>[23:22]</bitRange>
            </field>
            <field>
              <name>MUX12</name>
              <description>eallow, HRPWMXBAR_LOCK</description>
              <bitRange>[25:24]</bitRange>
            </field>
            <field>
              <name>MUX13</name>
              <description>eallow, HRPWMXBAR_LOCK</description>
              <bitRange>[27:26]</bitRange>
            </field>
            <field>
              <name>MUX14</name>
              <description>eallow, HRPWMXBAR_LOCK</description>
              <bitRange>[29:28]</bitRange>
            </field>
            <field>
              <name>MUX15</name>
              <description>eallow, HRPWMXBAR_LOCK</description>
              <bitRange>[31:30]</bitRange>
            </field>
          </fields>
        </register>
        <register>
          <name>HXB12_1</name>
          <addressOffset>0x7C</addressOffset>
          <fields>
            <field>
              <name>MUX16</name>
              <description>eallow, HRPWMXBAR_LOCK</description>
              <bitRange>[1:0]</bitRange>
            </field>
            <field>
              <name>MUX17</name>
              <description>eallow, HRPWMXBAR_LOCK</description>
              <bitRange>[3:2]</bitRange>
            </field>
            <field>
              <name>MUX18</name>
              <description>eallow, HRPWMXBAR_LOCK</description>
              <bitRange>[5:4]</bitRange>
            </field>
            <field>
              <name>MUX19</name>
              <description>eallow, HRPWMXBAR_LOCK</description>
              <bitRange>[7:6]</bitRange>
            </field>
            <field>
              <name>MUX20</name>
              <description>eallow, HRPWMXBAR_LOCK</description>
              <bitRange>[9:8]</bitRange>
            </field>
            <field>
              <name>MUX21</name>
              <description>eallow, HRPWMXBAR_LOCK</description>
              <bitRange>[11:10]</bitRange>
            </field>
            <field>
              <name>MUX22</name>
              <description>eallow, HRPWMXBAR_LOCK</description>
              <bitRange>[13:12]</bitRange>
            </field>
            <field>
              <name>MUX23</name>
              <description>eallow, HRPWMXBAR_LOCK</description>
              <bitRange>[15:14]</bitRange>
            </field>
            <field>
              <name>MUX24</name>
              <description>eallow, HRPWMXBAR_LOCK</description>
              <bitRange>[17:16]</bitRange>
            </field>
            <field>
              <name>MUX25</name>
              <description>eallow, HRPWMXBAR_LOCK</description>
              <bitRange>[19:18]</bitRange>
            </field>
            <field>
              <name>MUX26</name>
              <description>eallow, HRPWMXBAR_LOCK</description>
              <bitRange>[21:20]</bitRange>
            </field>
            <field>
              <name>MUX27</name>
              <description>eallow, HRPWMXBAR_LOCK</description>
              <bitRange>[23:22]</bitRange>
            </field>
            <field>
              <name>MUX28</name>
              <description>eallow, HRPWMXBAR_LOCK</description>
              <bitRange>[25:24]</bitRange>
            </field>
            <field>
              <name>MUX29</name>
              <description>eallow, HRPWMXBAR_LOCK</description>
              <bitRange>[27:26]</bitRange>
            </field>
            <field>
              <name>MUX30</name>
              <description>eallow, HRPWMXBAR_LOCK</description>
              <bitRange>[29:28]</bitRange>
            </field>
            <field>
              <name>MUX31</name>
              <description>eallow, HRPWMXBAR_LOCK</description>
              <bitRange>[31:30]</bitRange>
            </field>
          </fields>
        </register>
        <register>
          <name>HXB4_MUX</name>
          <addressOffset>0x80</addressOffset>
          <fields>
            <field>
              <name>MUXEN</name>
              <description>eallow, HRPWMXBAR_LOCK</description>
              <bitRange>[31:0]</bitRange>
            </field>
          </fields>
        </register>
        <register>
          <name>HXB5_MUX</name>
          <addressOffset>0x84</addressOffset>
          <fields>
            <field>
              <name>MUXEN</name>
              <description>eallow, HRPWMXBAR_LOCK</description>
              <bitRange>[31:0]</bitRange>
            </field>
          </fields>
        </register>
        <register>
          <name>HXB7_MUX</name>
          <addressOffset>0x88</addressOffset>
          <fields>
            <field>
              <name>MUXEN</name>
              <description>eallow, HRPWMXBAR_LOCK</description>
              <bitRange>[31:0]</bitRange>
            </field>
          </fields>
        </register>
        <register>
          <name>HXB8_MUX</name>
          <addressOffset>0x8C</addressOffset>
          <fields>
            <field>
              <name>MUXEN</name>
              <description>eallow, HRPWMXBAR_LOCK</description>
              <bitRange>[31:0]</bitRange>
            </field>
          </fields>
        </register>
        <register>
          <name>HXB9_MUX</name>
          <addressOffset>0x90</addressOffset>
          <fields>
            <field>
              <name>MUXEN</name>
              <description>eallow, HRPWMXBAR_LOCK</description>
              <bitRange>[31:0]</bitRange>
            </field>
          </fields>
        </register>
        <register>
          <name>HXB10_MUX</name>
          <addressOffset>0x94</addressOffset>
          <fields>
            <field>
              <name>MUXEN</name>
              <description>eallow, HRPWMXBAR_LOCK</description>
              <bitRange>[31:0]</bitRange>
            </field>
          </fields>
        </register>
        <register>
          <name>HXB11_MUX</name>
          <addressOffset>0x98</addressOffset>
          <fields>
            <field>
              <name>MUXEN</name>
              <description>eallow, HRPWMXBAR_LOCK</description>
              <bitRange>[31:0]</bitRange>
            </field>
          </fields>
        </register>
        <register>
          <name>HXB12_MUX</name>
          <addressOffset>0x9C</addressOffset>
          <fields>
            <field>
              <name>MUXEN</name>
              <description>eallow, HRPWMXBAR_LOCK</description>
              <bitRange>[31:0]</bitRange>
            </field>
          </fields>
        </register>
        <register>
          <name>HXB_POL</name>
          <addressOffset>0xA0</addressOffset>
          <fields>
            <field>
              <name>HXB4P</name>
              <description>eallow, HRPWMXBAR_LOCK</description>
              <bitRange>[0:0]</bitRange>
            </field>
            <field>
              <name>HXB5P</name>
              <description>eallow, HRPWMXBAR_LOCK</description>
              <bitRange>[1:1]</bitRange>
            </field>
            <field>
              <name>HXB7P</name>
              <description>eallow, HRPWMXBAR_LOCK</description>
              <bitRange>[2:2]</bitRange>
            </field>
            <field>
              <name>HXB8P</name>
              <description>eallow, HRPWMXBAR_LOCK</description>
              <bitRange>[3:3]</bitRange>
            </field>
            <field>
              <name>HXB9P</name>
              <description>eallow, HRPWMXBAR_LOCK</description>
              <bitRange>[4:4]</bitRange>
            </field>
            <field>
              <name>HXB10P</name>
              <description>eallow, HRPWMXBAR_LOCK</description>
              <bitRange>[5:5]</bitRange>
            </field>
            <field>
              <name>HXB11P</name>
              <description>eallow, HRPWMXBAR_LOCK</description>
              <bitRange>[6:6]</bitRange>
            </field>
            <field>
              <name>HXB12P</name>
              <description>eallow, HRPWMXBAR_LOCK</description>
              <bitRange>[7:7]</bitRange>
            </field>
          </fields>
        </register>
        <register>
          <name>HXB_LOCK</name>
          <addressOffset>0xA4</addressOffset>
          <fields>
            <field>
              <name>LOCK</name>
              <description>eallow</description>
              <bitRange>[0:0]</bitRange>
            </field>
            <field>
              <name>KEY</name>
              <description>eallow</description>
              <bitRange>[31:16]</bitRange>
              <access>write-only</access>
            </field>
          </fields>
        </register>
        <register>
          <name>SYNCI_SEL1_4</name>
          <addressOffset>0xC0</addressOffset>
          <fields>
            <field>
              <name>SEL1</name>
              <description>eallow, SYNCSELECT_LOCK</description>
              <bitRange>[4:0]</bitRange>
            </field>
            <field>
              <name>SEL2</name>
              <description>eallow, SYNCSELECT_LOCK</description>
              <bitRange>[12:8]</bitRange>
            </field>
            <field>
              <name>SEL3</name>
              <description>eallow, SYNCSELECT_LOCK</description>
              <bitRange>[20:16]</bitRange>
            </field>
            <field>
              <name>SEL4</name>
              <description>eallow, SYNCSELECT_LOCK</description>
              <bitRange>[28:24]</bitRange>
            </field>
          </fields>
        </register>
        <register>
          <name>SYNCI_SEL5_6</name>
          <addressOffset>0xC4</addressOffset>
          <fields>
            <field>
              <name>SEL5</name>
              <description>eallow, SYNCSELECT_LOCK</description>
              <bitRange>[4:0]</bitRange>
            </field>
            <field>
              <name>SEL6</name>
              <description>eallow, SYNCSELECT_LOCK</description>
              <bitRange>[12:8]</bitRange>
            </field>
          </fields>
        </register>
        <register>
          <name>SYNCO_SEL1_4</name>
          <addressOffset>0xC8</addressOffset>
          <fields>
            <field>
              <name>SEL1</name>
              <description>eallow</description>
              <bitRange>[4:0]</bitRange>
            </field>
            <field>
              <name>SEL2</name>
              <description>eallow</description>
              <bitRange>[12:8]</bitRange>
            </field>
            <field>
              <name>SEL3</name>
              <description>eallow</description>
              <bitRange>[20:16]</bitRange>
            </field>
            <field>
              <name>SEL4</name>
              <description>eallow</description>
              <bitRange>[28:24]</bitRange>
            </field>
          </fields>
        </register>
        <register>
          <name>SYNCO_SEL5_6</name>
          <addressOffset>0xCC</addressOffset>
          <fields>
            <field>
              <name>SEL5</name>
              <description>eallow</description>
              <bitRange>[4:0]</bitRange>
            </field>
            <field>
              <name>SEL6</name>
              <description>eallow</description>
              <bitRange>[12:8]</bitRange>
            </field>
          </fields>
        </register>
        <register>
          <name>ADCOUT</name>
          <addressOffset>0xD0</addressOffset>
          <fields>
            <field>
              <name>SOC1A_EN</name>
              <description>eallow , ADCSOCOUTSELECT_LOCK</description>
              <bitRange>[0:0]</bitRange>
            </field>
            <field>
              <name>SOC2A_EN</name>
              <description>eallow , ADCSOCOUTSELECT_LOCK</description>
              <bitRange>[1:1]</bitRange>
            </field>
            <field>
              <name>SOC3A_EN</name>
              <description>eallow , ADCSOCOUTSELECT_LOCK</description>
              <bitRange>[2:2]</bitRange>
            </field>
            <field>
              <name>SOC4A_EN</name>
              <description>eallow , ADCSOCOUTSELECT_LOCK</description>
              <bitRange>[3:3]</bitRange>
            </field>
            <field>
              <name>SOC5A_EN</name>
              <description>eallow , ADCSOCOUTSELECT_LOCK</description>
              <bitRange>[4:4]</bitRange>
            </field>
            <field>
              <name>SOC6A_EN</name>
              <description>eallow , ADCSOCOUTSELECT_LOCK</description>
              <bitRange>[5:5]</bitRange>
            </field>
            <field>
              <name>SOC1B_EN</name>
              <description>eallow , ADCSOCOUTSELECT_LOCK</description>
              <bitRange>[6:6]</bitRange>
            </field>
            <field>
              <name>SOC2B_EN</name>
              <description>eallow , ADCSOCOUTSELECT_LOCK</description>
              <bitRange>[7:7]</bitRange>
            </field>
            <field>
              <name>SOC3B_EN</name>
              <description>eallow , ADCSOCOUTSELECT_LOCK</description>
              <bitRange>[8:8]</bitRange>
            </field>
            <field>
              <name>SOC4B_EN</name>
              <description>eallow , ADCSOCOUTSELECT_LOCK</description>
              <bitRange>[9:9]</bitRange>
            </field>
            <field>
              <name>SOC5B_EN</name>
              <description>eallow , ADCSOCOUTSELECT_LOCK</description>
              <bitRange>[10:10]</bitRange>
            </field>
            <field>
              <name>SOC6B_EN</name>
              <description>eallow , ADCSOCOUTSELECT_LOCK</description>
              <bitRange>[11:11]</bitRange>
            </field>
            <field>
              <name>SOCA_POL</name>
              <description>eallow , ADCSOCOUTSELECT_LOCK</description>
              <bitRange>[12:12]</bitRange>
            </field>
            <field>
              <name>SOCB_POL</name>
              <description>eallow , ADCSOCOUTSELECT_LOCK</description>
              <bitRange>[13:13]</bitRange>
            </field>
          </fields>
        </register>
        <register>
          <name>SCOUT_CFG</name>
          <addressOffset>0xD4</addressOffset>
          <fields>
            <field>
              <name>SCOUT_SEL</name>
              <description>eallow</description>
              <bitRange>[2:0]</bitRange>
            </field>
            <field>
              <name>SCOUT_EXP_BYPASS</name>
              <description>eallow</description>
              <bitRange>[3:3]</bitRange>
            </field>
          </fields>
        </register>
        <register>
          <name>SYNCSOCLOCK</name>
          <addressOffset>0xD8</addressOffset>
          <fields>
            <field>
              <name>SYNC</name>
              <description>eallow</description>
              <bitRange>[0:0]</bitRange>
            </field>
            <field>
              <name>ADCSOC</name>
              <description>eallow</description>
              <bitRange>[1:1]</bitRange>
            </field>
          </fields>
        </register>
        <register>
          <name>EALLOW</name>
          <addressOffset>0xDC</addressOffset>
          <fields>
            <field>
              <name>EALLOW</name>
              <bitRange>[0:0]</bitRange>
            </field>
            <field>
              <name>EALLOW_KEY</name>
              <bitRange>[31:16]</bitRange>
              <access>write-only</access>
            </field>
          </fields>
        </register>
        <register>
          <name>CLKEN</name>
          <addressOffset>0xE0</addressOffset>
          <fields>
            <field>
              <name>HRPWM1_CLK_EN</name>
              <description>eallow</description>
              <bitRange>[0:0]</bitRange>
            </field>
            <field>
              <name>HRPWM2_CLK_EN</name>
              <description>eallow</description>
              <bitRange>[1:1]</bitRange>
            </field>
            <field>
              <name>HRPWM3_CLK_EN</name>
              <description>eallow</description>
              <bitRange>[2:2]</bitRange>
            </field>
            <field>
              <name>HRPWM4_CLK_EN</name>
              <description>eallow</description>
              <bitRange>[3:3]</bitRange>
            </field>
            <field>
              <name>HRPWM5_CLK_EN</name>
              <description>eallow</description>
              <bitRange>[4:4]</bitRange>
            </field>
            <field>
              <name>HRPWM6_CLK_EN</name>
              <description>eallow</description>
              <bitRange>[5:5]</bitRange>
            </field>
          </fields>
        </register>
        <register>
          <name>XBARFLG1</name>
          <addressOffset>0xF0</addressOffset>
          <fields>
            <field>
              <name>COMP1_OUT_FLG</name>
              <bitRange>[0:0]</bitRange>
              <access>read-only</access>
            </field>
            <field>
              <name>COMP2_OUT_FLG</name>
              <bitRange>[1:1]</bitRange>
              <access>read-only</access>
            </field>
            <field>
              <name>COMP3_OUT_FLG</name>
              <bitRange>[2:2]</bitRange>
              <access>read-only</access>
            </field>
            <field>
              <name>COMP4_OUT_FLG</name>
              <bitRange>[3:3]</bitRange>
              <access>read-only</access>
            </field>
            <field>
              <name>INPUT1_FLG</name>
              <bitRange>[4:4]</bitRange>
              <access>read-only</access>
            </field>
            <field>
              <name>INPUT2_FLG</name>
              <bitRange>[5:5]</bitRange>
              <access>read-only</access>
            </field>
            <field>
              <name>INPUT3_FLG</name>
              <bitRange>[6:6]</bitRange>
              <access>read-only</access>
            </field>
            <field>
              <name>INPUT4_FLG</name>
              <bitRange>[7:7]</bitRange>
              <access>read-only</access>
            </field>
            <field>
              <name>INPUT5_FLG</name>
              <bitRange>[8:8]</bitRange>
              <access>read-only</access>
            </field>
            <field>
              <name>INPUT6_FLG</name>
              <bitRange>[9:9]</bitRange>
              <access>read-only</access>
            </field>
            <field>
              <name>ADCSOCA_FLG</name>
              <bitRange>[10:10]</bitRange>
              <access>read-only</access>
            </field>
            <field>
              <name>ADCSOCB_FLG</name>
              <bitRange>[11:11]</bitRange>
              <access>read-only</access>
            </field>
            <field>
              <name>INPUT7_FLG</name>
              <bitRange>[12:12]</bitRange>
              <access>read-only</access>
            </field>
            <field>
              <name>INPUT8_FLG</name>
              <bitRange>[13:13]</bitRange>
              <access>read-only</access>
            </field>
            <field>
              <name>INPUT9_FLG</name>
              <bitRange>[14:14]</bitRange>
              <access>read-only</access>
            </field>
            <field>
              <name>INPUT10_FLG</name>
              <bitRange>[15:15]</bitRange>
              <access>read-only</access>
            </field>
            <field>
              <name>INPUT11_FLG</name>
              <bitRange>[16:16]</bitRange>
              <access>read-only</access>
            </field>
            <field>
              <name>INPUT12_FLG</name>
              <bitRange>[17:17]</bitRange>
              <access>read-only</access>
            </field>
            <field>
              <name>INPUT13_FLG</name>
              <bitRange>[18:18]</bitRange>
              <access>read-only</access>
            </field>
            <field>
              <name>INPUT14_FLG</name>
              <bitRange>[19:19]</bitRange>
              <access>read-only</access>
            </field>
            <field>
              <name>ADC1_AWD1_FLG</name>
              <bitRange>[20:20]</bitRange>
              <access>read-only</access>
            </field>
            <field>
              <name>ADC1_AWD2_FLG</name>
              <bitRange>[21:21]</bitRange>
              <access>read-only</access>
            </field>
            <field>
              <name>ADC1_AWD3_FLG</name>
              <bitRange>[22:22]</bitRange>
              <access>read-only</access>
            </field>
            <field>
              <name>ADC2_AWD1_FLG</name>
              <bitRange>[23:23]</bitRange>
              <access>read-only</access>
            </field>
            <field>
              <name>ADC2_AWD2_FLG</name>
              <bitRange>[24:24]</bitRange>
              <access>read-only</access>
            </field>
            <field>
              <name>ADC2_AWD3_FLG</name>
              <bitRange>[25:25]</bitRange>
              <access>read-only</access>
            </field>
            <field>
              <name>TIM1_OC1_FLG</name>
              <bitRange>[26:26]</bitRange>
              <access>read-only</access>
            </field>
            <field>
              <name>TIM1_OC2_FLG</name>
              <bitRange>[27:27]</bitRange>
              <access>read-only</access>
            </field>
            <field>
              <name>TIM1_OC3_FLG</name>
              <bitRange>[28:28]</bitRange>
              <access>read-only</access>
            </field>
            <field>
              <name>TIM1_OC4_FLG</name>
              <bitRange>[29:29]</bitRange>
              <access>read-only</access>
            </field>
            <field>
              <name>TIM1_OC5_FLG</name>
              <bitRange>[30:30]</bitRange>
              <access>read-only</access>
            </field>
            <field>
              <name>TIM1_OC6_FLG</name>
              <bitRange>[31:31]</bitRange>
              <access>read-only</access>
            </field>
          </fields>
        </register>
        <register>
          <name>XBARFLG2</name>
          <addressOffset>0xF4</addressOffset>
          <fields>
            <field>
              <name>TIM2_OC1_FLG</name>
              <bitRange>[0:0]</bitRange>
              <access>read-only</access>
            </field>
            <field>
              <name>TIM2_OC2_FLG</name>
              <bitRange>[1:1]</bitRange>
              <access>read-only</access>
            </field>
            <field>
              <name>TIM2_OC3_FLG</name>
              <bitRange>[2:2]</bitRange>
              <access>read-only</access>
            </field>
            <field>
              <name>TIM2_OC4_FLG</name>
              <bitRange>[3:3]</bitRange>
              <access>read-only</access>
            </field>
            <field>
              <name>TIM3_OC1_FLG</name>
              <bitRange>[4:4]</bitRange>
              <access>read-only</access>
            </field>
            <field>
              <name>TIM3_OC2_FLG</name>
              <bitRange>[5:5]</bitRange>
              <access>read-only</access>
            </field>
            <field>
              <name>TIM3_OC3_FLG</name>
              <bitRange>[6:6]</bitRange>
              <access>read-only</access>
            </field>
            <field>
              <name>TIM3_OC4_FLG</name>
              <bitRange>[7:7]</bitRange>
              <access>read-only</access>
            </field>
            <field>
              <name>TIM8_OC1_FLG</name>
              <bitRange>[8:8]</bitRange>
              <access>read-only</access>
            </field>
            <field>
              <name>TIM8_OC2_FLG</name>
              <bitRange>[9:9]</bitRange>
              <access>read-only</access>
            </field>
            <field>
              <name>TIM8_OC3_FLG</name>
              <bitRange>[10:10]</bitRange>
              <access>read-only</access>
            </field>
            <field>
              <name>TIM8_OC4_FLG</name>
              <bitRange>[11:11]</bitRange>
              <access>read-only</access>
            </field>
            <field>
              <name>TIM8_OC5_FLG</name>
              <bitRange>[12:12]</bitRange>
              <access>read-only</access>
            </field>
            <field>
              <name>TIM8_OC6_FLG</name>
              <bitRange>[13:13]</bitRange>
              <access>read-only</access>
            </field>
            <field>
              <name>HRPWM_SCOUT_FLG</name>
              <bitRange>[14:14]</bitRange>
              <access>read-only</access>
            </field>
            <field>
              <name>CPUHALT_FLG</name>
              <bitRange>[15:15]</bitRange>
              <access>read-only</access>
            </field>
          </fields>
        </register>
        <register>
          <name>XBARCLR1</name>
          <addressOffset>0xF8</addressOffset>
          <fields>
            <field>
              <name>COMP1_OUT_CLR</name>
              <bitRange>[0:0]</bitRange>
              <access>write-only</access>
            </field>
            <field>
              <name>COMP2_OUT_CLR</name>
              <bitRange>[1:1]</bitRange>
              <access>write-only</access>
            </field>
            <field>
              <name>COMP3_OUT_CLR</name>
              <bitRange>[2:2]</bitRange>
              <access>write-only</access>
            </field>
            <field>
              <name>COMP4_OUT_CLR</name>
              <bitRange>[3:3]</bitRange>
              <access>write-only</access>
            </field>
            <field>
              <name>INPUT1_CLR</name>
              <bitRange>[4:4]</bitRange>
              <access>write-only</access>
            </field>
            <field>
              <name>INPUT2_CLR</name>
              <bitRange>[5:5]</bitRange>
              <access>write-only</access>
            </field>
            <field>
              <name>INPUT3_CLR</name>
              <bitRange>[6:6]</bitRange>
              <access>write-only</access>
            </field>
            <field>
              <name>INPUT4_CLR</name>
              <bitRange>[7:7]</bitRange>
              <access>write-only</access>
            </field>
            <field>
              <name>INPUT5_CLR</name>
              <bitRange>[8:8]</bitRange>
              <access>write-only</access>
            </field>
            <field>
              <name>INPUT6_CLR</name>
              <bitRange>[9:9]</bitRange>
              <access>write-only</access>
            </field>
            <field>
              <name>ADCSOCA_CLR</name>
              <bitRange>[10:10]</bitRange>
              <access>write-only</access>
            </field>
            <field>
              <name>ADCSOCB_CLR</name>
              <bitRange>[11:11]</bitRange>
              <access>write-only</access>
            </field>
            <field>
              <name>INPUT7_CLR</name>
              <bitRange>[12:12]</bitRange>
              <access>write-only</access>
            </field>
            <field>
              <name>INPUT8_CLR</name>
              <bitRange>[13:13]</bitRange>
              <access>write-only</access>
            </field>
            <field>
              <name>INPUT9_CLR</name>
              <bitRange>[14:14]</bitRange>
              <access>write-only</access>
            </field>
            <field>
              <name>INPUT10_CLR</name>
              <bitRange>[15:15]</bitRange>
              <access>write-only</access>
            </field>
            <field>
              <name>INPUT11_CLR</name>
              <bitRange>[16:16]</bitRange>
              <access>write-only</access>
            </field>
            <field>
              <name>INPUT12_CLR</name>
              <bitRange>[17:17]</bitRange>
              <access>write-only</access>
            </field>
            <field>
              <name>INPUT13_CLR</name>
              <bitRange>[18:18]</bitRange>
              <access>write-only</access>
            </field>
            <field>
              <name>INPUT14_CLR</name>
              <bitRange>[19:19]</bitRange>
              <access>write-only</access>
            </field>
            <field>
              <name>ADC1_AWD1_CLR</name>
              <bitRange>[20:20]</bitRange>
              <access>write-only</access>
            </field>
            <field>
              <name>ADC1_AWD2_CLR</name>
              <bitRange>[21:21]</bitRange>
              <access>write-only</access>
            </field>
            <field>
              <name>ADC1_AWD3_CLR</name>
              <bitRange>[22:22]</bitRange>
              <access>write-only</access>
            </field>
            <field>
              <name>ADC2_AWD1_CLR</name>
              <bitRange>[23:23]</bitRange>
              <access>write-only</access>
            </field>
            <field>
              <name>ADC2_AWD2_CLR</name>
              <bitRange>[24:24]</bitRange>
              <access>write-only</access>
            </field>
            <field>
              <name>ADC2_AWD3_CLR</name>
              <bitRange>[25:25]</bitRange>
              <access>write-only</access>
            </field>
            <field>
              <name>TIM1_OC1_CLR</name>
              <bitRange>[26:26]</bitRange>
              <access>write-only</access>
            </field>
            <field>
              <name>TIM1_OC2_CLR</name>
              <bitRange>[27:27]</bitRange>
              <access>write-only</access>
            </field>
            <field>
              <name>TIM1_OC3_CLR</name>
              <bitRange>[28:28]</bitRange>
              <access>write-only</access>
            </field>
            <field>
              <name>TIM1_OC4_CLR</name>
              <bitRange>[29:29]</bitRange>
              <access>write-only</access>
            </field>
            <field>
              <name>TIM1_OC5_CLR</name>
              <bitRange>[30:30]</bitRange>
              <access>write-only</access>
            </field>
            <field>
              <name>TIM1_OC6_CLR</name>
              <bitRange>[31:31]</bitRange>
              <access>write-only</access>
            </field>
          </fields>
        </register>
        <register>
          <name>XBARCLR2</name>
          <addressOffset>0xFC</addressOffset>
          <fields>
            <field>
              <name>TIM2_OC1_CLR</name>
              <bitRange>[0:0]</bitRange>
              <access>write-only</access>
            </field>
            <field>
              <name>TIM2_OC2_CLR</name>
              <bitRange>[1:1]</bitRange>
              <access>write-only</access>
            </field>
            <field>
              <name>TIM2_OC3_CLR</name>
              <bitRange>[2:2]</bitRange>
              <access>write-only</access>
            </field>
            <field>
              <name>TIM2_OC4_CLR</name>
              <bitRange>[3:3]</bitRange>
              <access>write-only</access>
            </field>
            <field>
              <name>TIM3_OC1_CLR</name>
              <bitRange>[4:4]</bitRange>
              <access>write-only</access>
            </field>
            <field>
              <name>TIM3_OC2_CLR</name>
              <bitRange>[5:5]</bitRange>
              <access>write-only</access>
            </field>
            <field>
              <name>TIM3_OC3_CLR</name>
              <bitRange>[6:6]</bitRange>
              <access>write-only</access>
            </field>
            <field>
              <name>TIM3_OC4_CLR</name>
              <bitRange>[7:7]</bitRange>
              <access>write-only</access>
            </field>
            <field>
              <name>TIM8_OC1_CLR</name>
              <bitRange>[8:8]</bitRange>
              <access>write-only</access>
            </field>
            <field>
              <name>TIM8_OC2_CLR</name>
              <bitRange>[9:9]</bitRange>
              <access>write-only</access>
            </field>
            <field>
              <name>TIM8_OC3_CLR</name>
              <bitRange>[10:10]</bitRange>
              <access>write-only</access>
            </field>
            <field>
              <name>TIM8_OC4_CLR</name>
              <bitRange>[11:11]</bitRange>
              <access>write-only</access>
            </field>
            <field>
              <name>TIM8_OC5_CLR</name>
              <bitRange>[12:12]</bitRange>
              <access>write-only</access>
            </field>
            <field>
              <name>TIM8_OC6_CLR</name>
              <bitRange>[13:13]</bitRange>
              <access>write-only</access>
            </field>
            <field>
              <name>HRPWM_SCOUT_CLR</name>
              <bitRange>[14:14]</bitRange>
              <access>write-only</access>
            </field>
            <field>
              <name>CPUHALT_CLR</name>
              <bitRange>[15:15]</bitRange>
              <access>write-only</access>
            </field>
          </fields>
        </register>
        <register>
          <name>FPGA_SFO_DBG</name>
          <addressOffset>0x3F0</addressOffset>
          <fields>
            <field>
              <name>SFO_DEBUG</name>
              <bitRange>[2:0]</bitRange>
            </field>
          </fields>
        </register>
      </registers>
    </peripheral>
    <peripheral>
      <name>I2C1</name>
      <groupName>I2C</groupName>
      <baseAddress>0x40005400</baseAddress>
      <addressBlock>
        <offset>0x0</offset>
        <size>0x30</size>
        <usage>registers</usage>
      </addressBlock>
      <interrupt>
        <name>I2C1_EV</name>
        <description>I2C1 Event interrupt</description>
        <value>41</value>
      </interrupt>
      <interrupt>
        <name>I2C1_ER</name>
        <description>I2C1 Error interrupt</description>
        <value>42</value>
      </interrupt>
      <registers>
        <register>
          <name>CR1</name>
          <addressOffset>0x0</addressOffset>
          <fields>
            <field>
              <name>PE</name>
              <description>Peripheral enable</description>
              <bitRange>[0:0]</bitRange>
            </field>
            <field>
              <name>SMBUS</name>
              <description>SMBus mode</description>
              <bitRange>[1:1]</bitRange>
            </field>
            <field>
              <name>WUPEN</name>
              <description>Wakeup from Stop mode enable</description>
              <bitRange>[2:2]</bitRange>
            </field>
            <field>
              <name>SMBTYPE</name>
              <description>SMBus type</description>
              <bitRange>[3:3]</bitRange>
            </field>
            <field>
              <name>ENARP</name>
              <description>ARP enable</description>
              <bitRange>[4:4]</bitRange>
            </field>
            <field>
              <name>ENPEC</name>
              <description>PEC enable</description>
              <bitRange>[5:5]</bitRange>
            </field>
            <field>
              <name>ENGC</name>
              <description>General call enable</description>
              <bitRange>[6:6]</bitRange>
            </field>
            <field>
              <name>NOSTRETCH</name>
              <description>Clock stretching disable (Slave mode)</description>
              <bitRange>[7:7]</bitRange>
            </field>
            <field>
              <name>START</name>
              <description>Start generation</description>
              <bitRange>[8:8]</bitRange>
            </field>
            <field>
              <name>STOP</name>
              <description>Stop generation</description>
              <bitRange>[9:9]</bitRange>
            </field>
            <field>
              <name>ACK</name>
              <description>Acknowledge enable</description>
              <bitRange>[10:10]</bitRange>
            </field>
            <field>
              <name>POS</name>
              <description>Acknowledge(for data reception)</description>
              <bitRange>[11:11]</bitRange>
            </field>
            <field>
              <name>PEC</name>
              <description>Packet error checking</description>
              <bitRange>[12:12]</bitRange>
            </field>
            <field>
              <name>ALERT</name>
              <description>SMBus alert</description>
              <bitRange>[13:13]</bitRange>
            </field>
            <field>
              <name>SWRST</name>
              <description>Software reset</description>
              <bitRange>[15:15]</bitRange>
            </field>
            <field>
              <name>WKUP_DIV</name>
              <description>PCLK division</description>
              <bitRange>[17:16]</bitRange>
            </field>
            <field>
              <name>WKUP_CNT</name>
              <description>Timeout count number</description>
              <bitRange>[19:18]</bitRange>
            </field>
          </fields>
        </register>
        <register>
          <name>CR2</name>
          <addressOffset>0x4</addressOffset>
          <fields>
            <field>
              <name>FREQ</name>
              <description>Peripheral clock frequency</description>
              <bitRange>[7:0]</bitRange>
            </field>
            <field>
              <name>ITERREN</name>
              <description>Error interrupt enable</description>
              <bitRange>[8:8]</bitRange>
            </field>
            <field>
              <name>DMAEN</name>
              <description>DMA requests enable</description>
              <bitRange>[11:11]</bitRange>
            </field>
            <field>
              <name>LAST</name>
              <description>DMA last transfer</description>
              <bitRange>[12:12]</bitRange>
            </field>
            <field>
              <name>SBIE</name>
              <description>Start bit (Master mode) interrupt enable</description>
              <bitRange>[16:16]</bitRange>
            </field>
            <field>
              <name>ADDRIE</name>
              <description>Address sent (master mode)/matched (slave mode) interrupt enable</description>
              <bitRange>[17:17]</bitRange>
            </field>
            <field>
              <name>BTFIE</name>
              <description>Byte transfer finished interrupt enable</description>
              <bitRange>[18:18]</bitRange>
            </field>
            <field>
              <name>ADD10IE</name>
              <description>10-bit header sent (Master mode) interrupt enable</description>
              <bitRange>[19:19]</bitRange>
            </field>
            <field>
              <name>STOPIE</name>
              <description>Stop detection (slave mode) interrupt enable</description>
              <bitRange>[20:20]</bitRange>
            </field>
            <field>
              <name>RXIE</name>
              <description>Data register not empty (receivers) interrupt enable</description>
              <bitRange>[22:22]</bitRange>
            </field>
            <field>
              <name>TXIE</name>
              <description>Data register empty (transmitters) interrupt enable</description>
              <bitRange>[23:23]</bitRange>
            </field>
          </fields>
        </register>
        <register>
          <name>OAR1</name>
          <addressOffset>0x8</addressOffset>
          <fields>
            <field>
              <name>ADD</name>
              <description>Interface address</description>
              <bitRange>[9:0]</bitRange>
            </field>
            <field>
              <name>ADDMODE</name>
              <description>Addressing mode (slave mode)</description>
              <bitRange>[15:15]</bitRange>
            </field>
          </fields>
        </register>
        <register>
          <name>OAR2</name>
          <addressOffset>0xC</addressOffset>
          <fields>
            <field>
              <name>ENDUAL</name>
              <description>Dual addressing mode enable</description>
              <bitRange>[0:0]</bitRange>
            </field>
            <field>
              <name>ADD2</name>
              <description>Interface address</description>
              <bitRange>[7:1]</bitRange>
            </field>
            <field>
              <name>OA2MSK</name>
              <description>Own Address 2 masks</description>
              <bitRange>[10:8]</bitRange>
            </field>
          </fields>
        </register>
        <register>
          <name>DR</name>
          <addressOffset>0x10</addressOffset>
          <fields>
            <field>
              <name>DR</name>
              <description>8-bit data register</description>
              <bitRange>[7:0]</bitRange>
            </field>
          </fields>
        </register>
        <register>
          <name>SR1</name>
          <addressOffset>0x14</addressOffset>
          <fields>
            <field>
              <name>SB</name>
              <description>Start bit (Master mode)</description>
              <bitRange>[0:0]</bitRange>
              <access>read-only</access>
            </field>
            <field>
              <name>ADDR</name>
              <description>Address sent (master mode)/matched (slave mode)</description>
              <bitRange>[1:1]</bitRange>
              <access>read-only</access>
            </field>
            <field>
              <name>BTF</name>
              <description>Byte transfer finished</description>
              <bitRange>[2:2]</bitRange>
              <access>read-only</access>
            </field>
            <field>
              <name>ADD10</name>
              <description>10-bit header sent (Master mode)</description>
              <bitRange>[3:3]</bitRange>
              <access>read-only</access>
            </field>
            <field>
              <name>STOPF</name>
              <description>Stop detection (slave mode)</description>
              <bitRange>[4:4]</bitRange>
              <access>read-only</access>
            </field>
            <field>
              <name>RXNE</name>
              <description>Data register not empty (receivers)</description>
              <bitRange>[6:6]</bitRange>
              <access>read-only</access>
            </field>
            <field>
              <name>TXE</name>
              <description>Data register empty (transmitters)</description>
              <bitRange>[7:7]</bitRange>
              <access>read-only</access>
            </field>
            <field>
              <name>BERR</name>
              <description>Bus error</description>
              <bitRange>[8:8]</bitRange>
            </field>
            <field>
              <name>ARLO</name>
              <description>Arbitration lost (master mode)</description>
              <bitRange>[9:9]</bitRange>
            </field>
            <field>
              <name>AF</name>
              <description>Acknowledge failure</description>
              <bitRange>[10:10]</bitRange>
            </field>
            <field>
              <name>OVR</name>
              <description>Overrun/Underrun</description>
              <bitRange>[11:11]</bitRange>
            </field>
            <field>
              <name>PECERR</name>
              <description>PEC Error in reception</description>
              <bitRange>[12:12]</bitRange>
            </field>
            <field>
              <name>TIMEOUT</name>
              <description>Timeout or Tlow error</description>
              <bitRange>[14:14]</bitRange>
            </field>
            <field>
              <name>SMBALERT</name>
              <description>SMBus alert</description>
              <bitRange>[15:15]</bitRange>
            </field>
          </fields>
        </register>
        <register>
          <name>SR2</name>
          <addressOffset>0x18</addressOffset>
          <fields>
            <field>
              <name>MSL</name>
              <description>Master/slave</description>
              <bitRange>[0:0]</bitRange>
              <access>read-only</access>
            </field>
            <field>
              <name>BUSY</name>
              <description>Bus busy</description>
              <bitRange>[1:1]</bitRange>
              <access>read-only</access>
            </field>
            <field>
              <name>TRA</name>
              <description>Transmitter/receiver</description>
              <bitRange>[2:2]</bitRange>
              <access>read-only</access>
            </field>
            <field>
              <name>GENCALL</name>
              <description>General call address (Slave mode)</description>
              <bitRange>[4:4]</bitRange>
              <access>read-only</access>
            </field>
            <field>
              <name>SMBDEFAULT</name>
              <description>SMBus device default address (Slave mode)</description>
              <bitRange>[5:5]</bitRange>
              <access>read-only</access>
            </field>
            <field>
              <name>SMBHOST</name>
              <description>SMBus host header (Slave mode)</description>
              <bitRange>[6:6]</bitRange>
              <access>read-only</access>
            </field>
            <field>
              <name>DUALF</name>
              <description>Dual flag (Slave mode)</description>
              <bitRange>[7:7]</bitRange>
              <access>read-only</access>
            </field>
            <field>
              <name>PEC</name>
              <description>Packet error checking register</description>
              <bitRange>[15:8]</bitRange>
              <access>read-only</access>
            </field>
            <field>
              <name>SBUSY</name>
              <description>Slave busy</description>
              <bitRange>[16:16]</bitRange>
              <access>read-only</access>
            </field>
          </fields>
        </register>
        <register>
          <name>CCR</name>
          <addressOffset>0x1C</addressOffset>
          <fields>
            <field>
              <name>CCR</name>
              <description>Clock control register in Fm/Sm mode (Master mode)</description>
              <bitRange>[11:0]</bitRange>
            </field>
            <field>
              <name>FP</name>
              <description>I2C master mode selection</description>
              <bitRange>[13:13]</bitRange>
            </field>
            <field>
              <name>DUTY</name>
              <description>Fm mode duty cycle</description>
              <bitRange>[14:14]</bitRange>
            </field>
            <field>
              <name>FS</name>
              <description>I2C master mode selection</description>
              <bitRange>[15:15]</bitRange>
            </field>
          </fields>
        </register>
        <register>
          <name>TRISE</name>
          <addressOffset>0x20</addressOffset>
          <fields>
            <field>
              <name>TRISE</name>
              <description>Maximum rise time in Fm+/Fm/Sm mode (Master mode)</description>
              <bitRange>[6:0]</bitRange>
            </field>
            <field>
              <name>THOLDDATA</name>
              <description>Data hold time</description>
              <bitRange>[12:7]</bitRange>
            </field>
            <field>
              <name>THOLDDATA_SEL</name>
              <description>Data hold time select</description>
              <bitRange>[13:13]</bitRange>
            </field>
          </fields>
        </register>
        <register>
          <name>TIMEOUTR</name>
          <addressOffset>0x24</addressOffset>
          <fields>
            <field>
              <name>TIMEOUTA</name>
              <description>Bus Timeout A</description>
              <bitRange>[11:0]</bitRange>
            </field>
            <field>
              <name>TIDLE</name>
              <description>Idle clock timeout detection</description>
              <bitRange>[12:12]</bitRange>
            </field>
            <field>
              <name>TIMEOUTEN</name>
              <description>Clock timeout enable</description>
              <bitRange>[15:15]</bitRange>
            </field>
            <field>
              <name>TIMEOUTB</name>
              <description>Bus timeout B</description>
              <bitRange>[27:16]</bitRange>
            </field>
            <field>
              <name>TEXTEN</name>
              <description>Extended clock timeout enable</description>
              <bitRange>[31:31]</bitRange>
            </field>
          </fields>
        </register>
        <register>
          <name>OAR3</name>
          <addressOffset>0x28</addressOffset>
          <fields>
            <field>
              <name>ENTRIPLE</name>
              <description>Triple addressing mode enable</description>
              <bitRange>[0:0]</bitRange>
            </field>
            <field>
              <name>ADD3</name>
              <description>Interface address</description>
              <bitRange>[7:1]</bitRange>
            </field>
          </fields>
        </register>
      </registers>
    </peripheral>
    <peripheral derivedFrom="I2C1">
      <name>I2C2</name>
      <baseAddress>0x40005800</baseAddress>
      <interrupt>
        <name>I2C2_EV</name>
        <description>I2C2 Event interrupt</description>
        <value>43</value>
      </interrupt>
      <interrupt>
        <name>I2C2_ER</name>
        <description>I2C2 Error interrupt</description>
        <value>44</value>
      </interrupt>
    </peripheral>
    <peripheral>
      <name>IWDG</name>
      <baseAddress>0x40003000</baseAddress>
      <addressBlock>
        <offset>0x0</offset>
        <size>0x10</size>
        <usage>registers</usage>
      </addressBlock>
      <registers>
        <register>
          <name>KR</name>
          <addressOffset>0x0</addressOffset>
          <fields>
            <field>
              <name>KEY</name>
              <description>IWDG KEY</description>
              <bitRange>[15:0]</bitRange>
            </field>
          </fields>
        </register>
        <register>
          <name>PR</name>
          <addressOffset>0x4</addressOffset>
          <fields>
            <field>
              <name>PR</name>
              <description>IWDG preload</description>
              <bitRange>[2:0]</bitRange>
            </field>
          </fields>
        </register>
        <register>
          <name>RLR</name>
          <addressOffset>0x8</addressOffset>
          <fields>
            <field>
              <name>RL</name>
              <description>IWDG reload</description>
              <bitRange>[11:0]</bitRange>
            </field>
          </fields>
        </register>
        <register>
          <name>SR</name>
          <addressOffset>0xC</addressOffset>
          <fields>
            <field>
              <name>PVU</name>
              <description>Watchdog prescaler value update</description>
              <bitRange>[0:0]</bitRange>
              <access>read-only</access>
            </field>
            <field>
              <name>RVU</name>
              <description>Watchdog counter reload value update</description>
              <bitRange>[1:1]</bitRange>
              <access>read-only</access>
            </field>
          </fields>
        </register>
      </registers>
    </peripheral>
    <peripheral>
      <name>LPTIM</name>
      <baseAddress>0x40007C00</baseAddress>
      <addressBlock>
        <offset>0x0</offset>
        <size>0x30</size>
        <usage>registers</usage>
      </addressBlock>
      <interrupt>
        <name>LPTIM</name>
        <description>LPTIM global Interrupt</description>
        <value>33</value>
      </interrupt>
      <registers>
        <register>
          <name>ISR</name>
          <addressOffset>0x0</addressOffset>
          <fields>
            <field>
              <name>CMPM</name>
              <description>Compare match</description>
              <bitRange>[0:0]</bitRange>
              <access>read-only</access>
            </field>
            <field>
              <name>ARRM</name>
              <description>Autoreload match</description>
              <bitRange>[1:1]</bitRange>
              <access>read-only</access>
            </field>
            <field>
              <name>EXTTRIG</name>
              <description>External trigger edge event</description>
              <bitRange>[2:2]</bitRange>
              <access>read-only</access>
            </field>
            <field>
              <name>CMPOK</name>
              <description>Compare register update OK</description>
              <bitRange>[3:3]</bitRange>
              <access>read-only</access>
            </field>
            <field>
              <name>ARROK</name>
              <description>Autoreload register update OK</description>
              <bitRange>[4:4]</bitRange>
              <access>read-only</access>
            </field>
            <field>
              <name>UP</name>
              <description>Counter direction change down to up</description>
              <bitRange>[5:5]</bitRange>
              <access>read-only</access>
            </field>
            <field>
              <name>DOWN</name>
              <description>Counter direction change up to down</description>
              <bitRange>[6:6]</bitRange>
              <access>read-only</access>
            </field>
          </fields>
        </register>
        <register>
          <name>ICR</name>
          <addressOffset>0x4</addressOffset>
          <fields>
            <field>
              <name>CMPMCF</name>
              <description>Compare match clear flag</description>
              <bitRange>[0:0]</bitRange>
            </field>
            <field>
              <name>ARRMCF</name>
              <description>Autoreload match clear flag</description>
              <bitRange>[1:1]</bitRange>
            </field>
            <field>
              <name>EXTTRIGCF</name>
              <description>External trigger valid edge clear flag</description>
              <bitRange>[2:2]</bitRange>
            </field>
            <field>
              <name>CMPOKCF</name>
              <description>Compare register update OK clear flag</description>
              <bitRange>[3:3]</bitRange>
            </field>
            <field>
              <name>ARROKCF</name>
              <description>Autoreload register update OK clear flag</description>
              <bitRange>[4:4]</bitRange>
            </field>
            <field>
              <name>UPCF</name>
              <description>Direction change to UP clear flag</description>
              <bitRange>[5:5]</bitRange>
            </field>
            <field>
              <name>DOWNCF</name>
              <description>Direction change to down clear flag</description>
              <bitRange>[6:6]</bitRange>
            </field>
          </fields>
        </register>
        <register>
          <name>IER</name>
          <addressOffset>0x8</addressOffset>
          <fields>
            <field>
              <name>CMPMIE</name>
              <description>Compare match Interrupt Enable</description>
              <bitRange>[0:0]</bitRange>
            </field>
            <field>
              <name>ARRMIE</name>
              <description>Autoreload match Interrupt Enable</description>
              <bitRange>[1:1]</bitRange>
            </field>
            <field>
              <name>EXTTRIGIE</name>
              <description>External trigger valid edge Interrupt Enable</description>
              <bitRange>[2:2]</bitRange>
            </field>
            <field>
              <name>CMPOKIE</name>
              <description>Compare register update OK Interrupt Enable</description>
              <bitRange>[3:3]</bitRange>
            </field>
            <field>
              <name>ARROKIE</name>
              <description>Autoreload register update OK Interrupt Enable</description>
              <bitRange>[4:4]</bitRange>
            </field>
            <field>
              <name>UPIE</name>
              <description>Direction change to UP Interrupt Enable</description>
              <bitRange>[5:5]</bitRange>
            </field>
            <field>
              <name>DOWNIE</name>
              <description>Direction change to down Interrupt Enable</description>
              <bitRange>[6:6]</bitRange>
            </field>
          </fields>
        </register>
        <register>
          <name>CFGR</name>
          <addressOffset>0xC</addressOffset>
          <fields>
            <field>
              <name>CKSEL</name>
              <description>Clock selector</description>
              <bitRange>[0:0]</bitRange>
            </field>
            <field>
              <name>CKPOL</name>
              <description>Clock Polarity</description>
              <bitRange>[2:1]</bitRange>
            </field>
            <field>
              <name>CKFLT</name>
              <description>Configurable digital filter for external clock</description>
              <bitRange>[4:3]</bitRange>
            </field>
            <field>
              <name>TRGFLT</name>
              <description>Configurable digital filter for trigger</description>
              <bitRange>[7:6]</bitRange>
            </field>
            <field>
              <name>PRESC</name>
              <description>Clock prescaler</description>
              <bitRange>[11:9]</bitRange>
            </field>
            <field>
              <name>TRIGSEL</name>
              <description>Trigger selector</description>
              <bitRange>[15:13]</bitRange>
            </field>
            <field>
              <name>TRIGEN</name>
              <description>Trigger enable and polarity</description>
              <bitRange>[18:17]</bitRange>
            </field>
            <field>
              <name>TIMOUT</name>
              <description>Timeout enable</description>
              <bitRange>[19:19]</bitRange>
            </field>
            <field>
              <name>WAVE</name>
              <description>Waveform shape</description>
              <bitRange>[20:20]</bitRange>
            </field>
            <field>
              <name>WAVPOL</name>
              <description>Waveform shape polarity</description>
              <bitRange>[21:21]</bitRange>
            </field>
            <field>
              <name>PRELOAD</name>
              <description>Registers update mode</description>
              <bitRange>[22:22]</bitRange>
            </field>
            <field>
              <name>ENC</name>
              <description>Encoder mode enable</description>
              <bitRange>[24:24]</bitRange>
            </field>
          </fields>
        </register>
        <register>
          <name>CR</name>
          <addressOffset>0x10</addressOffset>
          <fields>
            <field>
              <name>ENABLE</name>
              <description>LPTIM enable</description>
              <bitRange>[0:0]</bitRange>
            </field>
            <field>
              <name>SNGSTRT</name>
              <description>LPTIM start in Single mode</description>
              <bitRange>[1:1]</bitRange>
            </field>
            <field>
              <name>CNTSTRT</name>
              <description>Timer start in Continuous mode</description>
              <bitRange>[2:2]</bitRange>
            </field>
          </fields>
        </register>
        <register>
          <name>CMP</name>
          <addressOffset>0x14</addressOffset>
          <fields>
            <field>
              <name>CMP</name>
              <description>Compare value</description>
              <bitRange>[15:0]</bitRange>
            </field>
          </fields>
        </register>
        <register>
          <name>ARR</name>
          <addressOffset>0x18</addressOffset>
          <fields>
            <field>
              <name>ARR</name>
              <description>Auto reload value</description>
              <bitRange>[15:0]</bitRange>
            </field>
          </fields>
        </register>
        <register>
          <name>CNT</name>
          <addressOffset>0x1C</addressOffset>
          <fields>
            <field>
              <name>CNT</name>
              <description>Counter value</description>
              <bitRange>[15:0]</bitRange>
              <access>read-only</access>
            </field>
          </fields>
        </register>
        <register>
          <name>OR</name>
          <addressOffset>0x20</addressOffset>
          <fields>
            <field>
              <name>IN1_L</name>
              <description>LPTimer input 1 remap extension</description>
              <bitRange>[0:0]</bitRange>
            </field>
            <field>
              <name>IN2_L</name>
              <description>LPTimer input 1 remap extension</description>
              <bitRange>[1:1]</bitRange>
            </field>
            <field>
              <name>IN1_H</name>
              <description>LPTimer input 3 remap extension</description>
              <bitRange>[3:2]</bitRange>
            </field>
            <field>
              <name>IN2_H</name>
              <description>LPTimer input 2 remap extension</description>
              <bitRange>[5:4]</bitRange>
            </field>
          </fields>
        </register>
      </registers>
    </peripheral>
    <peripheral>
      <name>LPUART</name>
      <baseAddress>0x40008000</baseAddress>
      <addressBlock>
        <offset>0x0</offset>
        <size>0x30</size>
        <usage>registers</usage>
      </addressBlock>
      <interrupt>
        <name>LPUART</name>
        <description>LPUART global Interrupt</description>
        <value>39</value>
      </interrupt>
      <registers>
        <register>
          <name>CR1</name>
          <addressOffset>0x0</addressOffset>
          <fields>
            <field>
              <name>UE</name>
              <description>LPUART enabled</description>
              <bitRange>[0:0]</bitRange>
            </field>
            <field>
              <name>UESM</name>
              <description>LPUART enabled in Stop mode</description>
              <bitRange>[1:1]</bitRange>
            </field>
            <field>
              <name>RE</name>
              <description>Receive enable</description>
              <bitRange>[2:2]</bitRange>
            </field>
            <field>
              <name>TE</name>
              <description>Transfer enable</description>
              <bitRange>[3:3]</bitRange>
            </field>
            <field>
              <name>IDLEIE</name>
              <description>IDLE interrupt enable</description>
              <bitRange>[4:4]</bitRange>
            </field>
            <field>
              <name>RXFNEIE</name>
              <description>RXFIFO non-null interrupt enable</description>
              <bitRange>[5:5]</bitRange>
            </field>
            <field>
              <name>TCIE</name>
              <description>End of Transfer interrupt enabled</description>
              <bitRange>[6:6]</bitRange>
            </field>
            <field>
              <name>TXFNFIE</name>
              <description>TXFIFO is not full interrupt enabled</description>
              <bitRange>[7:7]</bitRange>
            </field>
            <field>
              <name>PEIE</name>
              <description>PE interrupt enable</description>
              <bitRange>[8:8]</bitRange>
            </field>
            <field>
              <name>PS</name>
              <description>Parity selection</description>
              <bitRange>[9:9]</bitRange>
            </field>
            <field>
              <name>PCE</name>
              <description>Parity control</description>
              <bitRange>[10:10]</bitRange>
            </field>
            <field>
              <name>WAKE</name>
              <description>Receive wake-up mode</description>
              <bitRange>[11:11]</bitRange>
            </field>
            <field>
              <name>M0</name>
              <description>Configure the word length in combination with M1</description>
              <bitRange>[12:12]</bitRange>
            </field>
            <field>
              <name>MME</name>
              <description>Silent mode enabled</description>
              <bitRange>[13:13]</bitRange>
            </field>
            <field>
              <name>CMIE</name>
              <description>Character match interrupt enabled</description>
              <bitRange>[14:14]</bitRange>
            </field>
            <field>
              <name>DEDT</name>
              <description>The time between the transmit frame stop bit and the invalid DE (driver enable) signal</description>
              <bitRange>[20:16]</bitRange>
            </field>
            <field>
              <name>DEAT</name>
              <description>The time between the DE (driver enable) signal validity and the start bit</description>
              <bitRange>[25:21]</bitRange>
            </field>
            <field>
              <name>M1</name>
              <description>The value of {M1,M0} the configurate length</description>
              <bitRange>[28:28]</bitRange>
            </field>
            <field>
              <name>FIFOEN</name>
              <description>FIFO mode enabled</description>
              <bitRange>[29:29]</bitRange>
            </field>
            <field>
              <name>TXFEIE</name>
              <description>TXFIFO null interrupt enabled</description>
              <bitRange>[30:30]</bitRange>
            </field>
            <field>
              <name>RXFFIE</name>
              <description>RXFIFO full interrupt enabled</description>
              <bitRange>[31:31]</bitRange>
            </field>
          </fields>
        </register>
        <register>
          <name>CR2</name>
          <addressOffset>0x4</addressOffset>
          <fields>
            <field>
              <name>ADDM7</name>
              <description>7bit/4bit address detection configuration</description>
              <bitRange>[4:4]</bitRange>
            </field>
            <field>
              <name>STOP</name>
              <description>Stop bit configuration</description>
              <bitRange>[13:12]</bitRange>
            </field>
            <field>
              <name>SWAP</name>
              <description>TX/RX pin interchangeable</description>
              <bitRange>[15:15]</bitRange>
            </field>
            <field>
              <name>RXINV</name>
              <description>The RX pin is active level inverting</description>
              <bitRange>[16:16]</bitRange>
            </field>
            <field>
              <name>TXINV</name>
              <description>TX pin active level inverted</description>
              <bitRange>[17:17]</bitRange>
            </field>
            <field>
              <name>DATAINV</name>
              <description>Inverse binary data processing</description>
              <bitRange>[18:18]</bitRange>
            </field>
            <field>
              <name>MSBFIRST</name>
              <description>MSB first</description>
              <bitRange>[19:19]</bitRange>
            </field>
            <field>
              <name>TXOE_ALWAYS_ON</name>
              <bitRange>[20:20]</bitRange>
            </field>
            <field>
              <name>ADD</name>
              <description>LPUART address</description>
              <bitRange>[31:24]</bitRange>
            </field>
          </fields>
        </register>
        <register>
          <name>CR3</name>
          <addressOffset>0x8</addressOffset>
          <fields>
            <field>
              <name>EIE</name>
              <description>Error interrupts are enabled</description>
              <bitRange>[0:0]</bitRange>
            </field>
            <field>
              <name>HDSEL</name>
              <description>Half-duplex selection</description>
              <bitRange>[3:3]</bitRange>
            </field>
            <field>
              <name>DMAR</name>
              <description>Enable DMA on reception</description>
              <bitRange>[6:6]</bitRange>
            </field>
            <field>
              <name>DMAT</name>
              <description>Enable DMA while transmitting</description>
              <bitRange>[7:7]</bitRange>
            </field>
            <field>
              <name>RTSE</name>
              <description>RTS enabled</description>
              <bitRange>[8:8]</bitRange>
            </field>
            <field>
              <name>CTSE</name>
              <description>CTS enabled</description>
              <bitRange>[9:9]</bitRange>
            </field>
            <field>
              <name>CTSIE</name>
              <description>CTS interrupt enable</description>
              <bitRange>[10:10]</bitRange>
            </field>
            <field>
              <name>OVRDIS</name>
              <description>Overrun is prohibited</description>
              <bitRange>[12:12]</bitRange>
            </field>
            <field>
              <name>DDRE</name>
              <description>Whether DMA is disabled when receiving an error</description>
              <bitRange>[13:13]</bitRange>
            </field>
            <field>
              <name>DEM</name>
              <description>DE mode enabled</description>
              <bitRange>[14:14]</bitRange>
            </field>
            <field>
              <name>DEP</name>
              <description>DE polarity selection</description>
              <bitRange>[15:15]</bitRange>
            </field>
            <field>
              <name>WUS</name>
              <description>Low-power wake-up options</description>
              <bitRange>[21:20]</bitRange>
            </field>
            <field>
              <name>WUFIE</name>
              <description>Low-power wake-up interrupt enable</description>
              <bitRange>[22:22]</bitRange>
            </field>
            <field>
              <name>TXFTIE</name>
              <description>TXFIFO threshold interrupt enabled</description>
              <bitRange>[23:23]</bitRange>
            </field>
            <field>
              <name>RXFTCFG</name>
              <description>RXFIFO full threshold configuration</description>
              <bitRange>[27:25]</bitRange>
            </field>
            <field>
              <name>RXFTIE</name>
              <description>RXFIFO threshold interrupt enabled</description>
              <bitRange>[28:28]</bitRange>
            </field>
            <field>
              <name>TXFTCFG</name>
              <description>TXFIFO threshold configuration</description>
              <bitRange>[31:29]</bitRange>
            </field>
          </fields>
        </register>
        <register>
          <name>BRR</name>
          <addressOffset>0xC</addressOffset>
          <fields>
            <field>
              <name>BBR</name>
              <description>LPUART baud rate</description>
              <bitRange>[19:0]</bitRange>
            </field>
          </fields>
        </register>
        <register>
          <name>RQR</name>
          <addressOffset>0x18</addressOffset>
          <fields>
            <field>
              <name>SBKRQ</name>
              <description>Send an abort request</description>
              <bitRange>[1:1]</bitRange>
            </field>
            <field>
              <name>MMRQ</name>
              <description>Silent mode request</description>
              <bitRange>[2:2]</bitRange>
            </field>
            <field>
              <name>RXFRQ</name>
              <description>Receive a data refresh request</description>
              <bitRange>[3:3]</bitRange>
            </field>
            <field>
              <name>TXFRQ</name>
              <description>Route a data refresh request</description>
              <bitRange>[4:4]</bitRange>
            </field>
          </fields>
        </register>
        <register>
          <name>ISR</name>
          <addressOffset>0x1C</addressOffset>
          <fields>
            <field>
              <name>PE</name>
              <description>Parity error</description>
              <bitRange>[0:0]</bitRange>
              <access>read-only</access>
            </field>
            <field>
              <name>FE</name>
              <description>Frame error flag</description>
              <bitRange>[1:1]</bitRange>
              <access>read-only</access>
            </field>
            <field>
              <name>NE</name>
              <description>START bit noise flag</description>
              <bitRange>[2:2]</bitRange>
              <access>read-only</access>
            </field>
            <field>
              <name>ORE</name>
              <description>Overrun error flag</description>
              <bitRange>[3:3]</bitRange>
              <access>read-only</access>
            </field>
            <field>
              <name>IDLE</name>
              <description>idle flag</description>
              <bitRange>[4:4]</bitRange>
              <access>read-only</access>
            </field>
            <field>
              <name>RXFNE</name>
              <description>RX register not empty</description>
              <bitRange>[5:5]</bitRange>
              <access>read-only</access>
            </field>
            <field>
              <name>TC</name>
              <description>Transmission completion flag</description>
              <bitRange>[6:6]</bitRange>
              <access>read-only</access>
            </field>
            <field>
              <name>TXFNF</name>
              <description>TX register not full</description>
              <bitRange>[7:7]</bitRange>
              <access>read-only</access>
            </field>
            <field>
              <name>CTSIF</name>
              <description>CTS interrupt flag</description>
              <bitRange>[9:9]</bitRange>
              <access>read-only</access>
            </field>
            <field>
              <name>CTS</name>
              <description>CTS flag</description>
              <bitRange>[10:10]</bitRange>
              <access>read-only</access>
            </field>
            <field>
              <name>BUSY</name>
              <description>Busy flag</description>
              <bitRange>[16:16]</bitRange>
              <access>read-only</access>
            </field>
            <field>
              <name>CMF</name>
              <description>Address match flag</description>
              <bitRange>[17:17]</bitRange>
              <access>read-only</access>
            </field>
            <field>
              <name>SBKF</name>
              <description>Send abort flag</description>
              <bitRange>[18:18]</bitRange>
              <access>read-only</access>
            </field>
            <field>
              <name>RWU</name>
              <description>Receive Mute mode wake-up flag</description>
              <bitRange>[19:19]</bitRange>
              <access>read-only</access>
            </field>
            <field>
              <name>WUF</name>
              <description>Wake flag from low-power mode</description>
              <bitRange>[20:20]</bitRange>
              <access>read-only</access>
            </field>
            <field>
              <name>TEACK</name>
              <description>Transport enable acknowledgement flag</description>
              <bitRange>[21:21]</bitRange>
              <access>read-only</access>
            </field>
            <field>
              <name>REACK</name>
              <description>Receive the enable acknowledgment flag</description>
              <bitRange>[22:22]</bitRange>
              <access>read-only</access>
            </field>
            <field>
              <name>TXFE</name>
              <description>TXFIFO empty</description>
              <bitRange>[23:23]</bitRange>
              <access>read-only</access>
            </field>
            <field>
              <name>RXFF</name>
              <description>RXFIFO full logo</description>
              <bitRange>[24:24]</bitRange>
              <access>read-only</access>
            </field>
            <field>
              <name>RXFT</name>
              <description>RCFIFO threshold flag</description>
              <bitRange>[26:26]</bitRange>
              <access>read-only</access>
            </field>
            <field>
              <name>TXFT</name>
              <description>TXFIFO threshold flag</description>
              <bitRange>[27:27]</bitRange>
              <access>read-only</access>
            </field>
          </fields>
        </register>
        <register>
          <name>ICR</name>
          <addressOffset>0x20</addressOffset>
          <fields>
            <field>
              <name>PECF</name>
              <description>Check value error flag reset</description>
              <bitRange>[0:0]</bitRange>
            </field>
            <field>
              <name>FECF</name>
              <description>Frame error flag reset</description>
              <bitRange>[1:1]</bitRange>
            </field>
            <field>
              <name>NECF</name>
              <description>Clear the START bit noise flag</description>
              <bitRange>[2:2]</bitRange>
            </field>
            <field>
              <name>ORECF</name>
              <description>Overrun error flag reset</description>
              <bitRange>[3:3]</bitRange>
            </field>
            <field>
              <name>IDLECF</name>
              <description>Clear idle flag</description>
              <bitRange>[4:4]</bitRange>
            </field>
            <field>
              <name>TCCF</name>
              <description>Transfer completion flag reset</description>
              <bitRange>[6:6]</bitRange>
            </field>
            <field>
              <name>CTSCF</name>
              <description>CTS flag reset</description>
              <bitRange>[9:9]</bitRange>
            </field>
            <field>
              <name>CMCF</name>
              <description>Address matching flag reset</description>
              <bitRange>[17:17]</bitRange>
            </field>
            <field>
              <name>WUCF</name>
              <description>Low power wake-up flag reset</description>
              <bitRange>[20:20]</bitRange>
            </field>
          </fields>
        </register>
        <register>
          <name>RDR</name>
          <addressOffset>0x24</addressOffset>
          <fields>
            <field>
              <name>RDR</name>
              <description>Receive Data Register</description>
              <bitRange>[8:0]</bitRange>
              <access>read-only</access>
            </field>
          </fields>
        </register>
        <register>
          <name>TDR</name>
          <addressOffset>0x28</addressOffset>
          <fields>
            <field>
              <name>TDR</name>
              <description>Transmit Data Register</description>
              <bitRange>[8:0]</bitRange>
            </field>
          </fields>
        </register>
        <register>
          <name>PRESC</name>
          <addressOffset>0x2C</addressOffset>
          <fields>
            <field>
              <name>PRESCALER</name>
              <description>Input clock prescaler register</description>
              <bitRange>[3:0]</bitRange>
            </field>
          </fields>
        </register>
      </registers>
    </peripheral>
    <peripheral>
      <name>OPA</name>
      <baseAddress>0x40017000</baseAddress>
      <addressBlock>
        <offset>0x0</offset>
        <size>0x30</size>
        <usage>registers</usage>
      </addressBlock>
      <registers>
        <register>
          <name>OPA1_CSR</name>
          <addressOffset>0x0</addressOffset>
          <fields>
            <field>
              <name>OPA1_EN</name>
              <bitRange>[0:0]</bitRange>
            </field>
            <field>
              <name>OPA1_VPSEL</name>
              <bitRange>[2:2]</bitRange>
            </field>
            <field>
              <name>OPA1_VNSEL</name>
              <bitRange>[5:5]</bitRange>
            </field>
            <field>
              <name>OPA1_INTOEN</name>
              <bitRange>[8:8]</bitRange>
            </field>
            <field>
              <name>OPA1_EXTOEN</name>
              <bitRange>[9:9]</bitRange>
            </field>
            <field>
              <name>OPA1_MODE</name>
              <bitRange>[15:14]</bitRange>
            </field>
            <field>
              <name>OPA1_PGA_GAIN</name>
              <bitRange>[19:16]</bitRange>
            </field>
            <field>
              <name>OPA_VBIAS</name>
              <bitRange>[26:23]</bitRange>
            </field>
            <field>
              <name>OPA_VREF_SEL</name>
              <bitRange>[27:27]</bitRange>
            </field>
            <field>
              <name>OPA1_VBSEL</name>
              <bitRange>[29:29]</bitRange>
            </field>
            <field>
              <name>OPA1_LOCK</name>
              <bitRange>[31:31]</bitRange>
            </field>
          </fields>
        </register>
        <register>
          <name>OPA2_CSR</name>
          <addressOffset>0x4</addressOffset>
          <fields>
            <field>
              <name>OPA2_EN</name>
              <bitRange>[0:0]</bitRange>
            </field>
            <field>
              <name>OPA2_VPSEL</name>
              <bitRange>[2:2]</bitRange>
            </field>
            <field>
              <name>OPA2_VNSEL</name>
              <bitRange>[6:5]</bitRange>
            </field>
            <field>
              <name>OPA2_INTOEN</name>
              <bitRange>[8:8]</bitRange>
            </field>
            <field>
              <name>OPA2_EXTOEN</name>
              <bitRange>[9:9]</bitRange>
            </field>
            <field>
              <name>OPA2_PGA_GAIN</name>
              <bitRange>[19:16]</bitRange>
            </field>
            <field>
              <name>OPA2_VBSEL</name>
              <bitRange>[29:29]</bitRange>
            </field>
            <field>
              <name>OPA2_LOCK</name>
              <bitRange>[31:31]</bitRange>
            </field>
          </fields>
        </register>
        <register>
          <name>OPA3_CSR</name>
          <addressOffset>0x8</addressOffset>
          <fields>
            <field>
              <name>OPA3_EN</name>
              <bitRange>[0:0]</bitRange>
            </field>
            <field>
              <name>OPA3_VPSEL</name>
              <bitRange>[3:2]</bitRange>
            </field>
            <field>
              <name>OPA3_VNSEL</name>
              <bitRange>[6:5]</bitRange>
            </field>
            <field>
              <name>OPA3_INTOEN</name>
              <bitRange>[8:8]</bitRange>
            </field>
            <field>
              <name>OPA3_EXTOEN</name>
              <bitRange>[9:9]</bitRange>
            </field>
            <field>
              <name>OPA3_MODE</name>
              <bitRange>[15:14]</bitRange>
            </field>
            <field>
              <name>OPA3_PGA_GAIN</name>
              <bitRange>[19:16]</bitRange>
            </field>
            <field>
              <name>OPA3_VBSEL</name>
              <bitRange>[29:29]</bitRange>
            </field>
            <field>
              <name>OPA3_LOCK</name>
              <bitRange>[31:31]</bitRange>
            </field>
          </fields>
        </register>
        <register>
          <name>OPA4_CSR</name>
          <addressOffset>0xC</addressOffset>
          <fields>
            <field>
              <name>OPA4_EN</name>
              <bitRange>[0:0]</bitRange>
            </field>
            <field>
              <name>OPA4_VNSEL</name>
              <bitRange>[5:5]</bitRange>
            </field>
            <field>
              <name>OPA4_INTOEN</name>
              <bitRange>[8:8]</bitRange>
            </field>
            <field>
              <name>OPA4_EXTOEN</name>
              <bitRange>[9:9]</bitRange>
            </field>
            <field>
              <name>OPA4_MODE</name>
              <bitRange>[15:14]</bitRange>
            </field>
            <field>
              <name>OPA4_PGA_GAIN</name>
              <bitRange>[19:16]</bitRange>
            </field>
            <field>
              <name>OPA4_VBSEL</name>
              <bitRange>[29:29]</bitRange>
            </field>
            <field>
              <name>OPA4_LOCK</name>
              <bitRange>[31:31]</bitRange>
            </field>
          </fields>
        </register>
      </registers>
    </peripheral>
    <peripheral>
      <name>PWR</name>
      <baseAddress>0x40007000</baseAddress>
      <addressBlock>
        <offset>0x0</offset>
        <size>0x20</size>
        <usage>registers</usage>
      </addressBlock>
      <registers>
        <register>
          <name>CR1</name>
          <addressOffset>0x0</addressOffset>
          <fields>
            <field>
              <name>LPMS_ACTIVE</name>
              <bitRange>[0:0]</bitRange>
            </field>
            <field>
              <name>LPMS_SLP</name>
              <bitRange>[1:1]</bitRange>
            </field>
            <field>
              <name>VR_MODE_SLP</name>
              <bitRange>[5:4]</bitRange>
            </field>
            <field>
              <name>DBP</name>
              <bitRange>[8:8]</bitRange>
            </field>
            <field>
              <name>FLS_WUPT</name>
              <bitRange>[13:12]</bitRange>
            </field>
            <field>
              <name>MR_VSEL</name>
              <bitRange>[17:16]</bitRange>
            </field>
            <field>
              <name>HSION_CTRL</name>
              <bitRange>[25:25]</bitRange>
            </field>
            <field>
              <name>STDBY_MRRDY_WAIT</name>
              <bitRange>[27:26]</bitRange>
            </field>
          </fields>
        </register>
        <register>
          <name>CR2</name>
          <addressOffset>0x4</addressOffset>
          <fields>
            <field>
              <name>PVDE</name>
              <bitRange>[0:0]</bitRange>
            </field>
            <field>
              <name>PVDT</name>
              <bitRange>[3:1]</bitRange>
            </field>
            <field>
              <name>PVD_OUT_SEL</name>
              <bitRange>[7:7]</bitRange>
            </field>
            <field>
              <name>FLTEN</name>
              <bitRange>[8:8]</bitRange>
            </field>
            <field>
              <name>FLT_CTRL</name>
              <bitRange>[11:9]</bitRange>
            </field>
          </fields>
        </register>
        <register>
          <name>CR3</name>
          <addressOffset>0x8</addressOffset>
          <fields>
            <field>
              <name>EWUPX</name>
              <bitRange>[4:0]</bitRange>
            </field>
            <field>
              <name>RRS</name>
              <bitRange>[16:16]</bitRange>
            </field>
          </fields>
        </register>
        <register>
          <name>CR4</name>
          <addressOffset>0xC</addressOffset>
          <fields>
            <field>
              <name>EWUPX</name>
              <bitRange>[9:0]</bitRange>
            </field>
          </fields>
        </register>
        <register>
          <name>SR</name>
          <addressOffset>0x10</addressOffset>
          <fields>
            <field>
              <name>WUFX</name>
              <bitRange>[4:0]</bitRange>
            </field>
            <field>
              <name>SBF</name>
              <bitRange>[16:16]</bitRange>
              <access>read-only</access>
            </field>
            <field>
              <name>PVDO</name>
              <bitRange>[22:22]</bitRange>
              <access>read-only</access>
            </field>
            <field>
              <name>MR_RDY</name>
              <bitRange>[23:23]</bitRange>
              <access>read-only</access>
            </field>
          </fields>
        </register>
        <register>
          <name>SCR</name>
          <addressOffset>0x14</addressOffset>
          <fields>
            <field>
              <name>CWUFX</name>
              <bitRange>[4:0]</bitRange>
              <access>write-only</access>
            </field>
            <field>
              <name>CSBF</name>
              <bitRange>[16:16]</bitRange>
              <access>write-only</access>
            </field>
          </fields>
        </register>
      </registers>
    </peripheral>
    <peripheral>
      <name>RCC</name>
      <description>desc RCC</description>
      <baseAddress>0x40021000</baseAddress>
      <addressBlock>
        <offset>0x0</offset>
        <size>0x400</size>
        <usage>registers</usage>
      </addressBlock>
      <interrupt>
        <name>RCC_CTC</name>
        <description>RCC global Interrupt</description>
        <value>5</value>
      </interrupt>
      <registers>
        <register>
          <name>CR</name>
          <description>clock control register</description>
          <addressOffset>0x0</addressOffset>
          <fields>
            <field>
              <name>HSION</name>
              <bitRange>[8:8]</bitRange>
            </field>
            <field>
              <name>HSIKERON</name>
              <bitRange>[9:9]</bitRange>
            </field>
            <field>
              <name>HSIRDY</name>
              <bitRange>[10:10]</bitRange>
              <access>read-only</access>
            </field>
            <field>
              <name>HSIDIV</name>
              <bitRange>[13:11]</bitRange>
            </field>
            <field>
              <name>HSEON</name>
              <bitRange>[16:16]</bitRange>
            </field>
            <field>
              <name>HSERDY</name>
              <bitRange>[17:17]</bitRange>
              <access>read-only</access>
            </field>
            <field>
              <name>HSEBYP</name>
              <bitRange>[18:18]</bitRange>
            </field>
            <field>
              <name>HSECSSON</name>
              <bitRange>[19:19]</bitRange>
            </field>
            <field>
              <name>PLLON</name>
              <bitRange>[24:24]</bitRange>
            </field>
            <field>
              <name>PLLRDY</name>
              <bitRange>[25:25]</bitRange>
              <access>read-only</access>
            </field>
          </fields>
        </register>
        <register>
          <name>ICSCR</name>
          <addressOffset>0x8</addressOffset>
          <fields>
            <field>
              <name>HSI_TRIMCR</name>
              <bitRange>[15:0]</bitRange>
            </field>
            <field>
              <name>HSI_FS</name>
              <bitRange>[17:16]</bitRange>
            </field>
          </fields>
        </register>
        <register>
          <name>CFGR1</name>
          <description>clock configuration register 1</description>
          <addressOffset>0x14</addressOffset>
          <fields>
            <field>
              <name>SW</name>
              <bitRange>[1:0]</bitRange>
            </field>
            <field>
              <name>SWS</name>
              <bitRange>[5:4]</bitRange>
              <access>read-only</access>
            </field>
            <field>
              <name>HPRE</name>
              <bitRange>[11:8]</bitRange>
            </field>
            <field>
              <name>PPRE1</name>
              <bitRange>[15:12]</bitRange>
            </field>
            <field>
              <name>MCO1SEL</name>
              <bitRange>[19:16]</bitRange>
            </field>
            <field>
              <name>MCO1PRE</name>
              <bitRange>[23:20]</bitRange>
            </field>
            <field>
              <name>MCO2SEL</name>
              <bitRange>[27:24]</bitRange>
            </field>
            <field>
              <name>MCO2PRE</name>
              <bitRange>[31:28]</bitRange>
            </field>
          </fields>
        </register>
        <register>
          <name>CFGR2</name>
          <description>desc CFGR2</description>
          <addressOffset>0x18</addressOffset>
          <fields>
            <field>
              <name>PPRE2</name>
              <bitRange>[11:8]</bitRange>
            </field>
          </fields>
        </register>
        <register>
          <name>PLLCFGR1</name>
          <addressOffset>0x24</addressOffset>
          <fields>
            <field>
              <name>PLLSRC</name>
              <bitRange>[0:0]</bitRange>
            </field>
            <field>
              <name>PLLMUL</name>
              <bitRange>[5:2]</bitRange>
            </field>
          </fields>
        </register>
        <register>
          <name>ECSCR</name>
          <addressOffset>0x38</addressOffset>
          <fields>
            <field>
              <name>HSE_DRV</name>
              <bitRange>[1:0]</bitRange>
            </field>
            <field>
              <name>HSE_RDYSEL</name>
              <bitRange>[3:2]</bitRange>
            </field>
            <field>
              <name>HSE_FILT_ENB</name>
              <bitRange>[4:4]</bitRange>
            </field>
          </fields>
        </register>
        <register>
          <name>CIER</name>
          <addressOffset>0x3C</addressOffset>
          <fields>
            <field>
              <name>LSIRDYIE</name>
              <bitRange>[0:0]</bitRange>
            </field>
            <field>
              <name>HSIRDYIE</name>
              <bitRange>[2:2]</bitRange>
            </field>
            <field>
              <name>HSERDYIE</name>
              <bitRange>[3:3]</bitRange>
            </field>
            <field>
              <name>PLLRDYIE</name>
              <bitRange>[4:4]</bitRange>
            </field>
          </fields>
        </register>
        <register>
          <name>CIFR</name>
          <addressOffset>0x40</addressOffset>
          <fields>
            <field>
              <name>LSIRDYF</name>
              <bitRange>[0:0]</bitRange>
              <access>read-only</access>
            </field>
            <field>
              <name>HSIRDYF</name>
              <bitRange>[2:2]</bitRange>
              <access>read-only</access>
            </field>
            <field>
              <name>HSERDYF</name>
              <bitRange>[3:3]</bitRange>
              <access>read-only</access>
            </field>
            <field>
              <name>PLLRDYF</name>
              <bitRange>[4:4]</bitRange>
              <access>read-only</access>
            </field>
            <field>
              <name>HSECSSF</name>
              <bitRange>[8:8]</bitRange>
              <access>read-only</access>
            </field>
          </fields>
        </register>
        <register>
          <name>CICR</name>
          <addressOffset>0x44</addressOffset>
          <fields>
            <field>
              <name>LSIRDYC</name>
              <bitRange>[0:0]</bitRange>
              <access>write-only</access>
            </field>
            <field>
              <name>HSIRDYC</name>
              <bitRange>[2:2]</bitRange>
              <access>write-only</access>
            </field>
            <field>
              <name>HSERDYC</name>
              <bitRange>[3:3]</bitRange>
              <access>write-only</access>
            </field>
            <field>
              <name>PLLRDYC</name>
              <bitRange>[4:4]</bitRange>
              <access>write-only</access>
            </field>
            <field>
              <name>HSECSSC</name>
              <bitRange>[8:8]</bitRange>
              <access>write-only</access>
            </field>
          </fields>
        </register>
        <register>
          <name>AHBRSTR1</name>
          <addressOffset>0x48</addressOffset>
          <fields>
            <field>
              <name>DMARST</name>
              <bitRange>[0:0]</bitRange>
            </field>
            <field>
              <name>CRCRST</name>
              <bitRange>[16:16]</bitRange>
            </field>
          </fields>
        </register>
        <register>
          <name>AHBRSTR2</name>
          <addressOffset>0x4C</addressOffset>
          <fields>
            <field>
              <name>GPIOARST</name>
              <bitRange>[0:0]</bitRange>
            </field>
            <field>
              <name>GPIOBRST</name>
              <bitRange>[1:1]</bitRange>
            </field>
            <field>
              <name>GPIOCRST</name>
              <bitRange>[2:2]</bitRange>
            </field>
            <field>
              <name>GPIODRST</name>
              <bitRange>[3:3]</bitRange>
            </field>
          </fields>
        </register>
        <register>
          <name>APBRSTR1</name>
          <addressOffset>0x58</addressOffset>
          <fields>
            <field>
              <name>TIM1RST</name>
              <bitRange>[1:1]</bitRange>
            </field>
            <field>
              <name>TIM2RST</name>
              <bitRange>[2:2]</bitRange>
            </field>
            <field>
              <name>TIM3RST</name>
              <bitRange>[3:3]</bitRange>
            </field>
            <field>
              <name>TIM6RST</name>
              <bitRange>[6:6]</bitRange>
            </field>
            <field>
              <name>TIM7RST</name>
              <bitRange>[7:7]</bitRange>
            </field>
            <field>
              <name>TIM8RST</name>
              <bitRange>[8:8]</bitRange>
            </field>
          </fields>
        </register>
        <register>
          <name>APBRSTR2</name>
          <addressOffset>0x5C</addressOffset>
          <fields>
            <field>
              <name>HRPWMRST</name>
              <bitRange>[8:8]</bitRange>
            </field>
          </fields>
        </register>
        <register>
          <name>APBRSTR3</name>
          <addressOffset>0x60</addressOffset>
          <fields>
            <field>
              <name>UART1RST</name>
              <bitRange>[0:0]</bitRange>
            </field>
            <field>
              <name>UART2RST</name>
              <bitRange>[1:1]</bitRange>
            </field>
            <field>
              <name>USARTRST</name>
              <bitRange>[6:6]</bitRange>
            </field>
            <field>
              <name>LPUARTRST</name>
              <bitRange>[12:12]</bitRange>
            </field>
            <field>
              <name>I2CRST</name>
              <bitRange>[16:16]</bitRange>
            </field>
            <field>
              <name>SPIRST</name>
              <bitRange>[22:22]</bitRange>
            </field>
            <field>
              <name>CANRST</name>
              <bitRange>[28:28]</bitRange>
            </field>
          </fields>
        </register>
        <register>
          <name>APBRSTR4</name>
          <addressOffset>0x64</addressOffset>
          <fields>
            <field>
              <name>SYSCFGRST</name>
              <bitRange>[0:0]</bitRange>
            </field>
            <field>
              <name>VREFBUFRST</name>
              <bitRange>[8:8]</bitRange>
            </field>
            <field>
              <name>PWRRST</name>
              <bitRange>[9:9]</bitRange>
            </field>
            <field>
              <name>ADC1RST</name>
              <bitRange>[11:11]</bitRange>
            </field>
            <field>
              <name>ADC2RST</name>
              <bitRange>[12:12]</bitRange>
            </field>
            <field>
              <name>DACRST</name>
              <bitRange>[16:16]</bitRange>
            </field>
            <field>
              <name>OPARST</name>
              <bitRange>[20:20]</bitRange>
            </field>
            <field>
              <name>COMPRST</name>
              <bitRange>[24:24]</bitRange>
            </field>
          </fields>
        </register>
        <register>
          <name>AHBENR1</name>
          <addressOffset>0x70</addressOffset>
          <fields>
            <field>
              <name>DMAEN</name>
              <bitRange>[0:0]</bitRange>
            </field>
            <field>
              <name>FLASHSMEN</name>
              <bitRange>[4:4]</bitRange>
            </field>
            <field>
              <name>SRAMSMEN</name>
              <bitRange>[5:5]</bitRange>
            </field>
            <field>
              <name>CRCEN</name>
              <bitRange>[16:16]</bitRange>
            </field>
          </fields>
        </register>
        <register>
          <name>AHBENR2</name>
          <addressOffset>0x74</addressOffset>
          <fields>
            <field>
              <name>GPIOAEN</name>
              <bitRange>[0:0]</bitRange>
            </field>
            <field>
              <name>GPIOBEN</name>
              <bitRange>[1:1]</bitRange>
            </field>
            <field>
              <name>GPIOCEN</name>
              <bitRange>[2:2]</bitRange>
            </field>
            <field>
              <name>GPIODEN</name>
              <bitRange>[3:3]</bitRange>
            </field>
          </fields>
        </register>
        <register>
          <name>APBENR1</name>
          <addressOffset>0x80</addressOffset>
          <fields>
            <field>
              <name>TIM1EN</name>
              <bitRange>[1:1]</bitRange>
            </field>
            <field>
              <name>TIM2EN</name>
              <bitRange>[2:2]</bitRange>
            </field>
            <field>
              <name>TIM3EN</name>
              <bitRange>[3:3]</bitRange>
            </field>
            <field>
              <name>TIM6EN</name>
              <bitRange>[6:6]</bitRange>
            </field>
            <field>
              <name>TIM7EN</name>
              <bitRange>[7:7]</bitRange>
            </field>
            <field>
              <name>TIM8EN</name>
              <bitRange>[8:8]</bitRange>
            </field>
          </fields>
        </register>
        <register>
          <name>APBENR2</name>
          <addressOffset>0x84</addressOffset>
          <fields>
            <field>
              <name>HRPWMEN</name>
              <bitRange>[8:8]</bitRange>
            </field>
            <field>
              <name>WWDGEN</name>
              <bitRange>[31:31]</bitRange>
            </field>
          </fields>
        </register>
        <register>
          <name>APBENR3</name>
          <addressOffset>0x88</addressOffset>
          <fields>
            <field>
              <name>UART1EN</name>
              <bitRange>[0:0]</bitRange>
            </field>
            <field>
              <name>UART2EN</name>
              <bitRange>[1:1]</bitRange>
            </field>
            <field>
              <name>USARTEN</name>
              <bitRange>[6:6]</bitRange>
            </field>
            <field>
              <name>LPUARTEN</name>
              <bitRange>[12:12]</bitRange>
            </field>
            <field>
              <name>I2CEN</name>
              <bitRange>[16:16]</bitRange>
            </field>
            <field>
              <name>SPIEN</name>
              <bitRange>[22:22]</bitRange>
            </field>
            <field>
              <name>CANEN</name>
              <bitRange>[28:28]</bitRange>
            </field>
          </fields>
        </register>
        <register>
          <name>APBENR4</name>
          <addressOffset>0x8C</addressOffset>
          <fields>
            <field>
              <name>SYSCFGEN</name>
              <bitRange>[0:0]</bitRange>
            </field>
            <field>
              <name>BKPEN</name>
              <bitRange>[4:4]</bitRange>
            </field>
            <field>
              <name>VREFBUFEN</name>
              <bitRange>[8:8]</bitRange>
            </field>
            <field>
              <name>PWREN</name>
              <bitRange>[9:9]</bitRange>
            </field>
            <field>
              <name>ADC1EN</name>
              <bitRange>[11:11]</bitRange>
            </field>
            <field>
              <name>ADC2EN</name>
              <bitRange>[12:12]</bitRange>
            </field>
            <field>
              <name>DACEN</name>
              <bitRange>[16:16]</bitRange>
            </field>
            <field>
              <name>OPAEN</name>
              <bitRange>[20:20]</bitRange>
            </field>
            <field>
              <name>COMPEN</name>
              <bitRange>[24:24]</bitRange>
            </field>
          </fields>
        </register>
        <register>
          <name>CCIPR1</name>
          <addressOffset>0x98</addressOffset>
          <fields>
            <field>
              <name>USARTSEL</name>
              <bitRange>[1:0]</bitRange>
            </field>
            <field>
              <name>LPUARTSEL</name>
              <bitRange>[13:12]</bitRange>
            </field>
            <field>
              <name>COMP1SEL</name>
              <bitRange>[21:20]</bitRange>
            </field>
            <field>
              <name>COMP2SEL</name>
              <bitRange>[23:22]</bitRange>
            </field>
            <field>
              <name>COMP3SEL</name>
              <bitRange>[25:24]</bitRange>
            </field>
            <field>
              <name>COMP4SEL</name>
              <bitRange>[27:26]</bitRange>
            </field>
            <field>
              <name>TIMCLKCTRL</name>
              <bitRange>[28:28]</bitRange>
            </field>
            <field>
              <name>PVDSEL</name>
              <bitRange>[30:29]</bitRange>
            </field>
          </fields>
        </register>
        <register>
          <name>CCIPR2</name>
          <addressOffset>0x9C</addressOffset>
          <fields>
            <field>
              <name>CANCKSEL</name>
              <bitRange>[1:0]</bitRange>
            </field>
            <field>
              <name>ADC12SEL</name>
              <bitRange>[9:8]</bitRange>
            </field>
            <field>
              <name>ADC12KEN</name>
              <bitRange>[10:10]</bitRange>
            </field>
          </fields>
        </register>
        <register>
          <name>CCIPR3</name>
          <addressOffset>0xA0</addressOffset>
          <fields>
            <field>
              <name>PLL_ADC_DIV</name>
              <bitRange>[1:0]</bitRange>
            </field>
            <field>
              <name>PLL_CAN_DIV</name>
              <bitRange>[27:24]</bitRange>
            </field>
          </fields>
        </register>
        <register>
          <name>BDCR</name>
          <description>Backup domain control register</description>
          <addressOffset>0xB0</addressOffset>
          <fields>
            <field>
              <name>BDRST</name>
              <bitRange>[16:16]</bitRange>
            </field>
            <field>
              <name>LSI_TRIMCR</name>
              <bitRange>[25:17]</bitRange>
            </field>
            <field>
              <name>LSION</name>
              <bitRange>[26:26]</bitRange>
            </field>
            <field>
              <name>LSIRDY</name>
              <bitRange>[27:27]</bitRange>
              <access>read-only</access>
            </field>
          </fields>
        </register>
        <register>
          <name>CSR</name>
          <description>clock control &amp; status register</description>
          <addressOffset>0xB4</addressOffset>
          <fields>
            <field>
              <name>NRST_FLTDIS</name>
              <bitRange>[0:0]</bitRange>
            </field>
            <field>
              <name>RMVF</name>
              <bitRange>[8:8]</bitRange>
            </field>
            <field>
              <name>PLLULRSTF</name>
              <bitRange>[19:19]</bitRange>
            </field>
            <field>
              <name>OBLRSTF</name>
              <bitRange>[25:25]</bitRange>
              <access>read-only</access>
            </field>
            <field>
              <name>PINRSTF</name>
              <bitRange>[26:26]</bitRange>
              <access>read-only</access>
            </field>
            <field>
              <name>PWRRSTF</name>
              <bitRange>[27:27]</bitRange>
              <access>read-only</access>
            </field>
            <field>
              <name>SFTRSTF</name>
              <bitRange>[28:28]</bitRange>
              <access>read-only</access>
            </field>
            <field>
              <name>IWDGRSTF</name>
              <bitRange>[29:29]</bitRange>
              <access>read-only</access>
            </field>
            <field>
              <name>WWDGRSTF</name>
              <bitRange>[30:30]</bitRange>
              <access>read-only</access>
            </field>
            <field>
              <name>LPWRRSTF</name>
              <bitRange>[31:31]</bitRange>
              <access>read-only</access>
            </field>
          </fields>
        </register>
      </registers>
    </peripheral>
    <peripheral>
      <name>RTC</name>
      <baseAddress>0x40002800</baseAddress>
      <addressBlock>
        <offset>0x0</offset>
        <size>0x60</size>
        <usage>registers</usage>
      </addressBlock>
      <interrupt>
        <name>TAMPER</name>
        <description>Intrusion detection global interrupt</description>
        <value>2</value>
      </interrupt>
      <interrupt>
        <name>RTC</name>
        <description>RTC global interrupt</description>
        <value>3</value>
      </interrupt>
      <registers>
        <register>
          <name>CRH</name>
          <addressOffset>0x0</addressOffset>
          <fields>
            <field>
              <name>SECIE</name>
              <description>Second interrupt enable</description>
              <bitRange>[0:0]</bitRange>
            </field>
            <field>
              <name>ALRIE</name>
              <description>Alarm interrupt enable</description>
              <bitRange>[1:1]</bitRange>
            </field>
            <field>
              <name>OWIE</name>
              <description>Overflow interrupt enable</description>
              <bitRange>[2:2]</bitRange>
            </field>
          </fields>
        </register>
        <register>
          <name>CRL</name>
          <addressOffset>0x4</addressOffset>
          <fields>
            <field>
              <name>SECF</name>
              <description>Second flag</description>
              <bitRange>[0:0]</bitRange>
            </field>
            <field>
              <name>ALRF</name>
              <description>Alarm flag</description>
              <bitRange>[1:1]</bitRange>
            </field>
            <field>
              <name>OWF</name>
              <description>Overflow flag</description>
              <bitRange>[2:2]</bitRange>
            </field>
            <field>
              <name>RSF</name>
              <description>Registers synchronized flag</description>
              <bitRange>[3:3]</bitRange>
            </field>
            <field>
              <name>CNF</name>
              <description>Configuration flag</description>
              <bitRange>[4:4]</bitRange>
            </field>
            <field>
              <name>RTOFF</name>
              <description>RTC operation OFF</description>
              <bitRange>[5:5]</bitRange>
              <access>read-only</access>
            </field>
          </fields>
        </register>
        <register>
          <name>PRLH</name>
          <addressOffset>0x8</addressOffset>
          <fields>
            <field>
              <name>PRL</name>
              <description>RTC pre-scaler reload value high part</description>
              <bitRange>[3:0]</bitRange>
              <access>write-only</access>
            </field>
          </fields>
        </register>
        <register>
          <name>PRLL</name>
          <addressOffset>0xC</addressOffset>
          <fields>
            <field>
              <name>PRL</name>
              <description>RTC pre-scaler reload value low part</description>
              <bitRange>[15:0]</bitRange>
              <access>write-only</access>
            </field>
          </fields>
        </register>
        <register>
          <name>DIVH</name>
          <addressOffset>0x10</addressOffset>
          <fields>
            <field>
              <name>DIV</name>
              <description>RTC clock divider high part</description>
              <bitRange>[3:0]</bitRange>
              <access>read-only</access>
            </field>
          </fields>
        </register>
        <register>
          <name>DIVL</name>
          <addressOffset>0x14</addressOffset>
          <fields>
            <field>
              <name>DIV</name>
              <description>RTC clock divider low part</description>
              <bitRange>[15:0]</bitRange>
              <access>read-only</access>
            </field>
          </fields>
        </register>
        <register>
          <name>CNTH</name>
          <addressOffset>0x18</addressOffset>
          <fields>
            <field>
              <name>CNT</name>
              <description>RTC counter high part</description>
              <bitRange>[15:0]</bitRange>
            </field>
          </fields>
        </register>
        <register>
          <name>CNTL</name>
          <addressOffset>0x1C</addressOffset>
          <fields>
            <field>
              <name>CNT</name>
              <description>RTC counter high part</description>
              <bitRange>[15:0]</bitRange>
            </field>
          </fields>
        </register>
        <register>
          <name>ALRH</name>
          <addressOffset>0x20</addressOffset>
          <fields>
            <field>
              <name>ALR</name>
              <description>RTC alarm high part</description>
              <bitRange>[15:0]</bitRange>
            </field>
          </fields>
        </register>
        <register>
          <name>ALRL</name>
          <addressOffset>0x24</addressOffset>
          <fields>
            <field>
              <name>ALR</name>
              <description>RTC alarm low part</description>
              <bitRange>[15:0]</bitRange>
            </field>
          </fields>
        </register>
        <register>
          <name>TMPCFGR</name>
          <addressOffset>0x30</addressOffset>
          <fields>
            <field>
              <name>TPE</name>
              <description>TAMP enable</description>
              <bitRange>[0:0]</bitRange>
            </field>
            <field>
              <name>TPAL</name>
              <description>TAMPER pin interrupt enable</description>
              <bitRange>[1:1]</bitRange>
            </field>
          </fields>
        </register>
        <register>
          <name>TMPCSR</name>
          <addressOffset>0x34</addressOffset>
          <fields>
            <field>
              <name>CTE</name>
              <description>clear TAMP event</description>
              <bitRange>[0:0]</bitRange>
              <access>write-only</access>
            </field>
            <field>
              <name>CTI</name>
              <description>clear TAMP interrupt</description>
              <bitRange>[1:1]</bitRange>
              <access>write-only</access>
            </field>
            <field>
              <name>TPIE</name>
              <description>TAMP interrupt enable</description>
              <bitRange>[2:2]</bitRange>
            </field>
            <field>
              <name>TEF</name>
              <description>TAMP event flag</description>
              <bitRange>[8:8]</bitRange>
              <access>read-only</access>
            </field>
            <field>
              <name>TIF</name>
              <description>TAMP interrupt flag</description>
              <bitRange>[9:9]</bitRange>
              <access>read-only</access>
            </field>
          </fields>
        </register>
        <register>
          <name>CALIBR</name>
          <addressOffset>0x38</addressOffset>
          <fields>
            <field>
              <name>CAL</name>
              <description>RTC calibration value</description>
              <bitRange>[6:0]</bitRange>
            </field>
            <field>
              <name>CCO</name>
              <description>Calibration clock output</description>
              <bitRange>[7:7]</bitRange>
            </field>
            <field>
              <name>ASOE</name>
              <description>Alarm or second output enable</description>
              <bitRange>[8:8]</bitRange>
            </field>
            <field>
              <name>ASOS</name>
              <description>Alarm or second output selection</description>
              <bitRange>[9:9]</bitRange>
            </field>
          </fields>
        </register>
        <register>
          <name>BKPDR0</name>
          <addressOffset>0x40</addressOffset>
          <fields>
            <field>
              <name>D</name>
              <description>bakeup data word0</description>
              <bitRange>[31:0]</bitRange>
            </field>
          </fields>
        </register>
        <register>
          <name>BKPDR1</name>
          <addressOffset>0x44</addressOffset>
          <fields>
            <field>
              <name>D</name>
              <description>bakeup data word1</description>
              <bitRange>[31:0]</bitRange>
            </field>
          </fields>
        </register>
        <register>
          <name>BKPDR2</name>
          <addressOffset>0x48</addressOffset>
          <fields>
            <field>
              <name>D</name>
              <description>bakeup data word2</description>
              <bitRange>[31:0]</bitRange>
            </field>
          </fields>
        </register>
        <register>
          <name>BKPDR3</name>
          <addressOffset>0x4C</addressOffset>
          <fields>
            <field>
              <name>D</name>
              <description>bakeup data word3</description>
              <bitRange>[31:0]</bitRange>
            </field>
          </fields>
        </register>
        <register>
          <name>BKPDR4</name>
          <addressOffset>0x50</addressOffset>
          <fields>
            <field>
              <name>D</name>
              <description>bakeup data word4</description>
              <bitRange>[31:0]</bitRange>
            </field>
          </fields>
        </register>
      </registers>
    </peripheral>
    <peripheral>
      <name>SPI1</name>
      <groupName>SPI</groupName>
      <baseAddress>0x40013000</baseAddress>
      <addressBlock>
        <offset>0x0</offset>
        <size>0x30</size>
        <usage>registers</usage>
      </addressBlock>
      <interrupt>
        <name>SPI1</name>
        <description>SPI1 global Interrupt</description>
        <value>34</value>
      </interrupt>
      <registers>
        <register>
          <name>CR1</name>
          <addressOffset>0x0</addressOffset>
          <fields>
            <field>
              <name>CPHA</name>
              <description>Clock Phase</description>
              <bitRange>[0:0]</bitRange>
            </field>
            <field>
              <name>CPOL</name>
              <description>Clock Polarity</description>
              <bitRange>[1:1]</bitRange>
            </field>
            <field>
              <name>MSTR</name>
              <description>Master Selection</description>
              <bitRange>[2:2]</bitRange>
            </field>
            <field>
              <name>BR</name>
              <description>Baud Rate Control</description>
              <bitRange>[5:3]</bitRange>
            </field>
            <field>
              <name>SPE</name>
              <description>SPI Enable</description>
              <bitRange>[6:6]</bitRange>
            </field>
            <field>
              <name>LSBFIRST</name>
              <description>Frame Format</description>
              <bitRange>[7:7]</bitRange>
            </field>
            <field>
              <name>SSI</name>
              <description>Internal slave select</description>
              <bitRange>[8:8]</bitRange>
            </field>
            <field>
              <name>SSM</name>
              <description>Software slave management</description>
              <bitRange>[9:9]</bitRange>
            </field>
            <field>
              <name>RXONLY</name>
              <description>Receive only</description>
              <bitRange>[10:10]</bitRange>
            </field>
            <field>
              <name>DFF</name>
              <description>Data frame format</description>
              <bitRange>[11:11]</bitRange>
            </field>
            <field>
              <name>CRCNEXT</name>
              <description>Transmit CRC next</description>
              <bitRange>[12:12]</bitRange>
            </field>
            <field>
              <name>CRCEN</name>
              <description>Hardware CRC calculation enable</description>
              <bitRange>[13:13]</bitRange>
            </field>
            <field>
              <name>BIDIOE</name>
              <description>Output enable in bidirectional mode</description>
              <bitRange>[14:14]</bitRange>
            </field>
            <field>
              <name>BIDIMODE</name>
              <description>Bidirectional data mode enable</description>
              <bitRange>[15:15]</bitRange>
            </field>
          </fields>
        </register>
        <register>
          <name>CR2</name>
          <addressOffset>0x4</addressOffset>
          <fields>
            <field>
              <name>RXDMAEN</name>
              <description>Rx buffer DMA enable</description>
              <bitRange>[0:0]</bitRange>
            </field>
            <field>
              <name>TXDMAEN</name>
              <description>Tx buffer DMA enable</description>
              <bitRange>[1:1]</bitRange>
            </field>
            <field>
              <name>SSOE</name>
              <description>SS Output Enable</description>
              <bitRange>[2:2]</bitRange>
            </field>
            <field>
              <name>CLRTXFIFO</name>
              <description>Clear FIFO</description>
              <bitRange>[4:4]</bitRange>
            </field>
            <field>
              <name>ERRIE</name>
              <description>Error Interrupt Enable</description>
              <bitRange>[5:5]</bitRange>
            </field>
            <field>
              <name>RXNEIE</name>
              <description>RX buffer Not Empty Interrupt Enable</description>
              <bitRange>[6:6]</bitRange>
            </field>
            <field>
              <name>TXEIE</name>
              <description>Tx buffer Empty Interrupt Enable</description>
              <bitRange>[7:7]</bitRange>
            </field>
            <field>
              <name>FRF</name>
              <bitRange>[15:15]</bitRange>
            </field>
          </fields>
        </register>
        <register>
          <name>SR</name>
          <addressOffset>0x8</addressOffset>
          <fields>
            <field>
              <name>RXNE</name>
              <description>Receive buffer Not Empty</description>
              <bitRange>[0:0]</bitRange>
              <access>read-only</access>
            </field>
            <field>
              <name>TXE</name>
              <description>Transmit buffer Empty</description>
              <bitRange>[1:1]</bitRange>
              <access>read-only</access>
            </field>
            <field>
              <name>CHSIDE</name>
              <description>Channel side</description>
              <bitRange>[2:2]</bitRange>
              <access>read-only</access>
            </field>
            <field>
              <name>UDR</name>
              <description>Underrun flag</description>
              <bitRange>[3:3]</bitRange>
              <access>read-only</access>
            </field>
            <field>
              <name>CRCERR</name>
              <description>CRC error flag</description>
              <bitRange>[4:4]</bitRange>
            </field>
            <field>
              <name>MODF</name>
              <description>Mode fault</description>
              <bitRange>[5:5]</bitRange>
            </field>
            <field>
              <name>OVR</name>
              <description>Overrun flag</description>
              <bitRange>[6:6]</bitRange>
              <access>read-only</access>
            </field>
            <field>
              <name>BSY</name>
              <description>Busy flag</description>
              <bitRange>[7:7]</bitRange>
              <access>read-only</access>
            </field>
            <field>
              <name>FRE</name>
              <bitRange>[8:8]</bitRange>
              <access>read-only</access>
            </field>
            <field>
              <name>FRLVL</name>
              <description>FIFO Reception Level</description>
              <bitRange>[10:9]</bitRange>
              <access>read-only</access>
            </field>
            <field>
              <name>FTLVL</name>
              <description>FIFO Transmission Level</description>
              <bitRange>[12:11]</bitRange>
              <access>read-only</access>
            </field>
          </fields>
        </register>
        <register>
          <name>DR</name>
          <addressOffset>0xC</addressOffset>
          <fields>
            <field>
              <name>DR</name>
              <description>Data Register</description>
              <bitRange>[15:0]</bitRange>
            </field>
          </fields>
        </register>
        <register>
          <name>CRCPR</name>
          <addressOffset>0x10</addressOffset>
          <fields>
            <field>
              <name>CRCPOLY</name>
              <description>CRC polynomial register</description>
              <bitRange>[15:0]</bitRange>
            </field>
          </fields>
        </register>
        <register>
          <name>RXCRCR</name>
          <addressOffset>0x14</addressOffset>
          <fields>
            <field>
              <name>RXCRC</name>
              <description>rcv crc reg</description>
              <bitRange>[15:0]</bitRange>
              <access>read-only</access>
            </field>
          </fields>
        </register>
        <register>
          <name>TXCRCR</name>
          <addressOffset>0x18</addressOffset>
          <fields>
            <field>
              <name>TXCRC</name>
              <description>tx crc reg</description>
              <bitRange>[15:0]</bitRange>
              <access>read-only</access>
            </field>
          </fields>
        </register>
        <register>
          <name>I2S_CFGR</name>
          <addressOffset>0x1C</addressOffset>
          <fields>
            <field>
              <name>CHLEN</name>
              <description>Channel length (number of bits per audio channel</description>
              <bitRange>[0:0]</bitRange>
            </field>
            <field>
              <name>DATLEN</name>
              <description>Data length to be transferred</description>
              <bitRange>[2:1]</bitRange>
            </field>
            <field>
              <name>CKPOL</name>
              <description>Steady state clock polarity</description>
              <bitRange>[3:3]</bitRange>
            </field>
            <field>
              <name>I2SSTD</name>
              <description>I2S standard selection</description>
              <bitRange>[5:4]</bitRange>
            </field>
            <field>
              <name>PCMSYNC</name>
              <description>PCM frame synchronization</description>
              <bitRange>[7:7]</bitRange>
            </field>
            <field>
              <name>I2SCFG</name>
              <description>I2S configuration mode</description>
              <bitRange>[9:8]</bitRange>
            </field>
            <field>
              <name>I2SE</name>
              <description>I2S enable</description>
              <bitRange>[10:10]</bitRange>
            </field>
            <field>
              <name>I2SMOD</name>
              <description>I2S mode selection</description>
              <bitRange>[11:11]</bitRange>
            </field>
          </fields>
        </register>
        <register>
          <name>I2SPR</name>
          <addressOffset>0x20</addressOffset>
          <fields>
            <field>
              <name>I2SDIV</name>
              <description>I2S linear prescaler</description>
              <bitRange>[7:0]</bitRange>
            </field>
            <field>
              <name>ODD</name>
              <description>Odd factor for the prescaler</description>
              <bitRange>[8:8]</bitRange>
            </field>
            <field>
              <name>MCKOE</name>
              <description>Master clock output enable</description>
              <bitRange>[9:9]</bitRange>
            </field>
          </fields>
        </register>
      </registers>
    </peripheral>
    <peripheral derivedFrom="SPI1">
      <name>SPI2</name>
      <baseAddress>0x40003800</baseAddress>
      <interrupt>
        <name>SPI2</name>
        <description>SPI2 global Interrupt</description>
        <value>35</value>
      </interrupt>
    </peripheral>
    <peripheral>
      <name>SYSCFG</name>
      <baseAddress>0x40010000</baseAddress>
      <addressBlock>
        <offset>0x0</offset>
        <size>0x50</size>
        <usage>registers</usage>
      </addressBlock>
      <registers>
        <register>
          <name>CFGR1</name>
          <addressOffset>0x0</addressOffset>
          <fields>
            <field>
              <name>MEM_MODE</name>
              <bitRange>[1:0]</bitRange>
            </field>
            <field>
              <name>I2C_FMP</name>
              <bitRange>[2:2]</bitRange>
            </field>
            <field>
              <name>I2C_FLTEN</name>
              <bitRange>[4:4]</bitRange>
            </field>
          </fields>
        </register>
        <register>
          <name>CFGR2</name>
          <addressOffset>0x4</addressOffset>
          <fields>
            <field>
              <name>CLL</name>
              <bitRange>[0:0]</bitRange>
            </field>
            <field>
              <name>PVDL</name>
              <bitRange>[2:2]</bitRange>
            </field>
          </fields>
        </register>
        <register>
          <name>CFGR3</name>
          <addressOffset>0x8</addressOffset>
          <fields>
            <field>
              <name>DMA_MAP1</name>
              <bitRange>[6:0]</bitRange>
            </field>
            <field>
              <name>DMA_MAP2</name>
              <bitRange>[14:8]</bitRange>
            </field>
            <field>
              <name>DMA_MAP3</name>
              <bitRange>[22:16]</bitRange>
            </field>
            <field>
              <name>DMA_MAP4</name>
              <bitRange>[30:24]</bitRange>
            </field>
          </fields>
        </register>
        <register>
          <name>CFGR4</name>
          <addressOffset>0xC</addressOffset>
          <fields>
            <field>
              <name>DMA_MAP5</name>
              <bitRange>[6:0]</bitRange>
            </field>
          </fields>
        </register>
        <register>
          <name>EXTICR1</name>
          <addressOffset>0x14</addressOffset>
          <fields>
            <field>
              <name>EXTI0</name>
              <bitRange>[1:0]</bitRange>
            </field>
            <field>
              <name>EXTI1</name>
              <bitRange>[5:4]</bitRange>
            </field>
            <field>
              <name>EXTI2</name>
              <bitRange>[9:8]</bitRange>
            </field>
            <field>
              <name>EXTI3</name>
              <bitRange>[13:12]</bitRange>
            </field>
          </fields>
        </register>
        <register>
          <name>EXTICR2</name>
          <addressOffset>0x18</addressOffset>
          <fields>
            <field>
              <name>EXTI4</name>
              <bitRange>[1:0]</bitRange>
            </field>
            <field>
              <name>EXTI5</name>
              <bitRange>[5:4]</bitRange>
            </field>
            <field>
              <name>EXTI6</name>
              <bitRange>[9:8]</bitRange>
            </field>
            <field>
              <name>EXTI7</name>
              <bitRange>[13:12]</bitRange>
            </field>
          </fields>
        </register>
        <register>
          <name>EXTICR3</name>
          <addressOffset>0x1C</addressOffset>
          <fields>
            <field>
              <name>EXTI8</name>
              <bitRange>[1:0]</bitRange>
            </field>
            <field>
              <name>EXTI9</name>
              <bitRange>[5:4]</bitRange>
            </field>
            <field>
              <name>EXTI10</name>
              <bitRange>[9:8]</bitRange>
            </field>
            <field>
              <name>EXTI11</name>
              <bitRange>[13:12]</bitRange>
            </field>
          </fields>
        </register>
        <register>
          <name>EXTICR4</name>
          <addressOffset>0x20</addressOffset>
          <fields>
            <field>
              <name>EXTI12</name>
              <bitRange>[1:0]</bitRange>
            </field>
            <field>
              <name>EXTI13</name>
              <bitRange>[5:4]</bitRange>
            </field>
            <field>
              <name>EXTI14</name>
              <bitRange>[9:8]</bitRange>
            </field>
            <field>
              <name>EXTI15</name>
              <bitRange>[13:12]</bitRange>
            </field>
          </fields>
        </register>
        <register>
          <name>PAENS</name>
          <addressOffset>0x24</addressOffset>
          <fields>
            <field>
              <name>PA_ENS</name>
              <bitRange>[15:0]</bitRange>
            </field>
          </fields>
        </register>
        <register>
          <name>PBENS</name>
          <addressOffset>0x28</addressOffset>
          <fields>
            <field>
              <name>PB_ENS</name>
              <bitRange>[15:0]</bitRange>
            </field>
          </fields>
        </register>
        <register>
          <name>PCENS</name>
          <addressOffset>0x2C</addressOffset>
          <fields>
            <field>
              <name>PC_ENS</name>
              <bitRange>[15:0]</bitRange>
            </field>
          </fields>
        </register>
        <register>
          <name>PDENS</name>
          <addressOffset>0x30</addressOffset>
          <fields>
            <field>
              <name>PD_ENS</name>
              <bitRange>[11:0]</bitRange>
            </field>
          </fields>
        </register>
      </registers>
    </peripheral>
    <peripheral>
      <name>TIM1</name>
      <groupName>TIM</groupName>
      <baseAddress>0x40012C00</baseAddress>
      <addressBlock>
        <offset>0x0</offset>
        <size>0x3F0</size>
        <usage>registers</usage>
      </addressBlock>
      <interrupt>
        <name>TIM1_BRK</name>
        <description>TIM1 Break Interrupt</description>
        <value>21</value>
      </interrupt>
      <interrupt>
        <name>TIM1_UP</name>
        <description>TIM1 Up Interrupt</description>
        <value>22</value>
      </interrupt>
      <interrupt>
        <name>TIM1_TRG_COM</name>
        <description>TIM1 Trigger and Communication Interrupt</description>
        <value>23</value>
      </interrupt>
      <interrupt>
        <name>TIM1_CC</name>
        <description>TIM1 Capture and Comparison Interrupt</description>
        <value>24</value>
      </interrupt>
      <registers>
        <register>
          <name>CR1</name>
          <addressOffset>0x0</addressOffset>
          <fields>
            <field>
              <name>CEN</name>
              <bitRange>[0:0]</bitRange>
            </field>
            <field>
              <name>UDIS</name>
              <bitRange>[1:1]</bitRange>
            </field>
            <field>
              <name>URS</name>
              <bitRange>[2:2]</bitRange>
            </field>
            <field>
              <name>OPM</name>
              <bitRange>[3:3]</bitRange>
            </field>
            <field>
              <name>DIR</name>
              <bitRange>[4:4]</bitRange>
            </field>
            <field>
              <name>CMS</name>
              <bitRange>[6:5]</bitRange>
            </field>
            <field>
              <name>ARPE</name>
              <bitRange>[7:7]</bitRange>
            </field>
            <field>
              <name>CKD</name>
              <bitRange>[9:8]</bitRange>
            </field>
            <field>
              <name>UIFREMAP</name>
              <bitRange>[11:11]</bitRange>
            </field>
            <field>
              <name>DITHEN</name>
              <bitRange>[12:12]</bitRange>
            </field>
          </fields>
        </register>
        <register>
          <name>CR2</name>
          <addressOffset>0x4</addressOffset>
          <fields>
            <field>
              <name>CCPC</name>
              <bitRange>[0:0]</bitRange>
            </field>
            <field>
              <name>CCUS</name>
              <bitRange>[2:2]</bitRange>
            </field>
            <field>
              <name>CCDS</name>
              <bitRange>[3:3]</bitRange>
            </field>
            <field>
              <name>MMS_L</name>
              <bitRange>[6:4]</bitRange>
              <access>read-only</access>
            </field>
            <field>
              <name>TI1S</name>
              <bitRange>[7:7]</bitRange>
            </field>
            <field>
              <name>OIS1</name>
              <bitRange>[8:8]</bitRange>
            </field>
            <field>
              <name>OIS1N</name>
              <bitRange>[9:9]</bitRange>
            </field>
            <field>
              <name>OIS2</name>
              <bitRange>[10:10]</bitRange>
            </field>
            <field>
              <name>OIS2N</name>
              <bitRange>[11:11]</bitRange>
            </field>
            <field>
              <name>OIS3</name>
              <bitRange>[12:12]</bitRange>
            </field>
            <field>
              <name>OIS3N</name>
              <bitRange>[13:13]</bitRange>
            </field>
            <field>
              <name>OIS4</name>
              <bitRange>[14:14]</bitRange>
            </field>
            <field>
              <name>OIS4N</name>
              <bitRange>[15:15]</bitRange>
            </field>
            <field>
              <name>OIS5</name>
              <bitRange>[16:16]</bitRange>
            </field>
            <field>
              <name>OIS6</name>
              <bitRange>[18:18]</bitRange>
            </field>
            <field>
              <name>MMS2</name>
              <bitRange>[23:20]</bitRange>
            </field>
            <field>
              <name>MMS_H</name>
              <bitRange>[25:25]</bitRange>
            </field>
          </fields>
        </register>
        <register>
          <name>SMCR</name>
          <addressOffset>0x8</addressOffset>
          <fields>
            <field>
              <name>SMS_L</name>
              <bitRange>[2:0]</bitRange>
            </field>
            <field>
              <name>OCCS</name>
              <bitRange>[3:3]</bitRange>
            </field>
            <field>
              <name>TS_L</name>
              <bitRange>[6:4]</bitRange>
            </field>
            <field>
              <name>MSM</name>
              <bitRange>[7:7]</bitRange>
            </field>
            <field>
              <name>ETF</name>
              <bitRange>[11:8]</bitRange>
            </field>
            <field>
              <name>ETPS</name>
              <bitRange>[13:12]</bitRange>
            </field>
            <field>
              <name>ECE</name>
              <bitRange>[14:14]</bitRange>
            </field>
            <field>
              <name>ETP</name>
              <bitRange>[15:15]</bitRange>
            </field>
            <field>
              <name>SMS_H</name>
              <bitRange>[16:16]</bitRange>
            </field>
            <field>
              <name>TS_H</name>
              <bitRange>[21:20]</bitRange>
            </field>
            <field>
              <name>SMSPE</name>
              <bitRange>[24:24]</bitRange>
            </field>
            <field>
              <name>SMSPS</name>
              <bitRange>[25:25]</bitRange>
            </field>
          </fields>
        </register>
        <register>
          <name>DIER</name>
          <addressOffset>0xC</addressOffset>
          <fields>
            <field>
              <name>UIE</name>
              <bitRange>[0:0]</bitRange>
            </field>
            <field>
              <name>CC1IE</name>
              <bitRange>[1:1]</bitRange>
            </field>
            <field>
              <name>CC2IE</name>
              <bitRange>[2:2]</bitRange>
            </field>
            <field>
              <name>CC3IE</name>
              <bitRange>[3:3]</bitRange>
            </field>
            <field>
              <name>CC4IE</name>
              <bitRange>[4:4]</bitRange>
            </field>
            <field>
              <name>COMIE</name>
              <bitRange>[5:5]</bitRange>
            </field>
            <field>
              <name>TIE</name>
              <bitRange>[6:6]</bitRange>
            </field>
            <field>
              <name>BIE</name>
              <bitRange>[7:7]</bitRange>
            </field>
            <field>
              <name>UDE</name>
              <bitRange>[8:8]</bitRange>
            </field>
            <field>
              <name>CC1DE</name>
              <bitRange>[9:9]</bitRange>
            </field>
            <field>
              <name>CC2DE</name>
              <bitRange>[10:10]</bitRange>
            </field>
            <field>
              <name>CC3DE</name>
              <bitRange>[11:11]</bitRange>
            </field>
            <field>
              <name>CC4DE</name>
              <bitRange>[12:12]</bitRange>
            </field>
            <field>
              <name>COMDE</name>
              <bitRange>[13:13]</bitRange>
            </field>
            <field>
              <name>TDE</name>
              <bitRange>[14:14]</bitRange>
            </field>
            <field>
              <name>IDXIE</name>
              <bitRange>[20:20]</bitRange>
            </field>
            <field>
              <name>DIRIE</name>
              <bitRange>[21:21]</bitRange>
            </field>
            <field>
              <name>IERRIE</name>
              <bitRange>[22:22]</bitRange>
            </field>
            <field>
              <name>TERRIE</name>
              <bitRange>[23:23]</bitRange>
            </field>
          </fields>
        </register>
        <register>
          <name>SR</name>
          <addressOffset>0x10</addressOffset>
          <fields>
            <field>
              <name>UIF</name>
              <bitRange>[0:0]</bitRange>
            </field>
            <field>
              <name>CC1IF</name>
              <bitRange>[1:1]</bitRange>
            </field>
            <field>
              <name>CC2IF</name>
              <bitRange>[2:2]</bitRange>
            </field>
            <field>
              <name>CC3IF</name>
              <bitRange>[3:3]</bitRange>
            </field>
            <field>
              <name>CC4IF</name>
              <bitRange>[4:4]</bitRange>
            </field>
            <field>
              <name>COMIF</name>
              <bitRange>[5:5]</bitRange>
            </field>
            <field>
              <name>TIF</name>
              <bitRange>[6:6]</bitRange>
            </field>
            <field>
              <name>BIF</name>
              <bitRange>[7:7]</bitRange>
            </field>
            <field>
              <name>B2IF</name>
              <bitRange>[8:8]</bitRange>
            </field>
            <field>
              <name>CC1OF</name>
              <bitRange>[9:9]</bitRange>
            </field>
            <field>
              <name>CC2OF</name>
              <bitRange>[10:10]</bitRange>
            </field>
            <field>
              <name>CC3OF</name>
              <bitRange>[11:11]</bitRange>
            </field>
            <field>
              <name>CC4OF</name>
              <bitRange>[12:12]</bitRange>
            </field>
            <field>
              <name>SBIF</name>
              <bitRange>[13:13]</bitRange>
            </field>
            <field>
              <name>CC5IF</name>
              <bitRange>[16:16]</bitRange>
            </field>
            <field>
              <name>CC6IF</name>
              <bitRange>[17:17]</bitRange>
            </field>
            <field>
              <name>IC1IR</name>
              <bitRange>[18:18]</bitRange>
            </field>
            <field>
              <name>IC2IR</name>
              <bitRange>[19:19]</bitRange>
            </field>
            <field>
              <name>IDXF</name>
              <bitRange>[20:20]</bitRange>
            </field>
            <field>
              <name>DIRF</name>
              <bitRange>[21:21]</bitRange>
            </field>
            <field>
              <name>IERRF</name>
              <bitRange>[22:22]</bitRange>
            </field>
            <field>
              <name>TERRF</name>
              <bitRange>[23:23]</bitRange>
            </field>
            <field>
              <name>IC3IR</name>
              <bitRange>[24:24]</bitRange>
            </field>
            <field>
              <name>IC4IR</name>
              <bitRange>[25:25]</bitRange>
            </field>
            <field>
              <name>IC1IF</name>
              <bitRange>[26:26]</bitRange>
            </field>
            <field>
              <name>IC2IF</name>
              <bitRange>[27:27]</bitRange>
            </field>
            <field>
              <name>IC3IF</name>
              <bitRange>[28:28]</bitRange>
            </field>
            <field>
              <name>IC4IF</name>
              <bitRange>[29:29]</bitRange>
            </field>
          </fields>
        </register>
        <register>
          <name>EGR</name>
          <addressOffset>0x14</addressOffset>
          <fields>
            <field>
              <name>UG</name>
              <bitRange>[0:0]</bitRange>
              <access>read-only</access>
            </field>
            <field>
              <name>CC1G</name>
              <bitRange>[1:1]</bitRange>
              <access>read-only</access>
            </field>
            <field>
              <name>CC2G</name>
              <bitRange>[2:2]</bitRange>
              <access>read-only</access>
            </field>
            <field>
              <name>CC3G</name>
              <bitRange>[3:3]</bitRange>
              <access>read-only</access>
            </field>
            <field>
              <name>CC4G</name>
              <bitRange>[4:4]</bitRange>
              <access>read-only</access>
            </field>
            <field>
              <name>COMG</name>
              <bitRange>[5:5]</bitRange>
              <access>read-only</access>
            </field>
            <field>
              <name>TG</name>
              <bitRange>[6:6]</bitRange>
              <access>read-only</access>
            </field>
            <field>
              <name>BG</name>
              <bitRange>[7:7]</bitRange>
              <access>read-only</access>
            </field>
            <field>
              <name>B2G</name>
              <bitRange>[8:8]</bitRange>
              <access>read-only</access>
            </field>
          </fields>
        </register>
        <register>
          <name>CCMR1_OUTPUT</name>
          <addressOffset>0x18</addressOffset>
          <fields>
            <field>
              <name>CC1S</name>
              <bitRange>[1:0]</bitRange>
            </field>
            <field>
              <name>OC1FE</name>
              <bitRange>[2:2]</bitRange>
            </field>
            <field>
              <name>OC1PE</name>
              <bitRange>[3:3]</bitRange>
            </field>
            <field>
              <name>OC1M_L</name>
              <bitRange>[6:4]</bitRange>
            </field>
            <field>
              <name>OC1CE</name>
              <bitRange>[7:7]</bitRange>
            </field>
            <field>
              <name>CC2S</name>
              <bitRange>[9:8]</bitRange>
            </field>
            <field>
              <name>OC2FE</name>
              <bitRange>[10:10]</bitRange>
            </field>
            <field>
              <name>OC2PE</name>
              <bitRange>[11:11]</bitRange>
            </field>
            <field>
              <name>OC2M_L</name>
              <bitRange>[14:12]</bitRange>
            </field>
            <field>
              <name>OC2CE</name>
              <bitRange>[15:15]</bitRange>
            </field>
            <field>
              <name>OC1M_H</name>
              <bitRange>[16:16]</bitRange>
            </field>
            <field>
              <name>OC2M_H</name>
              <bitRange>[24:24]</bitRange>
            </field>
          </fields>
        </register>
        <register>
          <name>CCMR1_INPUT</name>
          <alternateRegister>CCMR1_OUTPUT</alternateRegister>
          <addressOffset>0x18</addressOffset>
          <fields>
            <field>
              <name>CC1S</name>
              <bitRange>[1:0]</bitRange>
            </field>
            <field>
              <name>IC1PSC</name>
              <bitRange>[3:2]</bitRange>
            </field>
            <field>
              <name>IC1F</name>
              <bitRange>[7:4]</bitRange>
            </field>
            <field>
              <name>CC2S</name>
              <bitRange>[9:8]</bitRange>
            </field>
            <field>
              <name>IC2PSC</name>
              <bitRange>[11:10]</bitRange>
            </field>
            <field>
              <name>IC2F</name>
              <bitRange>[15:12]</bitRange>
            </field>
          </fields>
        </register>
        <register>
          <name>CCMR2_OUTPUT</name>
          <addressOffset>0x1C</addressOffset>
          <fields>
            <field>
              <name>CC3S</name>
              <bitRange>[1:0]</bitRange>
            </field>
            <field>
              <name>OC3FE</name>
              <bitRange>[2:2]</bitRange>
            </field>
            <field>
              <name>OC3PE</name>
              <bitRange>[3:3]</bitRange>
            </field>
            <field>
              <name>OC3M_L</name>
              <bitRange>[6:4]</bitRange>
            </field>
            <field>
              <name>OC3CE</name>
              <bitRange>[7:7]</bitRange>
            </field>
            <field>
              <name>CC4S</name>
              <bitRange>[9:8]</bitRange>
            </field>
            <field>
              <name>OC4FE</name>
              <bitRange>[10:10]</bitRange>
            </field>
            <field>
              <name>OC4PE</name>
              <bitRange>[11:11]</bitRange>
            </field>
            <field>
              <name>OC4M_L</name>
              <bitRange>[14:12]</bitRange>
            </field>
            <field>
              <name>OC4CE</name>
              <bitRange>[15:15]</bitRange>
            </field>
            <field>
              <name>OC3M_H</name>
              <bitRange>[16:16]</bitRange>
            </field>
            <field>
              <name>OC4M_H</name>
              <bitRange>[24:24]</bitRange>
            </field>
          </fields>
        </register>
        <register>
          <name>CCMR2_INPUT</name>
          <alternateRegister>CCMR2_OUTPUT</alternateRegister>
          <addressOffset>0x1C</addressOffset>
          <fields>
            <field>
              <name>CC3S</name>
              <bitRange>[1:0]</bitRange>
            </field>
            <field>
              <name>IC3PSC</name>
              <bitRange>[3:2]</bitRange>
            </field>
            <field>
              <name>IC3F</name>
              <bitRange>[7:4]</bitRange>
            </field>
            <field>
              <name>CC4S</name>
              <bitRange>[9:8]</bitRange>
            </field>
            <field>
              <name>IC4PSC</name>
              <bitRange>[11:10]</bitRange>
            </field>
            <field>
              <name>IC4F</name>
              <bitRange>[15:12]</bitRange>
            </field>
          </fields>
        </register>
        <register>
          <name>TIMXCCER</name>
          <addressOffset>0x20</addressOffset>
          <fields>
            <field>
              <name>CC1E</name>
              <bitRange>[0:0]</bitRange>
            </field>
            <field>
              <name>CC1P</name>
              <bitRange>[1:1]</bitRange>
            </field>
            <field>
              <name>CC1NE</name>
              <bitRange>[2:2]</bitRange>
            </field>
            <field>
              <name>CC1NP</name>
              <bitRange>[3:3]</bitRange>
            </field>
            <field>
              <name>CC2E</name>
              <bitRange>[4:4]</bitRange>
            </field>
            <field>
              <name>CC2P</name>
              <bitRange>[5:5]</bitRange>
            </field>
            <field>
              <name>CC2NE</name>
              <bitRange>[6:6]</bitRange>
            </field>
            <field>
              <name>CC2NP</name>
              <bitRange>[7:7]</bitRange>
            </field>
            <field>
              <name>CC3E</name>
              <bitRange>[8:8]</bitRange>
            </field>
            <field>
              <name>CC3P</name>
              <bitRange>[9:9]</bitRange>
            </field>
            <field>
              <name>CC3NE</name>
              <bitRange>[10:10]</bitRange>
            </field>
            <field>
              <name>CC3NP</name>
              <bitRange>[11:11]</bitRange>
            </field>
            <field>
              <name>CC4E</name>
              <bitRange>[12:12]</bitRange>
            </field>
            <field>
              <name>CC4P</name>
              <bitRange>[13:13]</bitRange>
            </field>
            <field>
              <name>CC4NE</name>
              <bitRange>[14:14]</bitRange>
            </field>
            <field>
              <name>CC4NP</name>
              <bitRange>[15:15]</bitRange>
            </field>
            <field>
              <name>CC5E</name>
              <bitRange>[16:16]</bitRange>
            </field>
            <field>
              <name>CC5P</name>
              <bitRange>[17:17]</bitRange>
            </field>
            <field>
              <name>CC6E</name>
              <bitRange>[20:20]</bitRange>
            </field>
            <field>
              <name>CC6P</name>
              <bitRange>[21:21]</bitRange>
            </field>
          </fields>
        </register>
        <register>
          <name>CNT</name>
          <addressOffset>0x24</addressOffset>
          <fields>
            <field>
              <name>CNT</name>
              <bitRange>[30:0]</bitRange>
            </field>
            <field>
              <name>UIFCPY</name>
              <bitRange>[31:31]</bitRange>
              <access>read-only</access>
            </field>
          </fields>
        </register>
        <register>
          <name>PSC</name>
          <addressOffset>0x28</addressOffset>
          <fields>
            <field>
              <name>PSC</name>
              <bitRange>[15:0]</bitRange>
            </field>
          </fields>
        </register>
        <register>
          <name>ARR</name>
          <addressOffset>0x2C</addressOffset>
          <fields>
            <field>
              <name>ARR</name>
              <bitRange>[31:0]</bitRange>
            </field>
          </fields>
        </register>
        <register>
          <name>RCR</name>
          <addressOffset>0x30</addressOffset>
          <fields>
            <field>
              <name>REP</name>
              <bitRange>[15:0]</bitRange>
            </field>
          </fields>
        </register>
        <register>
          <name>CCR1</name>
          <addressOffset>0x34</addressOffset>
          <fields>
            <field>
              <name>CCR1</name>
              <bitRange>[31:0]</bitRange>
            </field>
          </fields>
        </register>
        <register>
          <name>CCR2</name>
          <addressOffset>0x38</addressOffset>
          <fields>
            <field>
              <name>CCR2</name>
              <bitRange>[31:0]</bitRange>
            </field>
          </fields>
        </register>
        <register>
          <name>CCR3</name>
          <addressOffset>0x3C</addressOffset>
          <fields>
            <field>
              <name>CCR3</name>
              <bitRange>[31:0]</bitRange>
            </field>
          </fields>
        </register>
        <register>
          <name>CCR4</name>
          <addressOffset>0x40</addressOffset>
          <fields>
            <field>
              <name>CCR4</name>
              <bitRange>[31:0]</bitRange>
            </field>
          </fields>
        </register>
        <register>
          <name>BDTR</name>
          <addressOffset>0x44</addressOffset>
          <fields>
            <field>
              <name>DTG</name>
              <bitRange>[7:0]</bitRange>
            </field>
            <field>
              <name>LOCK</name>
              <bitRange>[9:8]</bitRange>
            </field>
            <field>
              <name>OSSI</name>
              <bitRange>[10:10]</bitRange>
            </field>
            <field>
              <name>OSSR</name>
              <bitRange>[11:11]</bitRange>
            </field>
            <field>
              <name>BKE</name>
              <bitRange>[12:12]</bitRange>
            </field>
            <field>
              <name>BKP</name>
              <bitRange>[13:13]</bitRange>
            </field>
            <field>
              <name>AOE</name>
              <bitRange>[14:14]</bitRange>
            </field>
            <field>
              <name>MOE</name>
              <bitRange>[15:15]</bitRange>
            </field>
            <field>
              <name>BKF</name>
              <bitRange>[19:16]</bitRange>
            </field>
            <field>
              <name>BK2F</name>
              <bitRange>[23:20]</bitRange>
            </field>
            <field>
              <name>BK2E</name>
              <bitRange>[24:24]</bitRange>
            </field>
            <field>
              <name>BK2P</name>
              <bitRange>[25:25]</bitRange>
            </field>
            <field>
              <name>BKDSRM</name>
              <bitRange>[26:26]</bitRange>
            </field>
            <field>
              <name>BK2DSRM</name>
              <bitRange>[27:27]</bitRange>
            </field>
            <field>
              <name>BKBID</name>
              <bitRange>[28:28]</bitRange>
            </field>
            <field>
              <name>BK2BID</name>
              <bitRange>[29:29]</bitRange>
            </field>
          </fields>
        </register>
        <register>
          <name>CCR5</name>
          <addressOffset>0x48</addressOffset>
          <fields>
            <field>
              <name>CCR5</name>
              <bitRange>[19:0]</bitRange>
            </field>
            <field>
              <name>GC5C1</name>
              <bitRange>[29:29]</bitRange>
            </field>
            <field>
              <name>GC5C2</name>
              <bitRange>[30:30]</bitRange>
            </field>
            <field>
              <name>GC5C3</name>
              <bitRange>[31:31]</bitRange>
            </field>
          </fields>
        </register>
        <register>
          <name>CCR6</name>
          <addressOffset>0x4C</addressOffset>
          <fields>
            <field>
              <name>CCR6</name>
              <bitRange>[19:0]</bitRange>
            </field>
          </fields>
        </register>
        <register>
          <name>CCMR3</name>
          <addressOffset>0x50</addressOffset>
          <fields>
            <field>
              <name>OC5FE</name>
              <bitRange>[2:2]</bitRange>
            </field>
            <field>
              <name>OC5PE</name>
              <bitRange>[3:3]</bitRange>
            </field>
            <field>
              <name>OC5M_L</name>
              <bitRange>[6:4]</bitRange>
            </field>
            <field>
              <name>OC5CE</name>
              <bitRange>[7:7]</bitRange>
            </field>
            <field>
              <name>OC6FE</name>
              <bitRange>[10:10]</bitRange>
            </field>
            <field>
              <name>OC6PE</name>
              <bitRange>[11:11]</bitRange>
            </field>
            <field>
              <name>OC6M_L</name>
              <bitRange>[14:12]</bitRange>
            </field>
            <field>
              <name>OC6CE</name>
              <bitRange>[15:15]</bitRange>
            </field>
            <field>
              <name>OC5M_H</name>
              <bitRange>[16:16]</bitRange>
            </field>
            <field>
              <name>OC6M_H</name>
              <bitRange>[24:24]</bitRange>
            </field>
          </fields>
        </register>
        <register>
          <name>DTR2</name>
          <addressOffset>0x54</addressOffset>
          <fields>
            <field>
              <name>DTGF</name>
              <bitRange>[7:0]</bitRange>
            </field>
            <field>
              <name>DTAE</name>
              <bitRange>[16:16]</bitRange>
            </field>
            <field>
              <name>DTPE</name>
              <bitRange>[17:17]</bitRange>
            </field>
          </fields>
        </register>
        <register>
          <name>ECR</name>
          <addressOffset>0x58</addressOffset>
          <fields>
            <field>
              <name>IE</name>
              <bitRange>[0:0]</bitRange>
            </field>
            <field>
              <name>IDIR</name>
              <bitRange>[2:1]</bitRange>
            </field>
            <field>
              <name>FIDX</name>
              <bitRange>[5:5]</bitRange>
            </field>
            <field>
              <name>IPOS</name>
              <bitRange>[7:6]</bitRange>
            </field>
            <field>
              <name>PW</name>
              <bitRange>[23:16]</bitRange>
            </field>
            <field>
              <name>PWPRSC</name>
              <bitRange>[26:24]</bitRange>
            </field>
          </fields>
        </register>
        <register>
          <name>TISEL</name>
          <addressOffset>0x5C</addressOffset>
          <fields>
            <field>
              <name>TI1SEL</name>
              <bitRange>[3:0]</bitRange>
            </field>
            <field>
              <name>TI2SEL</name>
              <bitRange>[11:8]</bitRange>
            </field>
            <field>
              <name>TI3SEL</name>
              <bitRange>[19:16]</bitRange>
            </field>
            <field>
              <name>TI4SEL</name>
              <bitRange>[27:24]</bitRange>
            </field>
          </fields>
        </register>
        <register>
          <name>AF1</name>
          <addressOffset>0x60</addressOffset>
          <fields>
            <field>
              <name>BKINE</name>
              <bitRange>[0:0]</bitRange>
            </field>
            <field>
              <name>BKCMP1E</name>
              <bitRange>[1:1]</bitRange>
            </field>
            <field>
              <name>BKCMP2E</name>
              <bitRange>[2:2]</bitRange>
            </field>
            <field>
              <name>BKCMP3E</name>
              <bitRange>[3:3]</bitRange>
            </field>
            <field>
              <name>BKCMP4E</name>
              <bitRange>[4:4]</bitRange>
            </field>
            <field>
              <name>BKINP</name>
              <bitRange>[9:9]</bitRange>
            </field>
            <field>
              <name>BKCMP1P</name>
              <bitRange>[10:10]</bitRange>
            </field>
            <field>
              <name>BKCMP2P</name>
              <bitRange>[11:11]</bitRange>
            </field>
            <field>
              <name>BKCMP3P</name>
              <bitRange>[12:12]</bitRange>
            </field>
            <field>
              <name>BKCMP4P</name>
              <bitRange>[13:13]</bitRange>
            </field>
            <field>
              <name>ETRSEL</name>
              <bitRange>[17:14]</bitRange>
            </field>
            <field>
              <name>INTR_SEL</name>
              <bitRange>[19:18]</bitRange>
            </field>
            <field>
              <name>PWM_PHS_EN</name>
              <bitRange>[20:20]</bitRange>
            </field>
          </fields>
        </register>
        <register>
          <name>AF2</name>
          <addressOffset>0x64</addressOffset>
          <fields>
            <field>
              <name>BK2INE</name>
              <bitRange>[0:0]</bitRange>
            </field>
            <field>
              <name>BK2CMP1E</name>
              <bitRange>[1:1]</bitRange>
            </field>
            <field>
              <name>BK2CMP2E</name>
              <bitRange>[2:2]</bitRange>
            </field>
            <field>
              <name>BK2CMP3E</name>
              <bitRange>[3:3]</bitRange>
            </field>
            <field>
              <name>BK2CMP4E</name>
              <bitRange>[4:4]</bitRange>
            </field>
            <field>
              <name>BK2INP</name>
              <bitRange>[9:9]</bitRange>
            </field>
            <field>
              <name>BK2CMP1P</name>
              <bitRange>[10:10]</bitRange>
            </field>
            <field>
              <name>BK2CMP2P</name>
              <bitRange>[11:11]</bitRange>
            </field>
            <field>
              <name>BK2CMP3P</name>
              <bitRange>[12:12]</bitRange>
            </field>
            <field>
              <name>BK2CMP4P</name>
              <bitRange>[13:13]</bitRange>
            </field>
            <field>
              <name>OCRSEL</name>
              <bitRange>[18:16]</bitRange>
            </field>
          </fields>
        </register>
        <register>
          <name>OR1</name>
          <addressOffset>0x68</addressOffset>
          <fields>
            <field>
              <name>BID_BG_EXTEND_DIS</name>
              <bitRange>[30:30]</bitRange>
            </field>
            <field>
              <name>DG_MSK_DIS</name>
              <bitRange>[31:31]</bitRange>
            </field>
          </fields>
        </register>
        <register>
          <name>MTADCCR</name>
          <addressOffset>0x6C</addressOffset>
          <fields>
            <field>
              <name>MTZEROE</name>
              <bitRange>[0:0]</bitRange>
            </field>
            <field>
              <name>MTARRE</name>
              <bitRange>[1:1]</bitRange>
            </field>
            <field>
              <name>UMTCCR1E</name>
              <bitRange>[2:2]</bitRange>
            </field>
            <field>
              <name>UMTCCR1HE</name>
              <bitRange>[3:3]</bitRange>
            </field>
            <field>
              <name>UMTCCR2E</name>
              <bitRange>[4:4]</bitRange>
            </field>
            <field>
              <name>UMTCCR2HE</name>
              <bitRange>[5:5]</bitRange>
            </field>
            <field>
              <name>UMTCCR3E</name>
              <bitRange>[6:6]</bitRange>
            </field>
            <field>
              <name>UMTCCR3HE</name>
              <bitRange>[7:7]</bitRange>
            </field>
            <field>
              <name>UMTCCR4E</name>
              <bitRange>[8:8]</bitRange>
            </field>
            <field>
              <name>UMTCCR4HE</name>
              <bitRange>[9:9]</bitRange>
            </field>
            <field>
              <name>DMTCCR1E</name>
              <bitRange>[10:10]</bitRange>
            </field>
            <field>
              <name>DMTCCR1HE</name>
              <bitRange>[11:11]</bitRange>
            </field>
            <field>
              <name>DMTCCR2E</name>
              <bitRange>[12:12]</bitRange>
            </field>
            <field>
              <name>DMTCCR2HE</name>
              <bitRange>[13:13]</bitRange>
            </field>
            <field>
              <name>DMTCCR3E</name>
              <bitRange>[14:14]</bitRange>
            </field>
            <field>
              <name>DMTCCR3HE</name>
              <bitRange>[15:15]</bitRange>
            </field>
            <field>
              <name>DMTCCR4E</name>
              <bitRange>[16:16]</bitRange>
            </field>
            <field>
              <name>DMTCCR4HE</name>
              <bitRange>[17:17]</bitRange>
            </field>
            <field>
              <name>MTADCE</name>
              <bitRange>[18:18]</bitRange>
            </field>
          </fields>
        </register>
        <register>
          <name>DCR</name>
          <addressOffset>0x3DC</addressOffset>
          <fields>
            <field>
              <name>DBA</name>
              <bitRange>[4:0]</bitRange>
            </field>
            <field>
              <name>DBL</name>
              <bitRange>[12:8]</bitRange>
            </field>
          </fields>
        </register>
        <register>
          <name>DMAR</name>
          <addressOffset>0x3E0</addressOffset>
          <fields>
            <field>
              <name>DMAB</name>
              <bitRange>[31:0]</bitRange>
            </field>
          </fields>
        </register>
      </registers>
    </peripheral>
    <peripheral>
      <name>TIM2</name>
      <groupName>TIM</groupName>
      <baseAddress>0x40000000</baseAddress>
      <addressBlock>
        <offset>0x0</offset>
        <size>0x3F0</size>
        <usage>registers</usage>
      </addressBlock>
      <interrupt>
        <name>TIM2</name>
        <description>TIM2 global Interrupt</description>
        <value>25</value>
      </interrupt>
      <registers>
        <register>
          <name>CR1</name>
          <addressOffset>0x0</addressOffset>
          <fields>
            <field>
              <name>CEN</name>
              <bitRange>[0:0]</bitRange>
            </field>
            <field>
              <name>UDIS</name>
              <bitRange>[1:1]</bitRange>
            </field>
            <field>
              <name>URS</name>
              <bitRange>[2:2]</bitRange>
            </field>
            <field>
              <name>OPM</name>
              <bitRange>[3:3]</bitRange>
            </field>
            <field>
              <name>DIR</name>
              <bitRange>[4:4]</bitRange>
            </field>
            <field>
              <name>CMS</name>
              <bitRange>[6:5]</bitRange>
            </field>
            <field>
              <name>ARPE</name>
              <bitRange>[7:7]</bitRange>
            </field>
            <field>
              <name>CKD</name>
              <bitRange>[9:8]</bitRange>
            </field>
          </fields>
        </register>
        <register>
          <name>CR2</name>
          <addressOffset>0x4</addressOffset>
          <fields>
            <field>
              <name>CCPC</name>
              <bitRange>[0:0]</bitRange>
            </field>
            <field>
              <name>CCUS</name>
              <bitRange>[2:2]</bitRange>
            </field>
            <field>
              <name>CCDS</name>
              <bitRange>[3:3]</bitRange>
            </field>
            <field>
              <name>MMS_L</name>
              <bitRange>[6:4]</bitRange>
              <access>read-only</access>
            </field>
            <field>
              <name>TI1S</name>
              <bitRange>[7:7]</bitRange>
            </field>
            <field>
              <name>OIS1</name>
              <bitRange>[8:8]</bitRange>
            </field>
            <field>
              <name>OIS1N</name>
              <bitRange>[9:9]</bitRange>
            </field>
            <field>
              <name>OIS2</name>
              <bitRange>[10:10]</bitRange>
            </field>
            <field>
              <name>OIS2N</name>
              <bitRange>[11:11]</bitRange>
            </field>
            <field>
              <name>OIS3</name>
              <bitRange>[12:12]</bitRange>
            </field>
            <field>
              <name>OIS3N</name>
              <bitRange>[13:13]</bitRange>
            </field>
            <field>
              <name>OIS4</name>
              <bitRange>[14:14]</bitRange>
            </field>
            <field>
              <name>OIS4N</name>
              <bitRange>[15:15]</bitRange>
            </field>
            <field>
              <name>MMS2</name>
              <bitRange>[23:20]</bitRange>
            </field>
            <field>
              <name>MMS_H</name>
              <bitRange>[25:25]</bitRange>
            </field>
          </fields>
        </register>
        <register>
          <name>SMCR</name>
          <addressOffset>0x8</addressOffset>
          <fields>
            <field>
              <name>SMS_L</name>
              <bitRange>[2:0]</bitRange>
            </field>
            <field>
              <name>OCCS</name>
              <bitRange>[3:3]</bitRange>
            </field>
            <field>
              <name>TS_L</name>
              <bitRange>[6:4]</bitRange>
            </field>
            <field>
              <name>MSM</name>
              <bitRange>[7:7]</bitRange>
            </field>
            <field>
              <name>ETF</name>
              <bitRange>[11:8]</bitRange>
            </field>
            <field>
              <name>ETPS</name>
              <bitRange>[13:12]</bitRange>
            </field>
            <field>
              <name>ECE</name>
              <bitRange>[14:14]</bitRange>
            </field>
            <field>
              <name>SMS_H</name>
              <bitRange>[16:16]</bitRange>
            </field>
            <field>
              <name>TS_H</name>
              <bitRange>[21:20]</bitRange>
            </field>
            <field>
              <name>SMSPE</name>
              <bitRange>[24:24]</bitRange>
            </field>
            <field>
              <name>SMSPS</name>
              <bitRange>[25:25]</bitRange>
            </field>
          </fields>
        </register>
        <register>
          <name>DIER</name>
          <addressOffset>0xC</addressOffset>
          <fields>
            <field>
              <name>UIE</name>
              <bitRange>[0:0]</bitRange>
            </field>
            <field>
              <name>CC1IE</name>
              <bitRange>[1:1]</bitRange>
            </field>
            <field>
              <name>CC2IE</name>
              <bitRange>[2:2]</bitRange>
            </field>
            <field>
              <name>CC3IE</name>
              <bitRange>[3:3]</bitRange>
            </field>
            <field>
              <name>CC4IE</name>
              <bitRange>[4:4]</bitRange>
            </field>
            <field>
              <name>TIE</name>
              <bitRange>[6:6]</bitRange>
            </field>
            <field>
              <name>BIE</name>
              <bitRange>[7:7]</bitRange>
            </field>
            <field>
              <name>UDE</name>
              <bitRange>[8:8]</bitRange>
            </field>
            <field>
              <name>CC1DE</name>
              <bitRange>[9:9]</bitRange>
            </field>
            <field>
              <name>CC2DE</name>
              <bitRange>[10:10]</bitRange>
            </field>
            <field>
              <name>CC3DE</name>
              <bitRange>[11:11]</bitRange>
            </field>
            <field>
              <name>CC4DE</name>
              <bitRange>[12:12]</bitRange>
            </field>
            <field>
              <name>COMDE</name>
              <bitRange>[13:13]</bitRange>
            </field>
            <field>
              <name>TDE</name>
              <bitRange>[14:14]</bitRange>
            </field>
          </fields>
        </register>
        <register>
          <name>SR</name>
          <addressOffset>0x10</addressOffset>
          <fields>
            <field>
              <name>UIF</name>
              <bitRange>[0:0]</bitRange>
            </field>
            <field>
              <name>CC1IF</name>
              <bitRange>[1:1]</bitRange>
            </field>
            <field>
              <name>CC2IF</name>
              <bitRange>[2:2]</bitRange>
            </field>
            <field>
              <name>CC3IF</name>
              <bitRange>[3:3]</bitRange>
            </field>
            <field>
              <name>CC4IF</name>
              <bitRange>[4:4]</bitRange>
            </field>
            <field>
              <name>COMIF</name>
              <bitRange>[5:5]</bitRange>
            </field>
            <field>
              <name>TIF</name>
              <bitRange>[6:6]</bitRange>
            </field>
            <field>
              <name>BIF</name>
              <bitRange>[7:7]</bitRange>
            </field>
            <field>
              <name>B2IF</name>
              <bitRange>[8:8]</bitRange>
            </field>
            <field>
              <name>CC1OF</name>
              <bitRange>[9:9]</bitRange>
            </field>
            <field>
              <name>CC2OF</name>
              <bitRange>[10:10]</bitRange>
            </field>
            <field>
              <name>CC3OF</name>
              <bitRange>[11:11]</bitRange>
            </field>
            <field>
              <name>CC4OF</name>
              <bitRange>[12:12]</bitRange>
            </field>
            <field>
              <name>IC1IR</name>
              <bitRange>[18:18]</bitRange>
            </field>
            <field>
              <name>IC2IR</name>
              <bitRange>[19:19]</bitRange>
            </field>
            <field>
              <name>IC3IR</name>
              <bitRange>[24:24]</bitRange>
            </field>
            <field>
              <name>IC4IR</name>
              <bitRange>[25:25]</bitRange>
            </field>
            <field>
              <name>IC1IF</name>
              <bitRange>[26:26]</bitRange>
            </field>
            <field>
              <name>IC2IF</name>
              <bitRange>[27:27]</bitRange>
            </field>
            <field>
              <name>IC3IF</name>
              <bitRange>[28:28]</bitRange>
            </field>
            <field>
              <name>IC4IF</name>
              <bitRange>[29:29]</bitRange>
            </field>
          </fields>
        </register>
        <register>
          <name>EGR</name>
          <addressOffset>0x14</addressOffset>
          <fields>
            <field>
              <name>UG</name>
              <bitRange>[0:0]</bitRange>
              <access>write-only</access>
            </field>
            <field>
              <name>CC1G</name>
              <bitRange>[1:1]</bitRange>
              <access>write-only</access>
            </field>
            <field>
              <name>CC2G</name>
              <bitRange>[2:2]</bitRange>
              <access>write-only</access>
            </field>
            <field>
              <name>CC3G</name>
              <bitRange>[3:3]</bitRange>
              <access>write-only</access>
            </field>
            <field>
              <name>CC4G</name>
              <bitRange>[4:4]</bitRange>
              <access>write-only</access>
            </field>
            <field>
              <name>COMG</name>
              <bitRange>[5:5]</bitRange>
              <access>read-only</access>
            </field>
            <field>
              <name>TG</name>
              <bitRange>[6:6]</bitRange>
              <access>write-only</access>
            </field>
            <field>
              <name>BG</name>
              <bitRange>[7:7]</bitRange>
              <access>read-only</access>
            </field>
            <field>
              <name>B2G</name>
              <bitRange>[8:8]</bitRange>
              <access>read-only</access>
            </field>
          </fields>
        </register>
        <register>
          <name>CCMR1_OUTPUT</name>
          <addressOffset>0x18</addressOffset>
          <fields>
            <field>
              <name>CC1S</name>
              <bitRange>[1:0]</bitRange>
            </field>
            <field>
              <name>OC1FE</name>
              <bitRange>[2:2]</bitRange>
            </field>
            <field>
              <name>OC1PE</name>
              <bitRange>[3:3]</bitRange>
            </field>
            <field>
              <name>OC1M_L</name>
              <bitRange>[6:4]</bitRange>
            </field>
            <field>
              <name>OC1CE</name>
              <bitRange>[7:7]</bitRange>
            </field>
            <field>
              <name>CC2S</name>
              <bitRange>[9:8]</bitRange>
            </field>
            <field>
              <name>OC2FE</name>
              <bitRange>[10:10]</bitRange>
            </field>
            <field>
              <name>OC2PE</name>
              <bitRange>[11:11]</bitRange>
            </field>
            <field>
              <name>OC2M_L</name>
              <bitRange>[14:12]</bitRange>
            </field>
            <field>
              <name>OC2CE</name>
              <bitRange>[15:15]</bitRange>
            </field>
            <field>
              <name>OC1M_H</name>
              <bitRange>[16:16]</bitRange>
            </field>
            <field>
              <name>OC2M_H</name>
              <bitRange>[24:24]</bitRange>
            </field>
          </fields>
        </register>
        <register>
          <name>CCMR1_INPUT</name>
          <alternateRegister>CCMR1_OUTPUT</alternateRegister>
          <addressOffset>0x18</addressOffset>
          <fields>
            <field>
              <name>CC1S</name>
              <bitRange>[1:0]</bitRange>
            </field>
            <field>
              <name>IC1PSC</name>
              <bitRange>[3:2]</bitRange>
            </field>
            <field>
              <name>IC1F</name>
              <bitRange>[7:4]</bitRange>
            </field>
            <field>
              <name>CC2S</name>
              <bitRange>[9:8]</bitRange>
            </field>
            <field>
              <name>IC2PSC</name>
              <bitRange>[11:10]</bitRange>
            </field>
            <field>
              <name>IC2F</name>
              <bitRange>[15:12]</bitRange>
            </field>
          </fields>
        </register>
        <register>
          <name>OUTPUT</name>
          <addressOffset>0x1C</addressOffset>
          <fields>
            <field>
              <name>CC3S</name>
              <bitRange>[1:0]</bitRange>
            </field>
            <field>
              <name>OC3FE</name>
              <bitRange>[2:2]</bitRange>
            </field>
            <field>
              <name>OC3PE</name>
              <bitRange>[3:3]</bitRange>
            </field>
            <field>
              <name>OC3M_L</name>
              <bitRange>[6:4]</bitRange>
            </field>
            <field>
              <name>OC3CE</name>
              <bitRange>[7:7]</bitRange>
            </field>
            <field>
              <name>CC4S</name>
              <bitRange>[9:8]</bitRange>
            </field>
            <field>
              <name>OC4FE</name>
              <bitRange>[10:10]</bitRange>
            </field>
            <field>
              <name>OC4PE</name>
              <bitRange>[11:11]</bitRange>
            </field>
            <field>
              <name>OC4M_L</name>
              <bitRange>[14:12]</bitRange>
            </field>
            <field>
              <name>OC4CE</name>
              <bitRange>[15:15]</bitRange>
            </field>
            <field>
              <name>OC3M_H</name>
              <bitRange>[16:16]</bitRange>
            </field>
            <field>
              <name>OC4M_H</name>
              <bitRange>[24:24]</bitRange>
            </field>
          </fields>
        </register>
        <register>
          <name>INPUT</name>
          <alternateRegister>OUTPUT</alternateRegister>
          <addressOffset>0x1C</addressOffset>
          <fields>
            <field>
              <name>CC3S</name>
              <bitRange>[1:0]</bitRange>
            </field>
            <field>
              <name>IC3PSC</name>
              <bitRange>[3:2]</bitRange>
            </field>
            <field>
              <name>IC3F</name>
              <bitRange>[7:4]</bitRange>
            </field>
            <field>
              <name>CC4S</name>
              <bitRange>[9:8]</bitRange>
            </field>
            <field>
              <name>IC4PSC</name>
              <bitRange>[11:10]</bitRange>
            </field>
            <field>
              <name>IC4F</name>
              <bitRange>[15:12]</bitRange>
            </field>
          </fields>
        </register>
        <register>
          <name>CCER</name>
          <addressOffset>0x20</addressOffset>
          <fields>
            <field>
              <name>CC1E</name>
              <bitRange>[0:0]</bitRange>
            </field>
            <field>
              <name>CC1P</name>
              <bitRange>[1:1]</bitRange>
            </field>
            <field>
              <name>CC1NE</name>
              <bitRange>[2:2]</bitRange>
            </field>
            <field>
              <name>CC1NP</name>
              <bitRange>[3:3]</bitRange>
            </field>
            <field>
              <name>CC2E</name>
              <bitRange>[4:4]</bitRange>
            </field>
            <field>
              <name>CC2P</name>
              <bitRange>[5:5]</bitRange>
            </field>
            <field>
              <name>CC2NE</name>
              <bitRange>[6:6]</bitRange>
            </field>
            <field>
              <name>CC2NP</name>
              <bitRange>[7:7]</bitRange>
            </field>
            <field>
              <name>CC3E</name>
              <bitRange>[8:8]</bitRange>
            </field>
            <field>
              <name>CC3P</name>
              <bitRange>[9:9]</bitRange>
            </field>
            <field>
              <name>CC3NE</name>
              <bitRange>[10:10]</bitRange>
            </field>
            <field>
              <name>CC3NP</name>
              <bitRange>[11:11]</bitRange>
            </field>
            <field>
              <name>CC4E</name>
              <bitRange>[12:12]</bitRange>
            </field>
            <field>
              <name>CC4P</name>
              <bitRange>[13:13]</bitRange>
            </field>
            <field>
              <name>CC4NE</name>
              <bitRange>[14:14]</bitRange>
            </field>
            <field>
              <name>CC4NP</name>
              <bitRange>[15:15]</bitRange>
            </field>
          </fields>
        </register>
        <register>
          <name>CNT</name>
          <addressOffset>0x24</addressOffset>
          <fields>
            <field>
              <name>CNT</name>
              <bitRange>[31:0]</bitRange>
            </field>
          </fields>
        </register>
        <register>
          <name>PSC</name>
          <addressOffset>0x28</addressOffset>
          <fields>
            <field>
              <name>PSC</name>
              <bitRange>[15:0]</bitRange>
            </field>
          </fields>
        </register>
        <register>
          <name>ARR</name>
          <addressOffset>0x2C</addressOffset>
          <fields>
            <field>
              <name>ARR</name>
              <bitRange>[31:0]</bitRange>
            </field>
          </fields>
        </register>
        <register>
          <name>CCR1</name>
          <addressOffset>0x34</addressOffset>
          <fields>
            <field>
              <name>CCR1</name>
              <bitRange>[31:0]</bitRange>
            </field>
          </fields>
        </register>
        <register>
          <name>CCR2</name>
          <addressOffset>0x38</addressOffset>
          <fields>
            <field>
              <name>CCR2</name>
              <bitRange>[31:0]</bitRange>
            </field>
          </fields>
        </register>
        <register>
          <name>CCR3</name>
          <addressOffset>0x3C</addressOffset>
          <fields>
            <field>
              <name>CCR3</name>
              <bitRange>[31:0]</bitRange>
            </field>
          </fields>
        </register>
        <register>
          <name>CCR4</name>
          <addressOffset>0x40</addressOffset>
          <fields>
            <field>
              <name>CCR4</name>
              <bitRange>[31:0]</bitRange>
            </field>
          </fields>
        </register>
        <register>
          <name>BDTR</name>
          <addressOffset>0x44</addressOffset>
          <fields>
            <field>
              <name>DTG</name>
              <bitRange>[7:0]</bitRange>
            </field>
            <field>
              <name>LOCK</name>
              <bitRange>[9:8]</bitRange>
            </field>
            <field>
              <name>OSSI</name>
              <bitRange>[10:10]</bitRange>
            </field>
            <field>
              <name>OSSR</name>
              <bitRange>[11:11]</bitRange>
            </field>
            <field>
              <name>BKE</name>
              <bitRange>[12:12]</bitRange>
            </field>
            <field>
              <name>BKP</name>
              <bitRange>[13:13]</bitRange>
            </field>
            <field>
              <name>AOE</name>
              <bitRange>[14:14]</bitRange>
            </field>
            <field>
              <name>MOE</name>
              <bitRange>[15:15]</bitRange>
            </field>
            <field>
              <name>BKF</name>
              <bitRange>[19:16]</bitRange>
            </field>
            <field>
              <name>BK2F</name>
              <bitRange>[23:20]</bitRange>
            </field>
            <field>
              <name>BK2E</name>
              <bitRange>[24:24]</bitRange>
            </field>
            <field>
              <name>BK2P</name>
              <bitRange>[25:25]</bitRange>
            </field>
            <field>
              <name>BKDSRM</name>
              <bitRange>[26:26]</bitRange>
            </field>
            <field>
              <name>BK2DSRM</name>
              <bitRange>[27:27]</bitRange>
            </field>
            <field>
              <name>BKBID</name>
              <bitRange>[28:28]</bitRange>
            </field>
            <field>
              <name>BK2BID</name>
              <bitRange>[29:29]</bitRange>
            </field>
          </fields>
        </register>
        <register>
          <name>DTR2</name>
          <addressOffset>0x54</addressOffset>
          <fields>
            <field>
              <name>DTGF</name>
              <bitRange>[7:0]</bitRange>
            </field>
            <field>
              <name>DTAE</name>
              <bitRange>[16:16]</bitRange>
            </field>
            <field>
              <name>DTPE</name>
              <bitRange>[17:17]</bitRange>
            </field>
          </fields>
        </register>
        <register>
          <name>TISEL</name>
          <addressOffset>0x5C</addressOffset>
          <fields>
            <field>
              <name>TI1SEL</name>
              <bitRange>[3:0]</bitRange>
            </field>
            <field>
              <name>TI2SEL</name>
              <bitRange>[11:8]</bitRange>
            </field>
            <field>
              <name>TI3SEL</name>
              <bitRange>[19:16]</bitRange>
            </field>
            <field>
              <name>TI4SEL</name>
              <bitRange>[27:24]</bitRange>
            </field>
          </fields>
        </register>
        <register>
          <name>AF1</name>
          <addressOffset>0x60</addressOffset>
          <fields>
            <field>
              <name>BKINE</name>
              <bitRange>[0:0]</bitRange>
            </field>
            <field>
              <name>BKCMP1E</name>
              <bitRange>[1:1]</bitRange>
            </field>
            <field>
              <name>BKCMP2E</name>
              <bitRange>[2:2]</bitRange>
            </field>
            <field>
              <name>BKCMP3E</name>
              <bitRange>[3:3]</bitRange>
            </field>
            <field>
              <name>BKCMP4E</name>
              <bitRange>[4:4]</bitRange>
            </field>
            <field>
              <name>BKINP</name>
              <bitRange>[9:9]</bitRange>
            </field>
            <field>
              <name>BKCMP1P</name>
              <bitRange>[10:10]</bitRange>
            </field>
            <field>
              <name>BKCMP2P</name>
              <bitRange>[11:11]</bitRange>
            </field>
            <field>
              <name>BKCMP3P</name>
              <bitRange>[12:12]</bitRange>
            </field>
            <field>
              <name>BKCMP4P</name>
              <bitRange>[13:13]</bitRange>
            </field>
            <field>
              <name>ETRSEL</name>
              <bitRange>[17:14]</bitRange>
            </field>
          </fields>
        </register>
        <register>
          <name>AF2</name>
          <addressOffset>0x64</addressOffset>
          <fields>
            <field>
              <name>BK2INE</name>
              <bitRange>[0:0]</bitRange>
            </field>
            <field>
              <name>BK2CMP1E</name>
              <bitRange>[1:1]</bitRange>
            </field>
            <field>
              <name>BK2CMP2E</name>
              <bitRange>[2:2]</bitRange>
            </field>
            <field>
              <name>BK2CMP3E</name>
              <bitRange>[3:3]</bitRange>
            </field>
            <field>
              <name>BK2CMP4E</name>
              <bitRange>[4:4]</bitRange>
            </field>
            <field>
              <name>BK2INP</name>
              <bitRange>[9:9]</bitRange>
            </field>
            <field>
              <name>BK2CMP1P</name>
              <bitRange>[10:10]</bitRange>
            </field>
            <field>
              <name>BK2CMP2P</name>
              <bitRange>[11:11]</bitRange>
            </field>
            <field>
              <name>BK2CMP3P</name>
              <bitRange>[12:12]</bitRange>
            </field>
            <field>
              <name>BK2CMP4P</name>
              <bitRange>[13:13]</bitRange>
            </field>
            <field>
              <name>OCRSEL</name>
              <bitRange>[18:16]</bitRange>
            </field>
          </fields>
        </register>
        <register>
          <name>MTADCCR</name>
          <addressOffset>0x6C</addressOffset>
          <fields>
            <field>
              <name>MTZEROE</name>
              <bitRange>[0:0]</bitRange>
            </field>
            <field>
              <name>MTARRE</name>
              <bitRange>[1:1]</bitRange>
            </field>
            <field>
              <name>UMTCCR1E</name>
              <bitRange>[2:2]</bitRange>
            </field>
            <field>
              <name>UMTCCR1HE</name>
              <bitRange>[3:3]</bitRange>
            </field>
            <field>
              <name>UMTCCR2E</name>
              <bitRange>[4:4]</bitRange>
            </field>
            <field>
              <name>UMTCCR2HE</name>
              <bitRange>[5:5]</bitRange>
            </field>
            <field>
              <name>UMTCCR3E</name>
              <bitRange>[6:6]</bitRange>
            </field>
            <field>
              <name>UMTCCR3HE</name>
              <bitRange>[7:7]</bitRange>
            </field>
            <field>
              <name>UMTCCR4E</name>
              <bitRange>[8:8]</bitRange>
            </field>
            <field>
              <name>UMTCCR4HE</name>
              <bitRange>[9:9]</bitRange>
            </field>
            <field>
              <name>DMTCCR1E</name>
              <bitRange>[10:10]</bitRange>
            </field>
            <field>
              <name>DMTCCR1HE</name>
              <bitRange>[11:11]</bitRange>
            </field>
            <field>
              <name>DMTCCR2E</name>
              <bitRange>[12:12]</bitRange>
            </field>
            <field>
              <name>DMTCCR2HE</name>
              <bitRange>[13:13]</bitRange>
            </field>
            <field>
              <name>DMTCCR3E</name>
              <bitRange>[14:14]</bitRange>
            </field>
            <field>
              <name>DMTCCR3HE</name>
              <bitRange>[15:15]</bitRange>
            </field>
            <field>
              <name>DMTCCR4E</name>
              <bitRange>[16:16]</bitRange>
            </field>
            <field>
              <name>DMTCCR4HE</name>
              <bitRange>[17:17]</bitRange>
            </field>
            <field>
              <name>MTADCE</name>
              <bitRange>[18:18]</bitRange>
            </field>
          </fields>
        </register>
        <register>
          <name>TIMXDCR</name>
          <addressOffset>0x3DC</addressOffset>
          <fields>
            <field>
              <name>DBA</name>
              <bitRange>[4:0]</bitRange>
            </field>
            <field>
              <name>DBL</name>
              <bitRange>[12:8]</bitRange>
            </field>
          </fields>
        </register>
        <register>
          <name>DMAR</name>
          <addressOffset>0x3E0</addressOffset>
          <fields>
            <field>
              <name>DMAB</name>
              <bitRange>[31:0]</bitRange>
            </field>
          </fields>
        </register>
      </registers>
    </peripheral>
    <peripheral derivedFrom="TIM2">
      <name>TIM3</name>
      <baseAddress>0x40000400</baseAddress>
      <interrupt>
        <name>TIM3</name>
        <description>TIM3 global Interrupt</description>
        <value>26</value>
      </interrupt>
    </peripheral>
    <peripheral>
      <name>TIM6</name>
      <groupName>TIM</groupName>
      <baseAddress>0x40001000</baseAddress>
      <addressBlock>
        <offset>0x0</offset>
        <size>0x30</size>
        <usage>registers</usage>
      </addressBlock>
      <interrupt>
        <name>TIM6</name>
        <description>TIM6 global Interrupt</description>
        <value>27</value>
      </interrupt>
      <registers>
        <register>
          <name>CR1</name>
          <addressOffset>0x0</addressOffset>
          <fields>
            <field>
              <name>CEN</name>
              <bitRange>[0:0]</bitRange>
            </field>
            <field>
              <name>UDIS</name>
              <bitRange>[1:1]</bitRange>
            </field>
            <field>
              <name>URS</name>
              <bitRange>[2:2]</bitRange>
            </field>
            <field>
              <name>OPM</name>
              <bitRange>[3:3]</bitRange>
            </field>
            <field>
              <name>ARPE</name>
              <bitRange>[7:7]</bitRange>
            </field>
          </fields>
        </register>
        <register>
          <name>CR2</name>
          <addressOffset>0x4</addressOffset>
          <fields>
            <field>
              <name>MMS</name>
              <bitRange>[6:4]</bitRange>
              <access>read-only</access>
            </field>
          </fields>
        </register>
        <register>
          <name>DIER</name>
          <addressOffset>0xC</addressOffset>
          <fields>
            <field>
              <name>UIE</name>
              <bitRange>[0:0]</bitRange>
            </field>
            <field>
              <name>UDE</name>
              <bitRange>[8:8]</bitRange>
            </field>
          </fields>
        </register>
        <register>
          <name>SR</name>
          <addressOffset>0x10</addressOffset>
          <fields>
            <field>
              <name>UIF</name>
              <bitRange>[0:0]</bitRange>
            </field>
          </fields>
        </register>
        <register>
          <name>EGR</name>
          <addressOffset>0x14</addressOffset>
          <fields>
            <field>
              <name>UG</name>
              <bitRange>[0:0]</bitRange>
              <access>read-only</access>
            </field>
          </fields>
        </register>
        <register>
          <name>CNT</name>
          <addressOffset>0x24</addressOffset>
          <fields>
            <field>
              <name>CNT</name>
              <bitRange>[15:0]</bitRange>
            </field>
          </fields>
        </register>
        <register>
          <name>PSC</name>
          <addressOffset>0x28</addressOffset>
          <fields>
            <field>
              <name>PSC</name>
              <bitRange>[15:0]</bitRange>
            </field>
          </fields>
        </register>
        <register>
          <name>ARR</name>
          <addressOffset>0x2C</addressOffset>
          <fields>
            <field>
              <name>ARR</name>
              <bitRange>[15:0]</bitRange>
            </field>
          </fields>
        </register>
      </registers>
    </peripheral>
    <peripheral derivedFrom="TIM6">
      <name>TIM7</name>
      <baseAddress>0x40001400</baseAddress>
      <interrupt>
        <name>TIM7</name>
        <description>TIM7 global Interrupt</description>
        <value>28</value>
      </interrupt>
    </peripheral>
    <peripheral derivedFrom="TIM1">
      <name>TIM8</name>
      <baseAddress>0x40013400</baseAddress>
      <interrupt>
        <name>TIM8_BRK</name>
        <description>TIM8 Break Interrupt global Interrupt</description>
        <value>29</value>
      </interrupt>
      <interrupt>
        <name>TIM8_UP</name>
        <description>TIM8 Update Interrupt global Interrupt</description>
        <value>30</value>
      </interrupt>
      <interrupt>
        <name>TIM8_TRG_COM</name>
        <description>TIM8 Trigger and Commutation Interrupt global interrupt</description>
        <value>31</value>
      </interrupt>
      <interrupt>
        <name>TIM8_CC</name>
        <description>TIM8 Capture Compare Interrupt</description>
        <value>32</value>
      </interrupt>
    </peripheral>
    <peripheral>
      <name>UART1</name>
      <groupName>UART</groupName>
      <baseAddress>0x40004C00</baseAddress>
      <addressBlock>
        <offset>0x0</offset>
        <size>0x30</size>
        <usage>registers</usage>
      </addressBlock>
      <interrupt>
        <name>UART1</name>
        <description>UART1 global Interrupt</description>
        <value>37</value>
      </interrupt>
      <registers>
        <register>
          <name>DR</name>
          <addressOffset>0x0</addressOffset>
          <fields>
            <field>
              <name>DR</name>
              <description>Receive/send data register</description>
              <bitRange>[8:0]</bitRange>
            </field>
          </fields>
        </register>
        <register>
          <name>BRR</name>
          <addressOffset>0x4</addressOffset>
          <fields>
            <field>
              <name>BRR</name>
              <description>Baud rate register</description>
              <bitRange>[15:0]</bitRange>
            </field>
          </fields>
        </register>
        <register>
          <name>SR</name>
          <addressOffset>0x10</addressOffset>
          <fields>
            <field>
              <name>RXNE</name>
              <description>Receive register not empty</description>
              <bitRange>[0:0]</bitRange>
              <access>read-only</access>
            </field>
            <field>
              <name>ORE</name>
              <description>Overrun error bit</description>
              <bitRange>[1:1]</bitRange>
            </field>
            <field>
              <name>PE</name>
              <description>Parity Error bit</description>
              <bitRange>[2:2]</bitRange>
            </field>
            <field>
              <name>FE</name>
              <description>Framing Error bit</description>
              <bitRange>[3:3]</bitRange>
            </field>
            <field>
              <name>BRI</name>
              <description>Break Interrupt bit</description>
              <bitRange>[4:4]</bitRange>
            </field>
            <field>
              <name>TDRE</name>
              <description>Transmit Holding Register Empty bit</description>
              <bitRange>[5:5]</bitRange>
              <access>read-only</access>
            </field>
            <field>
              <name>TXE</name>
              <description>Transmitter Empty bit</description>
              <bitRange>[6:6]</bitRange>
              <access>read-only</access>
            </field>
            <field>
              <name>ADDR_RCVD</name>
              <description>Address Received Bit</description>
              <bitRange>[8:8]</bitRange>
            </field>
            <field>
              <name>BUSY</name>
              <description>UART Busy</description>
              <bitRange>[9:9]</bitRange>
              <access>read-only</access>
            </field>
            <field>
              <name>BUSY_ERR</name>
              <description>Busy Detect Error</description>
              <bitRange>[10:10]</bitRange>
            </field>
          </fields>
        </register>
        <register>
          <name>CR1</name>
          <addressOffset>0x14</addressOffset>
          <fields>
            <field>
              <name>M</name>
              <description>Data Length Select</description>
              <bitRange>[1:0]</bitRange>
            </field>
            <field>
              <name>STOP</name>
              <description>Number of stop bits</description>
              <bitRange>[2:2]</bitRange>
            </field>
            <field>
              <name>PCE</name>
              <description>Parity Enable</description>
              <bitRange>[3:3]</bitRange>
            </field>
            <field>
              <name>PS</name>
              <description>Even Parity Select</description>
              <bitRange>[4:4]</bitRange>
            </field>
            <field>
              <name>SP</name>
              <description>Stick Parity</description>
              <bitRange>[5:5]</bitRange>
            </field>
            <field>
              <name>SBK</name>
              <description>Send Break</description>
              <bitRange>[6:6]</bitRange>
            </field>
            <field>
              <name>SWAP</name>
              <description>TX/RX pin swap</description>
              <bitRange>[8:8]</bitRange>
            </field>
            <field>
              <name>MSBFIRST</name>
              <description>MSB first mode</description>
              <bitRange>[9:9]</bitRange>
            </field>
          </fields>
        </register>
        <register>
          <name>CR2</name>
          <addressOffset>0x18</addressOffset>
          <fields>
            <field>
              <name>RXNEIE</name>
              <description>Enable Received Data Available Interrupt</description>
              <bitRange>[0:0]</bitRange>
            </field>
            <field>
              <name>TDREIE</name>
              <description>Enable Transmit Holding Register Empty Interrupt</description>
              <bitRange>[1:1]</bitRange>
            </field>
            <field>
              <name>LSIE</name>
              <description>Enable Receiver Line Status Interrupt</description>
              <bitRange>[2:2]</bitRange>
            </field>
            <field>
              <name>BUSYERRIE</name>
              <description>Enable Busyerr state interruption</description>
              <bitRange>[3:3]</bitRange>
            </field>
          </fields>
        </register>
        <register>
          <name>CR3</name>
          <addressOffset>0x1C</addressOffset>
          <fields>
            <field>
              <name>M_E</name>
              <description>Extension for DLS</description>
              <bitRange>[0:0]</bitRange>
            </field>
            <field>
              <name>ADDR_MATCH</name>
              <description>Address Match Mode</description>
              <bitRange>[1:1]</bitRange>
            </field>
            <field>
              <name>SEND_ADDR</name>
              <description>Send address control bit</description>
              <bitRange>[2:2]</bitRange>
            </field>
            <field>
              <name>TX_MODE</name>
              <description>Transmit mode control bit</description>
              <bitRange>[3:3]</bitRange>
            </field>
            <field>
              <name>DMAR</name>
              <description>DMA receive enable</description>
              <bitRange>[4:4]</bitRange>
            </field>
            <field>
              <name>DMAT</name>
              <description>DMA transmit enable</description>
              <bitRange>[5:5]</bitRange>
            </field>
            <field>
              <name>DMA_SOFT_ACK</name>
              <description>DMA software ack</description>
              <bitRange>[6:6]</bitRange>
            </field>
          </fields>
        </register>
        <register>
          <name>RAR</name>
          <addressOffset>0x20</addressOffset>
          <fields>
            <field>
              <name>RAR</name>
              <description>Receive address matching register</description>
              <bitRange>[7:0]</bitRange>
            </field>
          </fields>
        </register>
        <register>
          <name>TAR</name>
          <addressOffset>0x24</addressOffset>
          <fields>
            <field>
              <name>TAR</name>
              <description>Transmit address matching register</description>
              <bitRange>[7:0]</bitRange>
            </field>
          </fields>
        </register>
        <register>
          <name>BRRF</name>
          <addressOffset>0x28</addressOffset>
          <fields>
            <field>
              <name>BRRF</name>
              <description>Baud rate fractional register</description>
              <bitRange>[3:0]</bitRange>
            </field>
          </fields>
        </register>
      </registers>
    </peripheral>
    <peripheral derivedFrom="UART1">
      <name>UART2</name>
      <baseAddress>0x40005000</baseAddress>
      <interrupt>
        <name>UART2</name>
        <description>UART2 global Interrupt</description>
        <value>38</value>
      </interrupt>
    </peripheral>
    <peripheral>
      <name>USART</name>
      <baseAddress>0x40013800</baseAddress>
      <addressBlock>
        <offset>0x0</offset>
        <size>0x20</size>
        <usage>registers</usage>
      </addressBlock>
      <interrupt>
        <name>USART</name>
        <description>USART global Interrupt</description>
        <value>36</value>
      </interrupt>
      <registers>
        <register>
          <name>SR</name>
          <addressOffset>0x0</addressOffset>
          <fields>
            <field>
              <name>PE</name>
              <bitRange>[0:0]</bitRange>
              <access>read-only</access>
            </field>
            <field>
              <name>FE</name>
              <bitRange>[1:1]</bitRange>
              <access>read-only</access>
            </field>
            <field>
              <name>NE</name>
              <bitRange>[2:2]</bitRange>
              <access>read-only</access>
            </field>
            <field>
              <name>ORE</name>
              <bitRange>[3:3]</bitRange>
              <access>read-only</access>
            </field>
            <field>
              <name>IDLE</name>
              <bitRange>[4:4]</bitRange>
              <access>read-only</access>
            </field>
            <field>
              <name>RXNE</name>
              <bitRange>[5:5]</bitRange>
            </field>
            <field>
              <name>TC</name>
              <bitRange>[6:6]</bitRange>
            </field>
            <field>
              <name>TXE</name>
              <bitRange>[7:7]</bitRange>
              <access>read-only</access>
            </field>
            <field>
              <name>LBD</name>
              <bitRange>[8:8]</bitRange>
            </field>
            <field>
              <name>CTS</name>
              <bitRange>[9:9]</bitRange>
            </field>
            <field>
              <name>ABRF</name>
              <bitRange>[10:10]</bitRange>
              <access>read-only</access>
            </field>
            <field>
              <name>ABRE</name>
              <bitRange>[11:11]</bitRange>
              <access>read-only</access>
            </field>
            <field>
              <name>ABRRQ</name>
              <bitRange>[12:12]</bitRange>
              <access>write-only</access>
            </field>
            <field>
              <name>TXFT</name>
              <bitRange>[13:13]</bitRange>
              <access>read-only</access>
            </field>
            <field>
              <name>RXFT</name>
              <bitRange>[14:14]</bitRange>
              <access>read-only</access>
            </field>
            <field>
              <name>RXFF</name>
              <bitRange>[15:15]</bitRange>
              <access>read-only</access>
            </field>
            <field>
              <name>TXFE</name>
              <bitRange>[16:16]</bitRange>
              <access>read-only</access>
            </field>
            <field>
              <name>EOBF</name>
              <bitRange>[18:18]</bitRange>
            </field>
            <field>
              <name>RTOF</name>
              <bitRange>[19:19]</bitRange>
            </field>
            <field>
              <name>TXPE</name>
              <bitRange>[20:20]</bitRange>
            </field>
            <field>
              <name>RXBUSY</name>
              <bitRange>[21:21]</bitRange>
              <access>read-only</access>
            </field>
            <field>
              <name>TXBUSY</name>
              <bitRange>[22:22]</bitRange>
              <access>read-only</access>
            </field>
            <field>
              <name>WAIT_RPT</name>
              <bitRange>[23:23]</bitRange>
              <access>read-only</access>
            </field>
          </fields>
        </register>
        <register>
          <name>DR</name>
          <addressOffset>0x4</addressOffset>
          <fields>
            <field>
              <name>DR</name>
              <bitRange>[8:0]</bitRange>
            </field>
          </fields>
        </register>
        <register>
          <name>BRR</name>
          <addressOffset>0x8</addressOffset>
          <fields>
            <field>
              <name>DIV_FRA</name>
              <bitRange>[3:0]</bitRange>
            </field>
            <field>
              <name>DIV_MAN</name>
              <bitRange>[15:4]</bitRange>
            </field>
          </fields>
        </register>
        <register>
          <name>CR1</name>
          <addressOffset>0xC</addressOffset>
          <fields>
            <field>
              <name>SBK</name>
              <bitRange>[0:0]</bitRange>
            </field>
            <field>
              <name>RWU</name>
              <bitRange>[1:1]</bitRange>
            </field>
            <field>
              <name>RE</name>
              <bitRange>[2:2]</bitRange>
            </field>
            <field>
              <name>TE</name>
              <bitRange>[3:3]</bitRange>
            </field>
            <field>
              <name>IDLEIE</name>
              <bitRange>[4:4]</bitRange>
            </field>
            <field>
              <name>RXNEIE</name>
              <bitRange>[5:5]</bitRange>
            </field>
            <field>
              <name>TCIE</name>
              <bitRange>[6:6]</bitRange>
            </field>
            <field>
              <name>TXEIE</name>
              <bitRange>[7:7]</bitRange>
            </field>
            <field>
              <name>PEIE</name>
              <bitRange>[8:8]</bitRange>
            </field>
            <field>
              <name>PS</name>
              <bitRange>[9:9]</bitRange>
            </field>
            <field>
              <name>PCE</name>
              <bitRange>[10:10]</bitRange>
            </field>
            <field>
              <name>WAKE</name>
              <bitRange>[11:11]</bitRange>
            </field>
            <field>
              <name>M0</name>
              <bitRange>[12:12]</bitRange>
            </field>
            <field>
              <name>UE</name>
              <bitRange>[13:13]</bitRange>
            </field>
            <field>
              <name>M1</name>
              <bitRange>[14:14]</bitRange>
            </field>
            <field>
              <name>MSB</name>
              <bitRange>[15:15]</bitRange>
            </field>
            <field>
              <name>ADDM7</name>
              <bitRange>[17:17]</bitRange>
            </field>
            <field>
              <name>SWAP</name>
              <bitRange>[18:18]</bitRange>
            </field>
            <field>
              <name>TXFTCFG</name>
              <bitRange>[21:19]</bitRange>
            </field>
            <field>
              <name>RXFTCFG</name>
              <bitRange>[24:22]</bitRange>
            </field>
            <field>
              <name>RX_INV</name>
              <bitRange>[25:25]</bitRange>
            </field>
            <field>
              <name>TX_INV</name>
              <bitRange>[26:26]</bitRange>
            </field>
            <field>
              <name>DATA_INV</name>
              <bitRange>[27:27]</bitRange>
            </field>
            <field>
              <name>ONEBIT</name>
              <bitRange>[28:28]</bitRange>
            </field>
            <field>
              <name>RXFRQ</name>
              <bitRange>[29:29]</bitRange>
              <access>write-only</access>
            </field>
            <field>
              <name>TXFRQ</name>
              <bitRange>[30:30]</bitRange>
              <access>write-only</access>
            </field>
            <field>
              <name>FIFOEN</name>
              <bitRange>[31:31]</bitRange>
            </field>
          </fields>
        </register>
        <register>
          <name>CR2</name>
          <addressOffset>0x10</addressOffset>
          <fields>
            <field>
              <name>LBDL</name>
              <bitRange>[5:5]</bitRange>
            </field>
            <field>
              <name>LBDIE</name>
              <bitRange>[6:6]</bitRange>
            </field>
            <field>
              <name>LBCL</name>
              <bitRange>[8:8]</bitRange>
            </field>
            <field>
              <name>CPHA</name>
              <bitRange>[9:9]</bitRange>
            </field>
            <field>
              <name>CPOL</name>
              <bitRange>[10:10]</bitRange>
            </field>
            <field>
              <name>CLKEN</name>
              <bitRange>[11:11]</bitRange>
            </field>
            <field>
              <name>STOP</name>
              <bitRange>[13:12]</bitRange>
            </field>
            <field>
              <name>LINEN</name>
              <bitRange>[14:14]</bitRange>
            </field>
            <field>
              <name>ADD</name>
              <bitRange>[22:15]</bitRange>
            </field>
            <field>
              <name>DEM</name>
              <bitRange>[23:23]</bitRange>
            </field>
            <field>
              <name>DEP</name>
              <bitRange>[24:24]</bitRange>
            </field>
            <field>
              <name>RTOEN</name>
              <bitRange>[25:25]</bitRange>
            </field>
            <field>
              <name>ERSW</name>
              <bitRange>[27:26]</bitRange>
            </field>
            <field>
              <name>REP_T</name>
              <bitRange>[28:28]</bitRange>
            </field>
            <field>
              <name>TREPEN</name>
              <bitRange>[29:29]</bitRange>
            </field>
            <field>
              <name>RREPEN</name>
              <bitRange>[30:30]</bitRange>
            </field>
          </fields>
        </register>
        <register>
          <name>CR3</name>
          <addressOffset>0x14</addressOffset>
          <fields>
            <field>
              <name>EIE</name>
              <bitRange>[0:0]</bitRange>
            </field>
            <field>
              <name>IREN</name>
              <bitRange>[1:1]</bitRange>
            </field>
            <field>
              <name>IRLP</name>
              <bitRange>[2:2]</bitRange>
            </field>
            <field>
              <name>HDSEL</name>
              <bitRange>[3:3]</bitRange>
            </field>
            <field>
              <name>NACK</name>
              <bitRange>[4:4]</bitRange>
            </field>
            <field>
              <name>SCEN</name>
              <bitRange>[5:5]</bitRange>
            </field>
            <field>
              <name>DMAR</name>
              <bitRange>[6:6]</bitRange>
            </field>
            <field>
              <name>DMAT</name>
              <bitRange>[7:7]</bitRange>
            </field>
            <field>
              <name>RTSE</name>
              <bitRange>[8:8]</bitRange>
            </field>
            <field>
              <name>CTSE</name>
              <bitRange>[9:9]</bitRange>
            </field>
            <field>
              <name>CTSIE</name>
              <bitRange>[10:10]</bitRange>
            </field>
            <field>
              <name>OVER8</name>
              <bitRange>[11:11]</bitRange>
            </field>
            <field>
              <name>ABREN</name>
              <bitRange>[12:12]</bitRange>
            </field>
            <field>
              <name>ABRMOD</name>
              <bitRange>[14:13]</bitRange>
            </field>
            <field>
              <name>RXFFIE</name>
              <bitRange>[15:15]</bitRange>
            </field>
            <field>
              <name>TXFEIE</name>
              <bitRange>[16:16]</bitRange>
            </field>
            <field>
              <name>RXFTIE</name>
              <bitRange>[17:17]</bitRange>
            </field>
            <field>
              <name>TXFTIE</name>
              <bitRange>[18:18]</bitRange>
            </field>
            <field>
              <name>DEDT</name>
              <bitRange>[23:19]</bitRange>
            </field>
            <field>
              <name>DEAT</name>
              <bitRange>[28:24]</bitRange>
            </field>
            <field>
              <name>RTOIE</name>
              <bitRange>[29:29]</bitRange>
            </field>
            <field>
              <name>EOBIE</name>
              <bitRange>[30:30]</bitRange>
            </field>
          </fields>
        </register>
        <register>
          <name>GTPR</name>
          <addressOffset>0x18</addressOffset>
          <fields>
            <field>
              <name>PSC</name>
              <bitRange>[7:0]</bitRange>
            </field>
            <field>
              <name>GT</name>
              <bitRange>[15:8]</bitRange>
            </field>
          </fields>
        </register>
        <register>
          <name>RTOR</name>
          <addressOffset>0x1C</addressOffset>
          <fields>
            <field>
              <name>RTO</name>
              <bitRange>[23:0]</bitRange>
            </field>
            <field>
              <name>BLEN</name>
              <bitRange>[31:24]</bitRange>
            </field>
          </fields>
        </register>
      </registers>
    </peripheral>
    <peripheral>
      <name>VREFBUF</name>
      <baseAddress>0x40012000</baseAddress>
      <addressBlock>
        <offset>0x0</offset>
        <size>0x10</size>
        <usage>registers</usage>
      </addressBlock>
      <registers>
        <register>
          <name>CR</name>
          <addressOffset>0x0</addressOffset>
          <fields>
            <field>
              <name>VREFBUFEN</name>
              <bitRange>[0:0]</bitRange>
            </field>
            <field>
              <name>VREFBUFSEL</name>
              <bitRange>[3:1]</bitRange>
            </field>
          </fields>
        </register>
      </registers>
    </peripheral>
    <peripheral>
      <name>WWDG</name>
      <baseAddress>0x40002C00</baseAddress>
      <addressBlock>
        <offset>0x0</offset>
        <size>0x10</size>
        <usage>registers</usage>
      </addressBlock>
      <interrupt>
        <name>WWDG</name>
        <description>Window WatchDog global Interrupt</description>
        <value>0</value>
      </interrupt>
      <registers>
        <register>
          <name>WWDR_CR</name>
          <addressOffset>0x0</addressOffset>
          <fields>
            <field>
              <name>T</name>
              <description>wwdg counter</description>
              <bitRange>[6:0]</bitRange>
            </field>
            <field>
              <name>WDGA</name>
              <description>WWDG Activation</description>
              <bitRange>[7:7]</bitRange>
            </field>
          </fields>
        </register>
        <register>
          <name>CFR</name>
          <addressOffset>0x4</addressOffset>
          <fields>
            <field>
              <name>W</name>
              <description>window value</description>
              <bitRange>[6:0]</bitRange>
            </field>
            <field>
              <name>WDGTB</name>
              <description>time base</description>
              <bitRange>[8:7]</bitRange>
            </field>
            <field>
              <name>EWI</name>
              <description>Early wakeup interrupt</description>
              <bitRange>[9:9]</bitRange>
            </field>
          </fields>
        </register>
        <register>
          <name>SR</name>
          <addressOffset>0x8</addressOffset>
          <size>16</size>
          <fields>
            <field>
              <name>EWIF</name>
              <description>Early wakeup interrupt flag</description>
              <bitRange>[0:0]</bitRange>
            </field>
          </fields>
        </register>
      </registers>
    </peripheral>
  </peripherals>
</device>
